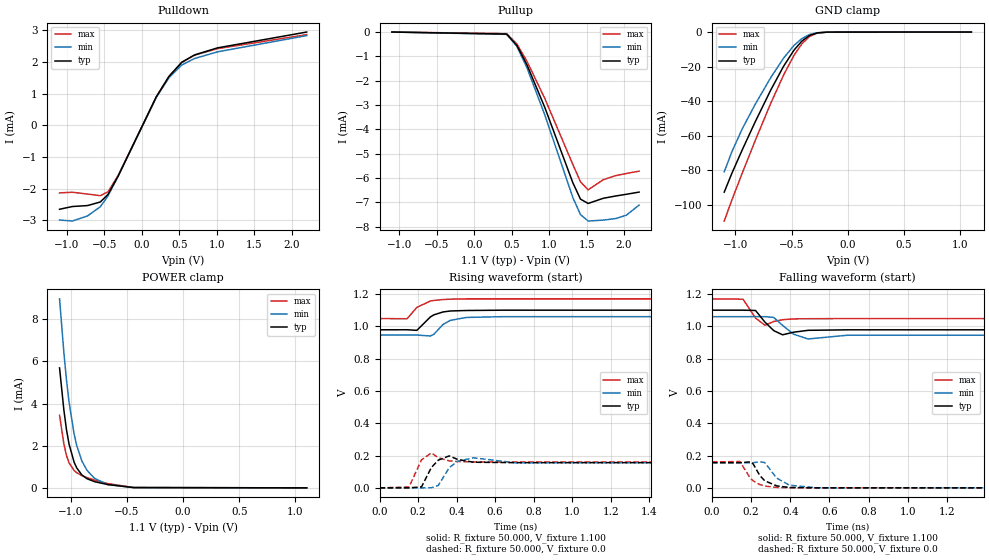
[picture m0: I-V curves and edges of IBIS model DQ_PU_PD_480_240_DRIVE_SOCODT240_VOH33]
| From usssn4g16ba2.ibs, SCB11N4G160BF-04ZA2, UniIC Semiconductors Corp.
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|   Model DQ_PU_PD_480_240_DRIVE_SOCODT240_VOH33
[Model] DQ_PU_PD_480_240_DRIVE_SOCODT240_VOH33
Model_type I/O
Polarity   Inverting
Vinl =  98.000mV
Vinh =  0.268V
Vmeas =  0.183V
Rref =  50.000
Vref =  0.183V
C_comp   1.020pF   1.010pF   1.030pF
[Model Spec]
Vinh   0.268V   0.262V   0.280V
Vinl   98.000mV   92.000mV   0.110V
Vmeas   0.183V   0.177V   0.195V
Vref   0.183V   0.177V   0.195V
Rref   50.000   NA   NA
[Temperature Range]   25.000   0.105k   -40.000
[Voltage Range]   1.100V   1.060V   1.170V
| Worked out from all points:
|   slope of the pulldown table from 0 to 0.165 V, typ, clamps not added: 211 ohm
|   GND clamp passes 1 mA (typ) near -0.30 V on its own axis
|   POWER clamp passes 1 mA (typ) near -0.95 V on its own axis
|   rising waveform, R_fixture 50.000, V_fixture 1.100: 20-80 % time 70ps typ, 72.2ps min, 68.1ps max; typ from 0.978 V to 1.1 V
|   rising waveform, R_fixture 50.000, V_fixture 0.0: 20-80 % time 37ps typ, 47ps min, 30.1ps max; typ from 0 V to 0.156 V
|   falling waveform, R_fixture 50.000, V_fixture 1.100: 20-80 % time 45.4ps typ, 59.1ps min, 35.5ps max; typ from 1.1 V to 0.978 V
|   falling waveform, R_fixture 50.000, V_fixture 0.0: 20-80 % time 63.3ps typ, 70.7ps min, 60.6ps max; typ from 0.156 V to 0 V
[Pulldown]
|Voltage   I(typ)   I(min)   I(max)
-1.1V     -2.652mA   -2.992mA   -2.134mA
-930mV    -2.565mA   -3.023mA   -2.114mA
-726mV    -2.535mA   -2.862mA   -2.171mA
-556mV    -2.422mA   -2.572mA   -2.223mA
-454mV    -2.185mA   -2.234mA   -2.101mA
-318mV    -1.604mA   -1.606mA   -1.589mA
192mV     900.6uA    884.3uA    903.8uA
362mV     1.549mA    1.507mA    1.549mA
532mV     1.993mA    1.907mA    1.988mA
702mV     2.225mA    2.111mA    2.215mA
1.008V    2.447mA    2.322mA    2.422mA
2.2V      2.948mA    2.835mA    2.866mA
[Pullup]
|Voltage   I(typ)   I(min)   I(max)
-1.1V     500pA      5.412nA    0A
432mV     -84.42uA   -95.4uA    -65.89uA
568mV     -546.4uA   -585.3uA   -487.9uA
704mV     -1.354mA   -1.473mA   -1.207mA
942mV     -3.104mA   -3.412mA   -2.737mA
1.316V    -6.198mA   -6.807mA   -5.446mA
1.418V    -6.872mA   -7.507mA   -6.161mA
1.52V     -7.049mA   -7.771mA   -6.489mA
1.724V    -6.835mA   -7.734mA   -6.072mA
1.894V    -6.739mA   -7.667mA   -5.9mA
2.03V     -6.672mA   -7.532mA   -5.816mA
2.2V      -6.582mA   -7.117mA   -5.721mA
[GND_clamp]
|Voltage   I(typ)   I(min)   I(max)
-1.1V     -92.78mA   -81.05mA   -109.5mA
-1.031V   -81.73mA   -69.22mA   -97.17mA
-939mV    -68.18mA   -56.02mA   -81.64mA
-824mV    -52mA      -41.83mA   -62.83mA
-686mV    -33.62mA   -26.41mA   -41.32mA
-571mV    -19.76mA   -15.06mA   -24.85mA
-479mV    -10.5mA    -7.76mA    -13.5mA
-410mV    -5.313mA   -3.84mA    -6.916mA
-341mV    -2.007mA   -1.45mA    -2.59mA
-272mV    -506.9uA   -403.5uA   -609.8uA
-180mV    -45.65uA   -51.35uA   -43.55uA
1.1V      0A         0A         0A
[POWER_clamp]
|Voltage   I(typ)   I(min)   I(max)
-1.1V     5.691mA    8.967mA    3.44mA
-1.062V   3.709mA    6.444mA    2.092mA
-1.039V   2.781mA    5.152mA    1.546mA
-1.016V   2.086mA    4.085mA    1.193mA
-970mV    1.21mA     2.539mA    818.5uA
-947mV    943.7uA    2.005mA    716.7uA
-901mV    610.1uA    1.27mA     581.3uA
-855mV    430.7uA    824.1uA    484.6uA
-786mV    289.9uA    439.4uA    366uA
-671mV    155.9uA    155.9uA    203.6uA
-441mV    13.2uA     12.79uA    15.03uA
1.1V      0A         0A         0A
[Ramp]
| variable   typ   min   max
dV/dt_r   93.599m/37.161p   92.823m/47.081p   96.210m/30.054p
dV/dt_f   72.903m/45.492p   68.572m/59.110p   73.268m/35.541p
R_load = 50.000
[Rising Waveform]
R_fixture= 50.000
V_fixture= 1.100
V_fixture_min= 1.060
V_fixture_max= 1.170
|time   V(typ)   V(min)   V(max)
0s        978.5mV    945.7mV    1.048V
143ps     978.8mV    945.9mV    1.047V
194ps     975.1mV    946mV      1.117V
264ps     1.058V     940.1mV    1.157V
282ps     1.071V     950.5mV    1.16V
330ps     1.089V     1.012V     1.166V
368ps     1.095V     1.037V     1.168V
451ps     1.098V     1.055V     1.17V
646ps     1.1V       1.06V      1.17V
3ns       1.1V       1.06V      1.17V
[Rising Waveform]
R_fixture= 50.000
V_fixture= 0.0
V_fixture_min= 0.0
V_fixture_max= 0.0
|time   V(typ)   V(min)   V(max)
0s        5.235uV    19.06uV    1.24uV
153ps     -29.13uV   44.17uV    4.946mV
218ps     6.141mV    -7.246uV   173.5mV
269ps     125.5mV    451.2uV    216.1mV
305ps     171.5mV    14.89mV    186.4mV
362ps     197.8mV    124.6mV    167mV
405ps     176.1mV    164.3mV    162.7mV
488ps     158.6mV    186mV      160.7mV
706ps     156mV      155mV      160.3mV
3ns       156mV      154.7mV    160.3mV
[Falling Waveform]
R_fixture= 50.000
V_fixture= 1.100
V_fixture_min= 1.060
V_fixture_max= 1.170
|time   V(typ)   V(min)   V(max)
0s        1.1V       1.06V      1.17V
159ps     1.1V       1.06V      1.168V
223ps     1.098V     1.06V      1.051V
271ps     1.026V     1.06V      1.007V
316ps     973.3mV    1.055V     1.03V
361ps     947.5mV    1.006V     1.041V
417ps     963.5mV    951.4mV    1.046V
491ps     975.3mV    921.7mV    1.047V
694ps     978.4mV    945.1mV    1.048V
3ns       978.5mV    945.7mV    1.048V
[Falling Waveform]
R_fixture= 50.000
V_fixture= 0.0
V_fixture_min= 0.0
V_fixture_max= 0.0
|time   V(typ)   V(min)   V(max)
0s        156mV      154.7mV    160.3mV
143ps     155.8mV    154.5mV    163mV
196ps     160.8mV    154.6mV    60.66mV
211ps     147.8mV    155.8mV    43.18mV
245ps     75.97mV    161.5mV    20.16mV
270ps     43.85mV    156.5mV    10.98mV
331ps     12.16mV    60.34mV    2.493mV
396ps     2.224mV    16.43mV    620.7uV
535ps     135.6uV    482.5uV    32.23uV
3ns       5.266uV    19.16uV    -96.73nV
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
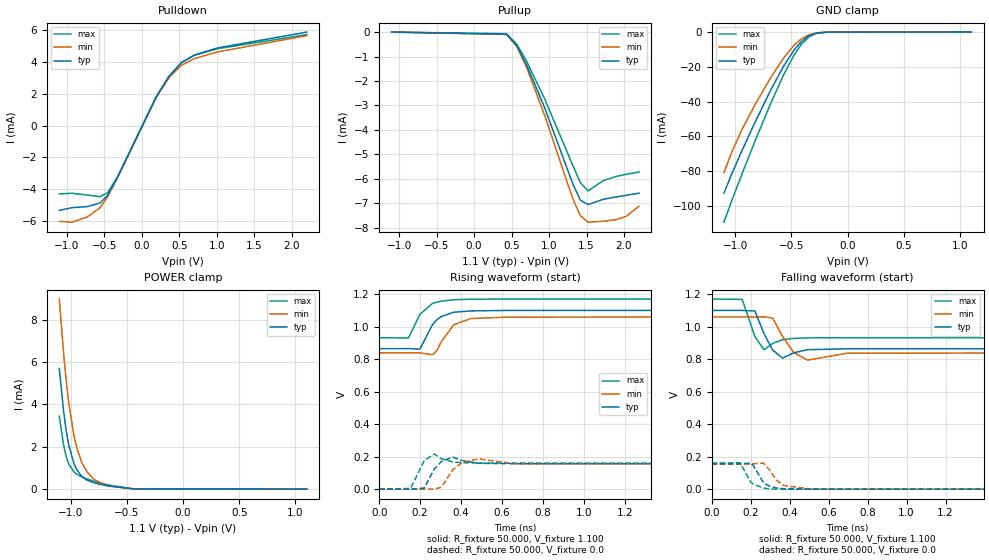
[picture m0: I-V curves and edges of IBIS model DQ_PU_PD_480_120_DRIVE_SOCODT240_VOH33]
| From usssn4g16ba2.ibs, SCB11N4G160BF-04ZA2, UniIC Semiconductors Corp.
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|   Model DQ_PU_PD_480_120_DRIVE_SOCODT240_VOH33
[Model] DQ_PU_PD_480_120_DRIVE_SOCODT240_VOH33
Model_type I/O
Polarity   Inverting
Vinl =  98.000mV
Vinh =  0.268V
Vmeas =  0.183V
Rref =  50.000
Vref =  0.183V
C_comp   1.020pF   1.010pF   1.030pF
[Model Spec]
Vinh   0.268V   0.262V   0.280V
Vinl   98.000mV   92.000mV   0.110V
Vmeas   0.183V   0.177V   0.195V
Vref   0.183V   0.177V   0.195V
Rref   50.000   NA   NA
[Temperature Range]   25.000   0.105k   -40.000
[Voltage Range]   1.100V   1.060V   1.170V
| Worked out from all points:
|   slope of the pulldown table from 0 to 0.165 V, typ, clamps not added: 105 ohm
|   GND clamp passes 1 mA (typ) near -0.30 V on its own axis
|   POWER clamp passes 1 mA (typ) near -0.95 V on its own axis
|   rising waveform, R_fixture 50.000, V_fixture 1.100: 20-80 % time 70.9ps typ, 74ps min, 68.7ps max; typ from 0.864 V to 1.1 V
|   rising waveform, R_fixture 50.000, V_fixture 0.0: 20-80 % time 36.7ps typ, 46.4ps min, 29.9ps max; typ from 0 V to 0.156 V
|   falling waveform, R_fixture 50.000, V_fixture 1.100: 20-80 % time 44.8ps typ, 58.1ps min, 35.2ps max; typ from 1.1 V to 0.864 V
|   falling waveform, R_fixture 50.000, V_fixture 0.0: 20-80 % time 52.5ps typ, 62.1ps min, 49.6ps max; typ from 0.156 V to 0 V
[Pulldown]
|Voltage   I(typ)   I(min)   I(max)
-1.1V     -5.34mA    -6.026mA   -4.302mA
-930mV    -5.164mA   -6.082mA   -4.26mA
-726mV    -5.101mA   -5.754mA   -4.373mA
-556mV    -4.87mA    -5.165mA   -4.475mA
-454mV    -4.386mA   -4.479mA   -4.222mA
-318mV    -3.209mA   -3.211mA   -3.18mA
192mV     1.799mA    1.766mA    1.806mA
362mV     3.096mA    3.011mA    3.096mA
532mV     3.983mA    3.811mA    3.973mA
702mV     4.448mA    4.219mA    4.427mA
1.008V    4.891mA    4.64mA     4.842mA
2.2V      5.891mA    5.665mA    5.73mA
[Pullup]
|Voltage   I(typ)   I(min)   I(max)
-1.1V     500pA      5.412nA    0A
432mV     -84.42uA   -95.4uA    -65.89uA
568mV     -546.4uA   -585.3uA   -487.9uA
704mV     -1.354mA   -1.473mA   -1.207mA
942mV     -3.104mA   -3.412mA   -2.737mA
1.316V    -6.198mA   -6.807mA   -5.446mA
1.418V    -6.872mA   -7.507mA   -6.161mA
1.52V     -7.049mA   -7.771mA   -6.489mA
1.724V    -6.835mA   -7.734mA   -6.072mA
1.894V    -6.739mA   -7.667mA   -5.9mA
2.03V     -6.672mA   -7.532mA   -5.816mA
2.2V      -6.582mA   -7.117mA   -5.721mA
[GND_clamp]
|Voltage   I(typ)   I(min)   I(max)
-1.1V     -92.78mA   -81.05mA   -109.5mA
-1.031V   -81.73mA   -69.22mA   -97.17mA
-939mV    -68.18mA   -56.02mA   -81.64mA
-824mV    -52mA      -41.83mA   -62.83mA
-686mV    -33.62mA   -26.41mA   -41.32mA
-571mV    -19.76mA   -15.06mA   -24.85mA
-479mV    -10.5mA    -7.76mA    -13.5mA
-410mV    -5.313mA   -3.84mA    -6.916mA
-341mV    -2.007mA   -1.45mA    -2.59mA
-272mV    -506.9uA   -403.5uA   -609.8uA
-180mV    -45.65uA   -51.35uA   -43.55uA
1.1V      0A         0A         0A
[POWER_clamp]
|Voltage   I(typ)   I(min)   I(max)
-1.1V     5.691mA    8.967mA    3.44mA
-1.062V   3.709mA    6.444mA    2.092mA
-1.039V   2.781mA    5.152mA    1.546mA
-1.016V   2.086mA    4.085mA    1.193mA
-970mV    1.21mA     2.539mA    818.5uA
-947mV    943.7uA    2.005mA    716.7uA
-901mV    610.1uA    1.27mA     581.3uA
-855mV    430.7uA    824.1uA    484.6uA
-786mV    289.9uA    439.4uA    366uA
-671mV    155.9uA    155.9uA    203.6uA
-441mV    13.2uA     12.79uA    15.03uA
1.1V      0A         0A         0A
[Ramp]
| variable   typ   min   max
dV/dt_r   93.600m/36.700p   92.825m/46.456p   96.210m/29.924p
dV/dt_f   0.141/44.746p   0.133/58.103p   0.143/35.264p
R_load = 50.000
[Rising Waveform]
R_fixture= 50.000
V_fixture= 1.100
V_fixture_min= 1.060
V_fixture_max= 1.170
|time   V(typ)   V(min)   V(max)
0s        864.4mV    838.5mV    932.1mV
143ps     864.9mV    838.7mV    930.5mV
199ps     862mV      838.6mV    1.076V
260ps     1.012V     827.4mV    1.143V
281ps     1.042V     851mV      1.151V
302ps     1.062V     904.9mV    1.157V
364ps     1.089V     1.012V     1.166V
447ps     1.097V     1.05V      1.169V
627ps     1.1V       1.059V     1.17V
3ns       1.1V       1.06V      1.17V
[Rising Waveform]
R_fixture= 50.000
V_fixture= 0.0
V_fixture_min= 0.0
V_fixture_max= 0.0
|time   V(typ)   V(min)   V(max)
0s        4.356uV    15.89uV    1.031uV
153ps     73.44uV    34.03uV    3.762mV
220ps     6.132mV    153.6uV    175.7mV
269ps     124mV      -471.6uV   215.9mV
305ps     171.1mV    12.11mV    186.4mV
359ps     197.2mV    118.7mV    167.4mV
406ps     175.5mV    164.5mV    162.7mV
486ps     158.8mV    185.8mV    160.7mV
665ps     156mV      155.4mV    160.4mV
3ns       156mV      154.7mV    160.3mV
[Falling Waveform]
R_fixture= 50.000
V_fixture= 1.100
V_fixture_min= 1.060
V_fixture_max= 1.170
|time   V(typ)   V(min)   V(max)
0s        1.1V       1.06V      1.17V
157ps     1.1V       1.06V      1.168V
222ps     1.097V     1.06V      939.9mV
269ps     957.1mV    1.061V     857.6mV
314ps     855.8mV    1.052V     897.3mV
364ps     806.5mV    940.4mV    919.5mV
421ps     839.3mV    841.3mV    928.1mV
492ps     858.3mV    794.1mV    931.2mV
698ps     864.3mV    837.3mV    932.1mV
3ns       864.4mV    838.5mV    932.1mV
[Falling Waveform]
R_fixture= 50.000
V_fixture= 0.0
V_fixture_min= 0.0
V_fixture_max= 0.0
|time   V(typ)   V(min)   V(max)
0s        156mV      154.7mV    160.3mV
146ps     155.8mV    154.5mV    162.6mV
200ps     160.4mV    154.8mV    45.79mV
215ps     143.5mV    156.2mV    30.14mV
266ps     39.97mV    160mV      6.797mV
297ps     18.06mV    119.2mV    975.6uV
331ps     7.774mV    57.5mV     415.2uV
369ps     2.426mV    22.99mV    167.1uV
515ps     -10.66uV   -75.85uV   5.185uV
3ns       4.126uV    15.81uV    991.6nV
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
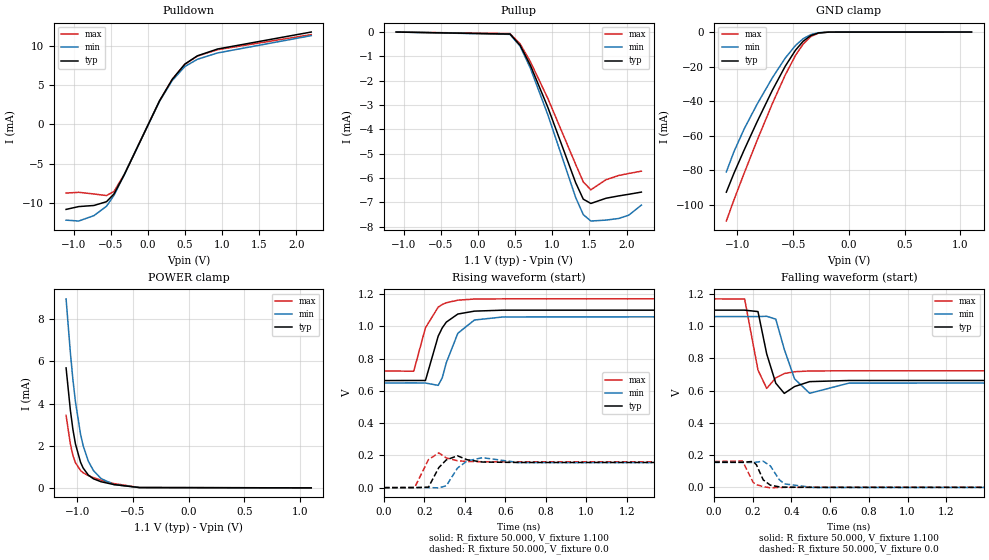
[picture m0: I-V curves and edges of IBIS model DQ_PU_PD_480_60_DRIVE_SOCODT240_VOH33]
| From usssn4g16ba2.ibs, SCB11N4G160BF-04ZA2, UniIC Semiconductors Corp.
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|   Model DQ_PU_PD_480_60_DRIVE_SOCODT240_VOH33
[Model] DQ_PU_PD_480_60_DRIVE_SOCODT240_VOH33
Model_type I/O
Polarity   Inverting
Vinl =  98.000mV
Vinh =  0.268V
Vmeas =  0.183V
Rref =  50.000
Vref =  0.183V
C_comp   1.020pF   1.010pF   1.030pF
[Model Spec]
Vinh   0.268V   0.262V   0.280V
Vinl   98.000mV   92.000mV   0.110V
Vmeas   0.183V   0.177V   0.195V
Vref   0.183V   0.177V   0.195V
Rref   50.000   NA   NA
[Temperature Range]   25.000   0.105k   -40.000
[Voltage Range]   1.100V   1.060V   1.170V
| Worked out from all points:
|   slope of the pulldown table from 0 to 0.165 V, typ, clamps not added: 52.7 ohm
|   GND clamp passes 1 mA (typ) near -0.30 V on its own axis
|   POWER clamp passes 1 mA (typ) near -0.95 V on its own axis
|   rising waveform, R_fixture 50.000, V_fixture 1.100: 20-80 % time 74.3ps typ, 78.1ps min, 71.5ps max; typ from 0.663 V to 1.1 V
|   rising waveform, R_fixture 50.000, V_fixture 0.0: 20-80 % time 36.5ps typ, 45.9ps min, 30ps max; typ from 0 V to 0.156 V
|   falling waveform, R_fixture 50.000, V_fixture 1.100: 20-80 % time 43.7ps typ, 56.9ps min, 35ps max; typ from 1.1 V to 0.663 V
|   falling waveform, R_fixture 50.000, V_fixture 0.0: 20-80 % time 40.7ps typ, 54.3ps min, 37.6ps max; typ from 0.156 V to 0 V
[Pulldown]
|Voltage   I(typ)   I(min)   I(max)
-1.1V     -10.83mA   -12.2mA    -8.746mA
-930mV    -10.47mA   -12.31mA   -8.649mA
-726mV    -10.33mA   -11.63mA   -8.863mA
-556mV    -9.849mA   -10.43mA   -9.063mA
-454mV    -8.849mA   -9.016mA   -8.534mA
-318mV    -6.436mA   -6.433mA   -6.383mA
158mV     3.005mA    2.954mA    3.019mA
328mV     5.729mA    5.586mA    5.734mA
498mV     7.686mA    7.379mA    7.672mA
668mV     8.751mA    8.306mA    8.715mA
940mV     9.618mA    9.116mA    9.532mA
2.2V      11.78mA    11.32mA    11.45mA
[Pullup]
|Voltage   I(typ)   I(min)   I(max)
-1.1V     500pA      5.412nA    0A
432mV     -84.42uA   -95.4uA    -65.89uA
568mV     -546.4uA   -585.3uA   -487.9uA
704mV     -1.354mA   -1.473mA   -1.207mA
942mV     -3.104mA   -3.412mA   -2.737mA
1.316V    -6.198mA   -6.807mA   -5.446mA
1.418V    -6.872mA   -7.507mA   -6.161mA
1.52V     -7.049mA   -7.771mA   -6.489mA
1.724V    -6.835mA   -7.734mA   -6.072mA
1.894V    -6.739mA   -7.667mA   -5.9mA
2.03V     -6.672mA   -7.532mA   -5.816mA
2.2V      -6.582mA   -7.117mA   -5.721mA
[GND_clamp]
|Voltage   I(typ)   I(min)   I(max)
-1.1V     -92.78mA   -81.05mA   -109.5mA
-1.031V   -81.73mA   -69.22mA   -97.17mA
-939mV    -68.18mA   -56.02mA   -81.64mA
-824mV    -52mA      -41.83mA   -62.83mA
-686mV    -33.62mA   -26.41mA   -41.32mA
-571mV    -19.76mA   -15.06mA   -24.85mA
-479mV    -10.5mA    -7.76mA    -13.5mA
-410mV    -5.313mA   -3.84mA    -6.916mA
-341mV    -2.007mA   -1.45mA    -2.59mA
-272mV    -506.9uA   -403.5uA   -609.8uA
-180mV    -45.65uA   -51.35uA   -43.55uA
1.1V      0A         0A         0A
[POWER_clamp]
|Voltage   I(typ)   I(min)   I(max)
-1.1V     5.691mA    8.967mA    3.44mA
-1.062V   3.709mA    6.444mA    2.092mA
-1.039V   2.781mA    5.152mA    1.546mA
-1.016V   2.086mA    4.085mA    1.193mA
-970mV    1.21mA     2.539mA    818.5uA
-947mV    943.7uA    2.005mA    716.7uA
-901mV    610.1uA    1.27mA     581.3uA
-855mV    430.7uA    824.1uA    484.6uA
-786mV    289.9uA    439.4uA    366uA
-671mV    155.9uA    155.9uA    203.6uA
-441mV    13.2uA     12.79uA    15.03uA
1.1V      0A         0A         0A
[Ramp]
| variable   typ   min   max
dV/dt_r   93.600m/36.486p   92.827m/45.929p   96.210m/30.147p
dV/dt_f   0.262/43.724p   0.247/56.957p   0.268/35.010p
R_load = 50.000
[Rising Waveform]
R_fixture= 50.000
V_fixture= 1.100
V_fixture_min= 1.060
V_fixture_max= 1.170
|time   V(typ)   V(min)   V(max)
0s        663.5mV    648.6mV    723.5mV
147ps     664.4mV    649.2mV    721.5mV
205ps     664.1mV    648.5mV    990.6mV
268ps     939mV      633.9mV    1.119V
288ps     990.3mV    681.1mV    1.135V
308ps     1.026V     774.6mV    1.146V
365ps     1.076V     956.8mV    1.162V
447ps     1.094V     1.039V     1.169V
589ps     1.1V       1.058V     1.17V
3ns       1.1V       1.06V      1.17V
[Rising Waveform]
R_fixture= 50.000
V_fixture= 0.0
V_fixture_min= 0.0
V_fixture_max= 0.0
|time   V(typ)   V(min)   V(max)
0s        3.262uV    11.92uV    771.1nV
152ps     171.2uV    18.36uV    1.764mV
220ps     3.07mV     366.5uV    173.9mV
271ps     124.4mV    -1.252mV   215.4mV
308ps     172mV      11.43mV    184.3mV
363ps     197.5mV    121mV      166.8mV
411ps     172.8mV    165.8mV    162.4mV
487ps     158.7mV    185.7mV    160.7mV
666ps     156mV      155.3mV    160.4mV
3ns       156mV      154.7mV    160.3mV
[Falling Waveform]
R_fixture= 50.000
V_fixture= 1.100
V_fixture_min= 1.060
V_fixture_max= 1.170
|time   V(typ)   V(min)   V(max)
0s        1.1V       1.06V      1.17V
158ps     1.1V       1.06V      1.169V
227ps     1.091V     1.06V      728.1mV
272ps     828.5mV    1.062V     614mV
319ps     646.5mV    1.044V     679.6mV
363ps     583.2mV    856.5mV    706.4mV
416ps     625.7mV    673.5mV    717.8mV
494ps     656.3mV    583.9mV    722.4mV
697ps     663.3mV    647mV      723.5mV
3ns       663.5mV    648.6mV    723.5mV
[Falling Waveform]
R_fixture= 50.000
V_fixture= 0.0
V_fixture_min= 0.0
V_fixture_max= 0.0
|time   V(typ)   V(min)   V(max)
0s        156mV      154.7mV    160.3mV
147ps     155.8mV    154.5mV    163.6mV
202ps     160.8mV    154.8mV    30.88mV
219ps     139.8mV    156.5mV    16.32mV
254ps     46.57mV    162.2mV    4.596mV
291ps     13.33mV    133.1mV    -3.105mV
337ps     3.193mV    47.69mV    -764.7uV
363ps     1.019mV    21.51mV    -301.9uV
513ps     -70.22uV   -1.085mV   -892nV
3ns       3.16uV     11.89uV    560.6nV
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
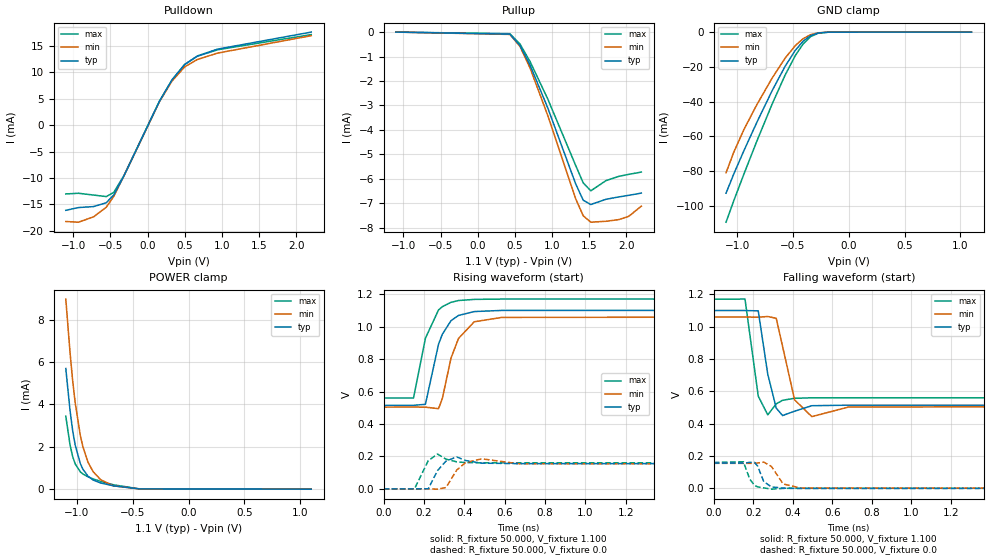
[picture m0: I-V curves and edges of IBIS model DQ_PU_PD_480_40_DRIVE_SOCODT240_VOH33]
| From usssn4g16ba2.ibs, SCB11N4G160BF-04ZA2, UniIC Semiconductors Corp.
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|   Model DQ_PU_PD_480_40_DRIVE_SOCODT240_VOH33
[Model] DQ_PU_PD_480_40_DRIVE_SOCODT240_VOH33
Model_type I/O
Polarity   Inverting
Vinl =  98.000mV
Vinh =  0.268V
Vmeas =  0.183V
Rref =  50.000
Vref =  0.183V
C_comp   1.020pF   1.010pF   1.030pF
[Model Spec]
Vinh   0.268V   0.262V   0.280V
Vinl   98.000mV   92.000mV   0.110V
Vmeas   0.183V   0.177V   0.195V
Vref   0.183V   0.177V   0.195V
Rref   50.000   NA   NA
[Temperature Range]   25.000   0.105k   -40.000
[Voltage Range]   1.100V   1.060V   1.170V
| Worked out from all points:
|   slope of the pulldown table from 0 to 0.165 V, typ, clamps not added: 35.3 ohm
|   GND clamp passes 1 mA (typ) near -0.30 V on its own axis
|   POWER clamp passes 1 mA (typ) near -0.95 V on its own axis
|   rising waveform, R_fixture 50.000, V_fixture 1.100: 20-80 % time 76.4ps typ, 80.2ps min, 73.5ps max; typ from 0.514 V to 1.1 V
|   rising waveform, R_fixture 50.000, V_fixture 0.0: 20-80 % time 36.1ps typ, 45.5ps min, 29.7ps max; typ from 0 V to 0.156 V
|   falling waveform, R_fixture 50.000, V_fixture 1.100: 20-80 % time 40.5ps typ, 53.3ps min, 33.2ps max; typ from 1.1 V to 0.514 V
|   falling waveform, R_fixture 50.000, V_fixture 0.0: 20-80 % time 33.3ps typ, 48.3ps min, 30.2ps max; typ from 0.156 V to 0 V
[Pulldown]
|Voltage   I(typ)   I(min)   I(max)
-1.1V     -16.13mA   -18.25mA   -13.03mA
-930mV    -15.61mA   -18.38mA   -12.9mA
-726mV    -15.42mA   -17.36mA   -13.24mA
-556mV    -14.7mA    -15.55mA   -13.53mA
-454mV    -13.2mA    -13.45mA   -12.73mA
-318mV    -9.609mA   -9.606mA   -9.529mA
158mV     4.492mA    4.415mA    4.512mA
328mV     8.568mA    8.352mA    8.576mA
498mV     11.5mA     11.04mA    11.48mA
668mV     13.1mA     12.43mA    13.05mA
940mV     14.4mA     13.65mA    14.28mA
2.2V      17.63mA    16.95mA    17.16mA
[Pullup]
|Voltage   I(typ)   I(min)   I(max)
-1.1V     500pA      5.412nA    0A
432mV     -84.42uA   -95.4uA    -65.89uA
568mV     -546.4uA   -585.3uA   -487.9uA
704mV     -1.354mA   -1.473mA   -1.207mA
942mV     -3.104mA   -3.412mA   -2.737mA
1.316V    -6.198mA   -6.807mA   -5.446mA
1.418V    -6.872mA   -7.507mA   -6.161mA
1.52V     -7.049mA   -7.771mA   -6.489mA
1.724V    -6.835mA   -7.734mA   -6.072mA
1.894V    -6.739mA   -7.667mA   -5.9mA
2.03V     -6.672mA   -7.532mA   -5.816mA
2.2V      -6.582mA   -7.117mA   -5.721mA
[GND_clamp]
|Voltage   I(typ)   I(min)   I(max)
-1.1V     -92.78mA   -81.05mA   -109.5mA
-1.031V   -81.73mA   -69.22mA   -97.17mA
-939mV    -68.18mA   -56.02mA   -81.64mA
-824mV    -52mA      -41.83mA   -62.83mA
-686mV    -33.62mA   -26.41mA   -41.32mA
-571mV    -19.76mA   -15.06mA   -24.85mA
-479mV    -10.5mA    -7.76mA    -13.5mA
-410mV    -5.313mA   -3.84mA    -6.916mA
-341mV    -2.007mA   -1.45mA    -2.59mA
-272mV    -506.9uA   -403.5uA   -609.8uA
-180mV    -45.65uA   -51.35uA   -43.55uA
1.1V      0A         0A         0A
[POWER_clamp]
|Voltage   I(typ)   I(min)   I(max)
-1.1V     5.691mA    8.967mA    3.44mA
-1.062V   3.709mA    6.444mA    2.092mA
-1.039V   2.781mA    5.152mA    1.546mA
-1.016V   2.086mA    4.085mA    1.193mA
-970mV    1.21mA     2.539mA    818.5uA
-947mV    943.7uA    2.005mA    716.7uA
-901mV    610.1uA    1.27mA     581.3uA
-855mV    430.7uA    824.1uA    484.6uA
-786mV    289.9uA    439.4uA    366uA
-671mV    155.9uA    155.9uA    203.6uA
-441mV    13.2uA     12.79uA    15.03uA
1.1V      0A         0A         0A
[Ramp]
| variable   typ   min   max
dV/dt_r   93.601m/36.231p   92.829m/45.503p   96.210m/29.958p
dV/dt_f   0.351/40.612p   0.333/53.407p   0.366/33.320p
R_load = 50.000
[Rising Waveform]
R_fixture= 50.000
V_fixture= 1.100
V_fixture_min= 1.060
V_fixture_max= 1.170
|time   V(typ)   V(min)   V(max)
0s        514.4mV    504.3mV    560.3mV
148ps     515.3mV    504.9mV    560.5mV
207ps     521.4mV    503.8mV    928.6mV
272ps     892mV      494.7mV    1.103V
291ps     953.4mV    557.8mV    1.123V
334ps     1.037V     807.2mV    1.15V
371ps     1.069V     927.2mV    1.161V
449ps     1.093V     1.03V      1.168V
586ps     1.1V       1.057V     1.17V
3ns       1.1V       1.06V      1.17V
[Rising Waveform]
R_fixture= 50.000
V_fixture= 0.0
V_fixture_min= 0.0
V_fixture_max= 0.0
|time   V(typ)   V(min)   V(max)
0s        2.608uV    9.548uV    616.3nV
153ps     334.6uV    16.89uV    864.6uV
221ps     1.036mV    579.7uV    174mV
267ps     112.8mV    -1.494mV   214.9mV
309ps     171.8mV    8.345mV    183.5mV
362ps     197.2mV    116.2mV    166.9mV
406ps     175.3mV    162.2mV    162.6mV
486ps     158.7mV    185.5mV    160.7mV
669ps     156mV      155.3mV    160.4mV
3ns       156mV      154.7mV    160.3mV
[Falling Waveform]
R_fixture= 50.000
V_fixture= 1.100
V_fixture_min= 1.060
V_fixture_max= 1.170
|time   V(typ)   V(min)   V(max)
0s        1.1V       1.06V      1.17V
158ps     1.1V       1.06V      1.171V
225ps     1.098V     1.059V     570.6mV
273ps     707mV      1.063V     454.5mV
316ps     496.5mV    1.052V     522.3mV
348ps     450.1mV    878.5mV    544.7mV
409ps     477.2mV    547.4mV    557.1mV
496ps     511.1mV    443.5mV    559.9mV
683ps     514.4mV    503.4mV    560.3mV
3ns       514.4mV    504.3mV    560.3mV
[Falling Waveform]
R_fixture= 50.000
V_fixture= 0.0
V_fixture_min= 0.0
V_fixture_max= 0.0
|time   V(typ)   V(min)   V(max)
0s        156mV      154.7mV    160.3mV
150ps     155.8mV    154.5mV    163.8mV
182ps     160.3mV    154.3mV    56.65mV
206ps     160.8mV    155mV      18.33mV
222ps     137.2mV    156.7mV    8.829mV
253ps     40.97mV    162mV      2.487mV
292ps     8.449mV    134.9mV    -5.342mV
351ps     1.215mV    26.97mV    -509.2uV
438ps     -1.186mV   1.839mV    -11.17uV
3ns       2.504uV    9.484uV    347.8nV
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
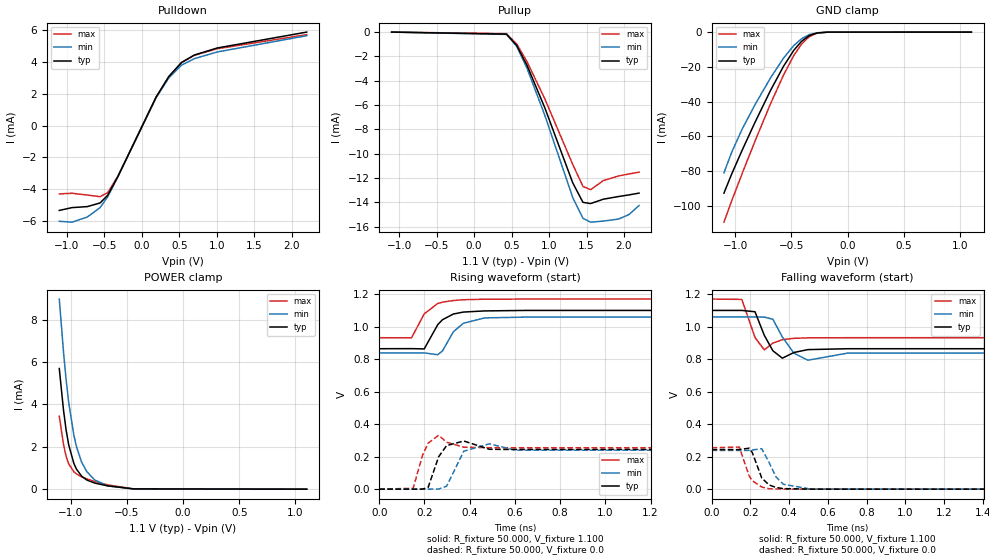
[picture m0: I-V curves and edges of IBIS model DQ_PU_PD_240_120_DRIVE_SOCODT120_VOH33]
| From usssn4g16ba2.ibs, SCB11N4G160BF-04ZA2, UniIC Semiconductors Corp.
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|   Model DQ_PU_PD_240_120_DRIVE_SOCODT120_VOH33
[Model] DQ_PU_PD_240_120_DRIVE_SOCODT120_VOH33
Model_type I/O
Polarity   Inverting
Vinl =  98.000mV
Vinh =  0.268V
Vmeas =  0.183V
Rref =  50.000
Vref =  0.183V
C_comp   1.020pF   1.010pF   1.030pF
[Model Spec]
Vinh   0.268V   0.262V   0.280V
Vinl   98.000mV   92.000mV   0.110V
Vmeas   0.183V   0.177V   0.195V
Vref   0.183V   0.177V   0.195V
Rref   50.000   NA   NA
[Temperature Range]   25.000   0.105k   -40.000
[Voltage Range]   1.100V   1.060V   1.170V
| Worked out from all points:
|   slope of the pulldown table from 0 to 0.165 V, typ, clamps not added: 105 ohm
|   GND clamp passes 1 mA (typ) near -0.30 V on its own axis
|   POWER clamp passes 1 mA (typ) near -0.95 V on its own axis
|   rising waveform, R_fixture 50.000, V_fixture 1.100: 20-80 % time 70.2ps typ, 72.6ps min, 68.3ps max; typ from 0.864 V to 1.1 V
|   rising waveform, R_fixture 50.000, V_fixture 0.0: 20-80 % time 33ps typ, 42.2ps min, 27ps max; typ from 0 V to 0.244 V
|   falling waveform, R_fixture 50.000, V_fixture 1.100: 20-80 % time 45ps typ, 58.6ps min, 35.4ps max; typ from 1.1 V to 0.864 V
|   falling waveform, R_fixture 50.000, V_fixture 0.0: 20-80 % time 52.8ps typ, 63.3ps min, 49.4ps max; typ from 0.244 V to 0 V
[Pulldown]
|Voltage   I(typ)   I(min)   I(max)
-1.1V     -5.34mA    -6.026mA   -4.302mA
-930mV    -5.164mA   -6.082mA   -4.26mA
-726mV    -5.101mA   -5.754mA   -4.373mA
-556mV    -4.87mA    -5.165mA   -4.475mA
-454mV    -4.386mA   -4.479mA   -4.222mA
-318mV    -3.209mA   -3.211mA   -3.18mA
192mV     1.799mA    1.766mA    1.806mA
362mV     3.096mA    3.011mA    3.096mA
532mV     3.983mA    3.811mA    3.973mA
702mV     4.448mA    4.219mA    4.427mA
1.008V    4.891mA    4.64mA     4.842mA
2.2V      5.891mA    5.665mA    5.73mA
[Pullup]
|Voltage   I(typ)   I(min)   I(max)
-1.1V     1nA        10.92nA    0A
432mV     -168.8uA   -190.8uA   -131.8uA
568mV     -1.092mA   -1.17mA    -975.3uA
704mV     -2.706mA   -2.942mA   -2.412mA
942mV     -6.202mA   -6.816mA   -5.469mA
1.316V    -12.39mA   -13.6mA    -10.88mA
1.452V    -13.99mA   -15.3mA    -12.68mA
1.554V    -14.09mA   -15.62mA   -12.95mA
1.724V    -13.73mA   -15.53mA   -12.2mA
1.928V    -13.51mA   -15.36mA   -11.82mA
2.064V    -13.38mA   -15mA      -11.66mA
2.2V      -13.23mA   -14.25mA   -11.51mA
[GND_clamp]
|Voltage   I(typ)   I(min)   I(max)
-1.1V     -92.78mA   -81.05mA   -109.5mA
-1.031V   -81.73mA   -69.22mA   -97.17mA
-939mV    -68.18mA   -56.02mA   -81.64mA
-824mV    -52mA      -41.83mA   -62.83mA
-686mV    -33.62mA   -26.41mA   -41.32mA
-571mV    -19.76mA   -15.06mA   -24.85mA
-479mV    -10.5mA    -7.76mA    -13.5mA
-410mV    -5.313mA   -3.84mA    -6.916mA
-341mV    -2.007mA   -1.45mA    -2.59mA
-272mV    -506.9uA   -403.5uA   -609.8uA
-180mV    -45.65uA   -51.35uA   -43.55uA
1.1V      0A         0A         0A
[POWER_clamp]
|Voltage   I(typ)   I(min)   I(max)
-1.1V     5.691mA    8.967mA    3.44mA
-1.062V   3.709mA    6.444mA    2.092mA
-1.039V   2.781mA    5.152mA    1.546mA
-1.016V   2.086mA    4.085mA    1.193mA
-970mV    1.21mA     2.539mA    818.5uA
-947mV    943.7uA    2.005mA    716.7uA
-901mV    610.1uA    1.27mA     581.3uA
-855mV    430.7uA    824.1uA    484.6uA
-786mV    289.9uA    439.4uA    366uA
-671mV    155.9uA    155.9uA    203.6uA
-441mV    13.2uA     12.79uA    15.03uA
1.1V      0A         0A         0A
[Ramp]
| variable   typ   min   max
dV/dt_r   0.146/33.230p   0.143/42.378p   0.153/27.125p
dV/dt_f   0.141/45.073p   0.133/58.679p   0.143/35.492p
R_load = 50.000
[Rising Waveform]
R_fixture= 50.000
V_fixture= 1.100
V_fixture_min= 1.060
V_fixture_max= 1.170
|time   V(typ)   V(min)   V(max)
0s        864.4mV    838.5mV    932.1mV
143ps     864.9mV    838.8mV    931.7mV
199ps     863.2mV    838.5mV    1.079V
259ps     1.013V     827.6mV    1.143V
280ps     1.043V     851.3mV    1.151V
328ps     1.078V     968.8mV    1.161V
372ps     1.09V      1.021V     1.166V
466ps     1.097V     1.054V     1.169V
647ps     1.1V       1.059V     1.17V
3ns       1.1V       1.06V      1.17V
[Rising Waveform]
R_fixture= 50.000
V_fixture= 0.0
V_fixture_min= 0.0
V_fixture_max= 0.0
|time   V(typ)   V(min)   V(max)
0s        4.356uV    15.89uV    1.031uV
150ps     -32.14uV   44.93uV    5.218mV
191ps     430uV      10.8uV     206.9mV
216ps     9.823mV    -98.92nV   282.9mV
263ps     200mV      554.6uV    331.7mV
298ps     268.1mV    18.44mV    289mV
374ps     296.4mV    233.5mV    258.3mV
487ps     245.4mV    279mV      255.2mV
602ps     244mV      239.8mV    255mV
3ns       243.9mV    238.7mV    255mV
[Falling Waveform]
R_fixture= 50.000
V_fixture= 1.100
V_fixture_min= 1.060
V_fixture_max= 1.170
|time   V(typ)   V(min)   V(max)
0s        1.1V       1.06V      1.17V
156ps     1.1V       1.06V      1.168V
224ps     1.092V     1.06V      933.6mV
272ps     946.8mV    1.059V     857.2mV
316ps     852.3mV    1.046V     898.7mV
365ps     806.1mV    936.7mV    919.8mV
425ps     841.3mV    836.6mV    928.4mV
497ps     858.9mV    793.6mV    931.2mV
702ps     864.3mV    837.4mV    932.1mV
3ns       864.4mV    838.5mV    932.1mV
[Falling Waveform]
R_fixture= 50.000
V_fixture= 0.0
V_fixture_min= 0.0
V_fixture_max= 0.0
|time   V(typ)   V(min)   V(max)
0s        243.9mV    238.7mV    255mV
143ps     243.6mV    238.4mV    259.1mV
194ps     252.3mV    238.7mV    81.09mV
210ps     225.5mV    241.2mV    51.95mV
259ps     68.39mV    249.2mV    13.18mV
297ps     25.63mV    163.4mV    2.571mV
332ps     10.7mV     75.51mV    1.061mV
370ps     3.498mV    30.18mV    410.7uV
511ps     30.71uV    455.5uV    11.99uV
3ns       2.675uV    15.8uV     -504.3nV
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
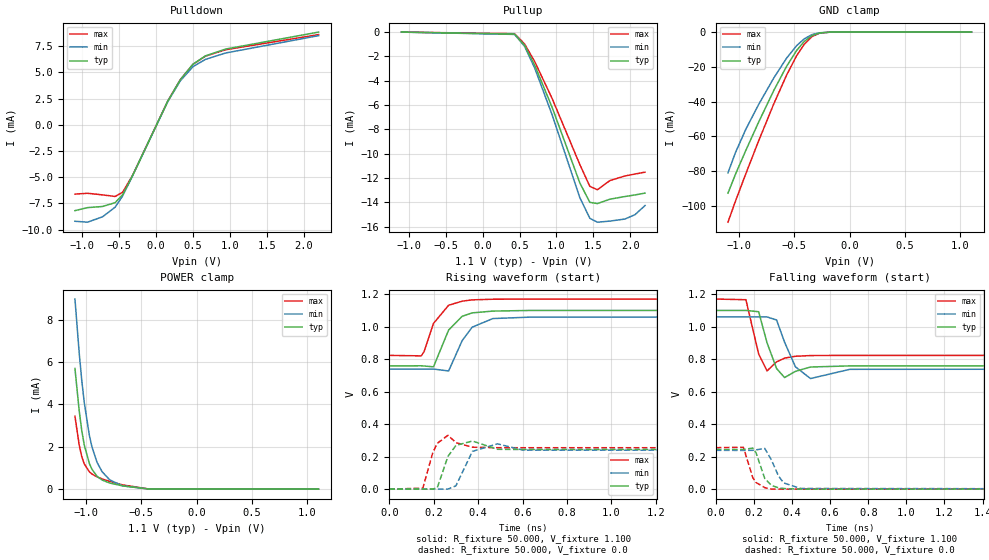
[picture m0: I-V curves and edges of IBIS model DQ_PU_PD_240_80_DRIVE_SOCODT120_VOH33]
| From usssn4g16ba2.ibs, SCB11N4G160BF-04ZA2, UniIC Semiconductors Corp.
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|   Model DQ_PU_PD_240_80_DRIVE_SOCODT120_VOH33
[Model] DQ_PU_PD_240_80_DRIVE_SOCODT120_VOH33
Model_type I/O
Polarity   Inverting
Vinl =  98.000mV
Vinh =  0.268V
Vmeas =  0.183V
Rref =  50.000
Vref =  0.183V
C_comp   1.020pF   1.010pF   1.030pF
[Model Spec]
Vinh   0.268V   0.262V   0.280V
Vinl   98.000mV   92.000mV   0.110V
Vmeas   0.183V   0.177V   0.195V
Vref   0.183V   0.177V   0.195V
Rref   50.000   NA   NA
[Temperature Range]   25.000   0.105k   -40.000
[Voltage Range]   1.100V   1.060V   1.170V
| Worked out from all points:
|   slope of the pulldown table from 0 to 0.165 V, typ, clamps not added: 70.2 ohm
|   GND clamp passes 1 mA (typ) near -0.30 V on its own axis
|   POWER clamp passes 1 mA (typ) near -0.95 V on its own axis
|   rising waveform, R_fixture 50.000, V_fixture 1.100: 20-80 % time 72.4ps typ, 75.5ps min, 69.9ps max; typ from 0.759 V to 1.1 V
|   rising waveform, R_fixture 50.000, V_fixture 0.0: 20-80 % time 33.1ps typ, 42.1ps min, 27.2ps max; typ from 0 V to 0.244 V
|   falling waveform, R_fixture 50.000, V_fixture 1.100: 20-80 % time 44.7ps typ, 58.2ps min, 35.5ps max; typ from 1.1 V to 0.759 V
|   falling waveform, R_fixture 50.000, V_fixture 0.0: 20-80 % time 46.8ps typ, 59.9ps min, 42.7ps max; typ from 0.244 V to 0 V
[Pulldown]
|Voltage   I(typ)   I(min)   I(max)
-1.1V     -8.193mA   -9.206mA   -6.618mA
-930mV    -7.906mA   -9.295mA   -6.537mA
-726mV    -7.797mA   -8.78mA    -6.691mA
-556mV    -7.432mA   -7.863mA   -6.841mA
-454mV    -6.673mA   -6.794mA   -6.44mA
-318mV    -4.841mA   -4.838mA   -4.804mA
158mV     2.257mA    2.219mA    2.267mA
328mV     4.302mA    4.194mA    4.305mA
498mV     5.77mA     5.539mA    5.759mA
668mV     6.567mA    6.233mA    6.54mA
940mV     7.217mA    6.841mA    7.152mA
2.2V      8.836mA    8.496mA    8.595mA
[Pullup]
|Voltage   I(typ)   I(min)   I(max)
-1.1V     1nA        10.92nA    0A
432mV     -168.8uA   -190.8uA   -131.8uA
568mV     -1.092mA   -1.17mA    -975.3uA
704mV     -2.706mA   -2.942mA   -2.412mA
942mV     -6.202mA   -6.816mA   -5.469mA
1.316V    -12.39mA   -13.6mA    -10.88mA
1.452V    -13.99mA   -15.3mA    -12.68mA
1.554V    -14.09mA   -15.62mA   -12.95mA
1.724V    -13.73mA   -15.53mA   -12.2mA
1.928V    -13.51mA   -15.36mA   -11.82mA
2.064V    -13.38mA   -15mA      -11.66mA
2.2V      -13.23mA   -14.25mA   -11.51mA
[GND_clamp]
|Voltage   I(typ)   I(min)   I(max)
-1.1V     -92.78mA   -81.05mA   -109.5mA
-1.031V   -81.73mA   -69.22mA   -97.17mA
-939mV    -68.18mA   -56.02mA   -81.64mA
-824mV    -52mA      -41.83mA   -62.83mA
-686mV    -33.62mA   -26.41mA   -41.32mA
-571mV    -19.76mA   -15.06mA   -24.85mA
-479mV    -10.5mA    -7.76mA    -13.5mA
-410mV    -5.313mA   -3.84mA    -6.916mA
-341mV    -2.007mA   -1.45mA    -2.59mA
-272mV    -506.9uA   -403.5uA   -609.8uA
-180mV    -45.65uA   -51.35uA   -43.55uA
1.1V      0A         0A         0A
[POWER_clamp]
|Voltage   I(typ)   I(min)   I(max)
-1.1V     5.691mA    8.967mA    3.44mA
-1.062V   3.709mA    6.444mA    2.092mA
-1.039V   2.781mA    5.152mA    1.546mA
-1.016V   2.086mA    4.085mA    1.193mA
-970mV    1.21mA     2.539mA    818.5uA
-947mV    943.7uA    2.005mA    716.7uA
-901mV    610.1uA    1.27mA     581.3uA
-855mV    430.7uA    824.1uA    484.6uA
-786mV    289.9uA    439.4uA    366uA
-671mV    155.9uA    155.9uA    203.6uA
-441mV    13.2uA     12.79uA    15.03uA
1.1V      0A         0A         0A
[Ramp]
| variable   typ   min   max
dV/dt_r   0.146/33.148p   0.143/42.127p   0.153/27.261p
dV/dt_f   0.205/44.793p   0.193/58.139p   0.208/35.579p
R_load = 50.000
[Rising Waveform]
R_fixture= 50.000
V_fixture= 1.100
V_fixture_min= 1.060
V_fixture_max= 1.170
|time   V(typ)   V(min)   V(max)
0s        758.6mV    738.8mV    823.3mV
144ps     759.4mV    739.2mV    820.4mV
157ps     757.9mV    739.5mV    847.5mV
199ps     752.9mV    739.3mV    1.02V
267ps     979.1mV    727.4mV    1.132V
328ps     1.064V     914.1mV    1.157V
373ps     1.085V     997mV      1.165V
466ps     1.096V     1.05V      1.169V
638ps     1.1V       1.059V     1.17V
3ns       1.1V       1.06V      1.17V
[Rising Waveform]
R_fixture= 50.000
V_fixture= 0.0
V_fixture_min= 0.0
V_fixture_max= 0.0
|time   V(typ)   V(min)   V(max)
0s        3.732uV    13.63uV    882.6nV
151ps     -2.695uV   30.18uV    6.213mV
196ps     816.1uV    21.32uV    225.6mV
216ps     8.616mV    105.4uV    282mV
264ps     201.5mV    511.5uV    331.7mV
300ps     269.4mV    20.61mV    286.5mV
374ps     296.3mV    232.6mV    258.3mV
487ps     245.4mV    279mV      255.2mV
603ps     244mV      239.8mV    255mV
3ns       243.9mV    238.7mV    255mV
[Falling Waveform]
R_fixture= 50.000
V_fixture= 1.100
V_fixture_min= 1.060
V_fixture_max= 1.170
|time   V(typ)   V(min)   V(max)
0s        1.1V       1.06V      1.17V
158ps     1.1V       1.06V      1.166V
225ps     1.092V     1.06V      831.6mV
269ps     900.5mV    1.06V      727.8mV
319ps     742.3mV    1.041V     783.5mV
361ps     686.8mV    904.3mV    806.3mV
418ps     725mV      752.8mV    817.8mV
497ps     751.7mV    680.6mV    822.2mV
703ps     758.5mV    737.4mV    823.3mV
3ns       758.6mV    738.8mV    823.3mV
[Falling Waveform]
R_fixture= 50.000
V_fixture= 0.0
V_fixture_min= 0.0
V_fixture_max= 0.0
|time   V(typ)   V(min)   V(max)
0s        243.9mV    238.7mV    255mV
145ps     243.7mV    238.4mV    257.6mV
194ps     252.6mV    238.7mV    71.17mV
211ps     224.1mV    241.4mV    40.71mV
257ps     65.19mV    250.4mV    8.992mV
292ps     22.73mV    179.6mV    -395uV
329ps     7.866mV    80.77mV    -215.8uV
356ps     3.576mV    38.07mV    -74.96uV
445ps     -429.2uV   3.993mV    -3.26uV
3ns       -1.513uV   13.5uV     427.3nV
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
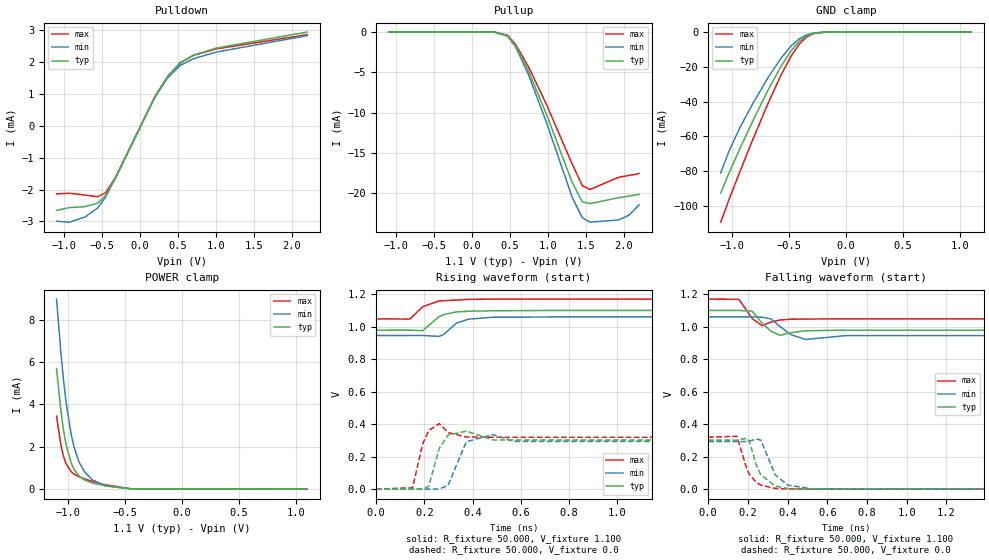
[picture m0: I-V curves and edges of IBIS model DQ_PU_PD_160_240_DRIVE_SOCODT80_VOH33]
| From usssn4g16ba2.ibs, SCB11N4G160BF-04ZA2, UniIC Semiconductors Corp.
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|   Model DQ_PU_PD_160_240_DRIVE_SOCODT80_VOH33
[Model] DQ_PU_PD_160_240_DRIVE_SOCODT80_VOH33
Model_type I/O
Polarity   Inverting
Vinl =  98.000mV
Vinh =  0.268V
Vmeas =  0.183V
Rref =  50.000
Vref =  0.183V
C_comp   1.020pF   1.010pF   1.030pF
[Model Spec]
Vinh   0.268V   0.262V   0.280V
Vinl   98.000mV   92.000mV   0.110V
Vmeas   0.183V   0.177V   0.195V
Vref   0.183V   0.177V   0.195V
Rref   50.000   NA   NA
[Temperature Range]   25.000   0.105k   -40.000
[Voltage Range]   1.100V   1.060V   1.170V
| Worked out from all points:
|   slope of the pulldown table from 0 to 0.165 V, typ, clamps not added: 211 ohm
|   GND clamp passes 1 mA (typ) near -0.30 V on its own axis
|   POWER clamp passes 1 mA (typ) near -0.95 V on its own axis
|   rising waveform, R_fixture 50.000, V_fixture 1.100: 20-80 % time 65.3ps typ, 64.5ps min, 65.2ps max; typ from 0.978 V to 1.1 V
|   rising waveform, R_fixture 50.000, V_fixture 0.0: 20-80 % time 30.9ps typ, 39.9ps min, 25.1ps max; typ from 0 V to 0.302 V
|   falling waveform, R_fixture 50.000, V_fixture 1.100: 20-80 % time 46.8ps typ, 62.5ps min, 36ps max; typ from 1.1 V to 0.978 V
|   falling waveform, R_fixture 50.000, V_fixture 0.0: 20-80 % time 62.3ps typ, 69.1ps min, 59.6ps max; typ from 0.302 V to 0 V
[Pulldown]
|Voltage   I(typ)   I(min)   I(max)
-1.1V     -2.652mA   -2.992mA   -2.134mA
-930mV    -2.565mA   -3.023mA   -2.114mA
-726mV    -2.535mA   -2.862mA   -2.171mA
-556mV    -2.422mA   -2.572mA   -2.223mA
-454mV    -2.185mA   -2.234mA   -2.101mA
-318mV    -1.604mA   -1.606mA   -1.589mA
192mV     900.6uA    884.3uA    903.8uA
362mV     1.549mA    1.507mA    1.549mA
532mV     1.993mA    1.907mA    1.988mA
702mV     2.225mA    2.111mA    2.215mA
1.008V    2.447mA    2.322mA    2.422mA
2.2V      2.948mA    2.835mA    2.866mA
[Pullup]
|Voltage   I(typ)   I(min)   I(max)
-1.1V     1.606nA    16.44nA    0A
296mV     -8.845uA   -14.64uA   -4.922uA
466mV     -464.7uA   -507.7uA   -387.5uA
568mV     -1.641mA   -1.758mA   -1.466mA
738mV     -4.764mA   -5.196mA   -4.236mA
976mV     -10.14mA   -11.16mA   -8.932mA
1.316V    -18.65mA   -20.49mA   -16.37mA
1.452V    -21.12mA   -23.1mA    -19.11mA
1.554V    -21.33mA   -23.64mA   -19.57mA
1.928V    -20.6mA    -23.36mA   -18.06mA
2.064V    -20.4mA    -22.78mA   -17.83mA
2.2V      -20.18mA   -21.49mA   -17.6mA
[GND_clamp]
|Voltage   I(typ)   I(min)   I(max)
-1.1V     -92.78mA   -81.05mA   -109.5mA
-1.031V   -81.73mA   -69.22mA   -97.17mA
-939mV    -68.18mA   -56.02mA   -81.64mA
-824mV    -52mA      -41.83mA   -62.83mA
-686mV    -33.62mA   -26.41mA   -41.32mA
-571mV    -19.76mA   -15.06mA   -24.85mA
-479mV    -10.5mA    -7.76mA    -13.5mA
-410mV    -5.313mA   -3.84mA    -6.916mA
-341mV    -2.007mA   -1.45mA    -2.59mA
-272mV    -506.9uA   -403.5uA   -609.8uA
-180mV    -45.65uA   -51.35uA   -43.55uA
1.1V      0A         0A         0A
[POWER_clamp]
|Voltage   I(typ)   I(min)   I(max)
-1.1V     5.691mA    8.967mA    3.44mA
-1.062V   3.709mA    6.444mA    2.092mA
-1.039V   2.781mA    5.152mA    1.546mA
-1.016V   2.086mA    4.085mA    1.193mA
-970mV    1.21mA     2.539mA    818.5uA
-947mV    943.7uA    2.005mA    716.7uA
-901mV    610.1uA    1.27mA     581.3uA
-855mV    430.7uA    824.1uA    484.6uA
-786mV    289.9uA    439.4uA    366uA
-671mV    155.9uA    155.9uA    203.6uA
-441mV    13.2uA     12.79uA    15.03uA
1.1V      0A         0A         0A
[Ramp]
| variable   typ   min   max
dV/dt_r   0.181/31.010p   0.176/39.984p   0.192/25.334p
dV/dt_f   72.904m/46.808p   68.572m/62.561p   73.268m/36.102p
R_load = 50.000
[Rising Waveform]
R_fixture= 50.000
V_fixture= 1.100
V_fixture_min= 1.060
V_fixture_max= 1.170
|time   V(typ)   V(min)   V(max)
0s        978.5mV    945.7mV    1.048V
140ps     978.8mV    945.9mV    1.047V
193ps     975.4mV    945.9mV    1.123V
260ps     1.061V     940mV      1.158V
280ps     1.074V     952.2mV    1.16V
333ps     1.091V     1.022V     1.164V
383ps     1.095V     1.046V     1.168V
481ps     1.098V     1.058V     1.17V
729ps     1.1V       1.06V      1.17V
3ns       1.1V       1.06V      1.17V
[Rising Waveform]
R_fixture= 50.000
V_fixture= 0.0
V_fixture_min= 0.0
V_fixture_max= 0.0
|time   V(typ)   V(min)   V(max)
0s        5.235uV    19.06uV    1.24uV
151ps     -191.3uV   65.34uV    8.324mV
194ps     1.151mV    -92.99uV   283.3mV
218ps     17.23mV    -283.2uV   360.6mV
262ps     252.3mV    1.049mV    403.1mV
298ps     332.6mV    23.49mV    348.1mV
374ps     357.1mV    291.9mV    320.9mV
484ps     302.8mV    335.8mV    319.2mV
571ps     302.1mV    294mV      319.2mV
3ns       302.1mV    293.3mV    319.2mV
[Falling Waveform]
R_fixture= 50.000
V_fixture= 1.100
V_fixture_min= 1.060
V_fixture_max= 1.170
|time   V(typ)   V(min)   V(max)
0s        1.1V       1.06V      1.17V
155ps     1.1V       1.06V      1.168V
222ps     1.095V     1.06V      1.05V
272ps     1.021V     1.058V     1.006V
316ps     971.9mV    1.048V     1.029V
362ps     946.7mV    1.001V     1.041V
417ps     963.3mV    950.1mV    1.046V
491ps     975.2mV    921.4mV    1.047V
694ps     978.4mV    945.1mV    1.048V
3ns       978.5mV    945.7mV    1.048V
[Falling Waveform]
R_fixture= 50.000
V_fixture= 0.0
V_fixture_min= 0.0
V_fixture_max= 0.0
|time   V(typ)   V(min)   V(max)
0s        302.1mV    293.3mV    319.2mV
145ps     301.6mV    292.9mV    325.7mV
195ps     314mV      293.1mV    121.8mV
209ps     288.4mV    295.9mV    88.68mV
242ps     148.9mV    308.9mV    42.05mV
265ps     88.84mV    302.2mV    24.74mV
337ps     19.43mV    89.17mV    4.769mV
401ps     4.235mV    24.82mV    1.213mV
525ps     356uV      1.707mV    84.36uV
3ns       5.293uV    19.12uV    655.9nV
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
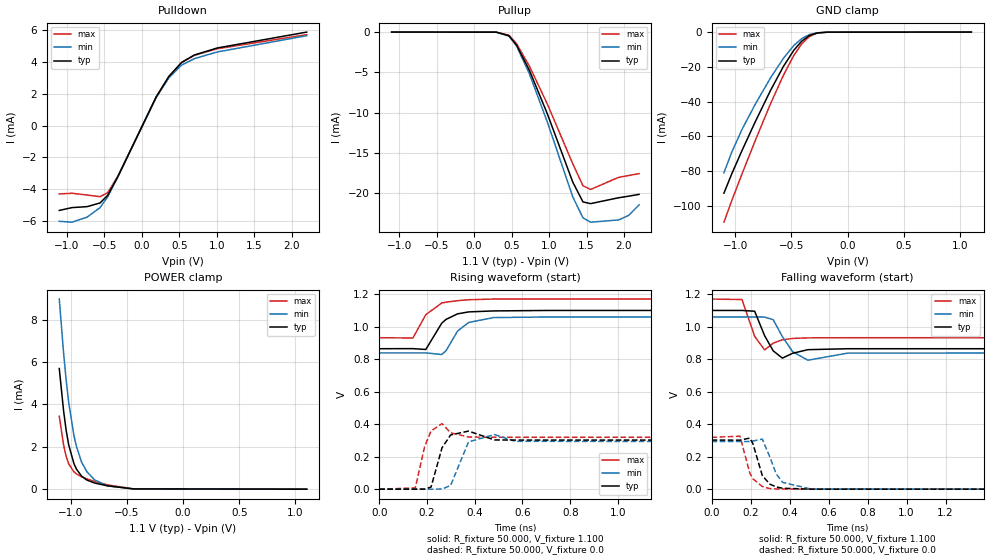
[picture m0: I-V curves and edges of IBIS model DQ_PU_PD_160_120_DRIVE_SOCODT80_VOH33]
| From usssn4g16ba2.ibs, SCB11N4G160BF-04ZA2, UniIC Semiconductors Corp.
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|   Model DQ_PU_PD_160_120_DRIVE_SOCODT80_VOH33
[Model] DQ_PU_PD_160_120_DRIVE_SOCODT80_VOH33
Model_type I/O
Polarity   Inverting
Vinl =  98.000mV
Vinh =  0.268V
Vmeas =  0.183V
Rref =  50.000
Vref =  0.183V
C_comp   1.020pF   1.010pF   1.030pF
[Model Spec]
Vinh   0.268V   0.262V   0.280V
Vinl   98.000mV   92.000mV   0.110V
Vmeas   0.183V   0.177V   0.195V
Vref   0.183V   0.177V   0.195V
Rref   50.000   NA   NA
[Temperature Range]   25.000   0.105k   -40.000
[Voltage Range]   1.100V   1.060V   1.170V
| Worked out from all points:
|   slope of the pulldown table from 0 to 0.165 V, typ, clamps not added: 105 ohm
|   GND clamp passes 1 mA (typ) near -0.30 V on its own axis
|   POWER clamp passes 1 mA (typ) near -0.95 V on its own axis
|   rising waveform, R_fixture 50.000, V_fixture 1.100: 20-80 % time 68.7ps typ, 70.1ps min, 67.4ps max; typ from 0.864 V to 1.1 V
|   rising waveform, R_fixture 50.000, V_fixture 0.0: 20-80 % time 30.7ps typ, 39.6ps min, 25.1ps max; typ from 0 V to 0.302 V
|   falling waveform, R_fixture 50.000, V_fixture 1.100: 20-80 % time 45.3ps typ, 59.5ps min, 35.5ps max; typ from 1.1 V to 0.864 V
|   falling waveform, R_fixture 50.000, V_fixture 0.0: 20-80 % time 51.8ps typ, 61.9ps min, 48.7ps max; typ from 0.302 V to 0 V
[Pulldown]
|Voltage   I(typ)   I(min)   I(max)
-1.1V     -5.34mA    -6.026mA   -4.302mA
-930mV    -5.164mA   -6.082mA   -4.26mA
-726mV    -5.101mA   -5.754mA   -4.373mA
-556mV    -4.87mA    -5.165mA   -4.475mA
-454mV    -4.386mA   -4.479mA   -4.222mA
-318mV    -3.209mA   -3.211mA   -3.18mA
192mV     1.799mA    1.766mA    1.806mA
362mV     3.096mA    3.011mA    3.096mA
532mV     3.983mA    3.811mA    3.973mA
702mV     4.448mA    4.219mA    4.427mA
1.008V    4.891mA    4.64mA     4.842mA
2.2V      5.891mA    5.665mA    5.73mA
[Pullup]
|Voltage   I(typ)   I(min)   I(max)
-1.1V     1.606nA    16.44nA    0A
296mV     -8.845uA   -14.64uA   -4.922uA
466mV     -464.7uA   -507.7uA   -387.5uA
568mV     -1.641mA   -1.758mA   -1.466mA
738mV     -4.764mA   -5.196mA   -4.236mA
976mV     -10.14mA   -11.16mA   -8.932mA
1.316V    -18.65mA   -20.49mA   -16.37mA
1.452V    -21.12mA   -23.1mA    -19.11mA
1.554V    -21.33mA   -23.64mA   -19.57mA
1.928V    -20.6mA    -23.36mA   -18.06mA
2.064V    -20.4mA    -22.78mA   -17.83mA
2.2V      -20.18mA   -21.49mA   -17.6mA
[GND_clamp]
|Voltage   I(typ)   I(min)   I(max)
-1.1V     -92.78mA   -81.05mA   -109.5mA
-1.031V   -81.73mA   -69.22mA   -97.17mA
-939mV    -68.18mA   -56.02mA   -81.64mA
-824mV    -52mA      -41.83mA   -62.83mA
-686mV    -33.62mA   -26.41mA   -41.32mA
-571mV    -19.76mA   -15.06mA   -24.85mA
-479mV    -10.5mA    -7.76mA    -13.5mA
-410mV    -5.313mA   -3.84mA    -6.916mA
-341mV    -2.007mA   -1.45mA    -2.59mA
-272mV    -506.9uA   -403.5uA   -609.8uA
-180mV    -45.65uA   -51.35uA   -43.55uA
1.1V      0A         0A         0A
[POWER_clamp]
|Voltage   I(typ)   I(min)   I(max)
-1.1V     5.691mA    8.967mA    3.44mA
-1.062V   3.709mA    6.444mA    2.092mA
-1.039V   2.781mA    5.152mA    1.546mA
-1.016V   2.086mA    4.085mA    1.193mA
-970mV    1.21mA     2.539mA    818.5uA
-947mV    943.7uA    2.005mA    716.7uA
-901mV    610.1uA    1.27mA     581.3uA
-855mV    430.7uA    824.1uA    484.6uA
-786mV    289.9uA    439.4uA    366uA
-671mV    155.9uA    155.9uA    203.6uA
-441mV    13.2uA     12.79uA    15.03uA
1.1V      0A         0A         0A
[Ramp]
| variable   typ   min   max
dV/dt_r   0.181/30.812p   0.176/39.497p   0.192/25.195p
dV/dt_f   0.141/45.332p   0.133/59.536p   0.143/35.518p
R_load = 50.000
[Rising Waveform]
R_fixture= 50.000
V_fixture= 1.100
V_fixture_min= 1.060
V_fixture_max= 1.170
|time   V(typ)   V(min)   V(max)
0s        864.4mV    838.5mV    932.1mV
141ps     864.9mV    838.7mV    930.3mV
195ps     859.6mV    838.7mV    1.074V
262ps     1.022V     828.7mV    1.146V
280ps     1.045V     852.5mV    1.151V
328ps     1.079V     973.1mV    1.16V
375ps     1.091V     1.026V     1.166V
479ps     1.097V     1.056V     1.17V
718ps     1.1V       1.06V      1.17V
3ns       1.1V       1.06V      1.17V
[Rising Waveform]
R_fixture= 50.000
V_fixture= 0.0
V_fixture_min= 0.0
V_fixture_max= 0.0
|time   V(typ)   V(min)   V(max)
0s        4.356uV    15.89uV    1.031uV
151ps     -96.84uV   54.19uV    7.108mV
190ps     269uV      -1.415uV   260.9mV
217ps     12.82mV    -111.7uV   358.3mV
263ps     254.9mV    614.8uV    403.3mV
299ps     333.6mV    23mV       346.9mV
374ps     357.3mV    291.2mV    320.9mV
483ps     302.8mV    335.7mV    319.2mV
570ps     302.1mV    294.1mV    319.2mV
3ns       302.1mV    293.3mV    319.2mV
[Falling Waveform]
R_fixture= 50.000
V_fixture= 1.100
V_fixture_min= 1.060
V_fixture_max= 1.170
|time   V(typ)   V(min)   V(max)
0s        1.1V       1.06V      1.17V
156ps     1.1V       1.06V      1.167V
221ps     1.095V     1.06V      940.5mV
272ps     944.7mV    1.059V     856.9mV
316ps     851.6mV    1.043V     898.5mV
363ps     806.5mV    939.4mV    919.2mV
416ps     836.3mV    845.9mV    927.7mV
494ps     858.5mV    793.6mV    931.2mV
698ps     864.3mV    837.3mV    932.1mV
3ns       864.4mV    838.5mV    932.1mV
[Falling Waveform]
R_fixture= 50.000
V_fixture= 0.0
V_fixture_min= 0.0
V_fixture_max= 0.0
|time   V(typ)   V(min)   V(max)
0s        302.1mV    293.3mV    319.2mV
146ps     301.7mV    292.8mV    325.7mV
196ps     314.5mV    293.2mV    99.96mV
212ps     280.1mV    296.6mV    63.94mV
260ps     84.32mV    308.5mV    16.63mV
298ps     31.61mV    200.7mV    3.908mV
332ps     13.49mV    93.03mV    1.659mV
365ps     5.525mV    41.36mV    719.4uV
510ps     69.88uV    804.1uV    18.23uV
3ns       4.394uV    15.9uV     1.068uV
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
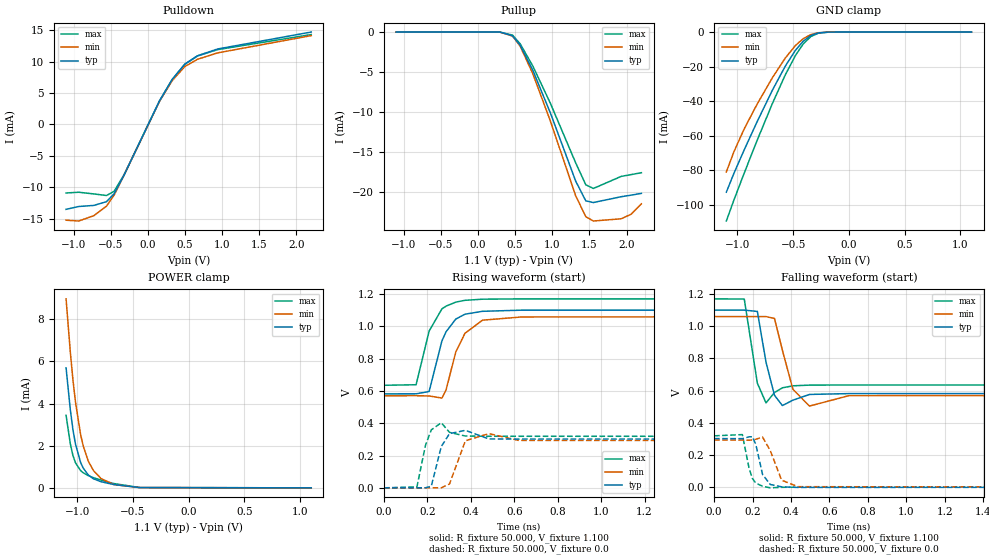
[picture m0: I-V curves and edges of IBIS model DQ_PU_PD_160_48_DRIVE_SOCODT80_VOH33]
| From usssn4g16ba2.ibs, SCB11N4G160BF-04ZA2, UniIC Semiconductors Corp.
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|   Model DQ_PU_PD_160_48_DRIVE_SOCODT80_VOH33
[Model] DQ_PU_PD_160_48_DRIVE_SOCODT80_VOH33
Model_type I/O
Polarity   Inverting
Vinl =  98.000mV
Vinh =  0.268V
Vmeas =  0.183V
Rref =  50.000
Vref =  0.183V
C_comp   1.020pF   1.010pF   1.030pF
[Model Spec]
Vinh   0.268V   0.262V   0.280V
Vinl   98.000mV   92.000mV   0.110V
Vmeas   0.183V   0.177V   0.195V
Vref   0.183V   0.177V   0.195V
Rref   50.000   NA   NA
[Temperature Range]   25.000   0.105k   -40.000
[Voltage Range]   1.100V   1.060V   1.170V
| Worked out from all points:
|   slope of the pulldown table from 0 to 0.165 V, typ, clamps not added: 42.3 ohm
|   GND clamp passes 1 mA (typ) near -0.30 V on its own axis
|   POWER clamp passes 1 mA (typ) near -0.95 V on its own axis
|   rising waveform, R_fixture 50.000, V_fixture 1.100: 20-80 % time 74.8ps typ, 78.2ps min, 72.3ps max; typ from 0.582 V to 1.1 V
|   rising waveform, R_fixture 50.000, V_fixture 0.0: 20-80 % time 30.4ps typ, 39ps min, 24.9ps max; typ from 0 V to 0.302 V
|   falling waveform, R_fixture 50.000, V_fixture 1.100: 20-80 % time 42.6ps typ, 55.9ps min, 34.5ps max; typ from 1.1 V to 0.582 V
|   falling waveform, R_fixture 50.000, V_fixture 0.0: 20-80 % time 36.7ps typ, 52.7ps min, 32.5ps max; typ from 0.302 V to 0 V
[Pulldown]
|Voltage   I(typ)   I(min)   I(max)
-1.1V     -13.51mA   -15.24mA   -10.91mA
-930mV    -13.06mA   -15.37mA   -10.79mA
-726mV    -12.89mA   -14.52mA   -11.06mA
-556mV    -12.29mA   -13.01mA   -11.31mA
-454mV    -11.04mA   -11.25mA   -10.65mA
-318mV    -8.03mA    -8.027mA   -7.964mA
158mV     3.751mA    3.687mA    3.768mA
328mV     7.153mA    6.973mA    7.158mA
498mV     9.598mA    9.214mA    9.581mA
668mV     10.93mA    10.37mA    10.89mA
940mV     12.01mA    11.39mA    11.91mA
2.2V      14.71mA    14.14mA    14.31mA
[Pullup]
|Voltage   I(typ)   I(min)   I(max)
-1.1V     1.606nA    16.44nA    0A
296mV     -8.845uA   -14.64uA   -4.922uA
466mV     -464.7uA   -507.7uA   -387.5uA
568mV     -1.641mA   -1.758mA   -1.466mA
738mV     -4.764mA   -5.196mA   -4.236mA
976mV     -10.14mA   -11.16mA   -8.932mA
1.316V    -18.65mA   -20.49mA   -16.37mA
1.452V    -21.12mA   -23.1mA    -19.11mA
1.554V    -21.33mA   -23.64mA   -19.57mA
1.928V    -20.6mA    -23.36mA   -18.06mA
2.064V    -20.4mA    -22.78mA   -17.83mA
2.2V      -20.18mA   -21.49mA   -17.6mA
[GND_clamp]
|Voltage   I(typ)   I(min)   I(max)
-1.1V     -92.78mA   -81.05mA   -109.5mA
-1.031V   -81.73mA   -69.22mA   -97.17mA
-939mV    -68.18mA   -56.02mA   -81.64mA
-824mV    -52mA      -41.83mA   -62.83mA
-686mV    -33.62mA   -26.41mA   -41.32mA
-571mV    -19.76mA   -15.06mA   -24.85mA
-479mV    -10.5mA    -7.76mA    -13.5mA
-410mV    -5.313mA   -3.84mA    -6.916mA
-341mV    -2.007mA   -1.45mA    -2.59mA
-272mV    -506.9uA   -403.5uA   -609.8uA
-180mV    -45.65uA   -51.35uA   -43.55uA
1.1V      0A         0A         0A
[POWER_clamp]
|Voltage   I(typ)   I(min)   I(max)
-1.1V     5.691mA    8.967mA    3.44mA
-1.062V   3.709mA    6.444mA    2.092mA
-1.039V   2.781mA    5.152mA    1.546mA
-1.016V   2.086mA    4.085mA    1.193mA
-970mV    1.21mA     2.539mA    818.5uA
-947mV    943.7uA    2.005mA    716.7uA
-901mV    610.1uA    1.27mA     581.3uA
-855mV    430.7uA    824.1uA    484.6uA
-786mV    289.9uA    439.4uA    366uA
-671mV    155.9uA    155.9uA    203.6uA
-441mV    13.2uA     12.79uA    15.03uA
1.1V      0A         0A         0A
[Ramp]
| variable   typ   min   max
dV/dt_r   0.181/30.338p   0.176/38.919p   0.192/24.997p
dV/dt_f   0.311/42.683p   0.294/55.993p   0.321/34.473p
R_load = 50.000
[Rising Waveform]
R_fixture= 50.000
V_fixture= 1.100
V_fixture_min= 1.060
V_fixture_max= 1.170
|time   V(typ)   V(min)   V(max)
0s        581.6mV    569.9mV    635mV
148ps     582.3mV    570.6mV    638.4mV
208ps     596.5mV    568.8mV    970.4mV
267ps     909.6mV    555.8mV    1.108V
286ps     966.4mV    606.6mV    1.125V
331ps     1.045V     841.6mV    1.15V
373ps     1.075V     956.7mV    1.161V
454ps     1.093V     1.038V     1.168V
634ps     1.1V       1.058V     1.17V
3ns       1.1V       1.06V      1.17V
[Rising Waveform]
R_fixture= 50.000
V_fixture= 0.0
V_fixture_min= 0.0
V_fixture_max= 0.0
|time   V(typ)   V(min)   V(max)
0s        2.898uV    10.6uV     685nV
152ps     91.66uV    31.25uV    6.439mV
191ps     381.7uV    60.71uV    262.2mV
218ps     10.25mV    247uV      359mV
264ps     255.6mV    99.21uV    403.3mV
302ps     335.7mV    24.37mV    343.4mV
375ps     356.2mV    291.3mV    320.8mV
483ps     302.8mV    335.7mV    319.2mV
621ps     302.1mV    293.5mV    319.2mV
3ns       302.1mV    293.3mV    319.2mV
[Falling Waveform]
R_fixture= 50.000
V_fixture= 1.100
V_fixture_min= 1.060
V_fixture_max= 1.170
|time   V(typ)   V(min)   V(max)
0s        1.1V       1.06V      1.17V
157ps     1.1V       1.06V      1.169V
225ps     1.092V     1.06V      646.1mV
270ps     776.8mV    1.06V      524.1mV
314ps     571.2mV    1.048V     588.2mV
355ps     507.4mV    851.4mV    617.4mV
410ps     540.8mV    608mV      630mV
496ps     576.4mV    504.2mV    634.3mV
701ps     581.5mV    568.8mV    635mV
3ns       581.6mV    569.9mV    635mV
[Falling Waveform]
R_fixture= 50.000
V_fixture= 0.0
V_fixture_min= 0.0
V_fixture_max= 0.0
|time   V(typ)   V(min)   V(max)
0s        302.1mV    293.3mV    319.2mV
147ps     301.7mV    292.8mV    326.9mV
182ps     313.2mV    292.3mV    117.4mV
199ps     313.6mV    293.5mV    55.12mV
217ps     266mV      298mV      25.58mV
252ps     79.39mV    311.4mV    6.149mV
292ps     17.21mV    227.9mV    -3.831mV
351ps     2.407mV    43.87mV    -445.9uV
436ps     -1.113mV   3.367mV    -15.22uV
3ns       -956.6nV   10.52uV    179.7nV
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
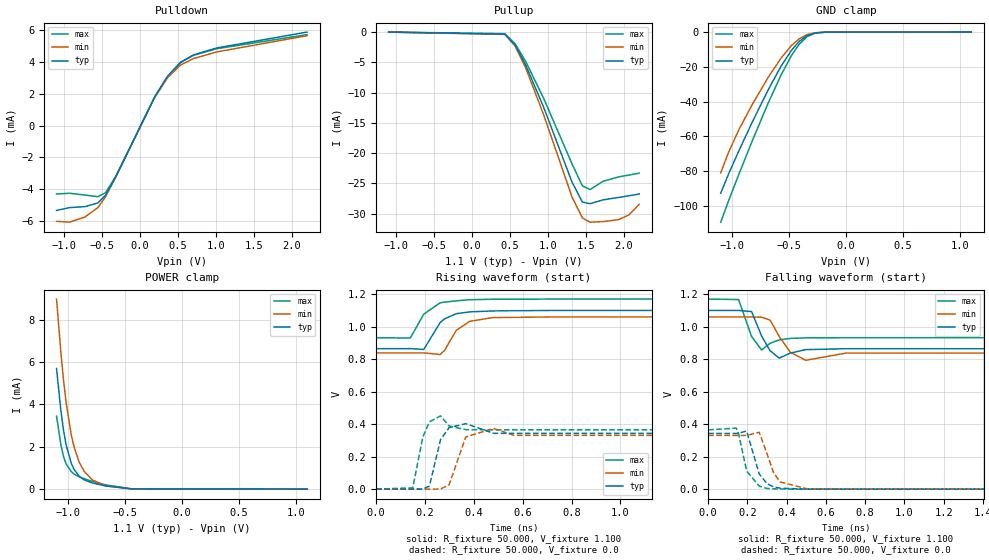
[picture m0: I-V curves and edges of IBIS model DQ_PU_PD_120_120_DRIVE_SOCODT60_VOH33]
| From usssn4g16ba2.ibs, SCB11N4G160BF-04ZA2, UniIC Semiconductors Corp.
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|   Model DQ_PU_PD_120_120_DRIVE_SOCODT60_VOH33
[Model] DQ_PU_PD_120_120_DRIVE_SOCODT60_VOH33
Model_type I/O
Polarity   Inverting
Vinl =  98.000mV
Vinh =  0.268V
Vmeas =  0.183V
Rref =  50.000
Vref =  0.183V
C_comp   1.020pF   1.010pF   1.030pF
[Model Spec]
Vinh   0.268V   0.262V   0.280V
Vinl   98.000mV   92.000mV   0.110V
Vmeas   0.183V   0.177V   0.195V
Vref   0.183V   0.177V   0.195V
Rref   50.000   NA   NA
[Temperature Range]   25.000   0.105k   -40.000
[Voltage Range]   1.100V   1.060V   1.170V
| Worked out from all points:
|   slope of the pulldown table from 0 to 0.165 V, typ, clamps not added: 105 ohm
|   GND clamp passes 1 mA (typ) near -0.30 V on its own axis
|   POWER clamp passes 1 mA (typ) near -0.95 V on its own axis
|   rising waveform, R_fixture 50.000, V_fixture 1.100: 20-80 % time 67.3ps typ, 67.5ps min, 66.7ps max; typ from 0.864 V to 1.1 V
|   rising waveform, R_fixture 50.000, V_fixture 0.0: 20-80 % time 29ps typ, 37.7ps min, 23.6ps max; typ from 0 V to 0.343 V
|   falling waveform, R_fixture 50.000, V_fixture 1.100: 20-80 % time 45.6ps typ, 60.3ps min, 35.6ps max; typ from 1.1 V to 0.864 V
|   falling waveform, R_fixture 50.000, V_fixture 0.0: 20-80 % time 51.7ps typ, 61.2ps min, 48.8ps max; typ from 0.343 V to 0 V
[Pulldown]
|Voltage   I(typ)   I(min)   I(max)
-1.1V     -5.34mA    -6.026mA   -4.302mA
-930mV    -5.164mA   -6.082mA   -4.26mA
-726mV    -5.101mA   -5.754mA   -4.373mA
-556mV    -4.87mA    -5.165mA   -4.475mA
-454mV    -4.386mA   -4.479mA   -4.222mA
-318mV    -3.209mA   -3.211mA   -3.18mA
192mV     1.799mA    1.766mA    1.806mA
362mV     3.096mA    3.011mA    3.096mA
532mV     3.983mA    3.811mA    3.973mA
702mV     4.448mA    4.219mA    4.427mA
1.008V    4.891mA    4.64mA     4.842mA
2.2V      5.891mA    5.665mA    5.73mA
[Pullup]
|Voltage   I(typ)   I(min)   I(max)
-1.1V     2.1nA      21.95nA    0A
432mV     -337.7uA   -381.6uA   -263.6uA
568mV     -2.186mA   -2.341mA   -1.952mA
704mV     -5.417mA   -5.891mA   -4.827mA
942mV     -12.42mA   -13.65mA   -10.95mA
1.316V    -24.8mA    -27.25mA   -21.78mA
1.452V    -28.09mA   -30.72mA   -25.42mA
1.554V    -28.36mA   -31.42mA   -26.03mA
1.724V    -27.73mA   -31.32mA   -24.66mA
1.928V    -27.33mA   -31mA      -23.94mA
2.064V    -27.06mA   -30.24mA   -23.63mA
2.2V      -26.76mA   -28.47mA   -23.32mA
[GND_clamp]
|Voltage   I(typ)   I(min)   I(max)
-1.1V     -92.78mA   -81.05mA   -109.5mA
-1.031V   -81.73mA   -69.22mA   -97.17mA
-939mV    -68.18mA   -56.02mA   -81.64mA
-824mV    -52mA      -41.83mA   -62.83mA
-686mV    -33.62mA   -26.41mA   -41.32mA
-571mV    -19.76mA   -15.06mA   -24.85mA
-479mV    -10.5mA    -7.76mA    -13.5mA
-410mV    -5.313mA   -3.84mA    -6.916mA
-341mV    -2.007mA   -1.45mA    -2.59mA
-272mV    -506.9uA   -403.5uA   -609.8uA
-180mV    -45.65uA   -51.35uA   -43.55uA
1.1V      0A         0A         0A
[POWER_clamp]
|Voltage   I(typ)   I(min)   I(max)
-1.1V     5.691mA    8.967mA    3.44mA
-1.062V   3.709mA    6.444mA    2.092mA
-1.039V   2.781mA    5.152mA    1.546mA
-1.016V   2.086mA    4.085mA    1.193mA
-970mV    1.21mA     2.539mA    818.5uA
-947mV    943.7uA    2.005mA    716.7uA
-901mV    610.1uA    1.27mA     581.3uA
-855mV    430.7uA    824.1uA    484.6uA
-786mV    289.9uA    439.4uA    366uA
-671mV    155.9uA    155.9uA    203.6uA
-441mV    13.2uA     12.79uA    15.03uA
1.1V      0A         0A         0A
[Ramp]
| variable   typ   min   max
dV/dt_r   0.206/29.194p   0.199/37.868p   0.219/23.889p
dV/dt_f   0.141/45.638p   0.133/60.104p   0.143/35.657p
R_load = 50.000
[Rising Waveform]
R_fixture= 50.000
V_fixture= 1.100
V_fixture_min= 1.060
V_fixture_max= 1.170
|time   V(typ)   V(min)   V(max)
0s        864.4mV    838.5mV    932.1mV
140ps     865mV      838.7mV    930mV
195ps     859.9mV    838.7mV    1.077V
262ps     1.025V     828.8mV    1.147V
280ps     1.048V     853.7mV    1.151V
328ps     1.08V      977.3mV    1.159V
383ps     1.091V     1.033V     1.166V
478ps     1.097V     1.056V     1.169V
726ps     1.1V       1.06V      1.17V
3ns       1.1V       1.06V      1.17V
[Rising Waveform]
R_fixture= 50.000
V_fixture= 0.0
V_fixture_min= 0.0
V_fixture_max= 0.0
|time   V(typ)   V(min)   V(max)
0s        4.356uV    15.89uV    1.031uV
150ps     -151.9uV   63.08uV    7.857mV
191ps     456.3uV    -25.82uV   319.7mV
218ps     18.34mV    -222.2uV   414.1mV
264ps     305.6mV    914.6uV    451mV
299ps     378.7mV    27.24mV    387.8mV
367ps     403mV      321.4mV    366.3mV
481ps     343.5mV    373.6mV    365.2mV
564ps     343.2mV    330.9mV    365.2mV
3ns       343.2mV    331.4mV    365.2mV
[Falling Waveform]
R_fixture= 50.000
V_fixture= 1.100
V_fixture_min= 1.060
V_fixture_max= 1.170
|time   V(typ)   V(min)   V(max)
0s        1.1V       1.06V      1.17V
155ps     1.1V       1.06V      1.167V
221ps     1.093V     1.06V      939.5mV
272ps     943.2mV    1.058V     856.5mV
315ps     852.3mV    1.041V     897.6mV
362ps     806.5mV    939.9mV    918.8mV
418ps     837.3mV    843mV      927.8mV
497ps     858.9mV    793.3mV    931.2mV
702ps     864.3mV    837.4mV    932.1mV
3ns       864.4mV    838.5mV    932.1mV
[Falling Waveform]
R_fixture= 50.000
V_fixture= 0.0
V_fixture_min= 0.0
V_fixture_max= 0.0
|time   V(typ)   V(min)   V(max)
0s        343.2mV    331.4mV    365.2mV
143ps     342.5mV    330.9mV    375.5mV
155ps     344.6mV    330.6mV    340.3mV
196ps     357.9mV    331.3mV    111.8mV
260ps     93.74mV    350mV      18.61mV
299ps     34.22mV    221.5mV    4.499mV
332ps     15.01mV    103.7mV    1.963mV
366ps     5.972mV    44.71mV    826uV
507ps     97.42uV    1.194mV    22.75uV
3ns       4.356uV    15.77uV    1.056uV
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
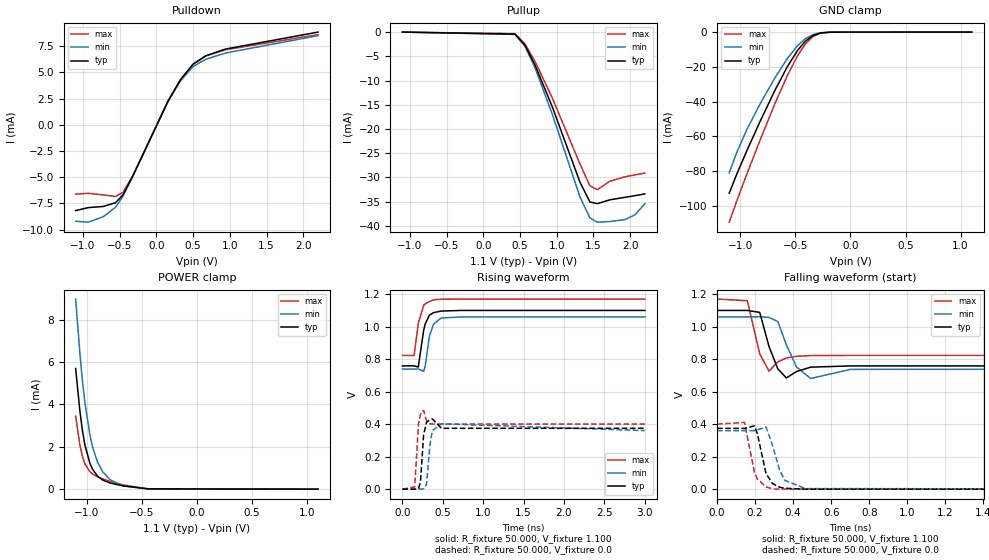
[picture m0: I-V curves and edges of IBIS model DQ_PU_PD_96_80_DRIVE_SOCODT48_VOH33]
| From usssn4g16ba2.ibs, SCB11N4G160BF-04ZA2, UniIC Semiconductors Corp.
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|   Model DQ_PU_PD_96_80_DRIVE_SOCODT48_VOH33
[Model] DQ_PU_PD_96_80_DRIVE_SOCODT48_VOH33
Model_type I/O
Polarity   Inverting
Vinl =  98.000mV
Vinh =  0.268V
Vmeas =  0.183V
Rref =  50.000
Vref =  0.183V
C_comp   1.020pF   1.010pF   1.030pF
[Model Spec]
Vinh   0.268V   0.262V   0.280V
Vinl   98.000mV   92.000mV   0.110V
Vmeas   0.183V   0.177V   0.195V
Vref   0.183V   0.177V   0.195V
Rref   50.000   NA   NA
[Temperature Range]   25.000   0.105k   -40.000
[Voltage Range]   1.100V   1.060V   1.170V
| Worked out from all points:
|   slope of the pulldown table from 0 to 0.165 V, typ, clamps not added: 70.2 ohm
|   GND clamp passes 1 mA (typ) near -0.30 V on its own axis
|   POWER clamp passes 1 mA (typ) near -0.95 V on its own axis
|   rising waveform, R_fixture 50.000, V_fixture 1.100: 20-80 % time 70.3ps typ, 71.4ps min, 69ps max; typ from 0.759 V to 1.1 V
|   rising waveform, R_fixture 50.000, V_fixture 0.0: 20-80 % time 27.9ps typ, 36.5ps min, 22.7ps max; typ from 0 V to 0.374 V
|   falling waveform, R_fixture 50.000, V_fixture 1.100: 20-80 % time 45.3ps typ, 59.8ps min, 35.8ps max; typ from 1.1 V to 0.759 V
|   falling waveform, R_fixture 50.000, V_fixture 0.0: 20-80 % time 46.1ps typ, 58.3ps min, 42.2ps max; typ from 0.374 V to 0 V
[Pulldown]
|Voltage   I(typ)   I(min)   I(max)
-1.1V     -8.193mA   -9.206mA   -6.618mA
-930mV    -7.906mA   -9.295mA   -6.537mA
-726mV    -7.797mA   -8.78mA    -6.691mA
-556mV    -7.432mA   -7.863mA   -6.841mA
-454mV    -6.673mA   -6.794mA   -6.44mA
-318mV    -4.841mA   -4.838mA   -4.804mA
158mV     2.257mA    2.219mA    2.267mA
328mV     4.302mA    4.194mA    4.305mA
498mV     5.77mA     5.539mA    5.759mA
668mV     6.567mA    6.233mA    6.54mA
940mV     7.217mA    6.841mA    7.152mA
2.2V      8.836mA    8.496mA    8.595mA
[Pullup]
|Voltage   I(typ)   I(min)   I(max)
-1.1V     2.6nA      27.46nA    0A
432mV     -421.9uA   -476.8uA   -329.3uA
568mV     -2.729mA   -2.923mA   -2.437mA
704mV     -6.762mA   -7.352mA   -6.026mA
942mV     -15.5mA    -17.03mA   -13.67mA
1.316V    -30.95mA   -34mA      -27.19mA
1.452V    -35.08mA   -38.36mA   -31.74mA
1.554V    -35.42mA   -39.25mA   -32.53mA
1.724V    -34.63mA   -39.11mA   -30.79mA
1.928V    -34.12mA   -38.72mA   -29.88mA
2.064V    -33.78mA   -37.75mA   -29.49mA
2.2V      -33.41mA   -35.44mA   -29.11mA
[GND_clamp]
|Voltage   I(typ)   I(min)   I(max)
-1.1V     -92.78mA   -81.05mA   -109.5mA
-1.031V   -81.73mA   -69.22mA   -97.17mA
-939mV    -68.18mA   -56.02mA   -81.64mA
-824mV    -52mA      -41.83mA   -62.83mA
-686mV    -33.62mA   -26.41mA   -41.32mA
-571mV    -19.76mA   -15.06mA   -24.85mA
-479mV    -10.5mA    -7.76mA    -13.5mA
-410mV    -5.313mA   -3.84mA    -6.916mA
-341mV    -2.007mA   -1.45mA    -2.59mA
-272mV    -506.9uA   -403.5uA   -609.8uA
-180mV    -45.65uA   -51.35uA   -43.55uA
1.1V      0A         0A         0A
[POWER_clamp]
|Voltage   I(typ)   I(min)   I(max)
-1.1V     5.691mA    8.967mA    3.44mA
-1.062V   3.709mA    6.444mA    2.092mA
-1.039V   2.781mA    5.152mA    1.546mA
-1.016V   2.086mA    4.085mA    1.193mA
-970mV    1.21mA     2.539mA    818.5uA
-947mV    943.7uA    2.005mA    716.7uA
-901mV    610.1uA    1.27mA     581.3uA
-855mV    430.7uA    824.1uA    484.6uA
-786mV    289.9uA    439.4uA    366uA
-671mV    155.9uA    155.9uA    203.6uA
-441mV    13.2uA     12.79uA    15.03uA
1.1V      0A         0A         0A
[Ramp]
| variable   typ   min   max
dV/dt_r   0.225/27.970p   0.216/36.659p   0.240/22.852p
dV/dt_f   0.205/45.397p   0.193/59.821p   0.208/35.929p
R_load = 50.000
[Rising Waveform]
R_fixture= 50.000
V_fixture= 1.100
V_fixture_min= 1.060
V_fixture_max= 1.170
|time   V(typ)   V(min)   V(max)
0s        758.6mV    738.8mV    823.3mV
144ps     759.3mV    739.2mV    822.9mV
196ps     751.4mV    739.4mV    1.02V
263ps     978.8mV    725.1mV    1.132V
282ps     1.017V     758.5mV    1.14V
334ps     1.071V     941.3mV    1.155V
384ps     1.086V     1.015V     1.165V
477ps     1.096V     1.053V     1.169V
727ps     1.1V       1.06V      1.17V
3ns       1.1V       1.06V      1.17V
[Rising Waveform]
R_fixture= 50.000
V_fixture= 0.0
V_fixture_min= 0.0
V_fixture_max= 0.0
|time   V(typ)   V(min)   V(max)
0s        3.732uV    13.63uV    882.6nV
152ps     -223.6uV   57.31uV    13.64mV
199ps     2.786mV    -145uV     403.4mV
223ps     43.99mV    -241.3uV   459.8mV
262ps     333.1mV    1.069mV    485.4mV
298ps     411.2mV    29.68mV    419.3mV
340ps     427.8mV    270.4mV    402mV
370ps     432.2mV    359.8mV    400.8mV
483ps     374.4mV    401.9mV    400.4mV
3ns       374.4mV    360.1mV    400.4mV
[Falling Waveform]
R_fixture= 50.000
V_fixture= 1.100
V_fixture_min= 1.060
V_fixture_max= 1.170
|time   V(typ)   V(min)   V(max)
0s        1.1V       1.06V      1.17V
159ps     1.1V       1.06V      1.16V
224ps     1.088V     1.061V     832.5mV
273ps     877.6mV    1.057V     726.3mV
319ps     740.7mV    1.032V     783.2mV
364ps     684.4mV    888.4mV    807.2mV
417ps     723.8mV    752.8mV    817.7mV
492ps     750.9mV    681.1mV    822mV
701ps     758.5mV    737.3mV    823.3mV
3ns       758.6mV    738.8mV    823.3mV
[Falling Waveform]
R_fixture= 50.000
V_fixture= 0.0
V_fixture_min= 0.0
V_fixture_max= 0.0
|time   V(typ)   V(min)   V(max)
0s        374.4mV    360.1mV    400.4mV
144ps     373.7mV    359.5mV    410.4mV
196ps     389.8mV    360.2mV    104.3mV
211ps     344.2mV    364.5mV    63.22mV
257ps     96.88mV    383mV      13.93mV
291ps     34.6mV     270.9mV    1.377mV
329ps     11.58mV    115.4mV    336.9uV
355ps     5.454mV    54.7mV     177.1uV
465ps     -127.4uV   3.462mV    8.159uV
3ns       3.469uV    13.53uV    -2.1uV
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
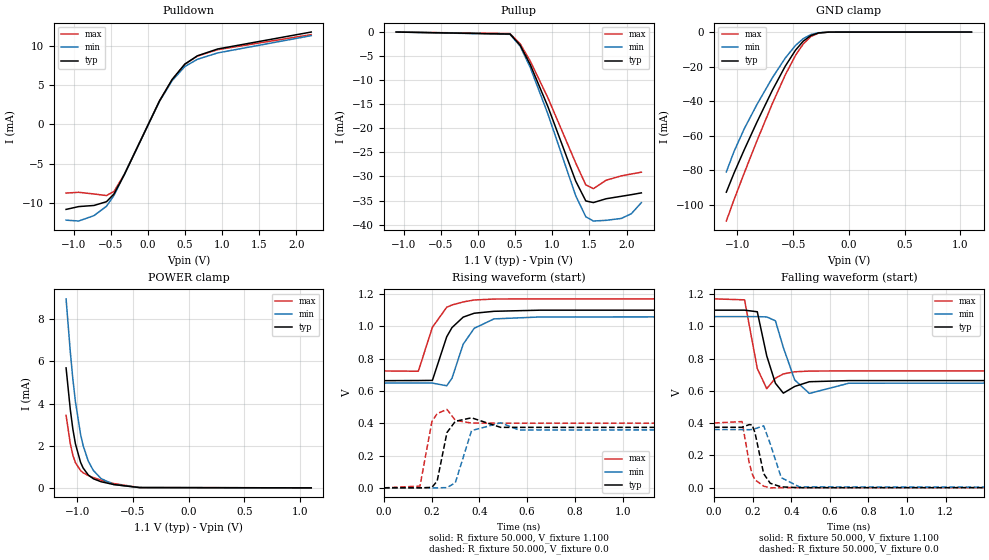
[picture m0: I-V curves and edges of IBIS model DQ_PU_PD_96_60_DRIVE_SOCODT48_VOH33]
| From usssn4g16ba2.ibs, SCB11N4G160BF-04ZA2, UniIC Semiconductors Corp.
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|   Model DQ_PU_PD_96_60_DRIVE_SOCODT48_VOH33
[Model] DQ_PU_PD_96_60_DRIVE_SOCODT48_VOH33
Model_type I/O
Polarity   Inverting
Vinl =  98.000mV
Vinh =  0.268V
Vmeas =  0.183V
Rref =  50.000
Vref =  0.183V
C_comp   1.020pF   1.010pF   1.030pF
[Model Spec]
Vinh   0.268V   0.262V   0.280V
Vinl   98.000mV   92.000mV   0.110V
Vmeas   0.183V   0.177V   0.195V
Vref   0.183V   0.177V   0.195V
Rref   50.000   NA   NA
[Temperature Range]   25.000   0.105k   -40.000
[Voltage Range]   1.100V   1.060V   1.170V
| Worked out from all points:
|   slope of the pulldown table from 0 to 0.165 V, typ, clamps not added: 52.7 ohm
|   GND clamp passes 1 mA (typ) near -0.30 V on its own axis
|   POWER clamp passes 1 mA (typ) near -0.95 V on its own axis
|   rising waveform, R_fixture 50.000, V_fixture 1.100: 20-80 % time 72.7ps typ, 74.8ps min, 70.8ps max; typ from 0.663 V to 1.1 V
|   rising waveform, R_fixture 50.000, V_fixture 0.0: 20-80 % time 27.6ps typ, 36.1ps min, 22.6ps max; typ from 0 V to 0.374 V
|   falling waveform, R_fixture 50.000, V_fixture 1.100: 20-80 % time 44.3ps typ, 58.3ps min, 35.3ps max; typ from 1.1 V to 0.663 V
|   falling waveform, R_fixture 50.000, V_fixture 0.0: 20-80 % time 41.7ps typ, 56.1ps min, 37.2ps max; typ from 0.374 V to 0 V
[Pulldown]
|Voltage   I(typ)   I(min)   I(max)
-1.1V     -10.83mA   -12.2mA    -8.746mA
-930mV    -10.47mA   -12.31mA   -8.649mA
-726mV    -10.33mA   -11.63mA   -8.863mA
-556mV    -9.849mA   -10.43mA   -9.063mA
-454mV    -8.849mA   -9.016mA   -8.534mA
-318mV    -6.436mA   -6.433mA   -6.383mA
158mV     3.005mA    2.954mA    3.019mA
328mV     5.729mA    5.586mA    5.734mA
498mV     7.686mA    7.379mA    7.672mA
668mV     8.751mA    8.306mA    8.715mA
940mV     9.618mA    9.116mA    9.532mA
2.2V      11.78mA    11.32mA    11.45mA
[Pullup]
|Voltage   I(typ)   I(min)   I(max)
-1.1V     2.6nA      27.46nA    0A
432mV     -421.9uA   -476.8uA   -329.3uA
568mV     -2.729mA   -2.923mA   -2.437mA
704mV     -6.762mA   -7.352mA   -6.026mA
942mV     -15.5mA    -17.03mA   -13.67mA
1.316V    -30.95mA   -34mA      -27.19mA
1.452V    -35.08mA   -38.36mA   -31.74mA
1.554V    -35.42mA   -39.25mA   -32.53mA
1.724V    -34.63mA   -39.11mA   -30.79mA
1.928V    -34.12mA   -38.72mA   -29.88mA
2.064V    -33.78mA   -37.75mA   -29.49mA
2.2V      -33.41mA   -35.44mA   -29.11mA
[GND_clamp]
|Voltage   I(typ)   I(min)   I(max)
-1.1V     -92.78mA   -81.05mA   -109.5mA
-1.031V   -81.73mA   -69.22mA   -97.17mA
-939mV    -68.18mA   -56.02mA   -81.64mA
-824mV    -52mA      -41.83mA   -62.83mA
-686mV    -33.62mA   -26.41mA   -41.32mA
-571mV    -19.76mA   -15.06mA   -24.85mA
-479mV    -10.5mA    -7.76mA    -13.5mA
-410mV    -5.313mA   -3.84mA    -6.916mA
-341mV    -2.007mA   -1.45mA    -2.59mA
-272mV    -506.9uA   -403.5uA   -609.8uA
-180mV    -45.65uA   -51.35uA   -43.55uA
1.1V      0A         0A         0A
[POWER_clamp]
|Voltage   I(typ)   I(min)   I(max)
-1.1V     5.691mA    8.967mA    3.44mA
-1.062V   3.709mA    6.444mA    2.092mA
-1.039V   2.781mA    5.152mA    1.546mA
-1.016V   2.086mA    4.085mA    1.193mA
-970mV    1.21mA     2.539mA    818.5uA
-947mV    943.7uA    2.005mA    716.7uA
-901mV    610.1uA    1.27mA     581.3uA
-855mV    430.7uA    824.1uA    484.6uA
-786mV    289.9uA    439.4uA    366uA
-671mV    155.9uA    155.9uA    203.6uA
-441mV    13.2uA     12.79uA    15.03uA
1.1V      0A         0A         0A
[Ramp]
| variable   typ   min   max
dV/dt_r   0.225/27.841p   0.216/36.440p   0.240/22.786p
dV/dt_f   0.262/44.436p   0.247/58.444p   0.268/35.302p
R_load = 50.000
[Rising Waveform]
R_fixture= 50.000
V_fixture= 1.100
V_fixture_min= 1.060
V_fixture_max= 1.170
|time   V(typ)   V(min)   V(max)
0s        663.5mV    648.6mV    723.5mV
144ps     664.4mV    649.1mV    722mV
203ps     665.2mV    648.5mV    994.1mV
263ps     935.3mV    632mV      1.118V
285ps     992mV      678.2mV    1.132V
332ps     1.057V     889mV      1.151V
378ps     1.081V     987.4mV    1.163V
461ps     1.093V     1.046V     1.169V
655ps     1.1V       1.058V     1.17V
3ns       1.1V       1.06V      1.17V
[Rising Waveform]
R_fixture= 50.000
V_fixture= 0.0
V_fixture_min= 0.0
V_fixture_max= 0.0
|time   V(typ)   V(min)   V(max)
0s        3.262uV    11.92uV    771.1nV
151ps     -144.6uV   53.98uV    10.85mV
201ps     2.893mV    -103.8uV   410.9mV
223ps     42.11mV    -98.12uV   459.8mV
264ps     342.1mV    1.298mV    485.6mV
299ps     411.9mV    30.96mV    418.2mV
367ps     433.5mV    354.1mV    400.8mV
489ps     374.4mV    402.6mV    400.4mV
565ps     374.4mV    358.3mV    400.4mV
3ns       374.4mV    360.1mV    400.4mV
[Falling Waveform]
R_fixture= 50.000
V_fixture= 1.100
V_fixture_min= 1.060
V_fixture_max= 1.170
|time   V(typ)   V(min)   V(max)
0s        1.1V       1.06V      1.17V
158ps     1.1V       1.06V      1.164V
224ps     1.09V      1.06V      738.2mV
273ps     816.6mV    1.058V     613mV
318ps     646.8mV    1.034V     678.2mV
359ps     585.5mV    868.7mV    704.7mV
418ps     627.1mV    667.2mV    718mV
494ps     656.3mV    583.7mV    722.4mV
699ps     663.3mV    647.1mV    723.5mV
3ns       663.5mV    648.6mV    723.5mV
[Falling Waveform]
R_fixture= 50.000
V_fixture= 0.0
V_fixture_min= 0.0
V_fixture_max= 0.0
|time   V(typ)   V(min)   V(max)
0s        374.4mV    360.1mV    400.4mV
145ps     373.8mV    359.4mV    409.2mV
182ps     390.4mV    358.9mV    154.7mV
197ps     389.2mV    360.4mV    86mV
212ps     340.9mV    364.9mV    48.44mV
257ps     86.58mV    382.9mV    8.921mV
291ps     26.94mV    272.3mV    -1.573mV
348ps     4.465mV    61.81mV    -299.2uV
442ps     -674.5uV   4.343mV    -9.6uV
3ns       1.985uV    11.9uV     62.5nV
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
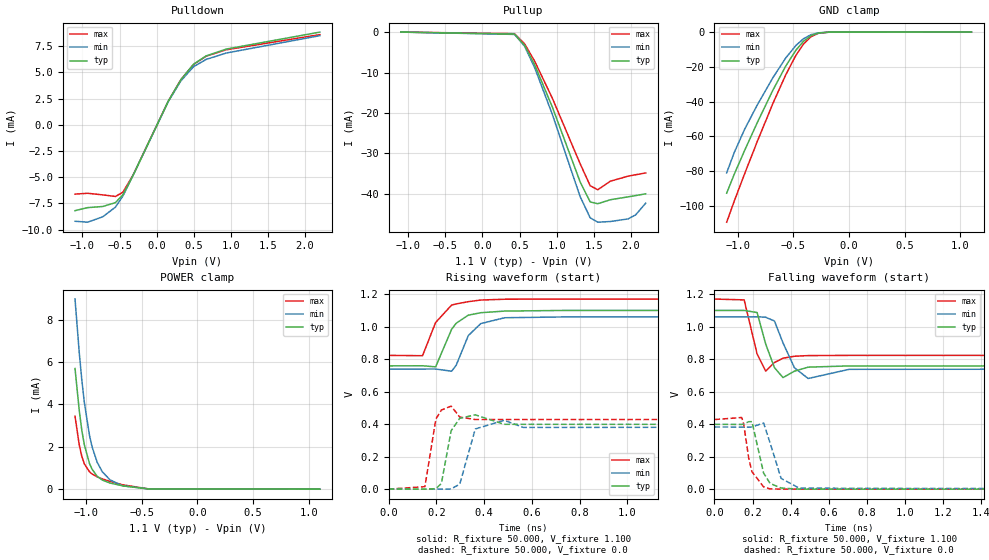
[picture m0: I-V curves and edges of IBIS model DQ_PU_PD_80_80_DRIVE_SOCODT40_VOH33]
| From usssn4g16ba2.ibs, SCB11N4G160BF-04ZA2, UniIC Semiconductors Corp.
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|   Model DQ_PU_PD_80_80_DRIVE_SOCODT40_VOH33
[Model] DQ_PU_PD_80_80_DRIVE_SOCODT40_VOH33
Model_type I/O
Polarity   Inverting
Vinl =  98.000mV
Vinh =  0.268V
Vmeas =  0.183V
Rref =  50.000
Vref =  0.183V
C_comp   1.020pF   1.010pF   1.030pF
[Model Spec]
Vinh   0.268V   0.262V   0.280V
Vinl   98.000mV   92.000mV   0.110V
Vmeas   0.183V   0.177V   0.195V
Vref   0.183V   0.177V   0.195V
Rref   50.000   NA   NA
[Temperature Range]   25.000   0.105k   -40.000
[Voltage Range]   1.100V   1.060V   1.170V
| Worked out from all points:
|   slope of the pulldown table from 0 to 0.165 V, typ, clamps not added: 70.2 ohm
|   GND clamp passes 1 mA (typ) near -0.30 V on its own axis
|   POWER clamp passes 1 mA (typ) near -0.95 V on its own axis
|   rising waveform, R_fixture 50.000, V_fixture 1.100: 20-80 % time 69.3ps typ, 69.5ps min, 68.6ps max; typ from 0.759 V to 1.1 V
|   rising waveform, R_fixture 50.000, V_fixture 0.0: 20-80 % time 26.8ps typ, 35.7ps min, 21.8ps max; typ from 0 V to 0.399 V
|   falling waveform, R_fixture 50.000, V_fixture 1.100: 20-80 % time 45.5ps typ, 60.4ps min, 36ps max; typ from 1.1 V to 0.759 V
|   falling waveform, R_fixture 50.000, V_fixture 0.0: 20-80 % time 46ps typ, 57.3ps min, 42.3ps max; typ from 0.399 V to 0 V
[Pulldown]
|Voltage   I(typ)   I(min)   I(max)
-1.1V     -8.193mA   -9.206mA   -6.618mA
-930mV    -7.906mA   -9.295mA   -6.537mA
-726mV    -7.797mA   -8.78mA    -6.691mA
-556mV    -7.432mA   -7.863mA   -6.841mA
-454mV    -6.673mA   -6.794mA   -6.44mA
-318mV    -4.841mA   -4.838mA   -4.804mA
158mV     2.257mA    2.219mA    2.267mA
328mV     4.302mA    4.194mA    4.305mA
498mV     5.77mA     5.539mA    5.759mA
668mV     6.567mA    6.233mA    6.54mA
940mV     7.217mA    6.841mA    7.152mA
2.2V      8.836mA    8.496mA    8.595mA
[Pullup]
|Voltage   I(typ)   I(min)   I(max)
-1.1V     3.1nA      32.98nA    0A
432mV     -506.1uA   -571.8uA   -395uA
568mV     -3.269mA   -3.501mA   -2.92mA
704mV     -8.095mA   -8.8mA     -7.217mA
942mV     -18.54mA   -20.37mA   -16.36mA
1.316V    -37.03mA   -40.67mA   -32.54mA
1.452V    -42.01mA   -45.93mA   -38mA
1.554V    -42.45mA   -47.02mA   -39mA
1.724V    -41.47mA   -46.85mA   -36.88mA
1.962V    -40.75mA   -46.21mA   -35.64mA
2.064V    -40.44mA   -45.22mA   -35.29mA
2.2V      -40mA      -42.32mA   -34.84mA
[GND_clamp]
|Voltage   I(typ)   I(min)   I(max)
-1.1V     -92.78mA   -81.05mA   -109.5mA
-1.031V   -81.73mA   -69.22mA   -97.17mA
-939mV    -68.18mA   -56.02mA   -81.64mA
-824mV    -52mA      -41.83mA   -62.83mA
-686mV    -33.62mA   -26.41mA   -41.32mA
-571mV    -19.76mA   -15.06mA   -24.85mA
-479mV    -10.5mA    -7.76mA    -13.5mA
-410mV    -5.313mA   -3.84mA    -6.916mA
-341mV    -2.007mA   -1.45mA    -2.59mA
-272mV    -506.9uA   -403.5uA   -609.8uA
-180mV    -45.65uA   -51.35uA   -43.55uA
1.1V      0A         0A         0A
[POWER_clamp]
|Voltage   I(typ)   I(min)   I(max)
-1.1V     5.691mA    8.967mA    3.44mA
-1.062V   3.709mA    6.444mA    2.092mA
-1.039V   2.781mA    5.152mA    1.546mA
-1.016V   2.086mA    4.085mA    1.193mA
-970mV    1.21mA     2.539mA    818.5uA
-947mV    943.7uA    2.005mA    716.7uA
-901mV    610.1uA    1.27mA     581.3uA
-855mV    430.7uA    824.1uA    484.6uA
-786mV    289.9uA    439.4uA    366uA
-671mV    155.9uA    155.9uA    203.6uA
-441mV    13.2uA     12.79uA    15.03uA
1.1V      0A         0A         0A
[Ramp]
| variable   typ   min   max
dV/dt_r   0.239/27.012p   0.230/35.769p   0.257/22.087p
dV/dt_f   0.205/45.575p   0.193/60.409p   0.208/36.053p
R_load = 50.000
[Rising Waveform]
R_fixture= 50.000
V_fixture= 1.100
V_fixture_min= 1.060
V_fixture_max= 1.170
|time   V(typ)   V(min)   V(max)
0s        758.6mV    738.8mV    823.3mV
142ps     759.4mV    739.2mV    821.3mV
197ps     752.6mV    739.3mV    1.026V
264ps     984.3mV    725.8mV    1.133V
283ps     1.021V     762.7mV    1.14V
334ps     1.071V     945.5mV    1.154V
386ps     1.086V     1.019V     1.164V
486ps     1.096V     1.055V     1.169V
735ps     1.1V       1.06V      1.17V
3ns       1.1V       1.06V      1.17V
[Rising Waveform]
R_fixture= 50.000
V_fixture= 0.0
V_fixture_min= 0.0
V_fixture_max= 0.0
|time   V(typ)   V(min)   V(max)
0s        3.732uV    13.63uV    882.6nV
152ps     -283.2uV   65.56uV    15.01mV
198ps     2.792mV    -165.4uV   431.5mV
221ps     34.78mV    -332.9uV   486.6mV
262ps     359.6mV    975.4uV    511.3mV
298ps     436mV      30.99mV    443.2mV
363ps     457.4mV    370.3mV    428.4mV
484ps     398.9mV    423.5mV    428.3mV
564ps     398.9mV    379.8mV    428.3mV
3ns       398.9mV    382.6mV    428.3mV
[Falling Waveform]
R_fixture= 50.000
V_fixture= 1.100
V_fixture_min= 1.060
V_fixture_max= 1.170
|time   V(typ)   V(min)   V(max)
0s        1.1V       1.06V      1.17V
156ps     1.1V       1.06V      1.165V
224ps     1.087V     1.061V     831.8mV
269ps     893.6mV    1.058V     726.5mV
315ps     747.9mV    1.035V     779.5mV
360ps     686.6mV    900.1mV    805.8mV
420ps     726.1mV    747.3mV    818mV
492ps     750.9mV    680.9mV    822mV
707ps     758.5mV    737.5mV    823.3mV
3ns       758.6mV    738.8mV    823.3mV
[Falling Waveform]
R_fixture= 50.000
V_fixture= 0.0
V_fixture_min= 0.0
V_fixture_max= 0.0
|time   V(typ)   V(min)   V(max)
0s        398.9mV    382.6mV    428.3mV
143ps     398.1mV    381.9mV    440.9mV
153ps     400.3mV    381.6mV    405.2mV
180ps     415.2mV    381.2mV    190.4mV
197ps     415.2mV    382.8mV    106.9mV
258ps     99.28mV    407mV      14.23mV
292ps     35.41mV    285.1mV    1.519mV
350ps     6.727mV    66.35mV    251.6uV
445ps     -253.6uV   5.777mV    16.71uV
3ns       3.47uV     13.5uV     502.5nV
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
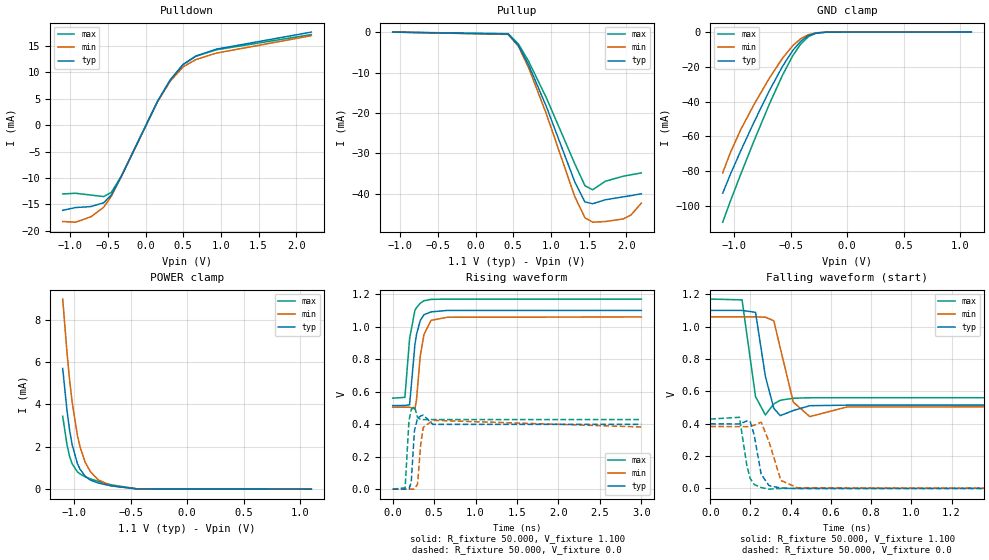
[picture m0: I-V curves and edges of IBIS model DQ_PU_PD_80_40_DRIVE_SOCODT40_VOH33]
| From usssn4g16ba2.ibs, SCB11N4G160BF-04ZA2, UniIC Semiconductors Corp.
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|   Model DQ_PU_PD_80_40_DRIVE_SOCODT40_VOH33
[Model] DQ_PU_PD_80_40_DRIVE_SOCODT40_VOH33
Model_type I/O
Polarity   Inverting
Vinl =  98.000mV
Vinh =  0.268V
Vmeas =  0.183V
Rref =  50.000
Vref =  0.183V
C_comp   1.020pF   1.010pF   1.030pF
[Model Spec]
Vinh   0.268V   0.262V   0.280V
Vinl   98.000mV   92.000mV   0.110V
Vmeas   0.183V   0.177V   0.195V
Vref   0.183V   0.177V   0.195V
Rref   50.000   NA   NA
[Temperature Range]   25.000   0.105k   -40.000
[Voltage Range]   1.100V   1.060V   1.170V
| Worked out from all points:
|   slope of the pulldown table from 0 to 0.165 V, typ, clamps not added: 35.3 ohm
|   GND clamp passes 1 mA (typ) near -0.30 V on its own axis
|   POWER clamp passes 1 mA (typ) near -0.95 V on its own axis
|   rising waveform, R_fixture 50.000, V_fixture 1.100: 20-80 % time 75ps typ, 77.3ps min, 72.8ps max; typ from 0.514 V to 1.1 V
|   rising waveform, R_fixture 50.000, V_fixture 0.0: 20-80 % time 26.6ps typ, 35.1ps min, 21.7ps max; typ from 0 V to 0.399 V
|   falling waveform, R_fixture 50.000, V_fixture 1.100: 20-80 % time 41.2ps typ, 54.7ps min, 33.6ps max; typ from 1.1 V to 0.514 V
|   falling waveform, R_fixture 50.000, V_fixture 0.0: 20-80 % time 35ps typ, 51.8ps min, 30.1ps max; typ from 0.399 V to 0 V
[Pulldown]
|Voltage   I(typ)   I(min)   I(max)
-1.1V     -16.13mA   -18.25mA   -13.03mA
-930mV    -15.61mA   -18.38mA   -12.9mA
-726mV    -15.42mA   -17.36mA   -13.24mA
-556mV    -14.7mA    -15.55mA   -13.53mA
-454mV    -13.2mA    -13.45mA   -12.73mA
-318mV    -9.609mA   -9.606mA   -9.529mA
158mV     4.492mA    4.415mA    4.512mA
328mV     8.568mA    8.352mA    8.576mA
498mV     11.5mA     11.04mA    11.48mA
668mV     13.1mA     12.43mA    13.05mA
940mV     14.4mA     13.65mA    14.28mA
2.2V      17.63mA    16.95mA    17.16mA
[Pullup]
|Voltage   I(typ)   I(min)   I(max)
-1.1V     3.1nA      32.98nA    0A
432mV     -506.1uA   -571.8uA   -395uA
568mV     -3.269mA   -3.501mA   -2.92mA
704mV     -8.095mA   -8.8mA     -7.217mA
942mV     -18.54mA   -20.37mA   -16.36mA
1.316V    -37.03mA   -40.67mA   -32.54mA
1.452V    -42.01mA   -45.93mA   -38mA
1.554V    -42.45mA   -47.02mA   -39mA
1.724V    -41.47mA   -46.85mA   -36.88mA
1.962V    -40.75mA   -46.21mA   -35.64mA
2.064V    -40.44mA   -45.22mA   -35.29mA
2.2V      -40mA      -42.32mA   -34.84mA
[GND_clamp]
|Voltage   I(typ)   I(min)   I(max)
-1.1V     -92.78mA   -81.05mA   -109.5mA
-1.031V   -81.73mA   -69.22mA   -97.17mA
-939mV    -68.18mA   -56.02mA   -81.64mA
-824mV    -52mA      -41.83mA   -62.83mA
-686mV    -33.62mA   -26.41mA   -41.32mA
-571mV    -19.76mA   -15.06mA   -24.85mA
-479mV    -10.5mA    -7.76mA    -13.5mA
-410mV    -5.313mA   -3.84mA    -6.916mA
-341mV    -2.007mA   -1.45mA    -2.59mA
-272mV    -506.9uA   -403.5uA   -609.8uA
-180mV    -45.65uA   -51.35uA   -43.55uA
1.1V      0A         0A         0A
[POWER_clamp]
|Voltage   I(typ)   I(min)   I(max)
-1.1V     5.691mA    8.967mA    3.44mA
-1.062V   3.709mA    6.444mA    2.092mA
-1.039V   2.781mA    5.152mA    1.546mA
-1.016V   2.086mA    4.085mA    1.193mA
-970mV    1.21mA     2.539mA    818.5uA
-947mV    943.7uA    2.005mA    716.7uA
-901mV    610.1uA    1.27mA     581.3uA
-855mV    430.7uA    824.1uA    484.6uA
-786mV    289.9uA    439.4uA    366uA
-671mV    155.9uA    155.9uA    203.6uA
-441mV    13.2uA     12.79uA    15.03uA
1.1V      0A         0A         0A
[Ramp]
| variable   typ   min   max
dV/dt_r   0.239/26.699p   0.230/35.167p   0.257/21.866p
dV/dt_f   0.351/41.147p   0.333/54.685p   0.366/33.664p
R_load = 50.000
[Rising Waveform]
R_fixture= 50.000
V_fixture= 1.100
V_fixture_min= 1.060
V_fixture_max= 1.170
|time   V(typ)   V(min)   V(max)
0s        514.4mV    504.3mV    560.3mV
147ps     515.1mV    504.9mV    564.9mV
204ps     519.5mV    504.1mV    927.4mV
268ps     890.3mV    492.9mV    1.101V
287ps     952mV      548.8mV    1.117V
332ps     1.038V     818.2mV    1.144V
378ps     1.074V     953.3mV    1.16V
463ps     1.091V     1.039V     1.168V
658ps     1.1V       1.058V     1.17V
3ns       1.1V       1.06V      1.17V
[Rising Waveform]
R_fixture= 50.000
V_fixture= 0.0
V_fixture_min= 0.0
V_fixture_max= 0.0
|time   V(typ)   V(min)   V(max)
0s        2.608uV    9.548uV    616.3nV
150ps     -51.96uV   55.79uV    8.502mV
196ps     1.456mV    -4.783uV   421.1mV
223ps     39.9mV     84.18uV    488.2mV
262ps     358.1mV    700uV      511.2mV
300ps     437mV      31.62mV    440.6mV
338ps     450.1mV    276.1mV    428.8mV
369ps     456.3mV    380.5mV    428.3mV
484ps     398.9mV    423.5mV    428.3mV
3ns       398.9mV    382.6mV    428.3mV
[Falling Waveform]
R_fixture= 50.000
V_fixture= 1.100
V_fixture_min= 1.060
V_fixture_max= 1.170
|time   V(typ)   V(min)   V(max)
0s        1.1V       1.06V      1.17V
158ps     1.1V       1.06V      1.165V
225ps     1.088V     1.06V      567.4mV
274ps     692mV      1.058V     453.9mV
316ps     494.8mV    1.036V     522.2mV
348ps     449.5mV    867.8mV    544.6mV
413ps     481.4mV    532.9mV    557.3mV
495ps     511mV      443.5mV    559.9mV
680ps     514.4mV    503.3mV    560.3mV
3ns       514.4mV    504.3mV    560.3mV
[Falling Waveform]
R_fixture= 50.000
V_fixture= 0.0
V_fixture_min= 0.0
V_fixture_max= 0.0
|time   V(typ)   V(min)   V(max)
0s        398.9mV    382.6mV    428.3mV
145ps     398.2mV    381.8mV    439.3mV
182ps     416.4mV    381.2mV    140.4mV
198ps     415.3mV    382.9mV    62.99mV
218ps     332.3mV    390.2mV    24.32mV
253ps     87.41mV    408.9mV    5.19mV
292ps     17.15mV    289.5mV    -4.817mV
351ps     2.186mV    49.24mV    -457.8uV
434ps     -1.362mV   3.467mV    -12.04uV
3ns       2.472uV    9.44uV     446.3nV
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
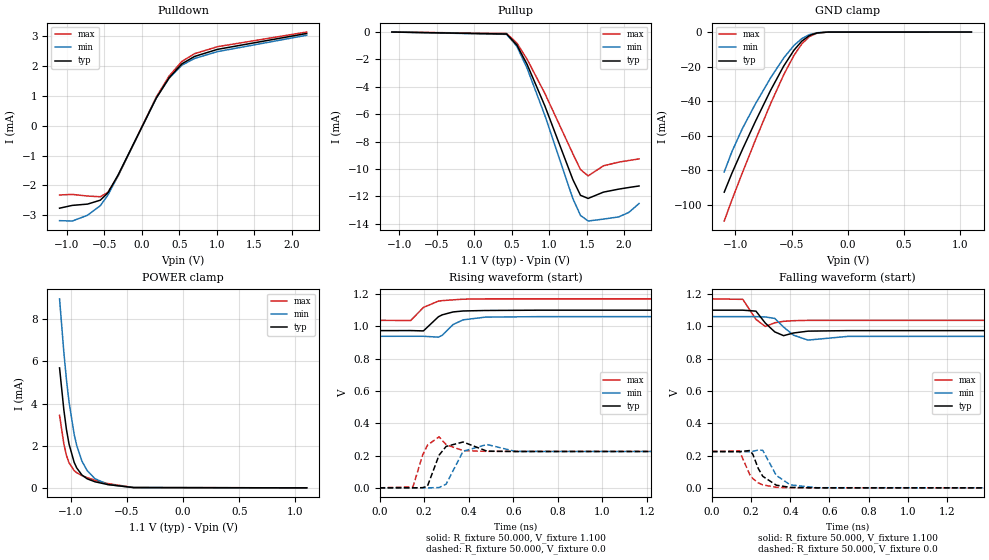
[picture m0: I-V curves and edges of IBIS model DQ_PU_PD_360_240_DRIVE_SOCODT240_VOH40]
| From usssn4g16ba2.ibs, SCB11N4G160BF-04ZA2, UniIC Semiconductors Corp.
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|   Model DQ_PU_PD_360_240_DRIVE_SOCODT240_VOH40
[Model] DQ_PU_PD_360_240_DRIVE_SOCODT240_VOH40
Model_type I/O
Polarity   Inverting
Vinl =  0.135V
Vinh =  0.305V
Vmeas =  0.220V
Rref =  50.000
Vref =  0.220V
C_comp   1.020pF   1.010pF   1.030pF
[Model Spec]
Vinh   0.305V   0.297V   0.319V
Vinl   0.135V   0.127V   0.149V
Vmeas   0.220V   0.212V   0.234V
Vref   0.220V   0.212V   0.234V
Rref   50.000   NA   NA
[Temperature Range]   25.000   0.105k   -40.000
[Voltage Range]   1.100V   1.060V   1.170V
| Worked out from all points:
|   slope of the pulldown table from 0 to 0.165 V, typ, clamps not added: 205 ohm
|   GND clamp passes 1 mA (typ) near -0.30 V on its own axis
|   POWER clamp passes 1 mA (typ) near -0.95 V on its own axis
|   rising waveform, R_fixture 50.000, V_fixture 1.100: 20-80 % time 68.4ps typ, 70.2ps min, 68.1ps max; typ from 0.973 V to 1.1 V
|   rising waveform, R_fixture 50.000, V_fixture 0.0: 20-80 % time 32.3ps typ, 41ps min, 25.5ps max; typ from 0 V to 0.225 V
|   falling waveform, R_fixture 50.000, V_fixture 1.100: 20-80 % time 47.2ps typ, 60.4ps min, 37.6ps max; typ from 1.1 V to 0.973 V
|   falling waveform, R_fixture 50.000, V_fixture 0.0: 20-80 % time 63.1ps typ, 70.5ps min, 60.5ps max; typ from 0.225 V to 0 V
[Pulldown]
|Voltage   I(typ)   I(min)   I(max)
-1.1V     -2.76mA    -3.177mA   -2.318mA
-930mV    -2.666mA   -3.189mA   -2.299mA
-726mV    -2.623mA   -2.996mA   -2.354mA
-556mV    -2.492mA   -2.677mA   -2.377mA
-454mV    -2.244mA   -2.321mA   -2.229mA
-318mV    -1.646mA   -1.668mA   -1.68mA
192mV     927.8uA    924.2uA    960.8uA
362mV     1.601mA    1.585mA    1.659mA
532mV     2.068mA    2.023mA    2.148mA
702mV     2.317mA    2.249mA    2.409mA
1.008V    2.554mA    2.478mA    2.643mA
2.2V      3.086mA    3.027mA    3.134mA
[Pullup]
|Voltage   I(typ)   I(min)   I(max)
-1.1V     900pA      9.618nA    0A
432mV     -147.1uA   -170.1uA   -107.3uA
568mV     -948.7uA   -1.043mA   -800.9uA
704mV     -2.351mA   -2.626mA   -1.98mA
942mV     -5.394mA   -6.093mA   -4.481mA
1.316V    -10.78mA   -12.17mA   -8.894mA
1.418V    -11.93mA   -13.4mA    -10.05mA
1.52V     -12.16mA   -13.81mA   -10.51mA
1.724V    -11.7mA    -13.67mA   -9.778mA
1.928V    -11.48mA   -13.51mA   -9.507mA
2.064V    -11.36mA   -13.18mA   -9.389mA
2.2V      -11.25mA   -12.53mA   -9.27mA
[GND_clamp]
|Voltage   I(typ)   I(min)   I(max)
-1.1V     -92.78mA   -81.05mA   -109.5mA
-1.031V   -81.73mA   -69.22mA   -97.17mA
-939mV    -68.18mA   -56.02mA   -81.64mA
-824mV    -52mA      -41.83mA   -62.83mA
-686mV    -33.62mA   -26.41mA   -41.32mA
-571mV    -19.76mA   -15.06mA   -24.85mA
-479mV    -10.5mA    -7.76mA    -13.5mA
-410mV    -5.313mA   -3.84mA    -6.916mA
-341mV    -2.007mA   -1.45mA    -2.59mA
-272mV    -506.9uA   -403.5uA   -609.8uA
-180mV    -45.65uA   -51.35uA   -43.55uA
1.1V      0A         0A         0A
[POWER_clamp]
|Voltage   I(typ)   I(min)   I(max)
-1.1V     5.691mA    8.967mA    3.44mA
-1.062V   3.709mA    6.444mA    2.092mA
-1.039V   2.781mA    5.152mA    1.546mA
-1.016V   2.086mA    4.085mA    1.193mA
-970mV    1.21mA     2.539mA    818.5uA
-947mV    943.7uA    2.005mA    716.7uA
-901mV    610.1uA    1.27mA     581.3uA
-855mV    430.7uA    824.1uA    484.6uA
-786mV    289.9uA    439.4uA    366uA
-671mV    155.9uA    155.9uA    203.6uA
-441mV    13.2uA     12.79uA    15.03uA
1.1V      0A         0A         0A
[Ramp]
| variable   typ   min   max
dV/dt_r   0.135/32.421p   0.134/41.155p   0.135/25.787p
dV/dt_f   75.974m/47.303p   73.034m/60.379p   79.780m/37.576p
R_load = 50.000
[Rising Waveform]
R_fixture= 50.000
V_fixture= 1.100
V_fixture_min= 1.060
V_fixture_max= 1.170
|time   V(typ)   V(min)   V(max)
0s        973.4mV    938.3mV    1.037V
140ps     973.7mV    938.4mV    1.036V
197ps     971.6mV    938.4mV    1.117V
264ps     1.059V     932.9mV    1.156V
281ps     1.071V     943.9mV    1.159V
330ps     1.089V     1.011V     1.164V
375ps     1.095V     1.04V      1.168V
475ps     1.098V     1.057V     1.17V
716ps     1.1V       1.06V      1.17V
3ns       1.1V       1.06V      1.17V
[Rising Waveform]
R_fixture= 50.000
V_fixture= 0.0
V_fixture_min= 0.0
V_fixture_max= 0.0
|time   V(typ)   V(min)   V(max)
0s        5.206uV    18.91uV    1.226uV
150ps     -117.6uV   55.69uV    5.972mV
193ps     979.9uV    -47.44uV   201.6mV
215ps     10.25mV    -137.7uV   264.2mV
267ps     202mV      1.585mV    315.6mV
299ps     256.5mV    23.06mV    267.2mV
375ps     283.8mV    226.3mV    230.3mV
482ps     227.1mV    268.4mV    225.7mV
610ps     224.8mV    225.4mV    225.5mV
3ns       224.7mV    224.1mV    225.5mV
[Falling Waveform]
R_fixture= 50.000
V_fixture= 1.100
V_fixture_min= 1.060
V_fixture_max= 1.170
|time   V(typ)   V(min)   V(max)
0s        1.1V       1.06V      1.17V
158ps     1.1V       1.06V      1.167V
225ps     1.094V     1.06V      1.043V
273ps     1.02V      1.058V     998.9mV
321ps     965.7mV    1.049V     1.022V
366ps     942.2mV    995.5mV    1.031V
417ps     958.8mV    945.1mV    1.035V
491ps     970.2mV    914.8mV    1.037V
694ps     973.3mV    937.7mV    1.037V
3ns       973.4mV    938.3mV    1.037V
[Falling Waveform]
R_fixture= 50.000
V_fixture= 0.0
V_fixture_min= 0.0
V_fixture_max= 0.0
|time   V(typ)   V(min)   V(max)
0s        224.7mV    224.1mV    225.5mV
140ps     224.3mV    223.8mV    229.2mV
194ps     231.1mV    224.1mV    81.2mV
209ps     207.9mV    226.2mV    57.73mV
237ps     119.5mV    234.1mV    30.65mV
260ps     71.33mV    231.9mV    18.08mV
329ps     16.48mV    76.84mV    3.432mV
400ps     2.845mV    18.58mV    737.8uV
535ps     189.7uV    750.3uV    40.25uV
3ns       5.228uV    18.92uV    1.258uV
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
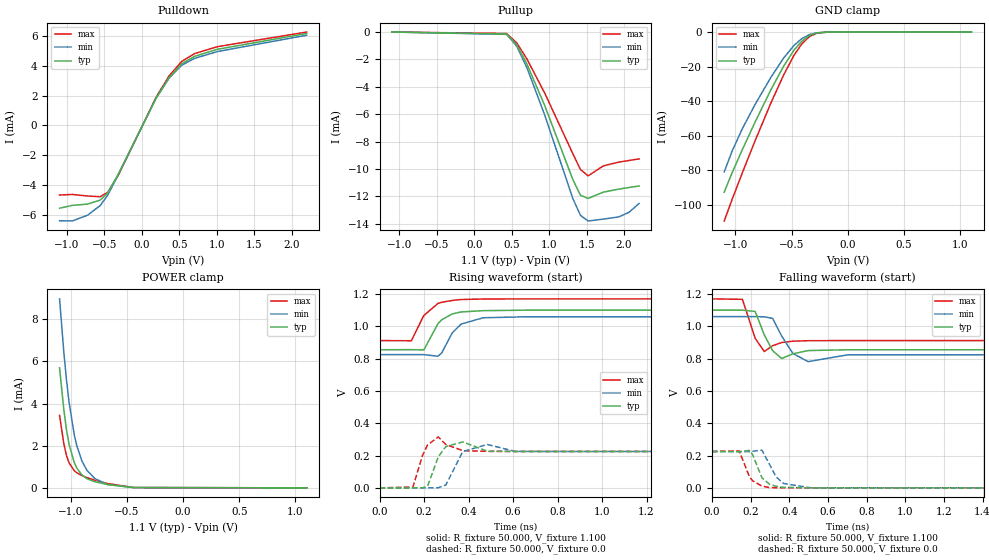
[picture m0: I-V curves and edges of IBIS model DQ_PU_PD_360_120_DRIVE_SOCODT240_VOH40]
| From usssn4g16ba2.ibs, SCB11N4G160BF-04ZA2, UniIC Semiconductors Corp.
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|   Model DQ_PU_PD_360_120_DRIVE_SOCODT240_VOH40
[Model] DQ_PU_PD_360_120_DRIVE_SOCODT240_VOH40
Model_type I/O
Polarity   Inverting
Vinl =  0.135V
Vinh =  0.305V
Vmeas =  0.220V
Rref =  50.000
Vref =  0.220V
C_comp   1.020pF   1.010pF   1.030pF
[Model Spec]
Vinh   0.305V   0.297V   0.319V
Vinl   0.135V   0.127V   0.149V
Vmeas   0.220V   0.212V   0.234V
Vref   0.220V   0.212V   0.234V
Rref   50.000   NA   NA
[Temperature Range]   25.000   0.105k   -40.000
[Voltage Range]   1.100V   1.060V   1.170V
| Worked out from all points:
|   slope of the pulldown table from 0 to 0.165 V, typ, clamps not added: 102 ohm
|   GND clamp passes 1 mA (typ) near -0.30 V on its own axis
|   POWER clamp passes 1 mA (typ) near -0.95 V on its own axis
|   rising waveform, R_fixture 50.000, V_fixture 1.100: 20-80 % time 70.2ps typ, 72.9ps min, 69ps max; typ from 0.855 V to 1.1 V
|   rising waveform, R_fixture 50.000, V_fixture 0.0: 20-80 % time 32.1ps typ, 40.7ps min, 25.5ps max; typ from 0 V to 0.225 V
|   falling waveform, R_fixture 50.000, V_fixture 1.100: 20-80 % time 46.1ps typ, 58.5ps min, 37.1ps max; typ from 1.1 V to 0.855 V
|   falling waveform, R_fixture 50.000, V_fixture 0.0: 20-80 % time 52.5ps typ, 63.3ps min, 49.8ps max; typ from 0.225 V to 0 V
[Pulldown]
|Voltage   I(typ)   I(min)   I(max)
-1.1V     -5.559mA   -6.398mA   -4.673mA
-930mV    -5.368mA   -6.416mA   -4.632mA
-726mV    -5.279mA   -6.025mA   -4.74mA
-556mV    -5.011mA   -5.376mA   -4.784mA
-454mV    -4.503mA   -4.653mA   -4.479mA
-318mV    -3.293mA   -3.335mA   -3.363mA
192mV     1.854mA    1.846mA    1.919mA
362mV     3.2mA      3.168mA    3.314mA
532mV     4.133mA    4.043mA    4.293mA
702mV     4.631mA    4.495mA    4.815mA
1.008V    5.105mA    4.953mA    5.282mA
2.2V      6.168mA    6.05mA     6.263mA
[Pullup]
|Voltage   I(typ)   I(min)   I(max)
-1.1V     900pA      9.618nA    0A
432mV     -147.1uA   -170.1uA   -107.3uA
568mV     -948.7uA   -1.043mA   -800.9uA
704mV     -2.351mA   -2.626mA   -1.98mA
942mV     -5.394mA   -6.093mA   -4.481mA
1.316V    -10.78mA   -12.17mA   -8.894mA
1.418V    -11.93mA   -13.4mA    -10.05mA
1.52V     -12.16mA   -13.81mA   -10.51mA
1.724V    -11.7mA    -13.67mA   -9.778mA
1.928V    -11.48mA   -13.51mA   -9.507mA
2.064V    -11.36mA   -13.18mA   -9.389mA
2.2V      -11.25mA   -12.53mA   -9.27mA
[GND_clamp]
|Voltage   I(typ)   I(min)   I(max)
-1.1V     -92.78mA   -81.05mA   -109.5mA
-1.031V   -81.73mA   -69.22mA   -97.17mA
-939mV    -68.18mA   -56.02mA   -81.64mA
-824mV    -52mA      -41.83mA   -62.83mA
-686mV    -33.62mA   -26.41mA   -41.32mA
-571mV    -19.76mA   -15.06mA   -24.85mA
-479mV    -10.5mA    -7.76mA    -13.5mA
-410mV    -5.313mA   -3.84mA    -6.916mA
-341mV    -2.007mA   -1.45mA    -2.59mA
-272mV    -506.9uA   -403.5uA   -609.8uA
-180mV    -45.65uA   -51.35uA   -43.55uA
1.1V      0A         0A         0A
[POWER_clamp]
|Voltage   I(typ)   I(min)   I(max)
-1.1V     5.691mA    8.967mA    3.44mA
-1.062V   3.709mA    6.444mA    2.092mA
-1.039V   2.781mA    5.152mA    1.546mA
-1.016V   2.086mA    4.085mA    1.193mA
-970mV    1.21mA     2.539mA    818.5uA
-947mV    943.7uA    2.005mA    716.7uA
-901mV    610.1uA    1.27mA     581.3uA
-855mV    430.7uA    824.1uA    484.6uA
-786mV    289.9uA    439.4uA    366uA
-671mV    155.9uA    155.9uA    203.6uA
-441mV    13.2uA     12.79uA    15.03uA
1.1V      0A         0A         0A
[Ramp]
| variable   typ   min   max
dV/dt_r   0.135/32.169p   0.134/40.729p   0.135/25.664p
dV/dt_f   0.147/46.132p   0.141/58.641p   0.155/37.105p
R_load = 50.000
[Rising Waveform]
R_fixture= 50.000
V_fixture= 1.100
V_fixture_min= 1.060
V_fixture_max= 1.170
|time   V(typ)   V(min)   V(max)
0s        855mV      824.7mV    911.8mV
143ps     855.5mV    825mV      910.7mV
199ps     853.8mV    824.7mV    1.067V
263ps     1.017V     814.8mV    1.142V
280ps     1.041V     836.8mV    1.149V
327ps     1.077V     959.6mV    1.16V
367ps     1.089V     1.014V     1.166V
466ps     1.097V     1.053V     1.169V
656ps     1.1V       1.059V     1.17V
3ns       1.1V       1.06V      1.17V
[Rising Waveform]
R_fixture= 50.000
V_fixture= 0.0
V_fixture_min= 0.0
V_fixture_max= 0.0
|time   V(typ)   V(min)   V(max)
0s        4.316uV    15.68uV    1.011uV
150ps     -33.57uV   45.53uV    4.76mV
193ps     595.7uV    14.44uV    200mV
216ps     9.941mV    16.54uV    265.4mV
264ps     192.2mV    617.7uV    315.3mV
298ps     255.1mV    18.12mV    268.5mV
374ps     284.5mV    224.4mV    230.4mV
484ps     227mV      268.6mV    225.7mV
611ps     224.8mV    225.3mV    225.5mV
3ns       224.7mV    224.1mV    225.5mV
[Falling Waveform]
R_fixture= 50.000
V_fixture= 1.100
V_fixture_min= 1.060
V_fixture_max= 1.170
|time   V(typ)   V(min)   V(max)
0s        1.1V       1.06V      1.17V
158ps     1.1V       1.06V      1.167V
224ps     1.092V     1.06V      925.6mV
271ps     947.2mV    1.059V     843.7mV
314ps     849.5mV    1.049V     880.1mV
361ps     800.6mV    940.2mV    899.6mV
419ps     829.9mV    831.8mV    908mV
498ps     849.9mV    781.5mV    911.1mV
703ps     854.9mV    823.7mV    911.8mV
3ns       855mV      824.7mV    911.8mV
[Falling Waveform]
R_fixture= 50.000
V_fixture= 0.0
V_fixture_min= 0.0
V_fixture_max= 0.0
|time   V(typ)   V(min)   V(max)
0s        224.7mV    224.1mV    225.5mV
141ps     224.3mV    223.8mV    229.2mV
194ps     231.9mV    224mV      69.16mV
210ps     207.3mV    226.3mV    44.06mV
259ps     62.28mV    233.1mV    11.06mV
297ps     23.23mV    147.8mV    1.846mV
332ps     9.641mV    68.15mV    751.1uV
370ps     3.085mV    27.14mV    288.7uV
511ps     17.58uV    316.2uV    8.408uV
3ns       4.212uV    15.51uV    1.054uV
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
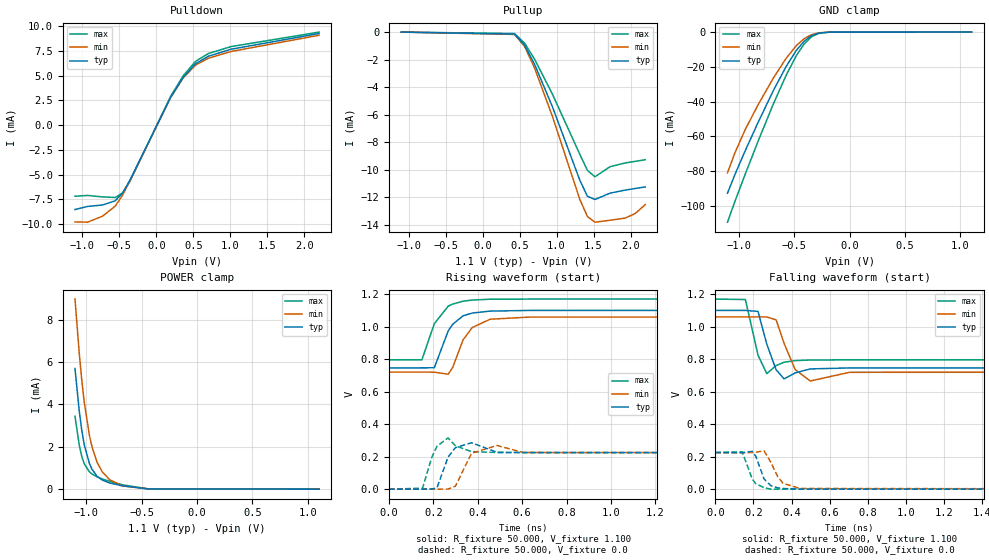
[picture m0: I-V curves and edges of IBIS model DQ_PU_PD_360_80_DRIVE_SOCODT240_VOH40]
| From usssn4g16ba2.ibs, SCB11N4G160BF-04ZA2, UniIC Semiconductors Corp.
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|   Model DQ_PU_PD_360_80_DRIVE_SOCODT240_VOH40
[Model] DQ_PU_PD_360_80_DRIVE_SOCODT240_VOH40
Model_type I/O
Polarity   Inverting
Vinl =  0.135V
Vinh =  0.305V
Vmeas =  0.220V
Rref =  50.000
Vref =  0.220V
C_comp   1.020pF   1.010pF   1.030pF
[Model Spec]
Vinh   0.305V   0.297V   0.319V
Vinl   0.135V   0.127V   0.149V
Vmeas   0.220V   0.212V   0.234V
Vref   0.220V   0.212V   0.234V
Rref   50.000   NA   NA
[Temperature Range]   25.000   0.105k   -40.000
[Voltage Range]   1.100V   1.060V   1.170V
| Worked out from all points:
|   slope of the pulldown table from 0 to 0.165 V, typ, clamps not added: 68.2 ohm
|   GND clamp passes 1 mA (typ) near -0.30 V on its own axis
|   POWER clamp passes 1 mA (typ) near -0.95 V on its own axis
|   rising waveform, R_fixture 50.000, V_fixture 1.100: 20-80 % time 72.4ps typ, 75.7ps min, 70.6ps max; typ from 0.746 V to 1.1 V
|   rising waveform, R_fixture 50.000, V_fixture 0.0: 20-80 % time 32.1ps typ, 40.6ps min, 25.8ps max; typ from 0 V to 0.225 V
|   falling waveform, R_fixture 50.000, V_fixture 1.100: 20-80 % time 45.7ps typ, 57.9ps min, 37.1ps max; typ from 1.1 V to 0.746 V
|   falling waveform, R_fixture 50.000, V_fixture 0.0: 20-80 % time 46.5ps typ, 60.3ps min, 43.6ps max; typ from 0.225 V to 0 V
[Pulldown]
|Voltage   I(typ)   I(min)   I(max)
-1.1V     -8.531mA   -9.779mA   -7.187mA
-930mV    -8.221mA   -9.809mA   -7.107mA
-726mV    -8.07mA    -9.196mA   -7.255mA
-556mV    -7.649mA   -8.186mA   -7.316mA
-454mV    -6.852mA   -7.06mA    -6.833mA
-352mV    -5.485mA   -5.559mA   -5.593mA
192mV     2.785mA    2.773mA    2.883mA
362mV     4.806mA    4.757mA    4.977mA
532mV     6.204mA    6.068mA    6.444mA
702mV     6.948mA    6.744mA    7.224mA
1.008V    7.659mA    7.43mA     7.924mA
2.2V      9.253mA    9.074mA    9.394mA
[Pullup]
|Voltage   I(typ)   I(min)   I(max)
-1.1V     900pA      9.618nA    0A
432mV     -147.1uA   -170.1uA   -107.3uA
568mV     -948.7uA   -1.043mA   -800.9uA
704mV     -2.351mA   -2.626mA   -1.98mA
942mV     -5.394mA   -6.093mA   -4.481mA
1.316V    -10.78mA   -12.17mA   -8.894mA
1.418V    -11.93mA   -13.4mA    -10.05mA
1.52V     -12.16mA   -13.81mA   -10.51mA
1.724V    -11.7mA    -13.67mA   -9.778mA
1.928V    -11.48mA   -13.51mA   -9.507mA
2.064V    -11.36mA   -13.18mA   -9.389mA
2.2V      -11.25mA   -12.53mA   -9.27mA
[GND_clamp]
|Voltage   I(typ)   I(min)   I(max)
-1.1V     -92.78mA   -81.05mA   -109.5mA
-1.031V   -81.73mA   -69.22mA   -97.17mA
-939mV    -68.18mA   -56.02mA   -81.64mA
-824mV    -52mA      -41.83mA   -62.83mA
-686mV    -33.62mA   -26.41mA   -41.32mA
-571mV    -19.76mA   -15.06mA   -24.85mA
-479mV    -10.5mA    -7.76mA    -13.5mA
-410mV    -5.313mA   -3.84mA    -6.916mA
-341mV    -2.007mA   -1.45mA    -2.59mA
-272mV    -506.9uA   -403.5uA   -609.8uA
-180mV    -45.65uA   -51.35uA   -43.55uA
1.1V      0A         0A         0A
[POWER_clamp]
|Voltage   I(typ)   I(min)   I(max)
-1.1V     5.691mA    8.967mA    3.44mA
-1.062V   3.709mA    6.444mA    2.092mA
-1.039V   2.781mA    5.152mA    1.546mA
-1.016V   2.086mA    4.085mA    1.193mA
-970mV    1.21mA     2.539mA    818.5uA
-947mV    943.7uA    2.005mA    716.7uA
-901mV    610.1uA    1.27mA     581.3uA
-855mV    430.7uA    824.1uA    484.6uA
-786mV    289.9uA    439.4uA    366uA
-671mV    155.9uA    155.9uA    203.6uA
-441mV    13.2uA     12.79uA    15.03uA
1.1V      0A         0A         0A
[Ramp]
| variable   typ   min   max
dV/dt_r   0.135/32.213p   0.134/40.574p   0.135/25.881p
dV/dt_f   0.212/45.696p   0.204/57.889p   0.225/37.254p
R_load = 50.000
[Rising Waveform]
R_fixture= 50.000
V_fixture= 1.100
V_fixture_min= 1.060
V_fixture_max= 1.170
|time   V(typ)   V(min)   V(max)
0s        746mV      720.2mV    795.6mV
148ps     746.6mV    720.7mV    795.8mV
204ps     747.4mV    720mV      1.018V
267ps     974.6mV    707.4mV    1.127V
287ps     1.015V     749.4mV    1.139V
334ps     1.067V     919.8mV    1.157V
375ps     1.084V     994.9mV    1.164V
456ps     1.096V     1.046V     1.169V
633ps     1.1V       1.059V     1.17V
3ns       1.1V       1.06V      1.17V
[Rising Waveform]
R_fixture= 50.000
V_fixture= 0.0
V_fixture_min= 0.0
V_fixture_max= 0.0
|time   V(typ)   V(min)   V(max)
0s        3.688uV    13.4uV     861.5nV
151ps     -5.239uV   31.77uV    5.857mV
192ps     678.8uV    26.82uV    193.3mV
216ps     8.79mV     121.5uV    264.2mV
266ps     196.7mV    564.5uV    315.4mV
299ps     255.6mV    18.12mV    267.1mV
372ps     285.6mV    221.2mV    230.7mV
487ps     226.8mV    268.8mV    225.7mV
605ps     224.8mV    225.6mV    225.5mV
3ns       224.7mV    224.1mV    225.5mV
[Falling Waveform]
R_fixture= 50.000
V_fixture= 1.100
V_fixture_min= 1.060
V_fixture_max= 1.170
|time   V(typ)   V(min)   V(max)
0s        1.1V       1.06V      1.17V
158ps     1.1V       1.06V      1.167V
224ps     1.094V     1.06V      825mV
270ps     892.7mV    1.06V      710.9mV
319ps     734.8mV    1.042V     760.7mV
361ps     678.2mV    896.4mV    780.9mV
419ps     715.2mV    735.7mV    791mV
498ps     739.8mV    665.2mV    794.6mV
704ps     745.9mV    718.9mV    795.5mV
3ns       746mV      720.2mV    795.6mV
[Falling Waveform]
R_fixture= 50.000
V_fixture= 0.0
V_fixture_min= 0.0
V_fixture_max= 0.0
|time   V(typ)   V(min)   V(max)
0s        224.7mV    224.1mV    225.5mV
141ps     224.3mV    223.8mV    229.5mV
194ps     232.1mV    224mV      61.19mV
212ps     203.3mV    226.7mV    33.56mV
256ps     61.37mV    235mV      7.895mV
292ps     20.54mV    163.5mV    -755.6uV
328ps     7.234mV    75.3mV     -333.2uV
355ps     3.304mV    35.37mV    -124uV
445ps     -436.1uV   3.515mV    -6.013uV
3ns       914nV      13.26uV    536.4nV
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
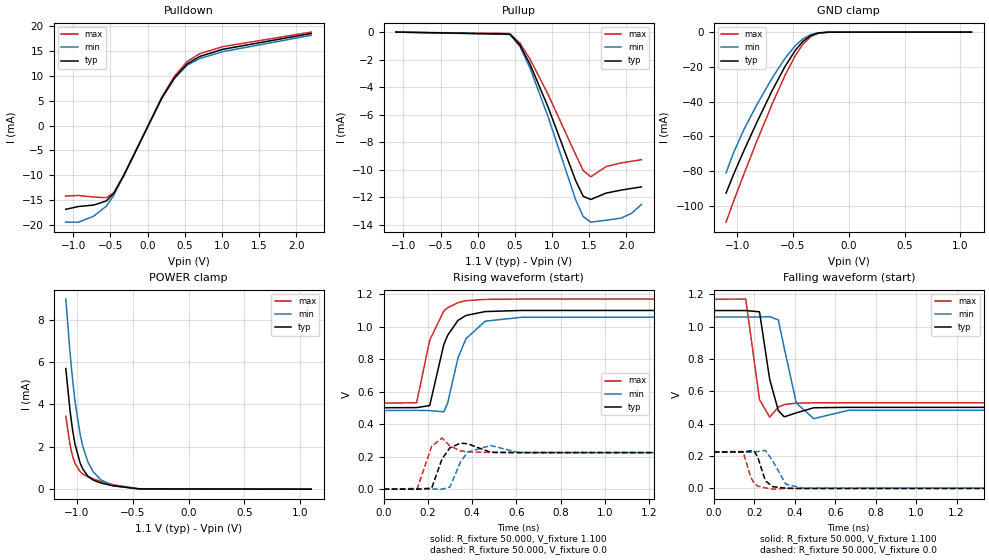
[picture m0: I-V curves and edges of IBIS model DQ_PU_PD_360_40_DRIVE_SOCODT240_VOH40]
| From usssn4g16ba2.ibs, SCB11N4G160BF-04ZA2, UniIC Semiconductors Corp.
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|   Model DQ_PU_PD_360_40_DRIVE_SOCODT240_VOH40
[Model] DQ_PU_PD_360_40_DRIVE_SOCODT240_VOH40
Model_type I/O
Polarity   Inverting
Vinl =  0.135V
Vinh =  0.305V
Vmeas =  0.220V
Rref =  50.000
Vref =  0.220V
C_comp   1.020pF   1.010pF   1.030pF
[Model Spec]
Vinh   0.305V   0.297V   0.319V
Vinl   0.135V   0.127V   0.149V
Vmeas   0.220V   0.212V   0.234V
Vref   0.220V   0.212V   0.234V
Rref   50.000   NA   NA
[Temperature Range]   25.000   0.105k   -40.000
[Voltage Range]   1.100V   1.060V   1.170V
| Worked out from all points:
|   slope of the pulldown table from 0 to 0.165 V, typ, clamps not added: 34.3 ohm
|   GND clamp passes 1 mA (typ) near -0.30 V on its own axis
|   POWER clamp passes 1 mA (typ) near -0.95 V on its own axis
|   rising waveform, R_fixture 50.000, V_fixture 1.100: 20-80 % time 76.1ps typ, 79.8ps min, 73.9ps max; typ from 0.501 V to 1.1 V
|   rising waveform, R_fixture 50.000, V_fixture 0.0: 20-80 % time 31.8ps typ, 40.3ps min, 25.8ps max; typ from 0 V to 0.225 V
|   falling waveform, R_fixture 50.000, V_fixture 1.100: 20-80 % time 40.9ps typ, 52.1ps min, 33.9ps max; typ from 1.1 V to 0.501 V
|   falling waveform, R_fixture 50.000, V_fixture 0.0: 20-80 % time 34.5ps typ, 54ps min, 31.3ps max; typ from 0.225 V to 0 V
[Pulldown]
|Voltage   I(typ)   I(min)   I(max)
-1.1V     -16.81mA   -19.37mA   -14.15mA
-930mV    -16.24mA   -19.39mA   -14.03mA
-726mV    -15.96mA   -18.19mA   -14.35mA
-556mV    -15.13mA   -16.19mA   -14.47mA
-454mV    -13.55mA   -13.98mA   -13.5mA
-318mV    -9.863mA   -9.979mA   -10.07mA
192mV     5.543mA    5.52mA     5.738mA
362mV     9.574mA    9.475mA    9.913mA
532mV     12.37mA    12.1mA     12.85mA
702mV     13.87mA    13.45mA    14.42mA
1.008V    15.29mA    14.82mA    15.82mA
2.2V      18.47mA    18.1mA     18.75mA
[Pullup]
|Voltage   I(typ)   I(min)   I(max)
-1.1V     900pA      9.618nA    0A
432mV     -147.1uA   -170.1uA   -107.3uA
568mV     -948.7uA   -1.043mA   -800.9uA
704mV     -2.351mA   -2.626mA   -1.98mA
942mV     -5.394mA   -6.093mA   -4.481mA
1.316V    -10.78mA   -12.17mA   -8.894mA
1.418V    -11.93mA   -13.4mA    -10.05mA
1.52V     -12.16mA   -13.81mA   -10.51mA
1.724V    -11.7mA    -13.67mA   -9.778mA
1.928V    -11.48mA   -13.51mA   -9.507mA
2.064V    -11.36mA   -13.18mA   -9.389mA
2.2V      -11.25mA   -12.53mA   -9.27mA
[GND_clamp]
|Voltage   I(typ)   I(min)   I(max)
-1.1V     -92.78mA   -81.05mA   -109.5mA
-1.031V   -81.73mA   -69.22mA   -97.17mA
-939mV    -68.18mA   -56.02mA   -81.64mA
-824mV    -52mA      -41.83mA   -62.83mA
-686mV    -33.62mA   -26.41mA   -41.32mA
-571mV    -19.76mA   -15.06mA   -24.85mA
-479mV    -10.5mA    -7.76mA    -13.5mA
-410mV    -5.313mA   -3.84mA    -6.916mA
-341mV    -2.007mA   -1.45mA    -2.59mA
-272mV    -506.9uA   -403.5uA   -609.8uA
-180mV    -45.65uA   -51.35uA   -43.55uA
1.1V      0A         0A         0A
[POWER_clamp]
|Voltage   I(typ)   I(min)   I(max)
-1.1V     5.691mA    8.967mA    3.44mA
-1.062V   3.709mA    6.444mA    2.092mA
-1.039V   2.781mA    5.152mA    1.546mA
-1.016V   2.086mA    4.085mA    1.193mA
-970mV    1.21mA     2.539mA    818.5uA
-947mV    943.7uA    2.005mA    716.7uA
-901mV    610.1uA    1.27mA     581.3uA
-855mV    430.7uA    824.1uA    484.6uA
-786mV    289.9uA    439.4uA    366uA
-671mV    155.9uA    155.9uA    203.6uA
-441mV    13.2uA     12.79uA    15.03uA
1.1V      0A         0A         0A
[Ramp]
| variable   typ   min   max
dV/dt_r   0.135/31.847p   0.134/40.360p   0.135/25.811p
dV/dt_f   0.359/40.927p   0.346/52.180p   0.384/33.972p
R_load = 50.000
[Rising Waveform]
R_fixture= 50.000
V_fixture= 1.100
V_fixture_min= 1.060
V_fixture_max= 1.170
|time   V(typ)   V(min)   V(max)
0s        501.3mV    484.2mV    529.3mV
149ps     501.9mV    484.8mV    532.1mV
208ps     514.2mV    483.4mV    916.2mV
272ps     890.5mV    476mV      1.097V
289ps     946.4mV    528.8mV    1.116V
336ps     1.039V     808.2mV    1.148V
372ps     1.069V     925.8mV    1.16V
459ps     1.093V     1.034V     1.168V
625ps     1.1V       1.058V     1.17V
3ns       1.1V       1.06V      1.17V
[Rising Waveform]
R_fixture= 50.000
V_fixture= 0.0
V_fixture_min= 0.0
V_fixture_max= 0.0
|time   V(typ)   V(min)   V(max)
0s        2.565uV    9.322uV    596nV
152ps     205.6uV    32.42uV    4.302mV
217ps     6.472mV    433.8uV    263.7mV
264ps     186.5mV    -59.52uV   314.8mV
299ps     254.4mV    12.2mV     267mV
347ps     283.2mV    166.5mV    235.8mV
380ps     279.2mV    228.5mV    229.6mV
483ps     227mV      268.4mV    225.7mV
610ps     224.8mV    225.4mV    225.5mV
3ns       224.7mV    224.1mV    225.5mV
[Falling Waveform]
R_fixture= 50.000
V_fixture= 1.100
V_fixture_min= 1.060
V_fixture_max= 1.170
|time   V(typ)   V(min)   V(max)
0s        1.1V       1.06V      1.17V
158ps     1.1V       1.06V      1.171V
226ps     1.092V     1.06V      549.7mV
276ps     676.1mV    1.062V     440.6mV
319ps     480.8mV    1.042V     502.6mV
348ps     442.4mV    868.9mV    518.2mV
408ps     467.2mV    527.8mV    527.3mV
494ps     498.6mV    431.3mV    529.1mV
667ps     501.2mV    483.3mV    529.3mV
3ns       501.3mV    484.2mV    529.3mV
[Falling Waveform]
R_fixture= 50.000
V_fixture= 0.0
V_fixture_min= 0.0
V_fixture_max= 0.0
|time   V(typ)   V(min)   V(max)
0s        224.7mV    224.1mV    225.5mV
144ps     224.4mV    223.8mV    228.7mV
183ps     232.5mV    223.5mV    68.96mV
199ps     230.3mV    224.4mV    32.2mV
217ps     194.6mV    227.6mV    13.79mV
255ps     46.44mV    235mV      2.708mV
292ps     10.17mV    168.4mV    -5mV
356ps     1.083mV    25.93mV    -353.3uV
436ps     -1.207mV   2.082mV    -10.3uV
3ns       -2.825uV   9.148uV    -33.44nV
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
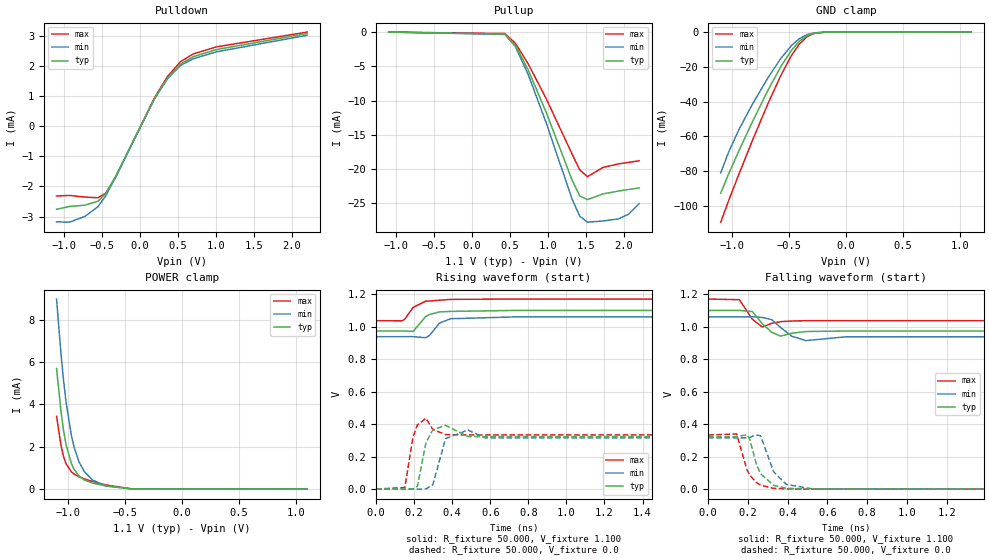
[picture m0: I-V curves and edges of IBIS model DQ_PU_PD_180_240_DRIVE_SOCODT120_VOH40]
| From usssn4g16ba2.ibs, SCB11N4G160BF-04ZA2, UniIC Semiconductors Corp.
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|   Model DQ_PU_PD_180_240_DRIVE_SOCODT120_VOH40
[Model] DQ_PU_PD_180_240_DRIVE_SOCODT120_VOH40
Model_type I/O
Polarity   Inverting
Vinl =  0.135V
Vinh =  0.305V
Vmeas =  0.220V
Rref =  50.000
Vref =  0.220V
C_comp   1.020pF   1.010pF   1.030pF
[Model Spec]
Vinh   0.305V   0.297V   0.319V
Vinl   0.135V   0.127V   0.149V
Vmeas   0.220V   0.212V   0.234V
Vref   0.220V   0.212V   0.234V
Rref   50.000   NA   NA
[Temperature Range]   25.000   0.105k   -40.000
[Voltage Range]   1.100V   1.060V   1.170V
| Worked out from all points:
|   slope of the pulldown table from 0 to 0.165 V, typ, clamps not added: 205 ohm
|   GND clamp passes 1 mA (typ) near -0.30 V on its own axis
|   POWER clamp passes 1 mA (typ) near -0.95 V on its own axis
|   rising waveform, R_fixture 50.000, V_fixture 1.100: 20-80 % time 62.7ps typ, 61.6ps min, 66ps max; typ from 0.973 V to 1.1 V
|   rising waveform, R_fixture 50.000, V_fixture 0.0: 20-80 % time 28.6ps typ, 36.5ps min, 22.8ps max; typ from 0 V to 0.323 V
|   falling waveform, R_fixture 50.000, V_fixture 1.100: 20-80 % time 48.4ps typ, 63.8ps min, 38.2ps max; typ from 1.1 V to 0.973 V
|   falling waveform, R_fixture 50.000, V_fixture 0.0: 20-80 % time 61.8ps typ, 67.8ps min, 59.9ps max; typ from 0.323 V to 0 V
[Pulldown]
|Voltage   I(typ)   I(min)   I(max)
-1.1V     -2.76mA    -3.177mA   -2.318mA
-930mV    -2.666mA   -3.189mA   -2.299mA
-726mV    -2.623mA   -2.996mA   -2.354mA
-556mV    -2.492mA   -2.677mA   -2.377mA
-454mV    -2.244mA   -2.321mA   -2.229mA
-318mV    -1.646mA   -1.668mA   -1.68mA
192mV     927.8uA    924.2uA    960.8uA
362mV     1.601mA    1.585mA    1.659mA
532mV     2.068mA    2.023mA    2.148mA
702mV     2.317mA    2.249mA    2.409mA
1.008V    2.554mA    2.478mA    2.643mA
2.2V      3.086mA    3.027mA    3.134mA
[Pullup]
|Voltage   I(typ)   I(min)   I(max)
-1.1V     1.8nA      19.34nA    0A
432mV     -294.2uA   -340.2uA   -214.5uA
568mV     -1.899mA   -2.087mA   -1.603mA
738mV     -5.508mA   -6.173mA   -4.628mA
976mV     -11.74mA   -13.27mA   -9.734mA
1.316V    -21.59mA   -24.38mA   -17.8mA
1.418V    -23.93mA   -26.88mA   -20.13mA
1.52V     -24.46mA   -27.76mA   -21.11mA
1.724V    -23.63mA   -27.58mA   -19.76mA
1.928V    -23.21mA   -27.28mA   -19.25mA
2.064V    -22.98mA   -26.57mA   -19.02mA
2.2V      -22.76mA   -25.06mA   -18.79mA
[GND_clamp]
|Voltage   I(typ)   I(min)   I(max)
-1.1V     -92.78mA   -81.05mA   -109.5mA
-1.031V   -81.73mA   -69.22mA   -97.17mA
-939mV    -68.18mA   -56.02mA   -81.64mA
-824mV    -52mA      -41.83mA   -62.83mA
-686mV    -33.62mA   -26.41mA   -41.32mA
-571mV    -19.76mA   -15.06mA   -24.85mA
-479mV    -10.5mA    -7.76mA    -13.5mA
-410mV    -5.313mA   -3.84mA    -6.916mA
-341mV    -2.007mA   -1.45mA    -2.59mA
-272mV    -506.9uA   -403.5uA   -609.8uA
-180mV    -45.65uA   -51.35uA   -43.55uA
1.1V      0A         0A         0A
[POWER_clamp]
|Voltage   I(typ)   I(min)   I(max)
-1.1V     5.691mA    8.967mA    3.44mA
-1.062V   3.709mA    6.444mA    2.092mA
-1.039V   2.781mA    5.152mA    1.546mA
-1.016V   2.086mA    4.085mA    1.193mA
-970mV    1.21mA     2.539mA    818.5uA
-947mV    943.7uA    2.005mA    716.7uA
-901mV    610.1uA    1.27mA     581.3uA
-855mV    430.7uA    824.1uA    484.6uA
-786mV    289.9uA    439.4uA    366uA
-671mV    155.9uA    155.9uA    203.6uA
-441mV    13.2uA     12.79uA    15.03uA
1.1V      0A         0A         0A
[Ramp]
| variable   typ   min   max
dV/dt_r   0.194/28.858p   0.190/36.607p   0.200/22.939p
dV/dt_f   75.974m/48.498p   73.034m/63.894p   79.780m/38.288p
R_load = 50.000
[Rising Waveform]
R_fixture= 50.000
V_fixture= 1.100
V_fixture_min= 1.060
V_fixture_max= 1.170
|time   V(typ)   V(min)   V(max)
0s        973.4mV    938.3mV    1.037V
138ps     973.7mV    938.4mV    1.036V
151ps     973.1mV    938.6mV    1.047V
195ps     971.1mV    938.5mV    1.119V
260ps     1.062V     932mV      1.157V
281ps     1.075V     946.5mV    1.158V
333ps     1.091V     1.022V     1.163V
392ps     1.094V     1.049V     1.168V
724ps     1.1V       1.06V      1.17V
3ns       1.1V       1.06V      1.17V
[Rising Waveform]
R_fixture= 50.000
V_fixture= 0.0
V_fixture_min= 0.0
V_fixture_max= 0.0
|time   V(typ)   V(min)   V(max)
0s        5.206uV    18.91uV    1.226uV
151ps     -249.7uV   74.55uV    9.781mV
193ps     1.219mV    -95.82uV   315.8mV
217ps     17.83mV    -359.6uV   395.4mV
262ps     285.8mV    1.151mV    436.3mV
298ps     365.2mV    26.78mV    367.3mV
365ps     392.4mV    310.5mV    335.6mV
482ps     323.6mV    364.1mV    333.3mV
571ps     323.1mV    316.1mV    333.3mV
3ns       323.1mV    316.4mV    333.3mV
[Falling Waveform]
R_fixture= 50.000
V_fixture= 1.100
V_fixture_min= 1.060
V_fixture_max= 1.170
|time   V(typ)   V(min)   V(max)
0s        1.1V       1.06V      1.17V
157ps     1.1V       1.06V      1.166V
222ps     1.093V     1.061V     1.046V
272ps     1.018V     1.057V     998.3mV
320ps     965.2mV    1.043V     1.021V
364ps     942mV      994.8mV    1.031V
422ps     960.1mV    940.7mV    1.035V
492ps     970.3mV    914.4mV    1.037V
693ps     973.3mV    937.7mV    1.037V
3ns       973.4mV    938.3mV    1.037V
[Falling Waveform]
R_fixture= 50.000
V_fixture= 0.0
V_fixture_min= 0.0
V_fixture_max= 0.0
|time   V(typ)   V(min)   V(max)
0s        323.1mV    316.4mV    333.3mV
143ps     322.4mV    315.9mV    339.9mV
195ps     335.5mV    316.2mV    119.3mV
209ps     306.1mV    319.1mV    86.79mV
242ps     155.2mV    333.8mV    40.97mV
264ps     94.37mV    327.6mV    24.63mV
329ps     23.71mV    107.2mV    5.42mV
393ps     5.392mV    29.39mV    1.362mV
524ps     369uV      1.785mV    79.27uV
3ns       3.041uV    18.92uV    1.253uV
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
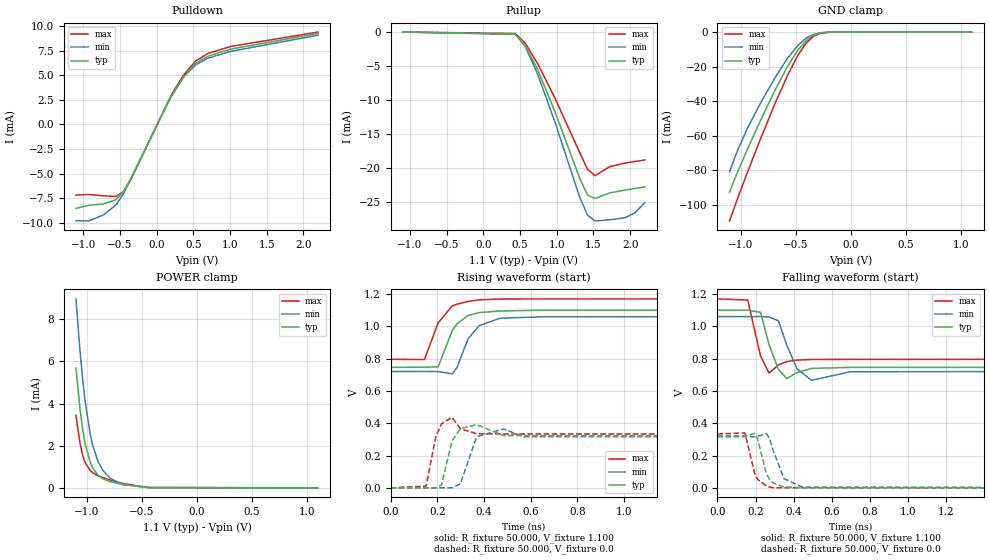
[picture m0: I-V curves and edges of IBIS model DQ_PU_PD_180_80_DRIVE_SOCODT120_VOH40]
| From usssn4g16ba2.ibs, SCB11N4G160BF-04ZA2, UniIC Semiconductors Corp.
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|   Model DQ_PU_PD_180_80_DRIVE_SOCODT120_VOH40
[Model] DQ_PU_PD_180_80_DRIVE_SOCODT120_VOH40
Model_type I/O
Polarity   Inverting
Vinl =  0.135V
Vinh =  0.305V
Vmeas =  0.220V
Rref =  50.000
Vref =  0.220V
C_comp   1.020pF   1.010pF   1.030pF
[Model Spec]
Vinh   0.305V   0.297V   0.319V
Vinl   0.135V   0.127V   0.149V
Vmeas   0.220V   0.212V   0.234V
Vref   0.220V   0.212V   0.234V
Rref   50.000   NA   NA
[Temperature Range]   25.000   0.105k   -40.000
[Voltage Range]   1.100V   1.060V   1.170V
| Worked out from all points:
|   slope of the pulldown table from 0 to 0.165 V, typ, clamps not added: 68.2 ohm
|   GND clamp passes 1 mA (typ) near -0.30 V on its own axis
|   POWER clamp passes 1 mA (typ) near -0.95 V on its own axis
|   rising waveform, R_fixture 50.000, V_fixture 1.100: 20-80 % time 71.1ps typ, 73.3ps min, 70.4ps max; typ from 0.746 V to 1.1 V
|   rising waveform, R_fixture 50.000, V_fixture 0.0: 20-80 % time 28.5ps typ, 36ps min, 22.8ps max; typ from 0 V to 0.323 V
|   falling waveform, R_fixture 50.000, V_fixture 1.100: 20-80 % time 46ps typ, 58.8ps min, 37.4ps max; typ from 1.1 V to 0.746 V
|   falling waveform, R_fixture 50.000, V_fixture 0.0: 20-80 % time 45.4ps typ, 58ps min, 42.9ps max; typ from 0.323 V to 0 V
[Pulldown]
|Voltage   I(typ)   I(min)   I(max)
-1.1V     -8.531mA   -9.779mA   -7.187mA
-930mV    -8.221mA   -9.809mA   -7.107mA
-726mV    -8.07mA    -9.196mA   -7.255mA
-556mV    -7.649mA   -8.186mA   -7.316mA
-454mV    -6.852mA   -7.06mA    -6.833mA
-352mV    -5.485mA   -5.559mA   -5.593mA
192mV     2.785mA    2.773mA    2.883mA
362mV     4.806mA    4.757mA    4.977mA
532mV     6.204mA    6.068mA    6.444mA
702mV     6.948mA    6.744mA    7.224mA
1.008V    7.659mA    7.43mA     7.924mA
2.2V      9.253mA    9.074mA    9.394mA
[Pullup]
|Voltage   I(typ)   I(min)   I(max)
-1.1V     1.8nA      19.34nA    0A
432mV     -294.2uA   -340.2uA   -214.5uA
568mV     -1.899mA   -2.087mA   -1.603mA
738mV     -5.508mA   -6.173mA   -4.628mA
976mV     -11.74mA   -13.27mA   -9.734mA
1.316V    -21.59mA   -24.38mA   -17.8mA
1.418V    -23.93mA   -26.88mA   -20.13mA
1.52V     -24.46mA   -27.76mA   -21.11mA
1.724V    -23.63mA   -27.58mA   -19.76mA
1.928V    -23.21mA   -27.28mA   -19.25mA
2.064V    -22.98mA   -26.57mA   -19.02mA
2.2V      -22.76mA   -25.06mA   -18.79mA
[GND_clamp]
|Voltage   I(typ)   I(min)   I(max)
-1.1V     -92.78mA   -81.05mA   -109.5mA
-1.031V   -81.73mA   -69.22mA   -97.17mA
-939mV    -68.18mA   -56.02mA   -81.64mA
-824mV    -52mA      -41.83mA   -62.83mA
-686mV    -33.62mA   -26.41mA   -41.32mA
-571mV    -19.76mA   -15.06mA   -24.85mA
-479mV    -10.5mA    -7.76mA    -13.5mA
-410mV    -5.313mA   -3.84mA    -6.916mA
-341mV    -2.007mA   -1.45mA    -2.59mA
-272mV    -506.9uA   -403.5uA   -609.8uA
-180mV    -45.65uA   -51.35uA   -43.55uA
1.1V      0A         0A         0A
[POWER_clamp]
|Voltage   I(typ)   I(min)   I(max)
-1.1V     5.691mA    8.967mA    3.44mA
-1.062V   3.709mA    6.444mA    2.092mA
-1.039V   2.781mA    5.152mA    1.546mA
-1.016V   2.086mA    4.085mA    1.193mA
-970mV    1.21mA     2.539mA    818.5uA
-947mV    943.7uA    2.005mA    716.7uA
-901mV    610.1uA    1.27mA     581.3uA
-855mV    430.7uA    824.1uA    484.6uA
-786mV    289.9uA    439.4uA    366uA
-671mV    155.9uA    155.9uA    203.6uA
-441mV    13.2uA     12.79uA    15.03uA
1.1V      0A         0A         0A
[Ramp]
| variable   typ   min   max
dV/dt_r   0.194/28.665p   0.190/36.013p   0.200/22.975p
dV/dt_f   0.212/46.084p   0.204/58.909p   0.225/37.475p
R_load = 50.000
[Rising Waveform]
R_fixture= 50.000
V_fixture= 1.100
V_fixture_min= 1.060
V_fixture_max= 1.170
|time   V(typ)   V(min)   V(max)
0s        746mV      720.2mV    795.6mV
145ps     746.7mV    720.6mV    794.2mV
204ps     749.5mV    719.8mV    1.022V
264ps     973.1mV    705.4mV    1.126V
284ps     1.015V     742.9mV    1.137V
332ps     1.067V     922.2mV    1.154V
379ps     1.085V     1.004V     1.164V
469ps     1.095V     1.05V      1.169V
653ps     1.1V       1.059V     1.17V
3ns       1.1V       1.06V      1.17V
[Rising Waveform]
R_fixture= 50.000
V_fixture= 0.0
V_fixture_min= 0.0
V_fixture_max= 0.0
|time   V(typ)   V(min)   V(max)
0s        3.688uV    13.4uV     861.5nV
152ps     -135.1uV   48.78uV    10.12mV
194ps     1.157mV    -28.47uV   318mV
218ps     16.95mV    -70.87uV   396.4mV
263ps     287.6mV    792.3uV    436.4mV
299ps     366.1mV    24.21mV    365.7mV
369ps     391.1mV    316.6mV    335.2mV
484ps     323.6mV    364.4mV    333.3mV
571ps     323.1mV    316.1mV    333.3mV
3ns       323.1mV    316.4mV    333.3mV
[Falling Waveform]
R_fixture= 50.000
V_fixture= 1.100
V_fixture_min= 1.060
V_fixture_max= 1.170
|time   V(typ)   V(min)   V(max)
0s        1.1V       1.06V      1.17V
159ps     1.1V       1.06V      1.163V
226ps     1.087V     1.06V      816.1mV
271ps     884.9mV    1.058V     710.2mV
320ps     731.8mV    1.034V     761.2mV
364ps     675.9mV    881.9mV    781.7mV
418ps     714.1mV    736.4mV    790.9mV
493ps     739.1mV    665.6mV    794.5mV
698ps     745.9mV    718.8mV    795.5mV
3ns       746mV      720.2mV    795.6mV
[Falling Waveform]
R_fixture= 50.000
V_fixture= 0.0
V_fixture_min= 0.0
V_fixture_max= 0.0
|time   V(typ)   V(min)   V(max)
0s        323.1mV    316.4mV    333.3mV
144ps     322.4mV    315.9mV    340.1mV
196ps     336.1mV    316.3mV    85.51mV
211ps     302mV      319.6mV    51.78mV
257ps     85.24mV    335.8mV    11.21mV
275ps     48.76mV    301.3mV    4.403mV
292ps     29.13mV    233.1mV    436.8uV
349ps     5.663mV    56.74mV    56.51uV
445ps     -322.5uV   4.686mV    5.166uV
3ns       3.255uV    13.2uV     681nV
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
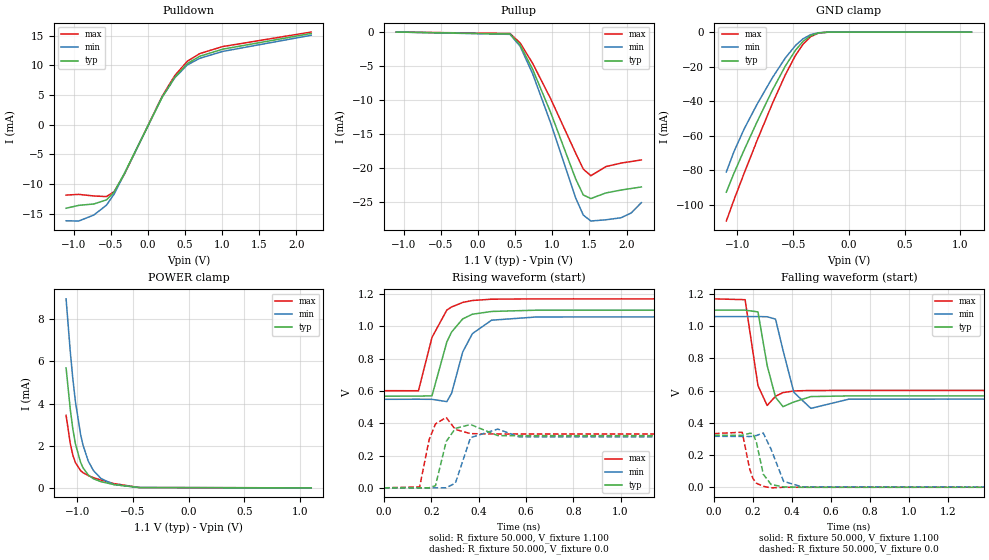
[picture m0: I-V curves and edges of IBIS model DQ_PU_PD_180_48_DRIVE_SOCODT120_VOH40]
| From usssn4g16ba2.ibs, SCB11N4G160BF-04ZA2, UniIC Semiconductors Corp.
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|   Model DQ_PU_PD_180_48_DRIVE_SOCODT120_VOH40
[Model] DQ_PU_PD_180_48_DRIVE_SOCODT120_VOH40
Model_type I/O
Polarity   Inverting
Vinl =  0.135V
Vinh =  0.305V
Vmeas =  0.220V
Rref =  50.000
Vref =  0.220V
C_comp   1.020pF   1.010pF   1.030pF
[Model Spec]
Vinh   0.305V   0.297V   0.319V
Vinl   0.135V   0.127V   0.149V
Vmeas   0.220V   0.212V   0.234V
Vref   0.220V   0.212V   0.234V
Rref   50.000   NA   NA
[Temperature Range]   25.000   0.105k   -40.000
[Voltage Range]   1.100V   1.060V   1.170V
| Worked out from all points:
|   slope of the pulldown table from 0 to 0.165 V, typ, clamps not added: 41 ohm
|   GND clamp passes 1 mA (typ) near -0.30 V on its own axis
|   POWER clamp passes 1 mA (typ) near -0.95 V on its own axis
|   rising waveform, R_fixture 50.000, V_fixture 1.100: 20-80 % time 74.6ps typ, 77.6ps min, 73ps max; typ from 0.567 V to 1.1 V
|   rising waveform, R_fixture 50.000, V_fixture 0.0: 20-80 % time 28.2ps typ, 35.6ps min, 22.7ps max; typ from 0 V to 0.323 V
|   falling waveform, R_fixture 50.000, V_fixture 1.100: 20-80 % time 43.2ps typ, 55.1ps min, 35.7ps max; typ from 1.1 V to 0.567 V
|   falling waveform, R_fixture 50.000, V_fixture 0.0: 20-80 % time 36.6ps typ, 53.1ps min, 33.6ps max; typ from 0.323 V to 0 V
[Pulldown]
|Voltage   I(typ)   I(min)   I(max)
-1.1V     -14.07mA   -16.18mA   -11.85mA
-930mV    -13.58mA   -16.22mA   -11.73mA
-726mV    -13.35mA   -15.21mA   -12mA
-556mV    -12.65mA   -13.54mA   -12.1mA
-454mV    -11.34mA   -11.69mA   -11.29mA
-318mV    -8.242mA   -8.339mA   -8.422mA
192mV     4.628mA    4.609mA    4.791mA
362mV     7.992mA    7.909mA    8.275mA
532mV     10.32mA    10.1mA     10.72mA
702mV     11.57mA    11.22mA    12.02mA
1.008V    12.75mA    12.37mA    13.19mA
2.2V      15.4mA     15.1mA     15.64mA
[Pullup]
|Voltage   I(typ)   I(min)   I(max)
-1.1V     1.8nA      19.34nA    0A
432mV     -294.2uA   -340.2uA   -214.5uA
568mV     -1.899mA   -2.087mA   -1.603mA
738mV     -5.508mA   -6.173mA   -4.628mA
976mV     -11.74mA   -13.27mA   -9.734mA
1.316V    -21.59mA   -24.38mA   -17.8mA
1.418V    -23.93mA   -26.88mA   -20.13mA
1.52V     -24.46mA   -27.76mA   -21.11mA
1.724V    -23.63mA   -27.58mA   -19.76mA
1.928V    -23.21mA   -27.28mA   -19.25mA
2.064V    -22.98mA   -26.57mA   -19.02mA
2.2V      -22.76mA   -25.06mA   -18.79mA
[GND_clamp]
|Voltage   I(typ)   I(min)   I(max)
-1.1V     -92.78mA   -81.05mA   -109.5mA
-1.031V   -81.73mA   -69.22mA   -97.17mA
-939mV    -68.18mA   -56.02mA   -81.64mA
-824mV    -52mA      -41.83mA   -62.83mA
-686mV    -33.62mA   -26.41mA   -41.32mA
-571mV    -19.76mA   -15.06mA   -24.85mA
-479mV    -10.5mA    -7.76mA    -13.5mA
-410mV    -5.313mA   -3.84mA    -6.916mA
-341mV    -2.007mA   -1.45mA    -2.59mA
-272mV    -506.9uA   -403.5uA   -609.8uA
-180mV    -45.65uA   -51.35uA   -43.55uA
1.1V      0A         0A         0A
[POWER_clamp]
|Voltage   I(typ)   I(min)   I(max)
-1.1V     5.691mA    8.967mA    3.44mA
-1.062V   3.709mA    6.444mA    2.092mA
-1.039V   2.781mA    5.152mA    1.546mA
-1.016V   2.086mA    4.085mA    1.193mA
-970mV    1.21mA     2.539mA    818.5uA
-947mV    943.7uA    2.005mA    716.7uA
-901mV    610.1uA    1.27mA     581.3uA
-855mV    430.7uA    824.1uA    484.6uA
-786mV    289.9uA    439.4uA    366uA
-671mV    155.9uA    155.9uA    203.6uA
-441mV    13.2uA     12.79uA    15.03uA
1.1V      0A         0A         0A
[Ramp]
| variable   typ   min   max
dV/dt_r   0.194/28.408p   0.190/35.664p   0.200/22.911p
dV/dt_f   0.320/43.324p   0.307/55.282p   0.341/35.782p
R_load = 50.000
[Rising Waveform]
R_fixture= 50.000
V_fixture= 1.100
V_fixture_min= 1.060
V_fixture_max= 1.170
|time   V(typ)   V(min)   V(max)
0s        567.3mV    548.1mV    601.6mV
146ps     568.1mV    548.7mV    601.2mV
203ps     569.5mV    548mV      931.5mV
266ps     903.9mV    533.9mV    1.101V
286ps     964.9mV    585.7mV    1.12V
333ps     1.046V     841.2mV    1.148V
374ps     1.075V     955mV      1.16V
455ps     1.092V     1.038V     1.168V
645ps     1.1V       1.058V     1.17V
3ns       1.1V       1.06V      1.17V
[Rising Waveform]
R_fixture= 50.000
V_fixture= 0.0
V_fixture_min= 0.0
V_fixture_max= 0.0
|time   V(typ)   V(min)   V(max)
0s        2.854uV    10.37uV    664nV
151ps     13.91uV    43.83uV    6.279mV
191ps     544.2uV    55.62uV    298.3mV
218ps     13.94mV    177.2uV    395.7mV
263ps     286.4mV    356.5uV    436.3mV
302ps     368.1mV    29.1mV     361.3mV
366ps     392.2mV    310.7mV    335.5mV
481ps     323.6mV    363.9mV    333.3mV
570ps     323.1mV    316.2mV    333.3mV
3ns       323.1mV    316.4mV    333.3mV
[Falling Waveform]
R_fixture= 50.000
V_fixture= 1.100
V_fixture_min= 1.060
V_fixture_max= 1.170
|time   V(typ)   V(min)   V(max)
0s        1.1V       1.06V      1.17V
159ps     1.1V       1.06V      1.165V
225ps     1.089V     1.06V      631.2mV
272ps     756.2mV    1.059V     507.7mV
315ps     559.1mV    1.044V     565.3mV
353ps     500.7mV    852.2mV    587.8mV
409ps     529.6mV    589.5mV    598.1mV
496ps     563.1mV    489.8mV    601.2mV
691ps     567.3mV    547.2mV    601.6mV
3ns       567.3mV    548.1mV    601.6mV
[Falling Waveform]
R_fixture= 50.000
V_fixture= 0.0
V_fixture_min= 0.0
V_fixture_max= 0.0
|time   V(typ)   V(min)   V(max)
0s        323.1mV    316.4mV    333.3mV
144ps     322.3mV    315.9mV    341.6mV
182ps     335mV      315.3mV    115.6mV
199ps     334.3mV    316.6mV    54.75mV
217ps     279.5mV    321.5mV    25.08mV
252ps     81.68mV    336.6mV    5.952mV
292ps     17.29mV    236.6mV    -3.697mV
356ps     1.917mV    36.64mV    -330.7uV
452ps     -517.3uV   2.168mV    -6.323uV
3ns       -266.9nV   10.24uV    -2.167uV
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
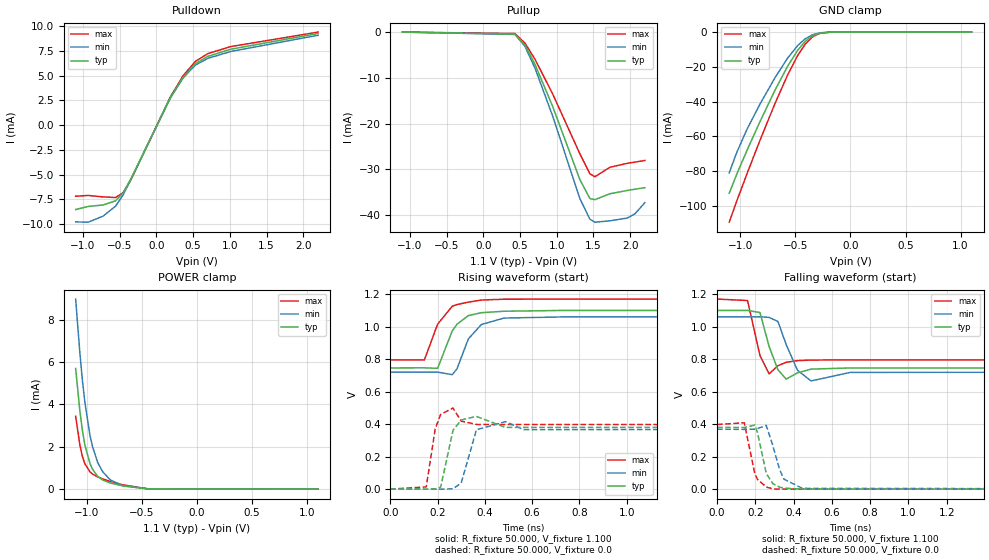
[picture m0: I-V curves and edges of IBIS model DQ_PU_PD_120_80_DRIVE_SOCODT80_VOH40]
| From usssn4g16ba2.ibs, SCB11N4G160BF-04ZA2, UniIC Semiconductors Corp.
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|   Model DQ_PU_PD_120_80_DRIVE_SOCODT80_VOH40
[Model] DQ_PU_PD_120_80_DRIVE_SOCODT80_VOH40
Model_type I/O
Polarity   Inverting
Vinl =  0.135V
Vinh =  0.305V
Vmeas =  0.220V
Rref =  50.000
Vref =  0.220V
C_comp   1.020pF   1.010pF   1.030pF
[Model Spec]
Vinh   0.305V   0.297V   0.319V
Vinl   0.135V   0.127V   0.149V
Vmeas   0.220V   0.212V   0.234V
Vref   0.220V   0.212V   0.234V
Rref   50.000   NA   NA
[Temperature Range]   25.000   0.105k   -40.000
[Voltage Range]   1.100V   1.060V   1.170V
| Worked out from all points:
|   slope of the pulldown table from 0 to 0.165 V, typ, clamps not added: 68.2 ohm
|   GND clamp passes 1 mA (typ) near -0.30 V on its own axis
|   POWER clamp passes 1 mA (typ) near -0.95 V on its own axis
|   rising waveform, R_fixture 50.000, V_fixture 1.100: 20-80 % time 69.6ps typ, 70.9ps min, 70ps max; typ from 0.746 V to 1.1 V
|   rising waveform, R_fixture 50.000, V_fixture 0.0: 20-80 % time 26.5ps typ, 34.2ps min, 21.2ps max; typ from 0 V to 0.38 V
|   falling waveform, R_fixture 50.000, V_fixture 1.100: 20-80 % time 46.5ps typ, 59.7ps min, 37.7ps max; typ from 1.1 V to 0.746 V
|   falling waveform, R_fixture 50.000, V_fixture 0.0: 20-80 % time 45.6ps typ, 57.4ps min, 43.1ps max; typ from 0.38 V to 0 V
[Pulldown]
|Voltage   I(typ)   I(min)   I(max)
-1.1V     -8.531mA   -9.779mA   -7.187mA
-930mV    -8.221mA   -9.809mA   -7.107mA
-726mV    -8.07mA    -9.196mA   -7.255mA
-556mV    -7.649mA   -8.186mA   -7.316mA
-454mV    -6.852mA   -7.06mA    -6.833mA
-352mV    -5.485mA   -5.559mA   -5.593mA
192mV     2.785mA    2.773mA    2.883mA
362mV     4.806mA    4.757mA    4.977mA
532mV     6.204mA    6.068mA    6.444mA
702mV     6.948mA    6.744mA    7.224mA
1.008V    7.659mA    7.43mA     7.924mA
2.2V      9.253mA    9.074mA    9.394mA
[Pullup]
|Voltage   I(typ)   I(min)   I(max)
-1.1V     2.7nA      29.07nA    0A
432mV     -441uA     -509.9uA   -321.6uA
568mV     -2.841mA   -3.122mA   -2.399mA
704mV     -7.035mA   -7.857mA   -5.928mA
942mV     -16.13mA   -18.22mA   -13.41mA
1.316V    -32.25mA   -36.4mA    -26.61mA
1.452V    -36.39mA   -40.9mA    -30.97mA
1.52V     -36.62mA   -41.55mA   -31.62mA
1.724V    -35.34mA   -41.25mA   -29.55mA
1.962V    -34.61mA   -40.64mA   -28.68mA
2.064V    -34.34mA   -39.74mA   -28.42mA
2.2V      -34.01mA   -37.29mA   -28.06mA
[GND_clamp]
|Voltage   I(typ)   I(min)   I(max)
-1.1V     -92.78mA   -81.05mA   -109.5mA
-1.031V   -81.73mA   -69.22mA   -97.17mA
-939mV    -68.18mA   -56.02mA   -81.64mA
-824mV    -52mA      -41.83mA   -62.83mA
-686mV    -33.62mA   -26.41mA   -41.32mA
-571mV    -19.76mA   -15.06mA   -24.85mA
-479mV    -10.5mA    -7.76mA    -13.5mA
-410mV    -5.313mA   -3.84mA    -6.916mA
-341mV    -2.007mA   -1.45mA    -2.59mA
-272mV    -506.9uA   -403.5uA   -609.8uA
-180mV    -45.65uA   -51.35uA   -43.55uA
1.1V      0A         0A         0A
[POWER_clamp]
|Voltage   I(typ)   I(min)   I(max)
-1.1V     5.691mA    8.967mA    3.44mA
-1.062V   3.709mA    6.444mA    2.092mA
-1.039V   2.781mA    5.152mA    1.546mA
-1.016V   2.086mA    4.085mA    1.193mA
-970mV    1.21mA     2.539mA    818.5uA
-947mV    943.7uA    2.005mA    716.7uA
-901mV    610.1uA    1.27mA     581.3uA
-855mV    430.7uA    824.1uA    484.6uA
-786mV    289.9uA    439.4uA    366uA
-671mV    155.9uA    155.9uA    203.6uA
-441mV    13.2uA     12.79uA    15.03uA
1.1V      0A         0A         0A
[Ramp]
| variable   typ   min   max
dV/dt_r   0.228/26.702p   0.221/34.364p   0.239/21.401p
dV/dt_f   0.212/46.552p   0.204/59.813p   0.225/37.677p
R_load = 50.000
[Rising Waveform]
R_fixture= 50.000
V_fixture= 1.100
V_fixture_min= 1.060
V_fixture_max= 1.170
|time   V(typ)   V(min)   V(max)
0s        746mV      720.2mV    795.6mV
144ps     746.7mV    720.6mV    794.8mV
200ps     743.5mV    720.3mV    1.015V
262ps     974.1mV    704.6mV    1.126V
282ps     1.015V     740.1mV    1.136V
330ps     1.068V     924.7mV    1.151V
385ps     1.086V     1.013V     1.164V
480ps     1.095V     1.053V     1.169V
727ps     1.1V       1.06V      1.17V
3ns       1.1V       1.06V      1.17V
[Rising Waveform]
R_fixture= 50.000
V_fixture= 0.0
V_fixture_min= 0.0
V_fixture_max= 0.0
|time   V(typ)   V(min)   V(max)
0s        3.688uV    13.4uV     861.5nV
152ps     -275.7uV   66.3uV     13.88mV
190ps     705.5uV    -38.37uV   371.1mV
213ps     11.83mV    -259.5uV   460.1mV
265ps     361.5mV    1.662mV    499.1mV
300ps     426mV      37.31mV    418.6mV
364ps     447.6mV    365mV      398.3mV
487ps     379.9mV    415.4mV    397.7mV
564ps     379.9mV    366mV      397.7mV
3ns       379.9mV    368.5mV    397.7mV
[Falling Waveform]
R_fixture= 50.000
V_fixture= 1.100
V_fixture_min= 1.060
V_fixture_max= 1.170
|time   V(typ)   V(min)   V(max)
0s        1.1V       1.06V      1.17V
159ps     1.1V       1.06V      1.161V
224ps     1.087V     1.061V     822.7mV
272ps     877.4mV    1.057V     709.5mV
318ps     734.6mV    1.032V     759.6mV
361ps     677.3mV    889.8mV    780.7mV
420ps     715.5mV    732.2mV    791mV
491ps     738.8mV    665.9mV    794.5mV
697ps     745.9mV    718.7mV    795.5mV
3ns       746mV      720.2mV    795.6mV
[Falling Waveform]
R_fixture= 50.000
V_fixture= 0.0
V_fixture_min= 0.0
V_fixture_max= 0.0
|time   V(typ)   V(min)   V(max)
0s        379.9mV    368.5mV    397.7mV
142ps     379mV      367.9mV    408.3mV
197ps     394.2mV    368.7mV    95.75mV
211ps     348.7mV    372.8mV    59.99mV
257ps     96.43mV    392.4mV    12.95mV
291ps     34.09mV    269.5mV    1.108mV
327ps     11.91mV    118.8mV    260.1uV
350ps     6.197mV    60.98mV    153.8uV
445ps     -271.8uV   5.184mV    10.61uV
3ns       3.355uV    13.16uV    -2.617uV
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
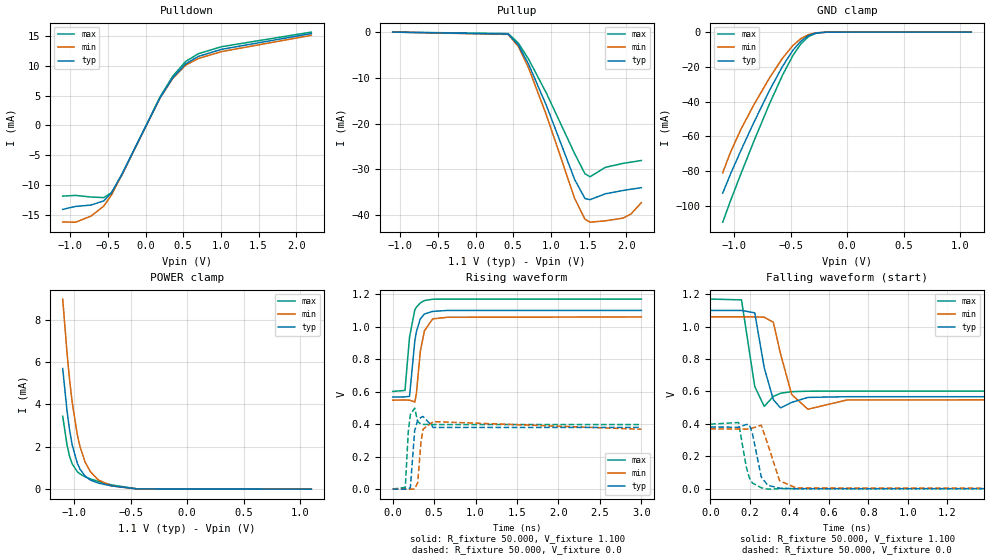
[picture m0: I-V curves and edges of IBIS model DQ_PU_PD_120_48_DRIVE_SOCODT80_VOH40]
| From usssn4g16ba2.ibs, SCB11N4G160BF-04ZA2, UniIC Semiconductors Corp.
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|   Model DQ_PU_PD_120_48_DRIVE_SOCODT80_VOH40
[Model] DQ_PU_PD_120_48_DRIVE_SOCODT80_VOH40
Model_type I/O
Polarity   Inverting
Vinl =  0.135V
Vinh =  0.305V
Vmeas =  0.220V
Rref =  50.000
Vref =  0.220V
C_comp   1.020pF   1.010pF   1.030pF
[Model Spec]
Vinh   0.305V   0.297V   0.319V
Vinl   0.135V   0.127V   0.149V
Vmeas   0.220V   0.212V   0.234V
Vref   0.220V   0.212V   0.234V
Rref   50.000   NA   NA
[Temperature Range]   25.000   0.105k   -40.000
[Voltage Range]   1.100V   1.060V   1.170V
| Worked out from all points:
|   slope of the pulldown table from 0 to 0.165 V, typ, clamps not added: 41 ohm
|   GND clamp passes 1 mA (typ) near -0.30 V on its own axis
|   POWER clamp passes 1 mA (typ) near -0.95 V on its own axis
|   rising waveform, R_fixture 50.000, V_fixture 1.100: 20-80 % time 73.8ps typ, 76.2ps min, 72.8ps max; typ from 0.567 V to 1.1 V
|   rising waveform, R_fixture 50.000, V_fixture 0.0: 20-80 % time 26.3ps typ, 33.8ps min, 21.1ps max; typ from 0 V to 0.38 V
|   falling waveform, R_fixture 50.000, V_fixture 1.100: 20-80 % time 43.6ps typ, 55.8ps min, 35.8ps max; typ from 1.1 V to 0.567 V
|   falling waveform, R_fixture 50.000, V_fixture 0.0: 20-80 % time 37.2ps typ, 53.2ps min, 34.1ps max; typ from 0.38 V to 0 V
[Pulldown]
|Voltage   I(typ)   I(min)   I(max)
-1.1V     -14.07mA   -16.18mA   -11.85mA
-930mV    -13.58mA   -16.22mA   -11.73mA
-726mV    -13.35mA   -15.21mA   -12mA
-556mV    -12.65mA   -13.54mA   -12.1mA
-454mV    -11.34mA   -11.69mA   -11.29mA
-318mV    -8.242mA   -8.339mA   -8.422mA
192mV     4.628mA    4.609mA    4.791mA
362mV     7.992mA    7.909mA    8.275mA
532mV     10.32mA    10.1mA     10.72mA
702mV     11.57mA    11.22mA    12.02mA
1.008V    12.75mA    12.37mA    13.19mA
2.2V      15.4mA     15.1mA     15.64mA
[Pullup]
|Voltage   I(typ)   I(min)   I(max)
-1.1V     2.7nA      29.07nA    0A
432mV     -441uA     -509.9uA   -321.6uA
568mV     -2.841mA   -3.122mA   -2.399mA
704mV     -7.035mA   -7.857mA   -5.928mA
942mV     -16.13mA   -18.22mA   -13.41mA
1.316V    -32.25mA   -36.4mA    -26.61mA
1.452V    -36.39mA   -40.9mA    -30.97mA
1.52V     -36.62mA   -41.55mA   -31.62mA
1.724V    -35.34mA   -41.25mA   -29.55mA
1.962V    -34.61mA   -40.64mA   -28.68mA
2.064V    -34.34mA   -39.74mA   -28.42mA
2.2V      -34.01mA   -37.29mA   -28.06mA
[GND_clamp]
|Voltage   I(typ)   I(min)   I(max)
-1.1V     -92.78mA   -81.05mA   -109.5mA
-1.031V   -81.73mA   -69.22mA   -97.17mA
-939mV    -68.18mA   -56.02mA   -81.64mA
-824mV    -52mA      -41.83mA   -62.83mA
-686mV    -33.62mA   -26.41mA   -41.32mA
-571mV    -19.76mA   -15.06mA   -24.85mA
-479mV    -10.5mA    -7.76mA    -13.5mA
-410mV    -5.313mA   -3.84mA    -6.916mA
-341mV    -2.007mA   -1.45mA    -2.59mA
-272mV    -506.9uA   -403.5uA   -609.8uA
-180mV    -45.65uA   -51.35uA   -43.55uA
1.1V      0A         0A         0A
[POWER_clamp]
|Voltage   I(typ)   I(min)   I(max)
-1.1V     5.691mA    8.967mA    3.44mA
-1.062V   3.709mA    6.444mA    2.092mA
-1.039V   2.781mA    5.152mA    1.546mA
-1.016V   2.086mA    4.085mA    1.193mA
-970mV    1.21mA     2.539mA    818.5uA
-947mV    943.7uA    2.005mA    716.7uA
-901mV    610.1uA    1.27mA     581.3uA
-855mV    430.7uA    824.1uA    484.6uA
-786mV    289.9uA    439.4uA    366uA
-671mV    155.9uA    155.9uA    203.6uA
-441mV    13.2uA     12.79uA    15.03uA
1.1V      0A         0A         0A
[Ramp]
| variable   typ   min   max
dV/dt_r   0.228/26.451p   0.221/33.929p   0.239/21.350p
dV/dt_f   0.320/43.568p   0.307/55.786p   0.341/35.868p
R_load = 50.000
[Rising Waveform]
R_fixture= 50.000
V_fixture= 1.100
V_fixture_min= 1.060
V_fixture_max= 1.170
|time   V(typ)   V(min)   V(max)
0s        567.3mV    548.1mV    601.6mV
148ps     567.8mV    548.8mV    607.5mV
203ps     571.1mV    547.9mV    935.8mV
267ps     913mV      535.9mV    1.104V
286ps     969mV      589.2mV    1.12V
333ps     1.048V     848.7mV    1.146V
383ps     1.078V     974.8mV    1.161V
482ps     1.094V     1.048V     1.169V
660ps     1.1V       1.058V     1.17V
3ns       1.1V       1.06V      1.17V
[Rising Waveform]
R_fixture= 50.000
V_fixture= 0.0
V_fixture_min= 0.0
V_fixture_max= 0.0
|time   V(typ)   V(min)   V(max)
0s        2.854uV    10.37uV    664.1nV
152ps     -117.5uV   60.55uV    11.68mV
188ps     391.7uV    34.05uV    354.2mV
213ps     9.261mV    -21.58uV   459.2mV
265ps     360mV      1.089mV    499mV
302ps     427mV      40.7mV     415.7mV
341ps     440.8mV    290.3mV    399.5mV
366ps     447.5mV    368.4mV    398.3mV
490ps     379.9mV    415.8mV    397.7mV
3ns       379.9mV    368.5mV    397.7mV
[Falling Waveform]
R_fixture= 50.000
V_fixture= 1.100
V_fixture_min= 1.060
V_fixture_max= 1.170
|time   V(typ)   V(min)   V(max)
0s        1.1V       1.06V      1.17V
158ps     1.1V       1.06V      1.165V
225ps     1.085V     1.06V      630.4mV
273ps     746.4mV    1.058V     507.4mV
319ps     549mV      1.027V     569mV
356ps     498mV      830mV      588.9mV
412ps     532.3mV    580.6mV    598.3mV
494ps     562.9mV    490mV      601.2mV
692ps     567.3mV    547.2mV    601.6mV
3ns       567.3mV    548.1mV    601.6mV
[Falling Waveform]
R_fixture= 50.000
V_fixture= 0.0
V_fixture_min= 0.0
V_fixture_max= 0.0
|time   V(typ)   V(min)   V(max)
0s        379.9mV    368.5mV    397.7mV
143ps     379mV      367.9mV    408mV
182ps     395.7mV    367.2mV    134.6mV
197ps     395.1mV    368.6mV    69.2mV
213ps     341.7mV    373.5mV    34.49mV
258ps     71.95mV    391.6mV    5.158mV
291ps     20.29mV    272.7mV    -3.487mV
351ps     2.663mV    48.36mV    -388.1uV
436ps     -1.037mV   3.557mV    -11.94uV
3ns       1.356uV    10.23uV    363.5nV
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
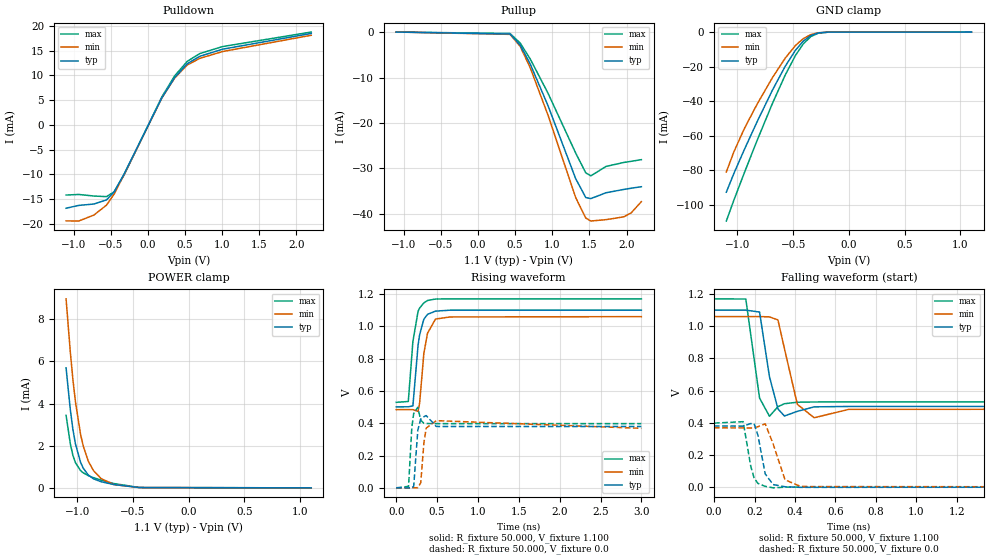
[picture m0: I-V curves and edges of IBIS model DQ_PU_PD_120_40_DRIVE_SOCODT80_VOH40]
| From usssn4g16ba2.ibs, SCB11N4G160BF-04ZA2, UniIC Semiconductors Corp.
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|   Model DQ_PU_PD_120_40_DRIVE_SOCODT80_VOH40
[Model] DQ_PU_PD_120_40_DRIVE_SOCODT80_VOH40
Model_type I/O
Polarity   Inverting
Vinl =  0.135V
Vinh =  0.305V
Vmeas =  0.220V
Rref =  50.000
Vref =  0.220V
C_comp   1.020pF   1.010pF   1.030pF
[Model Spec]
Vinh   0.305V   0.297V   0.319V
Vinl   0.135V   0.127V   0.149V
Vmeas   0.220V   0.212V   0.234V
Vref   0.220V   0.212V   0.234V
Rref   50.000   NA   NA
[Temperature Range]   25.000   0.105k   -40.000
[Voltage Range]   1.100V   1.060V   1.170V
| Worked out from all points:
|   slope of the pulldown table from 0 to 0.165 V, typ, clamps not added: 34.3 ohm
|   GND clamp passes 1 mA (typ) near -0.30 V on its own axis
|   POWER clamp passes 1 mA (typ) near -0.95 V on its own axis
|   rising waveform, R_fixture 50.000, V_fixture 1.100: 20-80 % time 75ps typ, 77.8ps min, 73.6ps max; typ from 0.501 V to 1.1 V
|   rising waveform, R_fixture 50.000, V_fixture 0.0: 20-80 % time 26.2ps typ, 33.6ps min, 21.1ps max; typ from 0 V to 0.38 V
|   falling waveform, R_fixture 50.000, V_fixture 1.100: 20-80 % time 41.4ps typ, 53ps min, 34.3ps max; typ from 1.1 V to 0.501 V
|   falling waveform, R_fixture 50.000, V_fixture 0.0: 20-80 % time 34.7ps typ, 52.3ps min, 31.3ps max; typ from 0.38 V to 0 V
[Pulldown]
|Voltage   I(typ)   I(min)   I(max)
-1.1V     -16.81mA   -19.37mA   -14.15mA
-930mV    -16.24mA   -19.39mA   -14.03mA
-726mV    -15.96mA   -18.19mA   -14.35mA
-556mV    -15.13mA   -16.19mA   -14.47mA
-454mV    -13.55mA   -13.98mA   -13.5mA
-318mV    -9.863mA   -9.979mA   -10.07mA
192mV     5.543mA    5.52mA     5.738mA
362mV     9.574mA    9.475mA    9.913mA
532mV     12.37mA    12.1mA     12.85mA
702mV     13.87mA    13.45mA    14.42mA
1.008V    15.29mA    14.82mA    15.82mA
2.2V      18.47mA    18.1mA     18.75mA
[Pullup]
|Voltage   I(typ)   I(min)   I(max)
-1.1V     2.7nA      29.07nA    0A
432mV     -441uA     -509.9uA   -321.6uA
568mV     -2.841mA   -3.122mA   -2.399mA
704mV     -7.035mA   -7.857mA   -5.928mA
942mV     -16.13mA   -18.22mA   -13.41mA
1.316V    -32.25mA   -36.4mA    -26.61mA
1.452V    -36.39mA   -40.9mA    -30.97mA
1.52V     -36.62mA   -41.55mA   -31.62mA
1.724V    -35.34mA   -41.25mA   -29.55mA
1.962V    -34.61mA   -40.64mA   -28.68mA
2.064V    -34.34mA   -39.74mA   -28.42mA
2.2V      -34.01mA   -37.29mA   -28.06mA
[GND_clamp]
|Voltage   I(typ)   I(min)   I(max)
-1.1V     -92.78mA   -81.05mA   -109.5mA
-1.031V   -81.73mA   -69.22mA   -97.17mA
-939mV    -68.18mA   -56.02mA   -81.64mA
-824mV    -52mA      -41.83mA   -62.83mA
-686mV    -33.62mA   -26.41mA   -41.32mA
-571mV    -19.76mA   -15.06mA   -24.85mA
-479mV    -10.5mA    -7.76mA    -13.5mA
-410mV    -5.313mA   -3.84mA    -6.916mA
-341mV    -2.007mA   -1.45mA    -2.59mA
-272mV    -506.9uA   -403.5uA   -609.8uA
-180mV    -45.65uA   -51.35uA   -43.55uA
1.1V      0A         0A         0A
[POWER_clamp]
|Voltage   I(typ)   I(min)   I(max)
-1.1V     5.691mA    8.967mA    3.44mA
-1.062V   3.709mA    6.444mA    2.092mA
-1.039V   2.781mA    5.152mA    1.546mA
-1.016V   2.086mA    4.085mA    1.193mA
-970mV    1.21mA     2.539mA    818.5uA
-947mV    943.7uA    2.005mA    716.7uA
-901mV    610.1uA    1.27mA     581.3uA
-855mV    430.7uA    824.1uA    484.6uA
-786mV    289.9uA    439.4uA    366uA
-671mV    155.9uA    155.9uA    203.6uA
-441mV    13.2uA     12.79uA    15.03uA
1.1V      0A         0A         0A
[Ramp]
| variable   typ   min   max
dV/dt_r   0.228/26.399p   0.221/33.765p   0.239/21.311p
dV/dt_f   0.359/41.391p   0.346/53.084p   0.384/34.203p
R_load = 50.000
[Rising Waveform]
R_fixture= 50.000
V_fixture= 1.100
V_fixture_min= 1.060
V_fixture_max= 1.170
|time   V(typ)   V(min)   V(max)
0s        501.3mV    484.2mV    529.3mV
148ps     501.8mV    484.8mV    534.7mV
204ps     507.1mV    483.9mV    905.2mV
268ps     885.4mV    473.1mV    1.094V
287ps     948.5mV    526.6mV    1.113V
338ps     1.044V     831.1mV    1.145V
383ps     1.074V     957.2mV    1.16V
481ps     1.094V     1.045V     1.169V
658ps     1.1V       1.058V     1.17V
3ns       1.1V       1.06V      1.17V
[Rising Waveform]
R_fixture= 50.000
V_fixture= 0.0
V_fixture_min= 0.0
V_fixture_max= 0.0
|time   V(typ)   V(min)   V(max)
0s        2.565uV    9.322uV    596nV
151ps     -51.36uV   62.45uV    9.121mV
191ps     852.2uV    33.98uV    374.4mV
214ps     9.4mV      78.64uV    460.9mV
264ps     355.3mV    982.7uV    499mV
300ps     426mV      30.89mV    418.6mV
339ps     440.1mV    278.4mV    399.7mV
367ps     447.3mV    369.8mV    398.2mV
491ps     379.9mV    416mV      397.7mV
3ns       379.9mV    368.5mV    397.7mV
[Falling Waveform]
R_fixture= 50.000
V_fixture= 1.100
V_fixture_min= 1.060
V_fixture_max= 1.170
|time   V(typ)   V(min)   V(max)
0s        1.1V       1.06V      1.17V
157ps     1.1V       1.06V      1.169V
225ps     1.088V     1.06V      553.4mV
274ps     686.1mV    1.058V     440.3mV
316ps     486mV      1.039V     499.9mV
348ps     442mV      861mV      518.2mV
412ps     471mV      514.3mV    527.5mV
495ps     498.6mV    431mV      529.1mV
667ps     501.2mV    483.3mV    529.3mV
3ns       501.3mV    484.2mV    529.3mV
[Falling Waveform]
R_fixture= 50.000
V_fixture= 0.0
V_fixture_min= 0.0
V_fixture_max= 0.0
|time   V(typ)   V(min)   V(max)
0s        379.9mV    368.5mV    397.7mV
144ps     379mV      367.9mV    406.6mV
181ps     394.9mV    367.2mV    132.1mV
198ps     394.3mV    368.8mV    56.77mV
217ps     321.5mV    375.2mV    22.84mV
253ps     81.83mV    393.6mV    4.625mV
292ps     15.71mV    269mV      -4.717mV
351ps     1.991mV    45.24mV    -414.1uV
429ps     -1.649mV   3.493mV    -13.68uV
3ns       2.36uV     9.114uV    365.5nV
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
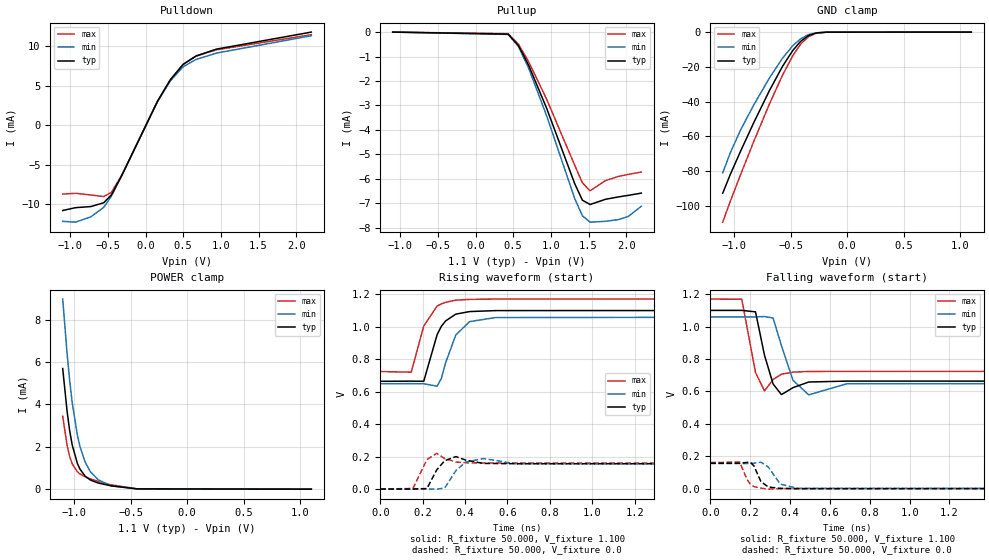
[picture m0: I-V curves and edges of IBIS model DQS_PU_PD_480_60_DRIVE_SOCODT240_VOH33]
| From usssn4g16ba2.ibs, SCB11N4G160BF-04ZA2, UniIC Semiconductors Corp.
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|   Model DQS_PU_PD_480_60_DRIVE_SOCODT240_VOH33
[Model] DQS_PU_PD_480_60_DRIVE_SOCODT240_VOH33
Model_type I/O
Polarity   Inverting
Vinl =  98.000mV
Vinh =  0.268V
Vmeas =  0.183V
Rref =  50.000
Vref =  0.183V
C_comp   1.020pF   1.010pF   1.030pF
[Model Spec]
Vinh   0.268V   0.262V   0.280V
Vinl   98.000mV   92.000mV   0.110V
Vmeas   0.183V   0.177V   0.195V
Vref   0.183V   0.177V   0.195V
Rref   50.000   NA   NA
[Temperature Range]   25.000   0.105k   -40.000
[Voltage Range]   1.100V   1.060V   1.170V
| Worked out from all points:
|   slope of the pulldown table from 0 to 0.165 V, typ, clamps not added: 52.7 ohm
|   GND clamp passes 1 mA (typ) near -0.30 V on its own axis
|   POWER clamp passes 1 mA (typ) near -0.95 V on its own axis
|   rising waveform, R_fixture 50.000, V_fixture 1.100: 20-80 % time 68.7ps typ, 72.2ps min, 66.3ps max; typ from 0.663 V to 1.1 V
|   rising waveform, R_fixture 50.000, V_fixture 0.0: 20-80 % time 34.6ps typ, 43.8ps min, 28.2ps max; typ from 0 V to 0.156 V
|   falling waveform, R_fixture 50.000, V_fixture 1.100: 20-80 % time 42.3ps typ, 55.4ps min, 33.8ps max; typ from 1.1 V to 0.663 V
|   falling waveform, R_fixture 50.000, V_fixture 0.0: 20-80 % time 37.3ps typ, 51.4ps min, 33.8ps max; typ from 0.156 V to 0 V
[Pulldown]
|Voltage   I(typ)   I(min)   I(max)
-1.1V     -10.83mA   -12.2mA    -8.746mA
-930mV    -10.47mA   -12.31mA   -8.649mA
-726mV    -10.33mA   -11.63mA   -8.863mA
-556mV    -9.849mA   -10.43mA   -9.063mA
-454mV    -8.849mA   -9.016mA   -8.534mA
-318mV    -6.436mA   -6.433mA   -6.383mA
158mV     3.005mA    2.954mA    3.019mA
328mV     5.729mA    5.586mA    5.734mA
498mV     7.686mA    7.379mA    7.672mA
668mV     8.751mA    8.306mA    8.715mA
940mV     9.618mA    9.116mA    9.532mA
2.2V      11.78mA    11.32mA    11.45mA
[Pullup]
|Voltage   I(typ)   I(min)   I(max)
-1.1V     500pA      5.412nA    0A
432mV     -84.42uA   -95.4uA    -65.89uA
568mV     -546.4uA   -585.3uA   -487.9uA
704mV     -1.354mA   -1.473mA   -1.207mA
942mV     -3.104mA   -3.412mA   -2.737mA
1.316V    -6.198mA   -6.807mA   -5.446mA
1.418V    -6.872mA   -7.507mA   -6.161mA
1.52V     -7.049mA   -7.771mA   -6.489mA
1.724V    -6.835mA   -7.734mA   -6.072mA
1.894V    -6.739mA   -7.667mA   -5.9mA
2.03V     -6.672mA   -7.532mA   -5.816mA
2.2V      -6.582mA   -7.117mA   -5.721mA
[GND_clamp]
|Voltage   I(typ)   I(min)   I(max)
-1.1V     -92.78mA   -81.05mA   -109.5mA
-1.031V   -81.73mA   -69.22mA   -97.17mA
-939mV    -68.18mA   -56.02mA   -81.64mA
-824mV    -52mA      -41.83mA   -62.83mA
-686mV    -33.62mA   -26.41mA   -41.32mA
-571mV    -19.76mA   -15.06mA   -24.85mA
-479mV    -10.5mA    -7.76mA    -13.5mA
-410mV    -5.313mA   -3.84mA    -6.916mA
-341mV    -2.007mA   -1.45mA    -2.59mA
-272mV    -506.9uA   -403.5uA   -609.8uA
-180mV    -45.65uA   -51.35uA   -43.55uA
1.1V      0A         0A         0A
[POWER_clamp]
|Voltage   I(typ)   I(min)   I(max)
-1.1V     5.691mA    8.967mA    3.44mA
-1.062V   3.709mA    6.444mA    2.092mA
-1.039V   2.781mA    5.152mA    1.546mA
-1.016V   2.086mA    4.085mA    1.193mA
-970mV    1.21mA     2.539mA    818.5uA
-947mV    943.7uA    2.005mA    716.7uA
-901mV    610.1uA    1.27mA     581.3uA
-855mV    430.7uA    824.1uA    484.6uA
-786mV    289.9uA    439.4uA    366uA
-671mV    155.9uA    155.9uA    203.6uA
-441mV    13.2uA     12.79uA    15.03uA
1.1V      0A         0A         0A
[Ramp]
| variable   typ   min   max
dV/dt_r   93.600m/34.547p   92.827m/43.879p   96.210m/28.300p
dV/dt_f   0.262/42.313p   0.247/55.396p   0.268/33.830p
R_load = 50.000
[Rising Waveform]
R_fixture= 50.000
V_fixture= 1.100
V_fixture_min= 1.060
V_fixture_max= 1.170
|time   V(typ)   V(min)   V(max)
0s        663.5mV    648.6mV    723.5mV
146ps     664.5mV    649.1mV    719.7mV
205ps     663.6mV    648.5mV    1.004V
268ps     950.4mV    633.2mV    1.127V
288ps     1.002V     681mV      1.14V
308ps     1.035V     776.9mV    1.15V
356ps     1.077V     948.1mV    1.163V
421ps     1.093V     1.031V     1.168V
543ps     1.099V     1.056V     1.17V
3ns       1.1V       1.06V      1.17V
[Rising Waveform]
R_fixture= 50.000
V_fixture= 0.0
V_fixture_min= 0.0
V_fixture_max= 0.0
|time   V(typ)   V(min)   V(max)
0s        3.261uV    11.92uV    770.5nV
154ps     200.8uV    18.1uV     3.43mV
220ps     3.031mV    373uV      181.4mV
266ps     117.7mV    -756.1uV   220.1mV
304ps     174.6mV    6.328mV    187.8mV
357ps     199.9mV    114.2mV    166.5mV
403ps     178.2mV    166.1mV    162mV
487ps     157.8mV    187.7mV    160.5mV
645ps     156mV      155.2mV    160.3mV
3ns       156mV      154.7mV    160.3mV
[Falling Waveform]
R_fixture= 50.000
V_fixture= 1.100
V_fixture_min= 1.060
V_fixture_max= 1.170
|time   V(typ)   V(min)   V(max)
0s        1.1V       1.06V      1.17V
158ps     1.1V       1.06V      1.169V
227ps     1.091V     1.06V      716mV
272ps     823.2mV    1.062V     602.9mV
315ps     646mV      1.053V     673.4mV
357ps     580mV      882.7mV    705.8mV
415ps     622.9mV    668.5mV    719mV
494ps     657.7mV    578.5mV    722.8mV
686ps     663.4mV    647.3mV    723.5mV
3ns       663.5mV    648.6mV    723.5mV
[Falling Waveform]
R_fixture= 50.000
V_fixture= 0.0
V_fixture_min= 0.0
V_fixture_max= 0.0
|time   V(typ)   V(min)   V(max)
0s        156mV      154.7mV    160.3mV
147ps     155.8mV    154.5mV    163.9mV
185ps     161.3mV    154.3mV    54.63mV
202ps     161.1mV    154.8mV    25.74mV
219ps     139.7mV    156.5mV    11.89mV
254ps     43.05mV    162.4mV    2.569mV
291ps     9.476mV    133mV      -3.996mV
351ps     940uV      27.53mV    -496.5uV
437ps     -1.123mV   1.341mV    -11.29uV
3ns       3.161uV    11.81uV    477.7nV
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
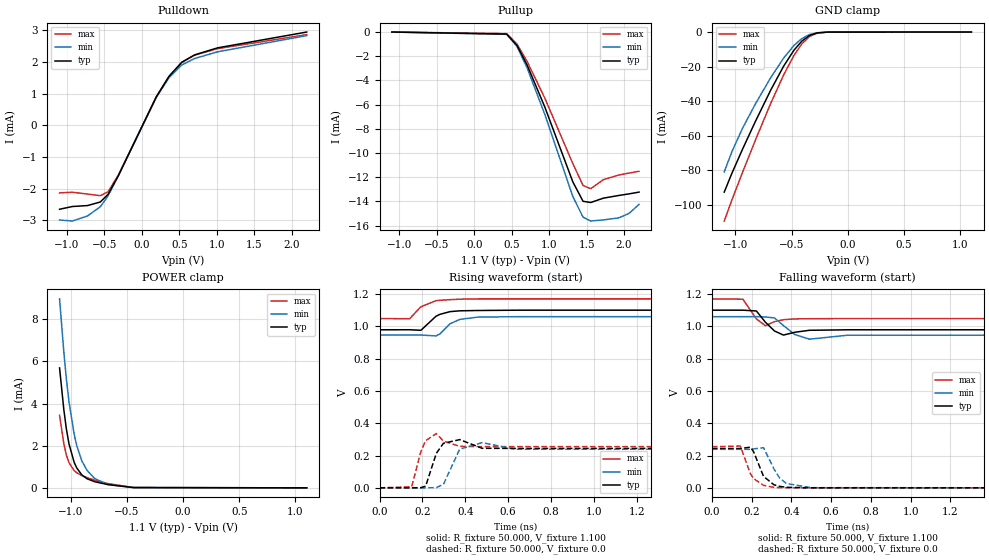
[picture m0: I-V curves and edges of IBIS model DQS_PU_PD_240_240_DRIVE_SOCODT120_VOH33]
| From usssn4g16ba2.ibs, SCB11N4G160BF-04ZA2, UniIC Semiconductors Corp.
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|   Model DQS_PU_PD_240_240_DRIVE_SOCODT120_VOH33
[Model] DQS_PU_PD_240_240_DRIVE_SOCODT120_VOH33
Model_type I/O
Polarity   Inverting
Vinl =  98.000mV
Vinh =  0.268V
Vmeas =  0.183V
Rref =  50.000
Vref =  0.183V
C_comp   1.020pF   1.010pF   1.030pF
[Model Spec]
Vinh   0.268V   0.262V   0.280V
Vinl   98.000mV   92.000mV   0.110V
Vmeas   0.183V   0.177V   0.195V
Vref   0.183V   0.177V   0.195V
Rref   50.000   NA   NA
[Temperature Range]   25.000   0.105k   -40.000
[Voltage Range]   1.100V   1.060V   1.170V
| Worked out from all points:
|   slope of the pulldown table from 0 to 0.165 V, typ, clamps not added: 211 ohm
|   GND clamp passes 1 mA (typ) near -0.30 V on its own axis
|   POWER clamp passes 1 mA (typ) near -0.95 V on its own axis
|   rising waveform, R_fixture 50.000, V_fixture 1.100: 20-80 % time 65ps typ, 66ps min, 64ps max; typ from 0.978 V to 1.1 V
|   rising waveform, R_fixture 50.000, V_fixture 0.0: 20-80 % time 31.8ps typ, 41.1ps min, 25.6ps max; typ from 0 V to 0.244 V
|   falling waveform, R_fixture 50.000, V_fixture 1.100: 20-80 % time 44.9ps typ, 59.2ps min, 34.9ps max; typ from 1.1 V to 0.978 V
|   falling waveform, R_fixture 50.000, V_fixture 0.0: 20-80 % time 56.5ps typ, 64.3ps min, 53.4ps max; typ from 0.244 V to 0 V
[Pulldown]
|Voltage   I(typ)   I(min)   I(max)
-1.1V     -2.652mA   -2.992mA   -2.134mA
-930mV    -2.565mA   -3.023mA   -2.114mA
-726mV    -2.535mA   -2.862mA   -2.171mA
-556mV    -2.422mA   -2.572mA   -2.223mA
-454mV    -2.185mA   -2.234mA   -2.101mA
-318mV    -1.604mA   -1.606mA   -1.589mA
192mV     900.6uA    884.3uA    903.8uA
362mV     1.549mA    1.507mA    1.549mA
532mV     1.993mA    1.907mA    1.988mA
702mV     2.225mA    2.111mA    2.215mA
1.008V    2.447mA    2.322mA    2.422mA
2.2V      2.948mA    2.835mA    2.866mA
[Pullup]
|Voltage   I(typ)   I(min)   I(max)
-1.1V     1nA        10.92nA    0A
432mV     -168.8uA   -190.8uA   -131.8uA
568mV     -1.092mA   -1.17mA    -975.3uA
704mV     -2.706mA   -2.942mA   -2.412mA
942mV     -6.202mA   -6.816mA   -5.469mA
1.316V    -12.39mA   -13.6mA    -10.88mA
1.452V    -13.99mA   -15.3mA    -12.68mA
1.554V    -14.09mA   -15.62mA   -12.95mA
1.724V    -13.73mA   -15.53mA   -12.2mA
1.928V    -13.51mA   -15.36mA   -11.82mA
2.064V    -13.38mA   -15mA      -11.66mA
2.2V      -13.23mA   -14.25mA   -11.51mA
[GND_clamp]
|Voltage   I(typ)   I(min)   I(max)
-1.1V     -92.78mA   -81.05mA   -109.5mA
-1.031V   -81.73mA   -69.22mA   -97.17mA
-939mV    -68.18mA   -56.02mA   -81.64mA
-824mV    -52mA      -41.83mA   -62.83mA
-686mV    -33.62mA   -26.41mA   -41.32mA
-571mV    -19.76mA   -15.06mA   -24.85mA
-479mV    -10.5mA    -7.76mA    -13.5mA
-410mV    -5.313mA   -3.84mA    -6.916mA
-341mV    -2.007mA   -1.45mA    -2.59mA
-272mV    -506.9uA   -403.5uA   -609.8uA
-180mV    -45.65uA   -51.35uA   -43.55uA
1.1V      0A         0A         0A
[POWER_clamp]
|Voltage   I(typ)   I(min)   I(max)
-1.1V     5.691mA    8.967mA    3.44mA
-1.062V   3.709mA    6.444mA    2.092mA
-1.039V   2.781mA    5.152mA    1.546mA
-1.016V   2.086mA    4.085mA    1.193mA
-970mV    1.21mA     2.539mA    818.5uA
-947mV    943.7uA    2.005mA    716.7uA
-901mV    610.1uA    1.27mA     581.3uA
-855mV    430.7uA    824.1uA    484.6uA
-786mV    289.9uA    439.4uA    366uA
-671mV    155.9uA    155.9uA    203.6uA
-441mV    13.2uA     12.79uA    15.03uA
1.1V      0A         0A         0A
[Ramp]
| variable   typ   min   max
dV/dt_r   0.146/31.912p   0.143/41.249p   0.153/25.777p
dV/dt_f   72.904m/44.911p   68.572m/59.341p   73.268m/35.020p
R_load = 50.000
[Rising Waveform]
R_fixture= 50.000
V_fixture= 1.100
V_fixture_min= 1.060
V_fixture_max= 1.170
|time   V(typ)   V(min)   V(max)
0s        978.5mV    945.7mV    1.048V
140ps     978.8mV    945.9mV    1.047V
193ps     975.4mV    946mV      1.121V
263ps     1.062V     940.6mV    1.159V
281ps     1.074V     951.9mV    1.161V
329ps     1.091V     1.016V     1.165V
375ps     1.096V     1.043V     1.168V
458ps     1.098V     1.057V     1.17V
657ps     1.1V       1.06V      1.17V
3ns       1.1V       1.06V      1.17V
[Rising Waveform]
R_fixture= 50.000
V_fixture= 0.0
V_fixture_min= 0.0
V_fixture_max= 0.0
|time   V(typ)   V(min)   V(max)
0s        5.234uV    19.06uV    1.239uV
150ps     -123.5uV   56.39uV    6.594mV
192ps     849.6uV    -48.1uV    221.1mV
215ps     10.36mV    -159.2uV   291.7mV
265ps     213.8mV    1.368mV    336.4mV
298ps     275.8mV    21.4mV     289mV
374ps     298.5mV    239.5mV    257mV
478ps     244.8mV    279.6mV    255.1mV
634ps     243.9mV    238.7mV    255mV
3ns       243.9mV    238.7mV    255mV
[Falling Waveform]
R_fixture= 50.000
V_fixture= 1.100
V_fixture_min= 1.060
V_fixture_max= 1.170
|time   V(typ)   V(min)   V(max)
0s        1.1V       1.06V      1.17V
156ps     1.1V       1.06V      1.168V
224ps     1.095V     1.06V      1.046V
269ps     1.026V     1.058V     1.004V
315ps     971.3mV    1.052V     1.029V
360ps     945.8mV    1.005V     1.041V
417ps     963.2mV    949.2mV    1.046V
491ps     975.5mV    920.4mV    1.047V
684ps     978.5mV    945.1mV    1.048V
3ns       978.5mV    945.7mV    1.048V
[Falling Waveform]
R_fixture= 50.000
V_fixture= 0.0
V_fixture_min= 0.0
V_fixture_max= 0.0
|time   V(typ)   V(min)   V(max)
0s        243.9mV    238.7mV    255mV
143ps     243.6mV    238.4mV    258.6mV
194ps     251.9mV    238.7mV    87.45mV
210ps     223.5mV    241.3mV    57.58mV
260ps     71.13mV    248.5mV    15.34mV
312ps     19.12mV    118mV      3.119mV
341ps     9.25mV     60.51mV    1.519mV
375ps     3.402mV    26.92mV    649.4uV
500ps     80.24uV    1.047mV    29.13uV
3ns       5.24uV     19.07uV    904.5nV
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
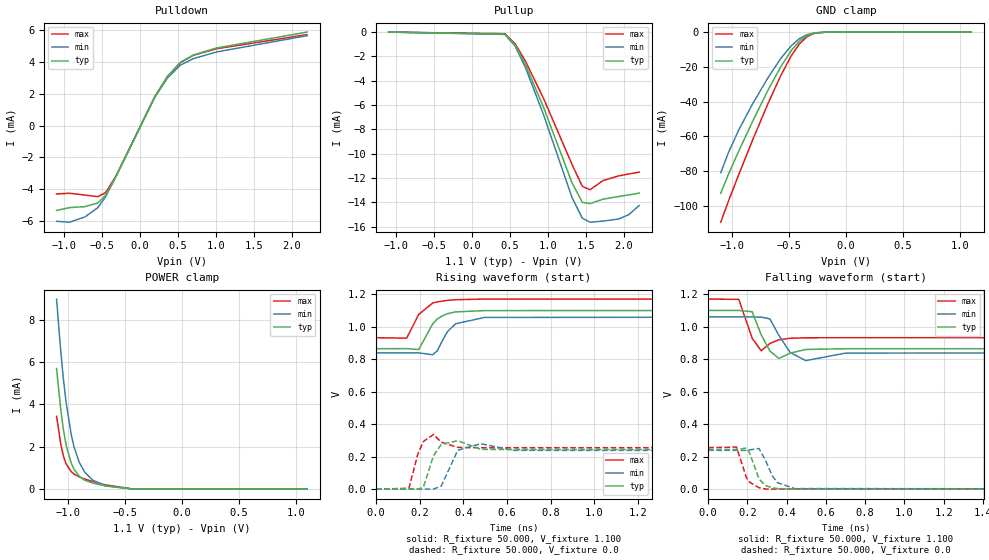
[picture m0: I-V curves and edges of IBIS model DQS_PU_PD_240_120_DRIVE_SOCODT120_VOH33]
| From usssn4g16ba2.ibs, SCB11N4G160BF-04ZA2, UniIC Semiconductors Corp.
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|   Model DQS_PU_PD_240_120_DRIVE_SOCODT120_VOH33
[Model] DQS_PU_PD_240_120_DRIVE_SOCODT120_VOH33
Model_type I/O
Polarity   Inverting
Vinl =  98.000mV
Vinh =  0.268V
Vmeas =  0.183V
Rref =  50.000
Vref =  0.183V
C_comp   1.020pF   1.010pF   1.030pF
[Model Spec]
Vinh   0.268V   0.262V   0.280V
Vinl   98.000mV   92.000mV   0.110V
Vmeas   0.183V   0.177V   0.195V
Vref   0.183V   0.177V   0.195V
Rref   50.000   NA   NA
[Temperature Range]   25.000   0.105k   -40.000
[Voltage Range]   1.100V   1.060V   1.170V
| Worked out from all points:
|   slope of the pulldown table from 0 to 0.165 V, typ, clamps not added: 105 ohm
|   GND clamp passes 1 mA (typ) near -0.30 V on its own axis
|   POWER clamp passes 1 mA (typ) near -0.95 V on its own axis
|   rising waveform, R_fixture 50.000, V_fixture 1.100: 20-80 % time 66.6ps typ, 68.9ps min, 65ps max; typ from 0.864 V to 1.1 V
|   rising waveform, R_fixture 50.000, V_fixture 0.0: 20-80 % time 31.5ps typ, 40.7ps min, 25.6ps max; typ from 0 V to 0.244 V
|   falling waveform, R_fixture 50.000, V_fixture 1.100: 20-80 % time 43.8ps typ, 57.3ps min, 34.4ps max; typ from 1.1 V to 0.864 V
|   falling waveform, R_fixture 50.000, V_fixture 0.0: 20-80 % time 47.7ps typ, 58.5ps min, 44ps max; typ from 0.244 V to 0 V
[Pulldown]
|Voltage   I(typ)   I(min)   I(max)
-1.1V     -5.34mA    -6.026mA   -4.302mA
-930mV    -5.164mA   -6.082mA   -4.26mA
-726mV    -5.101mA   -5.754mA   -4.373mA
-556mV    -4.87mA    -5.165mA   -4.475mA
-454mV    -4.386mA   -4.479mA   -4.222mA
-318mV    -3.209mA   -3.211mA   -3.18mA
192mV     1.799mA    1.766mA    1.806mA
362mV     3.096mA    3.011mA    3.096mA
532mV     3.983mA    3.811mA    3.973mA
702mV     4.448mA    4.219mA    4.427mA
1.008V    4.891mA    4.64mA     4.842mA
2.2V      5.891mA    5.665mA    5.73mA
[Pullup]
|Voltage   I(typ)   I(min)   I(max)
-1.1V     1nA        10.92nA    0A
432mV     -168.8uA   -190.8uA   -131.8uA
568mV     -1.092mA   -1.17mA    -975.3uA
704mV     -2.706mA   -2.942mA   -2.412mA
942mV     -6.202mA   -6.816mA   -5.469mA
1.316V    -12.39mA   -13.6mA    -10.88mA
1.452V    -13.99mA   -15.3mA    -12.68mA
1.554V    -14.09mA   -15.62mA   -12.95mA
1.724V    -13.73mA   -15.53mA   -12.2mA
1.928V    -13.51mA   -15.36mA   -11.82mA
2.064V    -13.38mA   -15mA      -11.66mA
2.2V      -13.23mA   -14.25mA   -11.51mA
[GND_clamp]
|Voltage   I(typ)   I(min)   I(max)
-1.1V     -92.78mA   -81.05mA   -109.5mA
-1.031V   -81.73mA   -69.22mA   -97.17mA
-939mV    -68.18mA   -56.02mA   -81.64mA
-824mV    -52mA      -41.83mA   -62.83mA
-686mV    -33.62mA   -26.41mA   -41.32mA
-571mV    -19.76mA   -15.06mA   -24.85mA
-479mV    -10.5mA    -7.76mA    -13.5mA
-410mV    -5.313mA   -3.84mA    -6.916mA
-341mV    -2.007mA   -1.45mA    -2.59mA
-272mV    -506.9uA   -403.5uA   -609.8uA
-180mV    -45.65uA   -51.35uA   -43.55uA
1.1V      0A         0A         0A
[POWER_clamp]
|Voltage   I(typ)   I(min)   I(max)
-1.1V     5.691mA    8.967mA    3.44mA
-1.062V   3.709mA    6.444mA    2.092mA
-1.039V   2.781mA    5.152mA    1.546mA
-1.016V   2.086mA    4.085mA    1.193mA
-970mV    1.21mA     2.539mA    818.5uA
-947mV    943.7uA    2.005mA    716.7uA
-901mV    610.1uA    1.27mA     581.3uA
-855mV    430.7uA    824.1uA    484.6uA
-786mV    289.9uA    439.4uA    366uA
-671mV    155.9uA    155.9uA    203.6uA
-441mV    13.2uA     12.79uA    15.03uA
1.1V      0A         0A         0A
[Ramp]
| variable   typ   min   max
dV/dt_r   0.146/31.634p   0.143/40.801p   0.153/25.685p
dV/dt_f   0.141/43.825p   0.133/57.197p   0.143/34.473p
R_load = 50.000
[Rising Waveform]
R_fixture= 50.000
V_fixture= 1.100
V_fixture_min= 1.060
V_fixture_max= 1.170
|time   V(typ)   V(min)   V(max)
0s        864.4mV    838.5mV    932.1mV
140ps     865mV      838.7mV    929.4mV
195ps     859.3mV    838.8mV    1.075V
259ps     1.017V     827.3mV    1.146V
280ps     1.047V     851.2mV    1.153V
302ps     1.066V     909.9mV    1.157V
327ps     1.08V      970mV      1.162V
364ps     1.091V     1.018V     1.166V
497ps     1.099V     1.057V     1.17V
3ns       1.1V       1.06V      1.17V
[Rising Waveform]
R_fixture= 50.000
V_fixture= 0.0
V_fixture_min= 0.0
V_fixture_max= 0.0
|time   V(typ)   V(min)   V(max)
0s        4.355uV    15.89uV    1.03uV
150ps     -33.07uV   45.13uV    5.325mV
191ps     432.3uV    10.97uV    215.1mV
216ps     9.935mV    -1.402uV   293mV
263ps     206.2mV    557.2uV    336.3mV
298ps     275.5mV    18.61mV    289mV
374ps     298.3mV    239.4mV    257mV
479ps     244.8mV    279.8mV    255.1mV
631ps     243.9mV    238.7mV    255mV
3ns       243.9mV    238.7mV    255mV
[Falling Waveform]
R_fixture= 50.000
V_fixture= 1.100
V_fixture_min= 1.060
V_fixture_max= 1.170
|time   V(typ)   V(min)   V(max)
0s        1.1V       1.06V      1.17V
156ps     1.1V       1.06V      1.168V
224ps     1.092V     1.06V      928.5mV
270ps     949.8mV    1.059V     852mV
314ps     850.9mV    1.048V     896.3mV
360ps     804.3mV    946.8mV    919.4mV
418ps     837mV      840.9mV    928.6mV
497ps     859.6mV    791.1mV    931.5mV
702ps     864.3mV    837.7mV    932.1mV
3ns       864.4mV    838.5mV    932.1mV
[Falling Waveform]
R_fixture= 50.000
V_fixture= 0.0
V_fixture_min= 0.0
V_fixture_max= 0.0
|time   V(typ)   V(min)   V(max)
0s        243.9mV    238.7mV    255mV
144ps     243.7mV    238.4mV    258.6mV
194ps     252.7mV    238.7mV    72.86mV
210ps     225.6mV    241.2mV    43.25mV
259ps     61.64mV    249.6mV    8.45mV
292ps     22.1mV     177mV      451.5uV
326ps     7.694mV    82.93mV    -62.56uV
352ps     3.44mV     40.04mV    -23.21uV
440ps     -508.5uV   3.219mV    539.2nV
3ns       3.161uV    15.88uV    -795.7nV
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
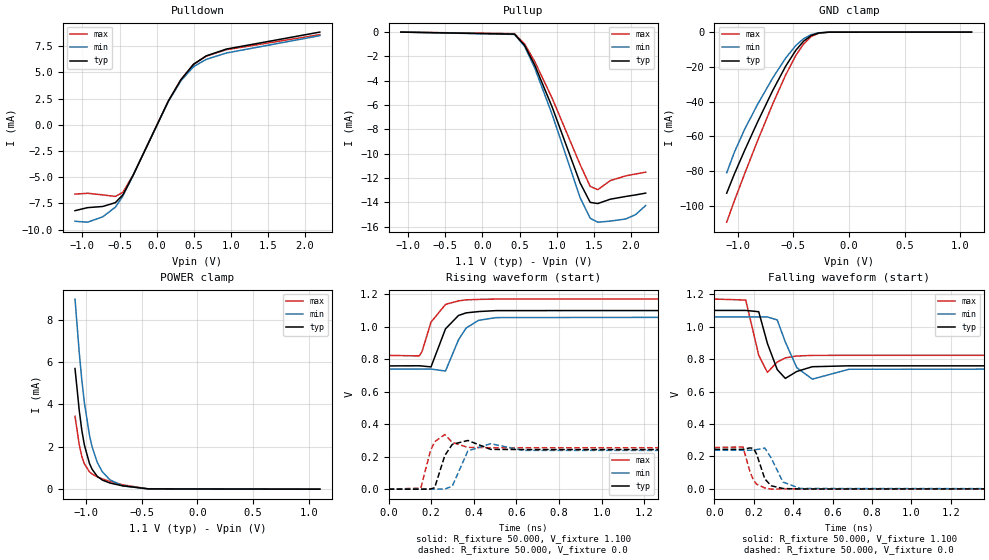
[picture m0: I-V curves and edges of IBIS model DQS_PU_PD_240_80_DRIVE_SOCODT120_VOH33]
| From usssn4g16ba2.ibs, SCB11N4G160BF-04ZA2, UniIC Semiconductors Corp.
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|   Model DQS_PU_PD_240_80_DRIVE_SOCODT120_VOH33
[Model] DQS_PU_PD_240_80_DRIVE_SOCODT120_VOH33
Model_type I/O
Polarity   Inverting
Vinl =  98.000mV
Vinh =  0.268V
Vmeas =  0.183V
Rref =  50.000
Vref =  0.183V
C_comp   1.020pF   1.010pF   1.030pF
[Model Spec]
Vinh   0.268V   0.262V   0.280V
Vinl   98.000mV   92.000mV   0.110V
Vmeas   0.183V   0.177V   0.195V
Vref   0.183V   0.177V   0.195V
Rref   50.000   NA   NA
[Temperature Range]   25.000   0.105k   -40.000
[Voltage Range]   1.100V   1.060V   1.170V
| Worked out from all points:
|   slope of the pulldown table from 0 to 0.165 V, typ, clamps not added: 70.2 ohm
|   GND clamp passes 1 mA (typ) near -0.30 V on its own axis
|   POWER clamp passes 1 mA (typ) near -0.95 V on its own axis
|   rising waveform, R_fixture 50.000, V_fixture 1.100: 20-80 % time 67.9ps typ, 70.6ps min, 65.7ps max; typ from 0.759 V to 1.1 V
|   rising waveform, R_fixture 50.000, V_fixture 0.0: 20-80 % time 31.5ps typ, 40.5ps min, 25.7ps max; typ from 0 V to 0.244 V
|   falling waveform, R_fixture 50.000, V_fixture 1.100: 20-80 % time 43.3ps typ, 56.6ps min, 34.4ps max; typ from 1.1 V to 0.759 V
|   falling waveform, R_fixture 50.000, V_fixture 0.0: 20-80 % time 42.7ps typ, 56.1ps min, 38.4ps max; typ from 0.244 V to 0 V
[Pulldown]
|Voltage   I(typ)   I(min)   I(max)
-1.1V     -8.193mA   -9.206mA   -6.618mA
-930mV    -7.906mA   -9.295mA   -6.537mA
-726mV    -7.797mA   -8.78mA    -6.691mA
-556mV    -7.432mA   -7.863mA   -6.841mA
-454mV    -6.673mA   -6.794mA   -6.44mA
-318mV    -4.841mA   -4.838mA   -4.804mA
158mV     2.257mA    2.219mA    2.267mA
328mV     4.302mA    4.194mA    4.305mA
498mV     5.77mA     5.539mA    5.759mA
668mV     6.567mA    6.233mA    6.54mA
940mV     7.217mA    6.841mA    7.152mA
2.2V      8.836mA    8.496mA    8.595mA
[Pullup]
|Voltage   I(typ)   I(min)   I(max)
-1.1V     1nA        10.92nA    0A
432mV     -168.8uA   -190.8uA   -131.8uA
568mV     -1.092mA   -1.17mA    -975.3uA
704mV     -2.706mA   -2.942mA   -2.412mA
942mV     -6.202mA   -6.816mA   -5.469mA
1.316V    -12.39mA   -13.6mA    -10.88mA
1.452V    -13.99mA   -15.3mA    -12.68mA
1.554V    -14.09mA   -15.62mA   -12.95mA
1.724V    -13.73mA   -15.53mA   -12.2mA
1.928V    -13.51mA   -15.36mA   -11.82mA
2.064V    -13.38mA   -15mA      -11.66mA
2.2V      -13.23mA   -14.25mA   -11.51mA
[GND_clamp]
|Voltage   I(typ)   I(min)   I(max)
-1.1V     -92.78mA   -81.05mA   -109.5mA
-1.031V   -81.73mA   -69.22mA   -97.17mA
-939mV    -68.18mA   -56.02mA   -81.64mA
-824mV    -52mA      -41.83mA   -62.83mA
-686mV    -33.62mA   -26.41mA   -41.32mA
-571mV    -19.76mA   -15.06mA   -24.85mA
-479mV    -10.5mA    -7.76mA    -13.5mA
-410mV    -5.313mA   -3.84mA    -6.916mA
-341mV    -2.007mA   -1.45mA    -2.59mA
-272mV    -506.9uA   -403.5uA   -609.8uA
-180mV    -45.65uA   -51.35uA   -43.55uA
1.1V      0A         0A         0A
[POWER_clamp]
|Voltage   I(typ)   I(min)   I(max)
-1.1V     5.691mA    8.967mA    3.44mA
-1.062V   3.709mA    6.444mA    2.092mA
-1.039V   2.781mA    5.152mA    1.546mA
-1.016V   2.086mA    4.085mA    1.193mA
-970mV    1.21mA     2.539mA    818.5uA
-947mV    943.7uA    2.005mA    716.7uA
-901mV    610.1uA    1.27mA     581.3uA
-855mV    430.7uA    824.1uA    484.6uA
-786mV    289.9uA    439.4uA    366uA
-671mV    155.9uA    155.9uA    203.6uA
-441mV    13.2uA     12.79uA    15.03uA
1.1V      0A         0A         0A
[Ramp]
| variable   typ   min   max
dV/dt_r   0.146/31.561p   0.143/40.517p   0.153/25.792p
dV/dt_f   0.205/43.467p   0.193/56.679p   0.208/34.505p
R_load = 50.000
[Rising Waveform]
R_fixture= 50.000
V_fixture= 1.100
V_fixture_min= 1.060
V_fixture_max= 1.170
|time   V(typ)   V(min)   V(max)
0s        758.6mV    738.8mV    823.3mV
144ps     759.4mV    739.2mV    820.1mV
157ps     758mV      739.5mV    847.8mV
199ps     752.4mV    739.3mV    1.028V
267ps     986.6mV    726.9mV    1.137V
328ps     1.069V     919.1mV    1.159V
364ps     1.085V     991.9mV    1.165V
422ps     1.093V     1.039V     1.168V
505ps     1.099V     1.056V     1.17V
3ns       1.1V       1.06V      1.17V
[Rising Waveform]
R_fixture= 50.000
V_fixture= 0.0
V_fixture_min= 0.0
V_fixture_max= 0.0
|time   V(typ)   V(min)   V(max)
0s        3.731uV    13.63uV    881.9nV
151ps     -3.997uV   30.23uV    6.343mV
196ps     833uV      21.12uV    234.7mV
216ps     8.706mV    106uV      292.1mV
264ps     207.7mV    519.7uV    336.3mV
299ps     275.9mV    18.58mV    287.5mV
372ps     299.7mV    235.6mV    257.2mV
479ps     244.8mV    279.8mV    255.1mV
632ps     243.9mV    238.7mV    255mV
3ns       243.9mV    238.7mV    255mV
[Falling Waveform]
R_fixture= 50.000
V_fixture= 1.100
V_fixture_min= 1.060
V_fixture_max= 1.170
|time   V(typ)   V(min)   V(max)
0s        1.1V       1.06V      1.17V
159ps     1.1V       1.06V      1.164V
225ps     1.092V     1.06V      823.5mV
269ps     896.6mV    1.06V      718.2mV
319ps     735.2mV    1.041V     782.1mV
360ps     681mV      905.5mV    807.3mV
418ps     723.5mV    747.6mV    819mV
497ps     752.9mV    676.3mV    822.6mV
684ps     758.5mV    737.4mV    823.3mV
3ns       758.6mV    738.8mV    823.3mV
[Falling Waveform]
R_fixture= 50.000
V_fixture= 0.0
V_fixture_min= 0.0
V_fixture_max= 0.0
|time   V(typ)   V(min)   V(max)
0s        243.9mV    238.7mV    255mV
145ps     243.7mV    238.4mV    257.9mV
180ps     252.4mV    238mV      107.8mV
198ps     249.8mV    239.1mV    54.02mV
214ps     214.8mV    242.1mV    28.79mV
256ps     61.09mV    251.4mV    5.49mV
288ps     19.14mV    190.5mV    -1.905mV
348ps     2.209mV    41.86mV    -432.8uV
436ps     -953.5uV   2.348mV    -14.8uV
3ns       -1.257uV   13.53uV    556.3nV
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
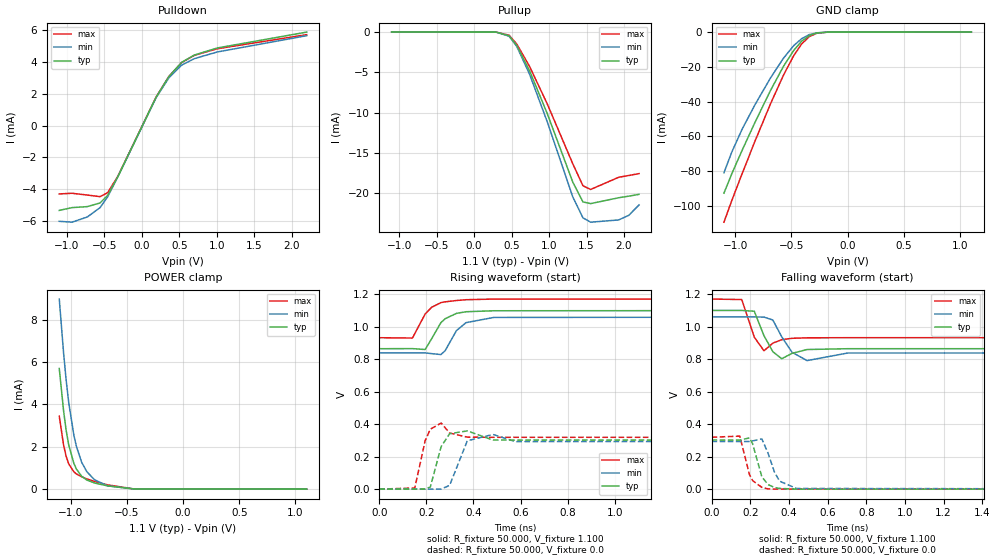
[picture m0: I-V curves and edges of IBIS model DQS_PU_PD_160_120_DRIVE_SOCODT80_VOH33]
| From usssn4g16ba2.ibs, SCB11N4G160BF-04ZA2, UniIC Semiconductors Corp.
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|   Model DQS_PU_PD_160_120_DRIVE_SOCODT80_VOH33
[Model] DQS_PU_PD_160_120_DRIVE_SOCODT80_VOH33
Model_type I/O
Polarity   Inverting
Vinl =  98.000mV
Vinh =  0.268V
Vmeas =  0.183V
Rref =  50.000
Vref =  0.183V
C_comp   1.020pF   1.010pF   1.030pF
[Model Spec]
Vinh   0.268V   0.262V   0.280V
Vinl   98.000mV   92.000mV   0.110V
Vmeas   0.183V   0.177V   0.195V
Vref   0.183V   0.177V   0.195V
Rref   50.000   NA   NA
[Temperature Range]   25.000   0.105k   -40.000
[Voltage Range]   1.100V   1.060V   1.170V
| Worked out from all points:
|   slope of the pulldown table from 0 to 0.165 V, typ, clamps not added: 105 ohm
|   GND clamp passes 1 mA (typ) near -0.30 V on its own axis
|   POWER clamp passes 1 mA (typ) near -0.95 V on its own axis
|   rising waveform, R_fixture 50.000, V_fixture 1.100: 20-80 % time 65.1ps typ, 66.4ps min, 64ps max; typ from 0.864 V to 1.1 V
|   rising waveform, R_fixture 50.000, V_fixture 0.0: 20-80 % time 29.5ps typ, 38.2ps min, 23.8ps max; typ from 0 V to 0.302 V
|   falling waveform, R_fixture 50.000, V_fixture 1.100: 20-80 % time 44ps typ, 58ps min, 34.4ps max; typ from 1.1 V to 0.864 V
|   falling waveform, R_fixture 50.000, V_fixture 0.0: 20-80 % time 46.7ps typ, 57.1ps min, 43.2ps max; typ from 0.302 V to 0 V
[Pulldown]
|Voltage   I(typ)   I(min)   I(max)
-1.1V     -5.34mA    -6.026mA   -4.302mA
-930mV    -5.164mA   -6.082mA   -4.26mA
-726mV    -5.101mA   -5.754mA   -4.373mA
-556mV    -4.87mA    -5.165mA   -4.475mA
-454mV    -4.386mA   -4.479mA   -4.222mA
-318mV    -3.209mA   -3.211mA   -3.18mA
192mV     1.799mA    1.766mA    1.806mA
362mV     3.096mA    3.011mA    3.096mA
532mV     3.983mA    3.811mA    3.973mA
702mV     4.448mA    4.219mA    4.427mA
1.008V    4.891mA    4.64mA     4.842mA
2.2V      5.891mA    5.665mA    5.73mA
[Pullup]
|Voltage   I(typ)   I(min)   I(max)
-1.1V     1.606nA    16.44nA    0A
296mV     -8.845uA   -14.64uA   -4.922uA
466mV     -464.7uA   -507.7uA   -387.5uA
568mV     -1.641mA   -1.758mA   -1.466mA
738mV     -4.764mA   -5.196mA   -4.236mA
976mV     -10.14mA   -11.16mA   -8.932mA
1.316V    -18.65mA   -20.49mA   -16.37mA
1.452V    -21.12mA   -23.1mA    -19.11mA
1.554V    -21.33mA   -23.64mA   -19.57mA
1.928V    -20.6mA    -23.36mA   -18.06mA
2.064V    -20.4mA    -22.78mA   -17.83mA
2.2V      -20.18mA   -21.49mA   -17.6mA
[GND_clamp]
|Voltage   I(typ)   I(min)   I(max)
-1.1V     -92.78mA   -81.05mA   -109.5mA
-1.031V   -81.73mA   -69.22mA   -97.17mA
-939mV    -68.18mA   -56.02mA   -81.64mA
-824mV    -52mA      -41.83mA   -62.83mA
-686mV    -33.62mA   -26.41mA   -41.32mA
-571mV    -19.76mA   -15.06mA   -24.85mA
-479mV    -10.5mA    -7.76mA    -13.5mA
-410mV    -5.313mA   -3.84mA    -6.916mA
-341mV    -2.007mA   -1.45mA    -2.59mA
-272mV    -506.9uA   -403.5uA   -609.8uA
-180mV    -45.65uA   -51.35uA   -43.55uA
1.1V      0A         0A         0A
[POWER_clamp]
|Voltage   I(typ)   I(min)   I(max)
-1.1V     5.691mA    8.967mA    3.44mA
-1.062V   3.709mA    6.444mA    2.092mA
-1.039V   2.781mA    5.152mA    1.546mA
-1.016V   2.086mA    4.085mA    1.193mA
-970mV    1.21mA     2.539mA    818.5uA
-947mV    943.7uA    2.005mA    716.7uA
-901mV    610.1uA    1.27mA     581.3uA
-855mV    430.7uA    824.1uA    484.6uA
-786mV    289.9uA    439.4uA    366uA
-671mV    155.9uA    155.9uA    203.6uA
-441mV    13.2uA     12.79uA    15.03uA
1.1V      0A         0A         0A
[Ramp]
| variable   typ   min   max
dV/dt_r   0.181/29.597p   0.176/38.280p   0.192/23.991p
dV/dt_f   0.141/44.087p   0.133/58.117p   0.143/34.475p
R_load = 50.000
[Rising Waveform]
R_fixture= 50.000
V_fixture= 1.100
V_fixture_min= 1.060
V_fixture_max= 1.170
|time   V(typ)   V(min)   V(max)
0s        864.4mV    838.5mV    932.1mV
141ps     865mV      838.7mV    930.1mV
195ps     859.4mV    838.8mV    1.078V
223ps     926.9mV    834mV      1.12V
262ps     1.025V     828.4mV    1.148V
280ps     1.049V     852.4mV    1.153V
328ps     1.082V     976.2mV    1.161V
369ps     1.092V     1.025V     1.166V
487ps     1.098V     1.057V     1.17V
3ns       1.1V       1.06V      1.17V
[Rising Waveform]
R_fixture= 50.000
V_fixture= 0.0
V_fixture_min= 0.0
V_fixture_max= 0.0
|time   V(typ)   V(min)   V(max)
0s        4.355uV    15.89uV    1.03uV
151ps     -98.45uV   54.57uV    7.252mV
195ps     798.1uV    -34.89uV   298.1mV
217ps     12.99mV    -115.3uV   369mV
263ps     262mV      610.4uV    406.8mV
299ps     341.3mV    23.23mV    345.7mV
374ps     358.6mV    297.7mV    319.9mV
483ps     302.1mV    336.7mV    319.2mV
578ps     302.1mV    292.7mV    319.2mV
3ns       302.1mV    293.3mV    319.2mV
[Falling Waveform]
R_fixture= 50.000
V_fixture= 1.100
V_fixture_min= 1.060
V_fixture_max= 1.170
|time   V(typ)   V(min)   V(max)
0s        1.1V       1.06V      1.17V
156ps     1.1V       1.06V      1.167V
221ps     1.095V     1.06V      935.5mV
271ps     944.6mV    1.059V     851.5mV
317ps     845.8mV    1.041V     898.6mV
363ps     802.7mV    937.5mV    920.1mV
416ps     835.5mV    842.6mV    928.4mV
494ps     859.3mV    791.1mV    931.4mV
704ps     864.3mV    837.7mV    932.1mV
3ns       864.4mV    838.5mV    932.1mV
[Falling Waveform]
R_fixture= 50.000
V_fixture= 0.0
V_fixture_min= 0.0
V_fixture_max= 0.0
|time   V(typ)   V(min)   V(max)
0s        302.1mV    293.3mV    319.2mV
146ps     301.7mV    292.8mV    326.1mV
196ps     315mV      293.2mV    89.52mV
212ps     280.2mV    296.7mV    52.96mV
260ps     75.88mV    309mV      10.63mV
292ps     27.93mV    221.7mV    1.352mV
326ps     9.716mV    102.6mV    258.3uV
352ps     4.317mV    48.85mV    122.2uV
439ps     -463.8uV   3.938mV    10.55uV
3ns       4.2uV      15.83uV    989.4nV
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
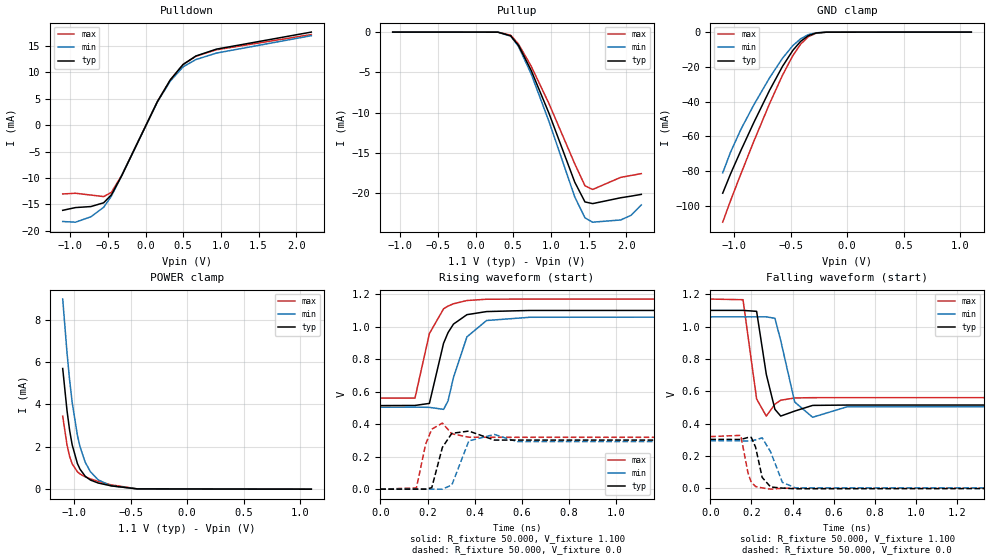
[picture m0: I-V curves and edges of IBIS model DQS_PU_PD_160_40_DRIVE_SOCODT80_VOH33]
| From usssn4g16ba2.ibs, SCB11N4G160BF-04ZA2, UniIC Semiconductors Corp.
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|   Model DQS_PU_PD_160_40_DRIVE_SOCODT80_VOH33
[Model] DQS_PU_PD_160_40_DRIVE_SOCODT80_VOH33
Model_type I/O
Polarity   Inverting
Vinl =  98.000mV
Vinh =  0.268V
Vmeas =  0.183V
Rref =  50.000
Vref =  0.183V
C_comp   1.020pF   1.010pF   1.030pF
[Model Spec]
Vinh   0.268V   0.262V   0.280V
Vinl   98.000mV   92.000mV   0.110V
Vmeas   0.183V   0.177V   0.195V
Vref   0.183V   0.177V   0.195V
Rref   50.000   NA   NA
[Temperature Range]   25.000   0.105k   -40.000
[Voltage Range]   1.100V   1.060V   1.170V
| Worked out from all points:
|   slope of the pulldown table from 0 to 0.165 V, typ, clamps not added: 35.3 ohm
|   GND clamp passes 1 mA (typ) near -0.30 V on its own axis
|   POWER clamp passes 1 mA (typ) near -0.95 V on its own axis
|   rising waveform, R_fixture 50.000, V_fixture 1.100: 20-80 % time 69ps typ, 72.5ps min, 66.6ps max; typ from 0.514 V to 1.1 V
|   rising waveform, R_fixture 50.000, V_fixture 0.0: 20-80 % time 29.1ps typ, 37.5ps min, 23.7ps max; typ from 0 V to 0.302 V
|   falling waveform, R_fixture 50.000, V_fixture 1.100: 20-80 % time 39.3ps typ, 52.3ps min, 32.1ps max; typ from 1.1 V to 0.514 V
|   falling waveform, R_fixture 50.000, V_fixture 0.0: 20-80 % time 31.6ps typ, 49.5ps min, 26.8ps max; typ from 0.302 V to 0 V
[Pulldown]
|Voltage   I(typ)   I(min)   I(max)
-1.1V     -16.13mA   -18.25mA   -13.03mA
-930mV    -15.61mA   -18.38mA   -12.9mA
-726mV    -15.42mA   -17.36mA   -13.24mA
-556mV    -14.7mA    -15.55mA   -13.53mA
-454mV    -13.2mA    -13.45mA   -12.73mA
-318mV    -9.609mA   -9.606mA   -9.529mA
158mV     4.492mA    4.415mA    4.512mA
328mV     8.568mA    8.352mA    8.576mA
498mV     11.5mA     11.04mA    11.48mA
668mV     13.1mA     12.43mA    13.05mA
940mV     14.4mA     13.65mA    14.28mA
2.2V      17.63mA    16.95mA    17.16mA
[Pullup]
|Voltage   I(typ)   I(min)   I(max)
-1.1V     1.606nA    16.44nA    0A
296mV     -8.845uA   -14.64uA   -4.922uA
466mV     -464.7uA   -507.7uA   -387.5uA
568mV     -1.641mA   -1.758mA   -1.466mA
738mV     -4.764mA   -5.196mA   -4.236mA
976mV     -10.14mA   -11.16mA   -8.932mA
1.316V    -18.65mA   -20.49mA   -16.37mA
1.452V    -21.12mA   -23.1mA    -19.11mA
1.554V    -21.33mA   -23.64mA   -19.57mA
1.928V    -20.6mA    -23.36mA   -18.06mA
2.064V    -20.4mA    -22.78mA   -17.83mA
2.2V      -20.18mA   -21.49mA   -17.6mA
[GND_clamp]
|Voltage   I(typ)   I(min)   I(max)
-1.1V     -92.78mA   -81.05mA   -109.5mA
-1.031V   -81.73mA   -69.22mA   -97.17mA
-939mV    -68.18mA   -56.02mA   -81.64mA
-824mV    -52mA      -41.83mA   -62.83mA
-686mV    -33.62mA   -26.41mA   -41.32mA
-571mV    -19.76mA   -15.06mA   -24.85mA
-479mV    -10.5mA    -7.76mA    -13.5mA
-410mV    -5.313mA   -3.84mA    -6.916mA
-341mV    -2.007mA   -1.45mA    -2.59mA
-272mV    -506.9uA   -403.5uA   -609.8uA
-180mV    -45.65uA   -51.35uA   -43.55uA
1.1V      0A         0A         0A
[POWER_clamp]
|Voltage   I(typ)   I(min)   I(max)
-1.1V     5.691mA    8.967mA    3.44mA
-1.062V   3.709mA    6.444mA    2.092mA
-1.039V   2.781mA    5.152mA    1.546mA
-1.016V   2.086mA    4.085mA    1.193mA
-970mV    1.21mA     2.539mA    818.5uA
-947mV    943.7uA    2.005mA    716.7uA
-901mV    610.1uA    1.27mA     581.3uA
-855mV    430.7uA    824.1uA    484.6uA
-786mV    289.9uA    439.4uA    366uA
-671mV    155.9uA    155.9uA    203.6uA
-441mV    13.2uA     12.79uA    15.03uA
1.1V      0A         0A         0A
[Ramp]
| variable   typ   min   max
dV/dt_r   0.181/29.054p   0.176/37.584p   0.192/23.693p
dV/dt_f   0.351/39.489p   0.333/52.353p   0.366/32.143p
R_load = 50.000
[Rising Waveform]
R_fixture= 50.000
V_fixture= 1.100
V_fixture_min= 1.060
V_fixture_max= 1.170
|time   V(typ)   V(min)   V(max)
0s        514.4mV    504.3mV    560.3mV
147ps     515.3mV    504.9mV    560.8mV
208ps     527.8mV    503.5mV    957.7mV
268ps     898mV      491.1mV    1.11V
287ps     963.7mV    543.2mV    1.127V
310ps     1.016V     687.9mV    1.141V
367ps     1.074V     937.5mV    1.161V
450ps     1.093V     1.038V     1.169V
634ps     1.1V       1.058V     1.17V
3ns       1.1V       1.06V      1.17V
[Rising Waveform]
R_fixture= 50.000
V_fixture= 0.0
V_fixture_min= 0.0
V_fixture_max= 0.0
|time   V(typ)   V(min)   V(max)
0s        2.608uV    9.547uV    615.8nV
153ps     169.3uV    32.25uV    7.456mV
192ps     420.2uV    84.24uV    276.2mV
218ps     9.014mV    345.3uV    369.4mV
263ps     257.2mV    117.5uV    406.7mV
303ps     343.7mV    25.61mV    340.6mV
375ps     357.5mV    297.2mV    319.9mV
483ps     302.1mV    336.8mV    319.2mV
579ps     302.1mV    292.7mV    319.2mV
3ns       302.1mV    293.3mV    319.2mV
[Falling Waveform]
R_fixture= 50.000
V_fixture= 1.100
V_fixture_min= 1.060
V_fixture_max= 1.170
|time   V(typ)   V(min)   V(max)
0s        1.1V       1.06V      1.17V
159ps     1.1V       1.06V      1.166V
225ps     1.094V     1.06V      552.2mV
272ps     704.5mV    1.06V      446mV
314ps     487.9mV    1.051V     519.9mV
342ps     446.2mV    913.9mV    544.2mV
410ps     477.2mV    533.1mV    558.3mV
497ps     512.3mV    438.9mV    560.1mV
664ps     514.4mV    503.5mV    560.3mV
3ns       514.4mV    504.3mV    560.3mV
[Falling Waveform]
R_fixture= 50.000
V_fixture= 0.0
V_fixture_min= 0.0
V_fixture_max= 0.0
|time   V(typ)   V(min)   V(max)
0s        302.1mV    293.3mV    319.2mV
148ps     301.7mV    292.8mV    327mV
183ps     313.8mV    292.3mV    95.48mV
199ps     314.5mV    293.5mV    37.21mV
220ps     254.1mV    299mV      10.61mV
252ps     66.8mV     311.6mV    1.92mV
293ps     7.698mV    224.9mV    -5.828mV
350ps     672.7uV    36.53mV    -426.1uV
413ps     -3.506mV   2.353mV    -9.994uV
3ns       2.509uV    6.602uV    140.6nV
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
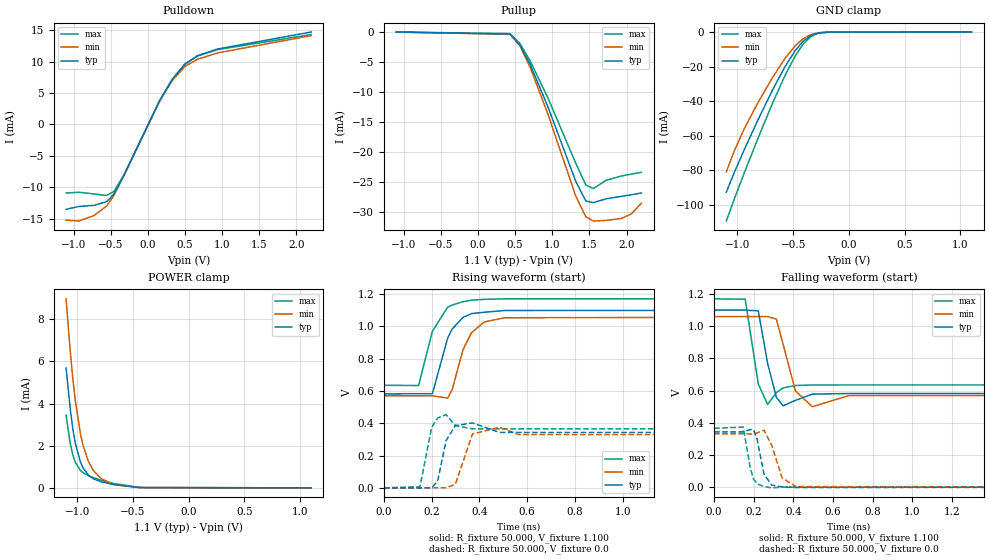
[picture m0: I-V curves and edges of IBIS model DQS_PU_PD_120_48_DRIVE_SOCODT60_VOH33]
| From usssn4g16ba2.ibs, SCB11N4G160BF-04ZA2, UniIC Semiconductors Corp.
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|   Model DQS_PU_PD_120_48_DRIVE_SOCODT60_VOH33
[Model] DQS_PU_PD_120_48_DRIVE_SOCODT60_VOH33
Model_type I/O
Polarity   Inverting
Vinl =  98.000mV
Vinh =  0.268V
Vmeas =  0.183V
Rref =  50.000
Vref =  0.183V
C_comp   1.020pF   1.010pF   1.030pF
[Model Spec]
Vinh   0.268V   0.262V   0.280V
Vinl   98.000mV   92.000mV   0.110V
Vmeas   0.183V   0.177V   0.195V
Vref   0.183V   0.177V   0.195V
Rref   50.000   NA   NA
[Temperature Range]   25.000   0.105k   -40.000
[Voltage Range]   1.100V   1.060V   1.170V
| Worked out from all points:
|   slope of the pulldown table from 0 to 0.165 V, typ, clamps not added: 42.3 ohm
|   GND clamp passes 1 mA (typ) near -0.30 V on its own axis
|   POWER clamp passes 1 mA (typ) near -0.95 V on its own axis
|   rising waveform, R_fixture 50.000, V_fixture 1.100: 20-80 % time 68.1ps typ, 70.7ps min, 66.2ps max; typ from 0.582 V to 1.1 V
|   rising waveform, R_fixture 50.000, V_fixture 0.0: 20-80 % time 27.6ps typ, 35.9ps min, 22.5ps max; typ from 0 V to 0.343 V
|   falling waveform, R_fixture 50.000, V_fixture 1.100: 20-80 % time 41.4ps typ, 54.7ps min, 33.2ps max; typ from 1.1 V to 0.582 V
|   falling waveform, R_fixture 50.000, V_fixture 0.0: 20-80 % time 34.3ps typ, 50ps min, 29.7ps max; typ from 0.343 V to 0 V
[Pulldown]
|Voltage   I(typ)   I(min)   I(max)
-1.1V     -13.51mA   -15.24mA   -10.91mA
-930mV    -13.06mA   -15.37mA   -10.79mA
-726mV    -12.89mA   -14.52mA   -11.06mA
-556mV    -12.29mA   -13.01mA   -11.31mA
-454mV    -11.04mA   -11.25mA   -10.65mA
-318mV    -8.03mA    -8.027mA   -7.964mA
158mV     3.751mA    3.687mA    3.768mA
328mV     7.153mA    6.973mA    7.158mA
498mV     9.598mA    9.214mA    9.581mA
668mV     10.93mA    10.37mA    10.89mA
940mV     12.01mA    11.39mA    11.91mA
2.2V      14.71mA    14.14mA    14.31mA
[Pullup]
|Voltage   I(typ)   I(min)   I(max)
-1.1V     2.106nA    21.95nA    0A
432mV     -337.7uA   -381.6uA   -263.6uA
568mV     -2.186mA   -2.341mA   -1.952mA
704mV     -5.417mA   -5.891mA   -4.827mA
942mV     -12.42mA   -13.65mA   -10.95mA
1.316V    -24.8mA    -27.25mA   -21.78mA
1.452V    -28.09mA   -30.72mA   -25.42mA
1.554V    -28.36mA   -31.42mA   -26.03mA
1.724V    -27.73mA   -31.32mA   -24.66mA
1.928V    -27.33mA   -31mA      -23.94mA
2.064V    -27.06mA   -30.24mA   -23.63mA
2.2V      -26.76mA   -28.47mA   -23.32mA
[GND_clamp]
|Voltage   I(typ)   I(min)   I(max)
-1.1V     -92.78mA   -81.05mA   -109.5mA
-1.031V   -81.73mA   -69.22mA   -97.17mA
-939mV    -68.18mA   -56.02mA   -81.64mA
-824mV    -52mA      -41.83mA   -62.83mA
-686mV    -33.62mA   -26.41mA   -41.32mA
-571mV    -19.76mA   -15.06mA   -24.85mA
-479mV    -10.5mA    -7.76mA    -13.5mA
-410mV    -5.313mA   -3.84mA    -6.916mA
-341mV    -2.007mA   -1.45mA    -2.59mA
-272mV    -506.9uA   -403.5uA   -609.8uA
-180mV    -45.65uA   -51.35uA   -43.55uA
1.1V      0A         0A         0A
[POWER_clamp]
|Voltage   I(typ)   I(min)   I(max)
-1.1V     5.691mA    8.967mA    3.44mA
-1.062V   3.709mA    6.444mA    2.092mA
-1.039V   2.781mA    5.152mA    1.546mA
-1.016V   2.086mA    4.085mA    1.193mA
-970mV    1.21mA     2.539mA    818.5uA
-947mV    943.7uA    2.005mA    716.7uA
-901mV    610.1uA    1.27mA     581.3uA
-855mV    430.7uA    824.1uA    484.6uA
-786mV    289.9uA    439.4uA    366uA
-671mV    155.9uA    155.9uA    203.6uA
-441mV    13.2uA     12.79uA    15.03uA
1.1V      0A         0A         0A
[Ramp]
| variable   typ   min   max
dV/dt_r   0.206/27.771p   0.199/36.031p   0.219/22.665p
dV/dt_f   0.311/41.415p   0.294/54.618p   0.321/33.405p
R_load = 50.000
[Rising Waveform]
R_fixture= 50.000
V_fixture= 1.100
V_fixture_min= 1.060
V_fixture_max= 1.170
|time   V(typ)   V(min)   V(max)
0s        581.6mV    569.9mV    635mV
145ps     582.6mV    570.5mV    633.5mV
203ps     582.8mV    569.9mV    969.7mV
267ps     926.9mV    555.7mV    1.119V
286ps     983.6mV    608.5mV    1.132V
331ps     1.055V     854.6mV    1.152V
367ps     1.079V     960.6mV    1.162V
420ps     1.087V     1.027V     1.167V
506ps     1.098V     1.053V     1.17V
3ns       1.1V       1.06V      1.17V
[Rising Waveform]
R_fixture= 50.000
V_fixture= 0.0
V_fixture_min= 0.0
V_fixture_max= 0.0
|time   V(typ)   V(min)   V(max)
0s        2.898uV    10.6uV     684.5nV
151ps     17.73uV    38.93uV    7.306mV
200ps     1.071mV    49.89uV    374.9mV
225ps     41.26mV    178.1uV    432.3mV
260ps     290.9mV    187.8uV    453.2mV
299ps     385.6mV    20.78mV    385.8mV
371ps     402mV      333.8mV    365.3mV
484ps     343mV      374.7mV    365.2mV
565ps     343.2mV    329.8mV    365.2mV
3ns       343.2mV    331.4mV    365.2mV
[Falling Waveform]
R_fixture= 50.000
V_fixture= 1.100
V_fixture_min= 1.060
V_fixture_max= 1.170
|time   V(typ)   V(min)   V(max)
0s        1.1V       1.06V      1.17V
157ps     1.1V       1.06V      1.168V
223ps     1.095V     1.06V      640.6mV
270ps     769.1mV    1.06V      513.4mV
314ps     558.9mV    1.044V     587.1mV
348ps     504.9mV    888.2mV    616.4mV
410ps     538.9mV    598.8mV    631.4mV
495ps     577.7mV    499.3mV    634.6mV
680ps     581.5mV    568.9mV    635mV
3ns       581.6mV    569.9mV    635mV
[Falling Waveform]
R_fixture= 50.000
V_fixture= 0.0
V_fixture_min= 0.0
V_fixture_max= 0.0
|time   V(typ)   V(min)   V(max)
0s        343.2mV    331.4mV    365.2mV
147ps     342.8mV    330.8mV    372.9mV
183ps     357.6mV    330.2mV    116.3mV
199ps     356.7mV    331.7mV    50.04mV
217ps     297mV      337mV      19.2mV
252ps     80.23mV    353.4mV    3.227mV
291ps     12.26mV    259mV      -4.856mV
343ps     1.251mV    56.87mV    -677.1uV
412ps     -3.129mV   3.252mV    -19.63uV
3ns       -1.038uV   10.53uV    257.9nV
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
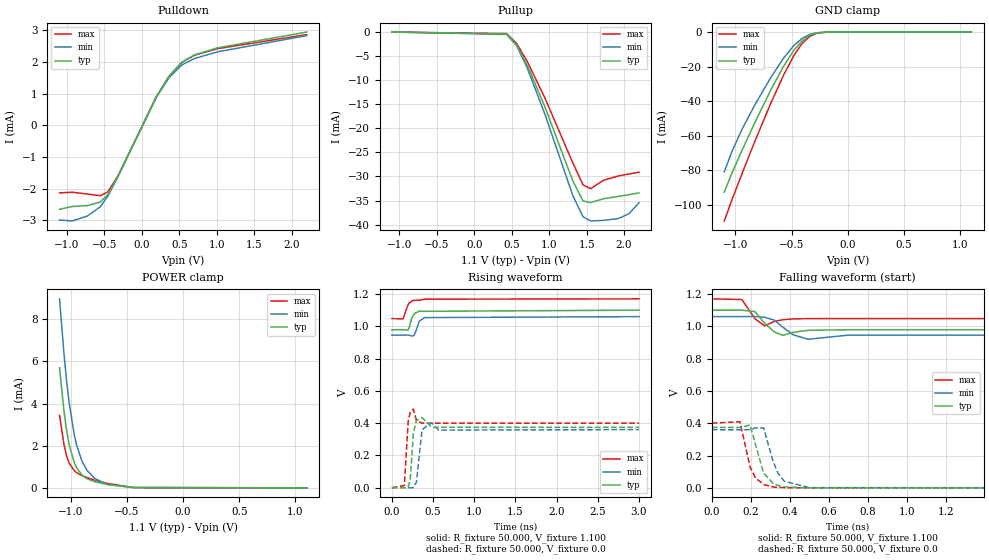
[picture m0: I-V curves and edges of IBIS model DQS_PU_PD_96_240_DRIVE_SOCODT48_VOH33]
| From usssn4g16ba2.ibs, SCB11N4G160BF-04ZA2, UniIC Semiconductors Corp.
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|   Model DQS_PU_PD_96_240_DRIVE_SOCODT48_VOH33
[Model] DQS_PU_PD_96_240_DRIVE_SOCODT48_VOH33
Model_type I/O
Polarity   Inverting
Vinl =  98.000mV
Vinh =  0.268V
Vmeas =  0.183V
Rref =  50.000
Vref =  0.183V
C_comp   1.020pF   1.010pF   1.030pF
[Model Spec]
Vinh   0.268V   0.262V   0.280V
Vinl   98.000mV   92.000mV   0.110V
Vmeas   0.183V   0.177V   0.195V
Vref   0.183V   0.177V   0.195V
Rref   50.000   NA   NA
[Temperature Range]   25.000   0.105k   -40.000
[Voltage Range]   1.100V   1.060V   1.170V
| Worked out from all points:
|   slope of the pulldown table from 0 to 0.165 V, typ, clamps not added: 211 ohm
|   GND clamp passes 1 mA (typ) near -0.30 V on its own axis
|   POWER clamp passes 1 mA (typ) near -0.95 V on its own axis
|   rising waveform, R_fixture 50.000, V_fixture 1.100: 20-80 % time 55ps typ, 51.2ps min, 57.4ps max; typ from 0.978 V to 1.1 V
|   rising waveform, R_fixture 50.000, V_fixture 0.0: 20-80 % time 27.1ps typ, 35.9ps min, 21.7ps max; typ from 0 V to 0.374 V
|   falling waveform, R_fixture 50.000, V_fixture 1.100: 20-80 % time 46.8ps typ, 66.4ps min, 35.5ps max; typ from 1.1 V to 0.978 V
|   falling waveform, R_fixture 50.000, V_fixture 0.0: 20-80 % time 55.1ps typ, 61.6ps min, 52.4ps max; typ from 0.374 V to 0 V
[Pulldown]
|Voltage   I(typ)   I(min)   I(max)
-1.1V     -2.652mA   -2.992mA   -2.134mA
-930mV    -2.565mA   -3.023mA   -2.114mA
-726mV    -2.535mA   -2.862mA   -2.171mA
-556mV    -2.422mA   -2.572mA   -2.223mA
-454mV    -2.185mA   -2.234mA   -2.101mA
-318mV    -1.604mA   -1.606mA   -1.589mA
192mV     900.6uA    884.3uA    903.8uA
362mV     1.549mA    1.507mA    1.549mA
532mV     1.993mA    1.907mA    1.988mA
702mV     2.225mA    2.111mA    2.215mA
1.008V    2.447mA    2.322mA    2.422mA
2.2V      2.948mA    2.835mA    2.866mA
[Pullup]
|Voltage   I(typ)   I(min)   I(max)
-1.1V     2.6nA      27.46nA    0A
432mV     -421.9uA   -476.8uA   -329.3uA
568mV     -2.729mA   -2.923mA   -2.437mA
704mV     -6.762mA   -7.352mA   -6.026mA
942mV     -15.5mA    -17.03mA   -13.67mA
1.316V    -30.95mA   -34mA      -27.19mA
1.452V    -35.08mA   -38.36mA   -31.74mA
1.554V    -35.42mA   -39.25mA   -32.53mA
1.724V    -34.63mA   -39.11mA   -30.79mA
1.928V    -34.12mA   -38.72mA   -29.88mA
2.064V    -33.78mA   -37.75mA   -29.49mA
2.2V      -33.41mA   -35.44mA   -29.11mA
[GND_clamp]
|Voltage   I(typ)   I(min)   I(max)
-1.1V     -92.78mA   -81.05mA   -109.5mA
-1.031V   -81.73mA   -69.22mA   -97.17mA
-939mV    -68.18mA   -56.02mA   -81.64mA
-824mV    -52mA      -41.83mA   -62.83mA
-686mV    -33.62mA   -26.41mA   -41.32mA
-571mV    -19.76mA   -15.06mA   -24.85mA
-479mV    -10.5mA    -7.76mA    -13.5mA
-410mV    -5.313mA   -3.84mA    -6.916mA
-341mV    -2.007mA   -1.45mA    -2.59mA
-272mV    -506.9uA   -403.5uA   -609.8uA
-180mV    -45.65uA   -51.35uA   -43.55uA
1.1V      0A         0A         0A
[POWER_clamp]
|Voltage   I(typ)   I(min)   I(max)
-1.1V     5.691mA    8.967mA    3.44mA
-1.062V   3.709mA    6.444mA    2.092mA
-1.039V   2.781mA    5.152mA    1.546mA
-1.016V   2.086mA    4.085mA    1.193mA
-970mV    1.21mA     2.539mA    818.5uA
-947mV    943.7uA    2.005mA    716.7uA
-901mV    610.1uA    1.27mA     581.3uA
-855mV    430.7uA    824.1uA    484.6uA
-786mV    289.9uA    439.4uA    366uA
-671mV    155.9uA    155.9uA    203.6uA
-441mV    13.2uA     12.79uA    15.03uA
1.1V      0A         0A         0A
[Ramp]
| variable   typ   min   max
dV/dt_r   0.225/27.191p   0.216/36.181p   0.240/21.935p
dV/dt_f   72.904m/46.897p   68.572m/66.396p   73.268m/35.527p
R_load = 50.000
[Rising Waveform]
R_fixture= 50.000
V_fixture= 1.100
V_fixture_min= 1.060
V_fixture_max= 1.170
|time   V(typ)   V(min)   V(max)
0s        978.5mV    945.7mV    1.048V
136ps     978.9mV    945.8mV    1.046V
194ps     976.3mV    945.9mV    1.132V
210ps     993mV      944.7mV    1.143V
240ps     1.049V     940.4mV    1.156V
260ps     1.069V     940.1mV    1.161V
281ps     1.081V     956.5mV    1.161V
333ps     1.094V     1.032V     1.162V
399ps     1.093V     1.054V     1.168V
3ns       1.1V       1.06V      1.17V
[Rising Waveform]
R_fixture= 50.000
V_fixture= 0.0
V_fixture_min= 0.0
V_fixture_max= 0.0
|time   V(typ)   V(min)   V(max)
0s        5.234uV    19.06uV    1.239uV
151ps     -348.8uV   87.08uV    13.53mV
198ps     3.248mV    -255.2uV   412.4mV
223ps     49.15mV    -614.6uV   468.1mV
261ps     338.4mV    1.241mV    487.1mV
298ps     417.9mV    35.38mV    417.3mV
366ps     434.5mV    360.3mV    400.2mV
483ps     374.1mV    402.5mV    400.4mV
565ps     374.4mV    357.3mV    400.4mV
3ns       374.4mV    360.1mV    400.4mV
[Falling Waveform]
R_fixture= 50.000
V_fixture= 1.100
V_fixture_min= 1.060
V_fixture_max= 1.170
|time   V(typ)   V(min)   V(max)
0s        1.1V       1.06V      1.17V
154ps     1.1V       1.06V      1.166V
221ps     1.091V     1.061V     1.047V
270ps     1.019V     1.056V     1.003V
321ps     964.8mV    1.038V     1.031V
364ps     944.1mV    994.3mV    1.041V
418ps     963.2mV    946.7mV    1.046V
494ps     975.6mV    920mV      1.048V
697ps     978.5mV    945.2mV    1.048V
3ns       978.5mV    945.7mV    1.048V
[Falling Waveform]
R_fixture= 50.000
V_fixture= 0.0
V_fixture_min= 0.0
V_fixture_max= 0.0
|time   V(typ)   V(min)   V(max)
0s        374.4mV    360.1mV    400.4mV
144ps     373.8mV    359.4mV    409.5mV
196ps     389.2mV    360.2mV    129.3mV
224ps     266.2mV    370.9mV    61.71mV
265ps     92.98mV    371.5mV    20.67mV
313ps     27.52mV    168.3mV    5.234mV
338ps     14.66mV    92.06mV    2.797mV
372ps     5.759mV    40.33mV    1.204mV
500ps     165.1uV    1.547mV    48.8uV
3ns       5.242uV    19.11uV    1.235uV
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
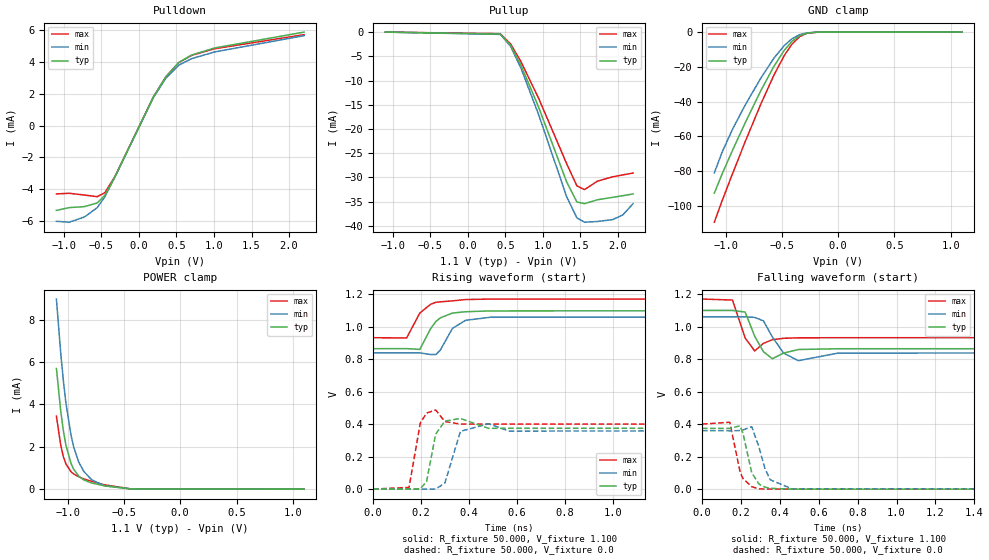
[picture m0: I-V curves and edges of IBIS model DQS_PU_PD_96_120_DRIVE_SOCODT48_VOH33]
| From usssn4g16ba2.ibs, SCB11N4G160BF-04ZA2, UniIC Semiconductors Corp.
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|   Model DQS_PU_PD_96_120_DRIVE_SOCODT48_VOH33
[Model] DQS_PU_PD_96_120_DRIVE_SOCODT48_VOH33
Model_type I/O
Polarity   Inverting
Vinl =  98.000mV
Vinh =  0.268V
Vmeas =  0.183V
Rref =  50.000
Vref =  0.183V
C_comp   1.020pF   1.010pF   1.030pF
[Model Spec]
Vinh   0.268V   0.262V   0.280V
Vinl   98.000mV   92.000mV   0.110V
Vmeas   0.183V   0.177V   0.195V
Vref   0.183V   0.177V   0.195V
Rref   50.000   NA   NA
[Temperature Range]   25.000   0.105k   -40.000
[Voltage Range]   1.100V   1.060V   1.170V
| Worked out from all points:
|   slope of the pulldown table from 0 to 0.165 V, typ, clamps not added: 105 ohm
|   GND clamp passes 1 mA (typ) near -0.30 V on its own axis
|   POWER clamp passes 1 mA (typ) near -0.95 V on its own axis
|   rising waveform, R_fixture 50.000, V_fixture 1.100: 20-80 % time 62.1ps typ, 61.3ps min, 62.4ps max; typ from 0.864 V to 1.1 V
|   rising waveform, R_fixture 50.000, V_fixture 0.0: 20-80 % time 26.9ps typ, 35.6ps min, 21.7ps max; typ from 0 V to 0.374 V
|   falling waveform, R_fixture 50.000, V_fixture 1.100: 20-80 % time 44.6ps typ, 59.7ps min, 34.7ps max; typ from 1.1 V to 0.864 V
|   falling waveform, R_fixture 50.000, V_fixture 0.0: 20-80 % time 46.8ps typ, 56.4ps min, 43.2ps max; typ from 0.374 V to 0 V
[Pulldown]
|Voltage   I(typ)   I(min)   I(max)
-1.1V     -5.34mA    -6.026mA   -4.302mA
-930mV    -5.164mA   -6.082mA   -4.26mA
-726mV    -5.101mA   -5.754mA   -4.373mA
-556mV    -4.87mA    -5.165mA   -4.475mA
-454mV    -4.386mA   -4.479mA   -4.222mA
-318mV    -3.209mA   -3.211mA   -3.18mA
192mV     1.799mA    1.766mA    1.806mA
362mV     3.096mA    3.011mA    3.096mA
532mV     3.983mA    3.811mA    3.973mA
702mV     4.448mA    4.219mA    4.427mA
1.008V    4.891mA    4.64mA     4.842mA
2.2V      5.891mA    5.665mA    5.73mA
[Pullup]
|Voltage   I(typ)   I(min)   I(max)
-1.1V     2.6nA      27.46nA    0A
432mV     -421.9uA   -476.8uA   -329.3uA
568mV     -2.729mA   -2.923mA   -2.437mA
704mV     -6.762mA   -7.352mA   -6.026mA
942mV     -15.5mA    -17.03mA   -13.67mA
1.316V    -30.95mA   -34mA      -27.19mA
1.452V    -35.08mA   -38.36mA   -31.74mA
1.554V    -35.42mA   -39.25mA   -32.53mA
1.724V    -34.63mA   -39.11mA   -30.79mA
1.928V    -34.12mA   -38.72mA   -29.88mA
2.064V    -33.78mA   -37.75mA   -29.49mA
2.2V      -33.41mA   -35.44mA   -29.11mA
[GND_clamp]
|Voltage   I(typ)   I(min)   I(max)
-1.1V     -92.78mA   -81.05mA   -109.5mA
-1.031V   -81.73mA   -69.22mA   -97.17mA
-939mV    -68.18mA   -56.02mA   -81.64mA
-824mV    -52mA      -41.83mA   -62.83mA
-686mV    -33.62mA   -26.41mA   -41.32mA
-571mV    -19.76mA   -15.06mA   -24.85mA
-479mV    -10.5mA    -7.76mA    -13.5mA
-410mV    -5.313mA   -3.84mA    -6.916mA
-341mV    -2.007mA   -1.45mA    -2.59mA
-272mV    -506.9uA   -403.5uA   -609.8uA
-180mV    -45.65uA   -51.35uA   -43.55uA
1.1V      0A         0A         0A
[POWER_clamp]
|Voltage   I(typ)   I(min)   I(max)
-1.1V     5.691mA    8.967mA    3.44mA
-1.062V   3.709mA    6.444mA    2.092mA
-1.039V   2.781mA    5.152mA    1.546mA
-1.016V   2.086mA    4.085mA    1.193mA
-970mV    1.21mA     2.539mA    818.5uA
-947mV    943.7uA    2.005mA    716.7uA
-901mV    610.1uA    1.27mA     581.3uA
-855mV    430.7uA    824.1uA    484.6uA
-786mV    289.9uA    439.4uA    366uA
-671mV    155.9uA    155.9uA    203.6uA
-441mV    13.2uA     12.79uA    15.03uA
1.1V      0A         0A         0A
[Ramp]
| variable   typ   min   max
dV/dt_r   0.225/27.123p   0.216/35.848p   0.240/21.872p
dV/dt_f   0.141/44.756p   0.133/59.767p   0.143/34.768p
R_load = 50.000
[Rising Waveform]
R_fixture= 50.000
V_fixture= 1.100
V_fixture_min= 1.060
V_fixture_max= 1.170
|time   V(typ)   V(min)   V(max)
0s        864.4mV    838.5mV    932.1mV
140ps     865mV      838.7mV    930.5mV
195ps     860.1mV    838.7mV    1.084V
240ps     988.1mV    828.4mV    1.138V
262ps     1.032V     828.8mV    1.15V
280ps     1.054V     855.4mV    1.153V
331ps     1.084V     989.7mV    1.159V
385ps     1.092V     1.039V     1.167V
488ps     1.097V     1.058V     1.17V
3ns       1.1V       1.06V      1.17V
[Rising Waveform]
R_fixture= 50.000
V_fixture= 0.0
V_fixture_min= 0.0
V_fixture_max= 0.0
|time   V(typ)   V(min)   V(max)
0s        4.355uV    15.89uV    1.03uV
150ps     -233.4uV   73.86uV    10.42mV
197ps     2.232mV    -153.6uV   407.4mV
223ps     46.54mV    -402.7uV   468.1mV
261ps     338.6mV    815.7uV    487.1mV
299ps     418.4mV    35.89mV    416mV
364ps     434.9mV    355.6mV    400.2mV
481ps     374.1mV    402.2mV    400.4mV
567ps     374.4mV    357.3mV    400.4mV
3ns       374.4mV    360.1mV    400.4mV
[Falling Waveform]
R_fixture= 50.000
V_fixture= 1.100
V_fixture_min= 1.060
V_fixture_max= 1.170
|time   V(typ)   V(min)   V(max)
0s        1.1V       1.06V      1.17V
157ps     1.1V       1.06V      1.164V
222ps     1.09V      1.061V     930.7mV
271ps     941.4mV    1.057V     850.6mV
316ps     846mV      1.036V     897.4mV
362ps     802.6mV    936.3mV    919.7mV
420ps     837.9mV    837mV      928.6mV
496ps     859.5mV    790.8mV    931.4mV
700ps     864.3mV    837.6mV    932.1mV
3ns       864.4mV    838.5mV    932.1mV
[Falling Waveform]
R_fixture= 50.000
V_fixture= 0.0
V_fixture_min= 0.0
V_fixture_max= 0.0
|time   V(typ)   V(min)   V(max)
0s        374.4mV    360.1mV    400.4mV
143ps     373.6mV    359.5mV    411.8mV
196ps     390.1mV    360.2mV    106.4mV
211ps     342.9mV    364.6mV    64.81mV
256ps     100.4mV    384.2mV    14.62mV
293ps     31.44mV    259mV      1.942mV
323ps     12.31mV    129.2mV    562.4uV
351ps     5.159mV    57.4mV     243.2uV
462ps     -202.9uV   2.338mV    9.849uV
3ns       4.151uV    15.8uV     903.7nV
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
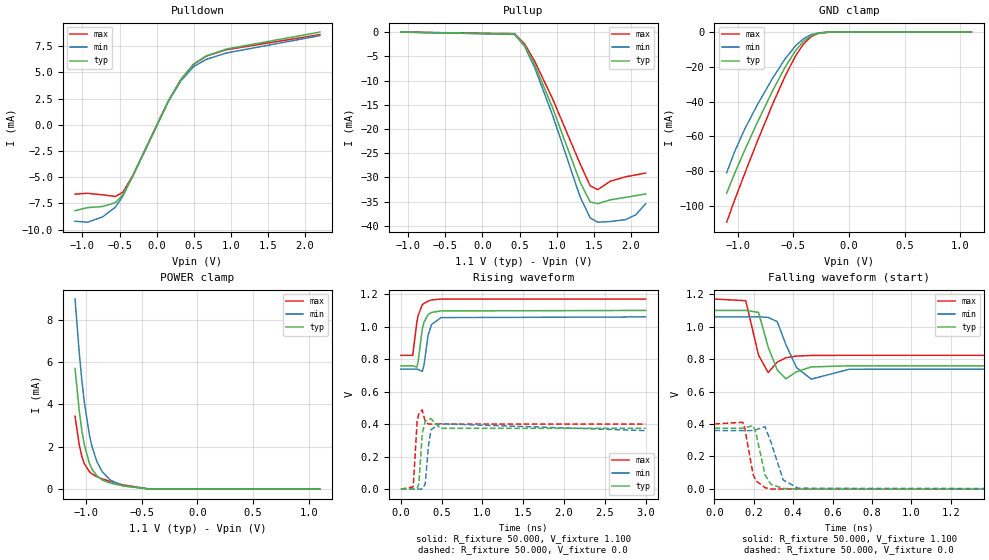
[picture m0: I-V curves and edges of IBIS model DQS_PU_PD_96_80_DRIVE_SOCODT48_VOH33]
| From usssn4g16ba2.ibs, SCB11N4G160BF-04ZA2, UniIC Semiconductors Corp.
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|   Model DQS_PU_PD_96_80_DRIVE_SOCODT48_VOH33
[Model] DQS_PU_PD_96_80_DRIVE_SOCODT48_VOH33
Model_type I/O
Polarity   Inverting
Vinl =  98.000mV
Vinh =  0.268V
Vmeas =  0.183V
Rref =  50.000
Vref =  0.183V
C_comp   1.020pF   1.010pF   1.030pF
[Model Spec]
Vinh   0.268V   0.262V   0.280V
Vinl   98.000mV   92.000mV   0.110V
Vmeas   0.183V   0.177V   0.195V
Vref   0.183V   0.177V   0.195V
Rref   50.000   NA   NA
[Temperature Range]   25.000   0.105k   -40.000
[Voltage Range]   1.100V   1.060V   1.170V
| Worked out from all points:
|   slope of the pulldown table from 0 to 0.165 V, typ, clamps not added: 70.2 ohm
|   GND clamp passes 1 mA (typ) near -0.30 V on its own axis
|   POWER clamp passes 1 mA (typ) near -0.95 V on its own axis
|   rising waveform, R_fixture 50.000, V_fixture 1.100: 20-80 % time 65.6ps typ, 66.5ps min, 64.8ps max; typ from 0.759 V to 1.1 V
|   rising waveform, R_fixture 50.000, V_fixture 0.0: 20-80 % time 26.8ps typ, 35.5ps min, 21.6ps max; typ from 0 V to 0.374 V
|   falling waveform, R_fixture 50.000, V_fixture 1.100: 20-80 % time 44.1ps typ, 58.4ps min, 34.8ps max; typ from 1.1 V to 0.759 V
|   falling waveform, R_fixture 50.000, V_fixture 0.0: 20-80 % time 42.1ps typ, 54.3ps min, 37.8ps max; typ from 0.374 V to 0 V
[Pulldown]
|Voltage   I(typ)   I(min)   I(max)
-1.1V     -8.193mA   -9.206mA   -6.618mA
-930mV    -7.906mA   -9.295mA   -6.537mA
-726mV    -7.797mA   -8.78mA    -6.691mA
-556mV    -7.432mA   -7.863mA   -6.841mA
-454mV    -6.673mA   -6.794mA   -6.44mA
-318mV    -4.841mA   -4.838mA   -4.804mA
158mV     2.257mA    2.219mA    2.267mA
328mV     4.302mA    4.194mA    4.305mA
498mV     5.77mA     5.539mA    5.759mA
668mV     6.567mA    6.233mA    6.54mA
940mV     7.217mA    6.841mA    7.152mA
2.2V      8.836mA    8.496mA    8.595mA
[Pullup]
|Voltage   I(typ)   I(min)   I(max)
-1.1V     2.6nA      27.46nA    0A
432mV     -421.9uA   -476.8uA   -329.3uA
568mV     -2.729mA   -2.923mA   -2.437mA
704mV     -6.762mA   -7.352mA   -6.026mA
942mV     -15.5mA    -17.03mA   -13.67mA
1.316V    -30.95mA   -34mA      -27.19mA
1.452V    -35.08mA   -38.36mA   -31.74mA
1.554V    -35.42mA   -39.25mA   -32.53mA
1.724V    -34.63mA   -39.11mA   -30.79mA
1.928V    -34.12mA   -38.72mA   -29.88mA
2.064V    -33.78mA   -37.75mA   -29.49mA
2.2V      -33.41mA   -35.44mA   -29.11mA
[GND_clamp]
|Voltage   I(typ)   I(min)   I(max)
-1.1V     -92.78mA   -81.05mA   -109.5mA
-1.031V   -81.73mA   -69.22mA   -97.17mA
-939mV    -68.18mA   -56.02mA   -81.64mA
-824mV    -52mA      -41.83mA   -62.83mA
-686mV    -33.62mA   -26.41mA   -41.32mA
-571mV    -19.76mA   -15.06mA   -24.85mA
-479mV    -10.5mA    -7.76mA    -13.5mA
-410mV    -5.313mA   -3.84mA    -6.916mA
-341mV    -2.007mA   -1.45mA    -2.59mA
-272mV    -506.9uA   -403.5uA   -609.8uA
-180mV    -45.65uA   -51.35uA   -43.55uA
1.1V      0A         0A         0A
[POWER_clamp]
|Voltage   I(typ)   I(min)   I(max)
-1.1V     5.691mA    8.967mA    3.44mA
-1.062V   3.709mA    6.444mA    2.092mA
-1.039V   2.781mA    5.152mA    1.546mA
-1.016V   2.086mA    4.085mA    1.193mA
-970mV    1.21mA     2.539mA    818.5uA
-947mV    943.7uA    2.005mA    716.7uA
-901mV    610.1uA    1.27mA     581.3uA
-855mV    430.7uA    824.1uA    484.6uA
-786mV    289.9uA    439.4uA    366uA
-671mV    155.9uA    155.9uA    203.6uA
-441mV    13.2uA     12.79uA    15.03uA
1.1V      0A         0A         0A
[Ramp]
| variable   typ   min   max
dV/dt_r   0.225/26.992p   0.216/35.640p   0.240/21.882p
dV/dt_f   0.205/44.104p   0.193/58.329p   0.208/34.915p
R_load = 50.000
[Rising Waveform]
R_fixture= 50.000
V_fixture= 1.100
V_fixture_min= 1.060
V_fixture_max= 1.170
|time   V(typ)   V(min)   V(max)
0s        758.6mV    738.8mV    823.3mV
145ps     759.3mV    739.2mV    823.7mV
196ps     751mV      739.4mV    1.028V
211ps     781.9mV    737mV      1.067V
263ps     986.4mV    724.5mV    1.136V
284ps     1.027V     764.5mV    1.144V
334ps     1.075V     947.4mV    1.157V
377ps     1.088V     1.014V     1.165V
494ps     1.097V     1.056V     1.17V
3ns       1.1V       1.06V      1.17V
[Rising Waveform]
R_fixture= 50.000
V_fixture= 0.0
V_fixture_min= 0.0
V_fixture_max= 0.0
|time   V(typ)   V(min)   V(max)
0s        3.731uV    13.63uV    881.9nV
152ps     -228.3uV   57.96uV    13.93mV
199ps     2.817mV    -146.4uV   415.6mV
221ps     34.04mV    -239.8uV   466.3mV
262ps     341.1mV    1.066mV    487.2mV
298ps     417.9mV    29.99mV    417.3mV
340ps     429.8mV    275.1mV    400.3mV
370ps     433mV      366.3mV    400.3mV
483ps     374.1mV    402.5mV    400.4mV
3ns       374.4mV    360.1mV    400.4mV
[Falling Waveform]
R_fixture= 50.000
V_fixture= 1.100
V_fixture_min= 1.060
V_fixture_max= 1.170
|time   V(typ)   V(min)   V(max)
0s        1.1V       1.06V      1.17V
159ps     1.1V       1.06V      1.16V
224ps     1.088V     1.061V     824.4mV
273ps     873.2mV    1.057V     717.1mV
319ps     733.7mV    1.031V     781.8mV
363ps     678.5mV    889.2mV    808.3mV
417ps     722.2mV    747.6mV    818.9mV
492ps     752.1mV    676.7mV    822.5mV
684ps     758.5mV    737.4mV    823.3mV
3ns       758.6mV    738.8mV    823.3mV
[Falling Waveform]
R_fixture= 50.000
V_fixture= 0.0
V_fixture_min= 0.0
V_fixture_max= 0.0
|time   V(typ)   V(min)   V(max)
0s        374.4mV    360.1mV    400.4mV
144ps     373.7mV    359.5mV    410.9mV
154ps     376mV      359.2mV    374.5mV
196ps     390.4mV    360.2mV    91.06mV
211ps     344.2mV    364.6mV    50.14mV
257ps     86.78mV    383.5mV    8.001mV
287ps     28.64mV    288.7mV    -911.7uV
349ps     2.972mV    55.82mV    -320.3uV
425ps     -1.326mV   4.325mV    -17.23uV
3ns       3.551uV    13.6uV     -1.988uV
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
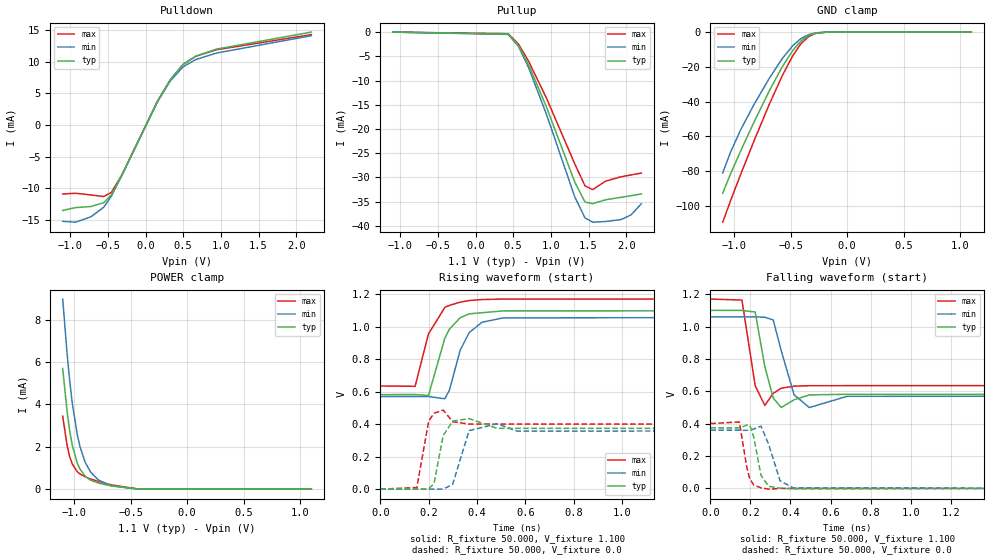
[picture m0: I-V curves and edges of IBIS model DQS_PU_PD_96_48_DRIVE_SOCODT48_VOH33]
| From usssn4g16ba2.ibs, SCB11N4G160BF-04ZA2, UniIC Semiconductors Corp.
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|   Model DQS_PU_PD_96_48_DRIVE_SOCODT48_VOH33
[Model] DQS_PU_PD_96_48_DRIVE_SOCODT48_VOH33
Model_type I/O
Polarity   Inverting
Vinl =  98.000mV
Vinh =  0.268V
Vmeas =  0.183V
Rref =  50.000
Vref =  0.183V
C_comp   1.020pF   1.010pF   1.030pF
[Model Spec]
Vinh   0.268V   0.262V   0.280V
Vinl   98.000mV   92.000mV   0.110V
Vmeas   0.183V   0.177V   0.195V
Vref   0.183V   0.177V   0.195V
Rref   50.000   NA   NA
[Temperature Range]   25.000   0.105k   -40.000
[Voltage Range]   1.100V   1.060V   1.170V
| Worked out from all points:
|   slope of the pulldown table from 0 to 0.165 V, typ, clamps not added: 42.3 ohm
|   GND clamp passes 1 mA (typ) near -0.30 V on its own axis
|   POWER clamp passes 1 mA (typ) near -0.95 V on its own axis
|   rising waveform, R_fixture 50.000, V_fixture 1.100: 20-80 % time 67.7ps typ, 70ps min, 66ps max; typ from 0.582 V to 1.1 V
|   rising waveform, R_fixture 50.000, V_fixture 0.0: 20-80 % time 26.6ps typ, 35ps min, 21.6ps max; typ from 0 V to 0.374 V
|   falling waveform, R_fixture 50.000, V_fixture 1.100: 20-80 % time 41.5ps typ, 54.9ps min, 33.4ps max; typ from 1.1 V to 0.582 V
|   falling waveform, R_fixture 50.000, V_fixture 0.0: 20-80 % time 34.9ps typ, 50.6ps min, 30ps max; typ from 0.374 V to 0 V
[Pulldown]
|Voltage   I(typ)   I(min)   I(max)
-1.1V     -13.51mA   -15.24mA   -10.91mA
-930mV    -13.06mA   -15.37mA   -10.79mA
-726mV    -12.89mA   -14.52mA   -11.06mA
-556mV    -12.29mA   -13.01mA   -11.31mA
-454mV    -11.04mA   -11.25mA   -10.65mA
-318mV    -8.03mA    -8.027mA   -7.964mA
158mV     3.751mA    3.687mA    3.768mA
328mV     7.153mA    6.973mA    7.158mA
498mV     9.598mA    9.214mA    9.581mA
668mV     10.93mA    10.37mA    10.89mA
940mV     12.01mA    11.39mA    11.91mA
2.2V      14.71mA    14.14mA    14.31mA
[Pullup]
|Voltage   I(typ)   I(min)   I(max)
-1.1V     2.6nA      27.46nA    0A
432mV     -421.9uA   -476.8uA   -329.3uA
568mV     -2.729mA   -2.923mA   -2.437mA
704mV     -6.762mA   -7.352mA   -6.026mA
942mV     -15.5mA    -17.03mA   -13.67mA
1.316V    -30.95mA   -34mA      -27.19mA
1.452V    -35.08mA   -38.36mA   -31.74mA
1.554V    -35.42mA   -39.25mA   -32.53mA
1.724V    -34.63mA   -39.11mA   -30.79mA
1.928V    -34.12mA   -38.72mA   -29.88mA
2.064V    -33.78mA   -37.75mA   -29.49mA
2.2V      -33.41mA   -35.44mA   -29.11mA
[GND_clamp]
|Voltage   I(typ)   I(min)   I(max)
-1.1V     -92.78mA   -81.05mA   -109.5mA
-1.031V   -81.73mA   -69.22mA   -97.17mA
-939mV    -68.18mA   -56.02mA   -81.64mA
-824mV    -52mA      -41.83mA   -62.83mA
-686mV    -33.62mA   -26.41mA   -41.32mA
-571mV    -19.76mA   -15.06mA   -24.85mA
-479mV    -10.5mA    -7.76mA    -13.5mA
-410mV    -5.313mA   -3.84mA    -6.916mA
-341mV    -2.007mA   -1.45mA    -2.59mA
-272mV    -506.9uA   -403.5uA   -609.8uA
-180mV    -45.65uA   -51.35uA   -43.55uA
1.1V      0A         0A         0A
[POWER_clamp]
|Voltage   I(typ)   I(min)   I(max)
-1.1V     5.691mA    8.967mA    3.44mA
-1.062V   3.709mA    6.444mA    2.092mA
-1.039V   2.781mA    5.152mA    1.546mA
-1.016V   2.086mA    4.085mA    1.193mA
-970mV    1.21mA     2.539mA    818.5uA
-947mV    943.7uA    2.005mA    716.7uA
-901mV    610.1uA    1.27mA     581.3uA
-855mV    430.7uA    824.1uA    484.6uA
-786mV    289.9uA    439.4uA    366uA
-671mV    155.9uA    155.9uA    203.6uA
-441mV    13.2uA     12.79uA    15.03uA
1.1V      0A         0A         0A
[Ramp]
| variable   typ   min   max
dV/dt_r   0.225/26.721p   0.216/35.216p   0.240/21.724p
dV/dt_f   0.311/41.532p   0.294/54.990p   0.321/33.429p
R_load = 50.000
[Rising Waveform]
R_fixture= 50.000
V_fixture= 1.100
V_fixture_min= 1.060
V_fixture_max= 1.170
|time   V(typ)   V(min)   V(max)
0s        581.6mV    569.9mV    635mV
144ps     582.6mV    570.4mV    633.1mV
199ps     576.2mV    570.5mV    955.2mV
267ps     929.8mV    556.3mV    1.119V
286ps     985.6mV    610.7mV    1.131V
330ps     1.055V     854.4mV    1.151V
367ps     1.079V     963.1mV    1.161V
420ps     1.086V     1.027V     1.167V
507ps     1.097V     1.054V     1.17V
3ns       1.1V       1.06V      1.17V
[Rising Waveform]
R_fixture= 50.000
V_fixture= 0.0
V_fixture_min= 0.0
V_fixture_max= 0.0
|time   V(typ)   V(min)   V(max)
0s        2.898uV    10.6uV     684.5nV
151ps     -62.81uV   48.19uV    9.854mV
200ps     2.007mV    -23.96uV   418.7mV
222ps     34.83mV    51.52uV    467.1mV
260ps     329.8mV    518.1uV    486.8mV
299ps     418.3mV    29.02mV    415.7mV
367ps     434.4mV    360.4mV    400.2mV
483ps     374.1mV    402.5mV    400.4mV
565ps     374.4mV    357.3mV    400.4mV
3ns       374.4mV    360.1mV    400.4mV
[Falling Waveform]
R_fixture= 50.000
V_fixture= 1.100
V_fixture_min= 1.060
V_fixture_max= 1.170
|time   V(typ)   V(min)   V(max)
0s        1.1V       1.06V      1.17V
158ps     1.1V       1.06V      1.164V
224ps     1.09V      1.06V      634.4mV
272ps     753.2mV    1.058V     512.7mV
314ps     558.3mV    1.041V     587mV
354ps     499.9mV    850.5mV    619.2mV
418ps     547.4mV    578.4mV    632mV
494ps     577.6mV    499.4mV    634.6mV
682ps     581.5mV    569mV      635mV
3ns       581.6mV    569.9mV    635mV
[Falling Waveform]
R_fixture= 50.000
V_fixture= 0.0
V_fixture_min= 0.0
V_fixture_max= 0.0
|time   V(typ)   V(min)   V(max)
0s        374.4mV    360.1mV    400.4mV
145ps     373.7mV    359.4mV    410.6mV
182ps     390.8mV    358.8mV    131.1mV
197ps     390.5mV    360.3mV    59.76mV
217ps     315.7mV    367mV      20.37mV
253ps     80.68mV    384.7mV    3.231mV
291ps     12.88mV    272.9mV    -4.823mV
348ps     1.07mV     47.6mV     -520.4uV
413ps     -3.055mV   3.262mV    -18.48uV
3ns       947.6nV    10.44uV    352.7nV
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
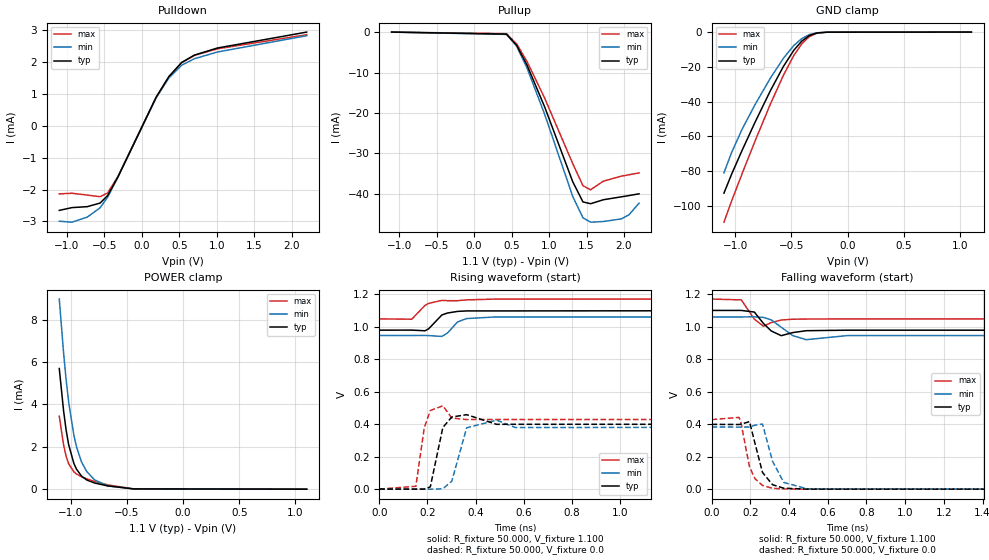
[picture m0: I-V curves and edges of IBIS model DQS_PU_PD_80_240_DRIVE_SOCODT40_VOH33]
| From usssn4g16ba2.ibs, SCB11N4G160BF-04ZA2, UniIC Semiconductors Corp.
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|   Model DQS_PU_PD_80_240_DRIVE_SOCODT40_VOH33
[Model] DQS_PU_PD_80_240_DRIVE_SOCODT40_VOH33
Model_type I/O
Polarity   Inverting
Vinl =  98.000mV
Vinh =  0.268V
Vmeas =  0.183V
Rref =  50.000
Vref =  0.183V
C_comp   1.020pF   1.010pF   1.030pF
[Model Spec]
Vinh   0.268V   0.262V   0.280V
Vinl   98.000mV   92.000mV   0.110V
Vmeas   0.183V   0.177V   0.195V
Vref   0.183V   0.177V   0.195V
Rref   50.000   NA   NA
[Temperature Range]   25.000   0.105k   -40.000
[Voltage Range]   1.100V   1.060V   1.170V
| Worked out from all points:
|   slope of the pulldown table from 0 to 0.165 V, typ, clamps not added: 211 ohm
|   GND clamp passes 1 mA (typ) near -0.30 V on its own axis
|   POWER clamp passes 1 mA (typ) near -0.95 V on its own axis
|   rising waveform, R_fixture 50.000, V_fixture 1.100: 20-80 % time 50.6ps typ, 46.1ps min, 54.1ps max; typ from 0.978 V to 1.1 V
|   rising waveform, R_fixture 50.000, V_fixture 0.0: 20-80 % time 26.2ps typ, 35.2ps min, 21ps max; typ from 0 V to 0.399 V
|   falling waveform, R_fixture 50.000, V_fixture 1.100: 20-80 % time 47.3ps typ, 69.9ps min, 35.7ps max; typ from 1.1 V to 0.978 V
|   falling waveform, R_fixture 50.000, V_fixture 0.0: 20-80 % time 54.7ps typ, 60.8ps min, 52.2ps max; typ from 0.399 V to 0 V
[Pulldown]
|Voltage   I(typ)   I(min)   I(max)
-1.1V     -2.652mA   -2.992mA   -2.134mA
-930mV    -2.565mA   -3.023mA   -2.114mA
-726mV    -2.535mA   -2.862mA   -2.171mA
-556mV    -2.422mA   -2.572mA   -2.223mA
-454mV    -2.185mA   -2.234mA   -2.101mA
-318mV    -1.604mA   -1.606mA   -1.589mA
192mV     900.6uA    884.3uA    903.8uA
362mV     1.549mA    1.507mA    1.549mA
532mV     1.993mA    1.907mA    1.988mA
702mV     2.225mA    2.111mA    2.215mA
1.008V    2.447mA    2.322mA    2.422mA
2.2V      2.948mA    2.835mA    2.866mA
[Pullup]
|Voltage   I(typ)   I(min)   I(max)
-1.1V     3.1nA      32.98nA    0A
432mV     -506.1uA   -571.8uA   -395uA
568mV     -3.269mA   -3.501mA   -2.92mA
704mV     -8.095mA   -8.8mA     -7.217mA
942mV     -18.54mA   -20.37mA   -16.36mA
1.316V    -37.03mA   -40.67mA   -32.54mA
1.452V    -42.01mA   -45.93mA   -38mA
1.554V    -42.45mA   -47.02mA   -39mA
1.724V    -41.47mA   -46.85mA   -36.88mA
1.962V    -40.75mA   -46.21mA   -35.64mA
2.064V    -40.44mA   -45.22mA   -35.29mA
2.2V      -40mA      -42.32mA   -34.84mA
[GND_clamp]
|Voltage   I(typ)   I(min)   I(max)
-1.1V     -92.78mA   -81.05mA   -109.5mA
-1.031V   -81.73mA   -69.22mA   -97.17mA
-939mV    -68.18mA   -56.02mA   -81.64mA
-824mV    -52mA      -41.83mA   -62.83mA
-686mV    -33.62mA   -26.41mA   -41.32mA
-571mV    -19.76mA   -15.06mA   -24.85mA
-479mV    -10.5mA    -7.76mA    -13.5mA
-410mV    -5.313mA   -3.84mA    -6.916mA
-341mV    -2.007mA   -1.45mA    -2.59mA
-272mV    -506.9uA   -403.5uA   -609.8uA
-180mV    -45.65uA   -51.35uA   -43.55uA
1.1V      0A         0A         0A
[POWER_clamp]
|Voltage   I(typ)   I(min)   I(max)
-1.1V     5.691mA    8.967mA    3.44mA
-1.062V   3.709mA    6.444mA    2.092mA
-1.039V   2.781mA    5.152mA    1.546mA
-1.016V   2.086mA    4.085mA    1.193mA
-970mV    1.21mA     2.539mA    818.5uA
-947mV    943.7uA    2.005mA    716.7uA
-901mV    610.1uA    1.27mA     581.3uA
-855mV    430.7uA    824.1uA    484.6uA
-786mV    289.9uA    439.4uA    366uA
-671mV    155.9uA    155.9uA    203.6uA
-441mV    13.2uA     12.79uA    15.03uA
1.1V      0A         0A         0A
[Ramp]
| variable   typ   min   max
dV/dt_r   0.239/26.483p   0.230/35.428p   0.257/21.218p
dV/dt_f   72.904m/47.403p   68.572m/69.906p   73.268m/35.722p
R_load = 50.000
[Rising Waveform]
R_fixture= 50.000
V_fixture= 1.100
V_fixture_min= 1.060
V_fixture_max= 1.170
|time   V(typ)   V(min)   V(max)
0s        978.5mV    945.7mV    1.048V
135ps     978.9mV    945.8mV    1.046V
190ps     974.7mV    946mV      1.131V
205ps     986.6mV    945.1mV    1.143V
260ps     1.072V     939.9mV    1.162V
283ps     1.084V     960.3mV    1.16V
325ps     1.094V     1.029V     1.16V
363ps     1.097V     1.05V      1.165V
486ps     1.097V     1.06V      1.17V
3ns       1.1V       1.06V      1.17V
[Rising Waveform]
R_fixture= 50.000
V_fixture= 0.0
V_fixture_min= 0.0
V_fixture_max= 0.0
|time   V(typ)   V(min)   V(max)
0s        5.234uV    19.06uV    1.239uV
152ps     -431.2uV   97.1uV     17.23mV
187ps     -74.5uV    -30.12uV   378.7mV
212ps     13.5mV     -568.9uV   483.8mV
264ps     378.9mV    1.927mV    513mV
301ps     443.6mV    47.99mV    437.5mV
363ps     458.1mV    377.2mV    427.9mV
487ps     398.7mV    424.5mV    428.3mV
565ps     398.9mV    378.9mV    428.3mV
3ns       398.9mV    382.6mV    428.3mV
[Falling Waveform]
R_fixture= 50.000
V_fixture= 1.100
V_fixture_min= 1.060
V_fixture_max= 1.170
|time   V(typ)   V(min)   V(max)
0s        1.1V       1.06V      1.17V
154ps     1.1V       1.06V      1.165V
221ps     1.09V      1.061V     1.046V
268ps     1.02V      1.057V     1.003V
308ps     973.9mV    1.042V     1.025V
360ps     944.7mV    996.6mV    1.041V
420ps     963.8mV    944.8mV    1.046V
489ps     975.3mV    920.1mV    1.047V
703ps     978.5mV    945.3mV    1.048V
3ns       978.5mV    945.7mV    1.048V
[Falling Waveform]
R_fixture= 50.000
V_fixture= 0.0
V_fixture_min= 0.0
V_fixture_max= 0.0
|time   V(typ)   V(min)   V(max)
0s        398.9mV    382.6mV    428.3mV
142ps     398mV      381.9mV    441.4mV
151ps     399.7mV    381.6mV    414.1mV
196ps     415.7mV    382.6mV    136.5mV
224ps     283.2mV    393.9mV    65.07mV
263ps     102.9mV    400.9mV    23.08mV
315ps     27.47mV    171.6mV    5.308mV
373ps     5.887mV    41.35mV    1.251mV
495ps     200.4uV    1.979mV    58.65uV
3ns       5.23uV     19.13uV    875.8nV
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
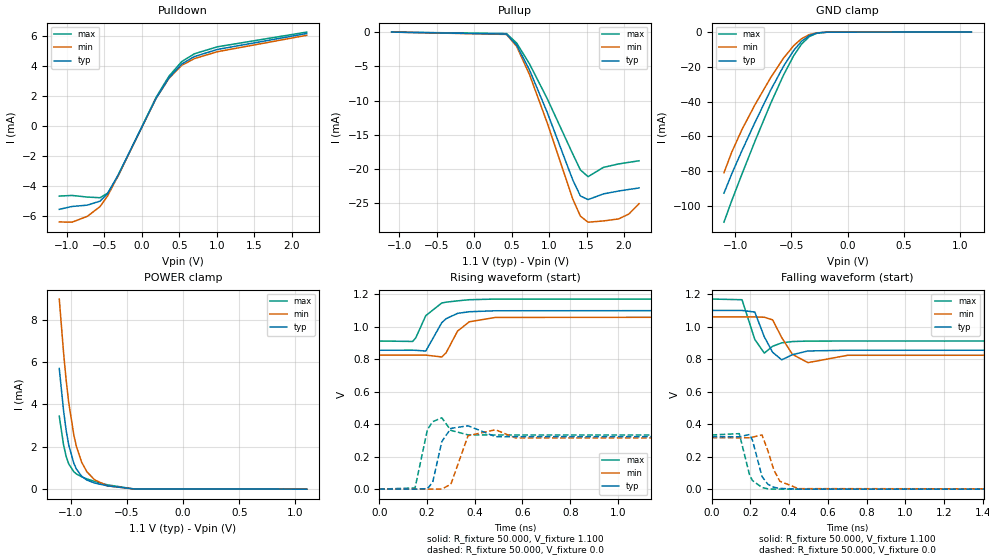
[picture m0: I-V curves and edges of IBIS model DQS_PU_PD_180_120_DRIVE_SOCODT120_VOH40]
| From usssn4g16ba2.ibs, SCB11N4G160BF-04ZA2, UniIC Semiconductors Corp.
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|   Model DQS_PU_PD_180_120_DRIVE_SOCODT120_VOH40
[Model] DQS_PU_PD_180_120_DRIVE_SOCODT120_VOH40
Model_type I/O
Polarity   Inverting
Vinl =  0.135V
Vinh =  0.305V
Vmeas =  0.220V
Rref =  50.000
Vref =  0.220V
C_comp   1.020pF   1.010pF   1.030pF
[Model Spec]
Vinh   0.305V   0.297V   0.319V
Vinl   0.135V   0.127V   0.149V
Vmeas   0.220V   0.212V   0.234V
Vref   0.220V   0.212V   0.234V
Rref   50.000   NA   NA
[Temperature Range]   25.000   0.105k   -40.000
[Voltage Range]   1.100V   1.060V   1.170V
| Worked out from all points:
|   slope of the pulldown table from 0 to 0.165 V, typ, clamps not added: 102 ohm
|   GND clamp passes 1 mA (typ) near -0.30 V on its own axis
|   POWER clamp passes 1 mA (typ) near -0.95 V on its own axis
|   rising waveform, R_fixture 50.000, V_fixture 1.100: 20-80 % time 63.8ps typ, 64.8ps min, 64.7ps max; typ from 0.855 V to 1.1 V
|   rising waveform, R_fixture 50.000, V_fixture 0.0: 20-80 % time 27.6ps typ, 35ps min, 21.7ps max; typ from 0 V to 0.323 V
|   falling waveform, R_fixture 50.000, V_fixture 1.100: 20-80 % time 45.3ps typ, 58.6ps min, 36.3ps max; typ from 1.1 V to 0.855 V
|   falling waveform, R_fixture 50.000, V_fixture 0.0: 20-80 % time 46.2ps typ, 56.3ps min, 43.6ps max; typ from 0.323 V to 0 V
[Pulldown]
|Voltage   I(typ)   I(min)   I(max)
-1.1V     -5.559mA   -6.398mA   -4.673mA
-930mV    -5.368mA   -6.416mA   -4.632mA
-726mV    -5.279mA   -6.025mA   -4.74mA
-556mV    -5.011mA   -5.376mA   -4.784mA
-454mV    -4.503mA   -4.653mA   -4.479mA
-318mV    -3.293mA   -3.335mA   -3.363mA
192mV     1.854mA    1.846mA    1.919mA
362mV     3.2mA      3.168mA    3.314mA
532mV     4.133mA    4.043mA    4.293mA
702mV     4.631mA    4.495mA    4.815mA
1.008V    5.105mA    4.953mA    5.282mA
2.2V      6.168mA    6.05mA     6.263mA
[Pullup]
|Voltage   I(typ)   I(min)   I(max)
-1.1V     1.8nA      19.34nA    0A
432mV     -294.2uA   -340.2uA   -214.5uA
568mV     -1.899mA   -2.087mA   -1.603mA
738mV     -5.508mA   -6.173mA   -4.628mA
976mV     -11.74mA   -13.27mA   -9.734mA
1.316V    -21.59mA   -24.38mA   -17.8mA
1.418V    -23.93mA   -26.88mA   -20.13mA
1.52V     -24.46mA   -27.76mA   -21.11mA
1.724V    -23.63mA   -27.58mA   -19.76mA
1.928V    -23.21mA   -27.28mA   -19.25mA
2.064V    -22.98mA   -26.57mA   -19.02mA
2.2V      -22.76mA   -25.06mA   -18.79mA
[GND_clamp]
|Voltage   I(typ)   I(min)   I(max)
-1.1V     -92.78mA   -81.05mA   -109.5mA
-1.031V   -81.73mA   -69.22mA   -97.17mA
-939mV    -68.18mA   -56.02mA   -81.64mA
-824mV    -52mA      -41.83mA   -62.83mA
-686mV    -33.62mA   -26.41mA   -41.32mA
-571mV    -19.76mA   -15.06mA   -24.85mA
-479mV    -10.5mA    -7.76mA    -13.5mA
-410mV    -5.313mA   -3.84mA    -6.916mA
-341mV    -2.007mA   -1.45mA    -2.59mA
-272mV    -506.9uA   -403.5uA   -609.8uA
-180mV    -45.65uA   -51.35uA   -43.55uA
1.1V      0A         0A         0A
[POWER_clamp]
|Voltage   I(typ)   I(min)   I(max)
-1.1V     5.691mA    8.967mA    3.44mA
-1.062V   3.709mA    6.444mA    2.092mA
-1.039V   2.781mA    5.152mA    1.546mA
-1.016V   2.086mA    4.085mA    1.193mA
-970mV    1.21mA     2.539mA    818.5uA
-947mV    943.7uA    2.005mA    716.7uA
-901mV    610.1uA    1.27mA     581.3uA
-855mV    430.7uA    824.1uA    484.6uA
-786mV    289.9uA    439.4uA    366uA
-671mV    155.9uA    155.9uA    203.6uA
-441mV    13.2uA     12.79uA    15.03uA
1.1V      0A         0A         0A
[Ramp]
| variable   typ   min   max
dV/dt_r   0.194/27.577p   0.190/35.221p   0.200/21.873p
dV/dt_f   0.147/45.337p   0.141/58.477p   0.155/36.321p
R_load = 50.000
[Rising Waveform]
R_fixture= 50.000
V_fixture= 1.100
V_fixture_min= 1.060
V_fixture_max= 1.170
|time   V(typ)   V(min)   V(max)
0s        855mV      824.7mV    911.8mV
140ps     855.6mV    825mV      909.1mV
153ps     854.4mV    825.3mV    931.4mV
195ps     850mV      825mV      1.068V
262ps     1.025V     813.6mV    1.146V
280ps     1.049V     839.1mV    1.151V
328ps     1.082V     972.9mV    1.159V
377ps     1.092V     1.03V      1.166V
487ps     1.098V     1.057V     1.17V
3ns       1.1V       1.06V      1.17V
[Rising Waveform]
R_fixture= 50.000
V_fixture= 0.0
V_fixture_min= 0.0
V_fixture_max= 0.0
|time   V(typ)   V(min)   V(max)
0s        4.315uV    15.68uV    1.011uV
150ps     -150.3uV   63.8uV     7.275mV
202ps     2.946mV    -117.9uV   367.4mV
224ps     42.51mV    -226.9uV   415.3mV
262ps     292.2mV    629.3uV    439.1mV
300ps     374.1mV    29.89mV    362mV
372ps     390mV      328.7mV    333.8mV
487ps     322.9mV    365.5mV    333.3mV
570ps     323.1mV    315.1mV    333.3mV
3ns       323.1mV    316.4mV    333.3mV
[Falling Waveform]
R_fixture= 50.000
V_fixture= 1.100
V_fixture_min= 1.060
V_fixture_max= 1.170
|time   V(typ)   V(min)   V(max)
0s        1.1V       1.06V      1.17V
157ps     1.1V       1.06V      1.166V
223ps     1.09V      1.06V      921.6mV
272ps     937.5mV    1.058V     837.3mV
315ps     842.4mV    1.042V     879.4mV
362ps     795.7mV    932.4mV    900.6mV
417ps     827.7mV    829.6mV    908.5mV
497ps     850.4mV    778.6mV    911.3mV
702ps     854.9mV    823.9mV    911.8mV
3ns       855mV      824.7mV    911.8mV
[Falling Waveform]
R_fixture= 50.000
V_fixture= 0.0
V_fixture_min= 0.0
V_fixture_max= 0.0
|time   V(typ)   V(min)   V(max)
0s        323.1mV    316.4mV    333.3mV
143ps     322.3mV    315.9mV    341.5mV
196ps     336.3mV    316.2mV    86.97mV
211ps     300.7mV    319.7mV    52.88mV
260ps     78.18mV    333.8mV    10.12mV
291ps     29.38mV    234.8mV    1.331mV
321ps     11.48mV    118.5mV    248.8uV
352ps     4.321mV    48.72mV    101.1uV
448ps     -336uV     2.93mV     7.173uV
3ns       4.093uV    15.5uV     963.8nV
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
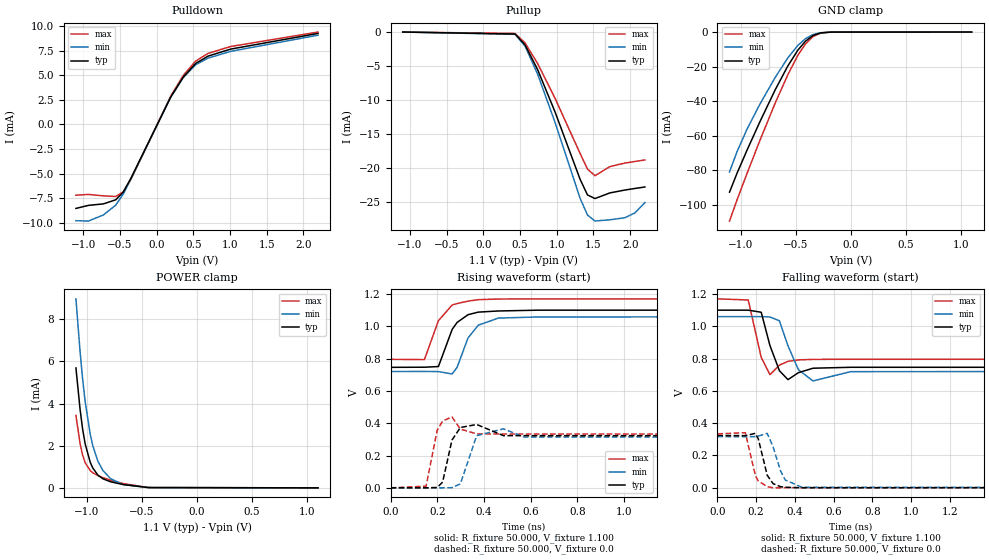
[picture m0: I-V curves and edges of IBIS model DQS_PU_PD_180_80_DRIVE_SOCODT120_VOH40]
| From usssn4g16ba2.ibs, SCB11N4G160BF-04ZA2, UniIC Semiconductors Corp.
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|   Model DQS_PU_PD_180_80_DRIVE_SOCODT120_VOH40
[Model] DQS_PU_PD_180_80_DRIVE_SOCODT120_VOH40
Model_type I/O
Polarity   Inverting
Vinl =  0.135V
Vinh =  0.305V
Vmeas =  0.220V
Rref =  50.000
Vref =  0.220V
C_comp   1.020pF   1.010pF   1.030pF
[Model Spec]
Vinh   0.305V   0.297V   0.319V
Vinl   0.135V   0.127V   0.149V
Vmeas   0.220V   0.212V   0.234V
Vref   0.220V   0.212V   0.234V
Rref   50.000   NA   NA
[Temperature Range]   25.000   0.105k   -40.000
[Voltage Range]   1.100V   1.060V   1.170V
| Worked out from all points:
|   slope of the pulldown table from 0 to 0.165 V, typ, clamps not added: 68.2 ohm
|   GND clamp passes 1 mA (typ) near -0.30 V on its own axis
|   POWER clamp passes 1 mA (typ) near -0.95 V on its own axis
|   rising waveform, R_fixture 50.000, V_fixture 1.100: 20-80 % time 66.3ps typ, 68.3ps min, 65.9ps max; typ from 0.746 V to 1.1 V
|   rising waveform, R_fixture 50.000, V_fixture 0.0: 20-80 % time 27.4ps typ, 34.8ps min, 21.8ps max; typ from 0 V to 0.323 V
|   falling waveform, R_fixture 50.000, V_fixture 1.100: 20-80 % time 44.6ps typ, 57.3ps min, 36.3ps max; typ from 1.1 V to 0.746 V
|   falling waveform, R_fixture 50.000, V_fixture 0.0: 20-80 % time 41.4ps typ, 54.2ps min, 38.4ps max; typ from 0.323 V to 0 V
[Pulldown]
|Voltage   I(typ)   I(min)   I(max)
-1.1V     -8.531mA   -9.779mA   -7.187mA
-930mV    -8.221mA   -9.809mA   -7.107mA
-726mV    -8.07mA    -9.196mA   -7.255mA
-556mV    -7.649mA   -8.186mA   -7.316mA
-454mV    -6.852mA   -7.06mA    -6.833mA
-352mV    -5.485mA   -5.559mA   -5.593mA
192mV     2.785mA    2.773mA    2.883mA
362mV     4.806mA    4.757mA    4.977mA
532mV     6.204mA    6.068mA    6.444mA
702mV     6.948mA    6.744mA    7.224mA
1.008V    7.659mA    7.43mA     7.924mA
2.2V      9.253mA    9.074mA    9.394mA
[Pullup]
|Voltage   I(typ)   I(min)   I(max)
-1.1V     1.8nA      19.34nA    0A
432mV     -294.2uA   -340.2uA   -214.5uA
568mV     -1.899mA   -2.087mA   -1.603mA
738mV     -5.508mA   -6.173mA   -4.628mA
976mV     -11.74mA   -13.27mA   -9.734mA
1.316V    -21.59mA   -24.38mA   -17.8mA
1.418V    -23.93mA   -26.88mA   -20.13mA
1.52V     -24.46mA   -27.76mA   -21.11mA
1.724V    -23.63mA   -27.58mA   -19.76mA
1.928V    -23.21mA   -27.28mA   -19.25mA
2.064V    -22.98mA   -26.57mA   -19.02mA
2.2V      -22.76mA   -25.06mA   -18.79mA
[GND_clamp]
|Voltage   I(typ)   I(min)   I(max)
-1.1V     -92.78mA   -81.05mA   -109.5mA
-1.031V   -81.73mA   -69.22mA   -97.17mA
-939mV    -68.18mA   -56.02mA   -81.64mA
-824mV    -52mA      -41.83mA   -62.83mA
-686mV    -33.62mA   -26.41mA   -41.32mA
-571mV    -19.76mA   -15.06mA   -24.85mA
-479mV    -10.5mA    -7.76mA    -13.5mA
-410mV    -5.313mA   -3.84mA    -6.916mA
-341mV    -2.007mA   -1.45mA    -2.59mA
-272mV    -506.9uA   -403.5uA   -609.8uA
-180mV    -45.65uA   -51.35uA   -43.55uA
1.1V      0A         0A         0A
[POWER_clamp]
|Voltage   I(typ)   I(min)   I(max)
-1.1V     5.691mA    8.967mA    3.44mA
-1.062V   3.709mA    6.444mA    2.092mA
-1.039V   2.781mA    5.152mA    1.546mA
-1.016V   2.086mA    4.085mA    1.193mA
-970mV    1.21mA     2.539mA    818.5uA
-947mV    943.7uA    2.005mA    716.7uA
-901mV    610.1uA    1.27mA     581.3uA
-855mV    430.7uA    824.1uA    484.6uA
-786mV    289.9uA    439.4uA    366uA
-671mV    155.9uA    155.9uA    203.6uA
-441mV    13.2uA     12.79uA    15.03uA
1.1V      0A         0A         0A
[Ramp]
| variable   typ   min   max
dV/dt_r   0.194/27.559p   0.190/34.980p   0.200/21.925p
dV/dt_f   0.212/44.769p   0.204/57.390p   0.225/36.342p
R_load = 50.000
[Rising Waveform]
R_fixture= 50.000
V_fixture= 1.100
V_fixture_min= 1.060
V_fixture_max= 1.170
|time   V(typ)   V(min)   V(max)
0s        746mV      720.2mV    795.6mV
145ps     746.8mV    720.6mV    793.9mV
205ps     751mV      719.7mV    1.035V
264ps     981.2mV    704.9mV    1.132V
285ps     1.024V     746mV      1.141V
332ps     1.072V     928.4mV    1.156V
376ps     1.088V     1.007V     1.165V
462ps     1.095V     1.051V     1.169V
633ps     1.1V       1.058V     1.17V
3ns       1.1V       1.06V      1.17V
[Rising Waveform]
R_fixture= 50.000
V_fixture= 0.0
V_fixture_min= 0.0
V_fixture_max= 0.0
|time   V(typ)   V(min)   V(max)
0s        3.687uV    13.4uV     860.8nV
152ps     -138uV     49.23uV    10.33mV
200ps     2.241mV    -60.31uV   357.9mV
223ps     35.64mV    -79.55uV   413.7mV
263ps     295.2mV    792.5uV    439.3mV
299ps     373.5mV    24.43mV    363.7mV
369ps     392.3mV    323.2mV    334mV
484ps     322.9mV    365.2mV    333.3mV
571ps     323.1mV    315mV      333.3mV
3ns       323.1mV    316.4mV    333.3mV
[Falling Waveform]
R_fixture= 50.000
V_fixture= 1.100
V_fixture_min= 1.060
V_fixture_max= 1.170
|time   V(typ)   V(min)   V(max)
0s        1.1V       1.06V      1.17V
159ps     1.1V       1.06V      1.163V
226ps     1.087V     1.06V      807.4mV
271ps     880.7mV    1.058V     700.3mV
320ps     724.5mV    1.034V     759.6mV
364ps     669.4mV    879.1mV    782.7mV
418ps     712.6mV    730.9mV    791.8mV
493ps     740.2mV    661.1mV    794.9mV
687ps     745.9mV    719mV      795.6mV
3ns       746mV      720.2mV    795.6mV
[Falling Waveform]
R_fixture= 50.000
V_fixture= 0.0
V_fixture_min= 0.0
V_fixture_max= 0.0
|time   V(typ)   V(min)   V(max)
0s        323.1mV    316.4mV    333.3mV
144ps     322.4mV    315.9mV    340.6mV
196ps     336.6mV    316.2mV    74.63mV
211ps     302.1mV    319.6mV    41.14mV
257ps     76.69mV    336.3mV    6.451mV
287ps     25.02mV    253.8mV    -1.245mV
326ps     5.837mV    103.3mV    -809.7uV
350ps     2.456mV    47.34mV    -323.5uV
436ps     -898.9uV   2.557mV    -10.58uV
3ns       3.382uV    13.34uV    507.9nV
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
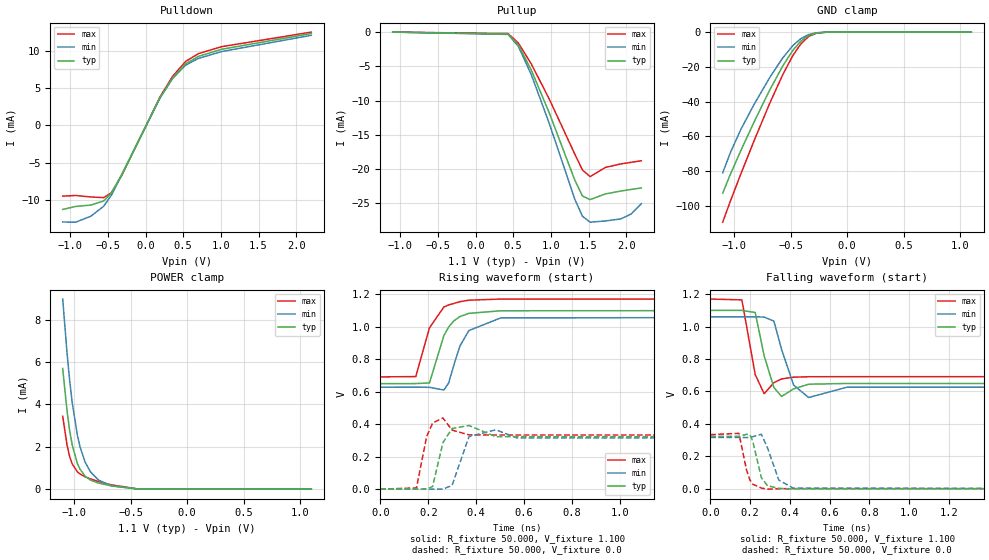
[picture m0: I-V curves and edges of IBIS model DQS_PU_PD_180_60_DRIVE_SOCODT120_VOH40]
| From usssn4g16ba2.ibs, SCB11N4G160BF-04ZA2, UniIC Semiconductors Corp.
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|   Model DQS_PU_PD_180_60_DRIVE_SOCODT120_VOH40
[Model] DQS_PU_PD_180_60_DRIVE_SOCODT120_VOH40
Model_type I/O
Polarity   Inverting
Vinl =  0.135V
Vinh =  0.305V
Vmeas =  0.220V
Rref =  50.000
Vref =  0.220V
C_comp   1.020pF   1.010pF   1.030pF
[Model Spec]
Vinh   0.305V   0.297V   0.319V
Vinl   0.135V   0.127V   0.149V
Vmeas   0.220V   0.212V   0.234V
Vref   0.220V   0.212V   0.234V
Rref   50.000   NA   NA
[Temperature Range]   25.000   0.105k   -40.000
[Voltage Range]   1.100V   1.060V   1.170V
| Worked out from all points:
|   slope of the pulldown table from 0 to 0.165 V, typ, clamps not added: 51.2 ohm
|   GND clamp passes 1 mA (typ) near -0.30 V on its own axis
|   POWER clamp passes 1 mA (typ) near -0.95 V on its own axis
|   rising waveform, R_fixture 50.000, V_fixture 1.100: 20-80 % time 67.4ps typ, 70ps min, 66.4ps max; typ from 0.649 V to 1.1 V
|   rising waveform, R_fixture 50.000, V_fixture 0.0: 20-80 % time 27.3ps typ, 34.7ps min, 21.7ps max; typ from 0 V to 0.323 V
|   falling waveform, R_fixture 50.000, V_fixture 1.100: 20-80 % time 43.5ps typ, 55.7ps min, 35.4ps max; typ from 1.1 V to 0.649 V
|   falling waveform, R_fixture 50.000, V_fixture 0.0: 20-80 % time 37.4ps typ, 52.8ps min, 33.9ps max; typ from 0.323 V to 0 V
[Pulldown]
|Voltage   I(typ)   I(min)   I(max)
-1.1V     -11.28mA   -12.96mA   -9.498mA
-930mV    -10.88mA   -12.99mA   -9.404mA
-726mV    -10.69mA   -12.19mA   -9.609mA
-556mV    -10.14mA   -10.85mA   -9.692mA
-454mV    -9.086mA   -9.369mA   -9.054mA
-318mV    -6.606mA   -6.683mA   -6.751mA
192mV     3.708mA    3.693mA    3.839mA
362mV     6.401mA    6.335mA    6.628mA
532mV     8.266mA    8.084mA    8.585mA
702mV     9.259mA    8.986mA    9.627mA
1.008V    10.21mA    9.901mA    10.56mA
2.2V      12.33mA    12.09mA    12.52mA
[Pullup]
|Voltage   I(typ)   I(min)   I(max)
-1.1V     1.8nA      19.34nA    0A
432mV     -294.2uA   -340.2uA   -214.5uA
568mV     -1.899mA   -2.087mA   -1.603mA
738mV     -5.508mA   -6.173mA   -4.628mA
976mV     -11.74mA   -13.27mA   -9.734mA
1.316V    -21.59mA   -24.38mA   -17.8mA
1.418V    -23.93mA   -26.88mA   -20.13mA
1.52V     -24.46mA   -27.76mA   -21.11mA
1.724V    -23.63mA   -27.58mA   -19.76mA
1.928V    -23.21mA   -27.28mA   -19.25mA
2.064V    -22.98mA   -26.57mA   -19.02mA
2.2V      -22.76mA   -25.06mA   -18.79mA
[GND_clamp]
|Voltage   I(typ)   I(min)   I(max)
-1.1V     -92.78mA   -81.05mA   -109.5mA
-1.031V   -81.73mA   -69.22mA   -97.17mA
-939mV    -68.18mA   -56.02mA   -81.64mA
-824mV    -52mA      -41.83mA   -62.83mA
-686mV    -33.62mA   -26.41mA   -41.32mA
-571mV    -19.76mA   -15.06mA   -24.85mA
-479mV    -10.5mA    -7.76mA    -13.5mA
-410mV    -5.313mA   -3.84mA    -6.916mA
-341mV    -2.007mA   -1.45mA    -2.59mA
-272mV    -506.9uA   -403.5uA   -609.8uA
-180mV    -45.65uA   -51.35uA   -43.55uA
1.1V      0A         0A         0A
[POWER_clamp]
|Voltage   I(typ)   I(min)   I(max)
-1.1V     5.691mA    8.967mA    3.44mA
-1.062V   3.709mA    6.444mA    2.092mA
-1.039V   2.781mA    5.152mA    1.546mA
-1.016V   2.086mA    4.085mA    1.193mA
-970mV    1.21mA     2.539mA    818.5uA
-947mV    943.7uA    2.005mA    716.7uA
-901mV    610.1uA    1.27mA     581.3uA
-855mV    430.7uA    824.1uA    484.6uA
-786mV    289.9uA    439.4uA    366uA
-671mV    155.9uA    155.9uA    203.6uA
-441mV    13.2uA     12.79uA    15.03uA
1.1V      0A         0A         0A
[Ramp]
| variable   typ   min   max
dV/dt_r   0.194/27.375p   0.190/34.837p   0.200/21.900p
dV/dt_f   0.270/43.580p   0.260/55.893p   0.287/35.521p
R_load = 50.000
[Rising Waveform]
R_fixture= 50.000
V_fixture= 1.100
V_fixture_min= 1.060
V_fixture_max= 1.170
|time   V(typ)   V(min)   V(max)
0s        649.2mV    627.2mV    691mV
148ps     649.9mV    627.8mV    693mV
205ps     653.6mV    626.8mV    992.7mV
265ps     944.7mV    610.1mV    1.121V
285ps     998.1mV    653.1mV    1.134V
307ps     1.036V     765.2mV    1.143V
332ps     1.062V     881mV      1.154V
369ps     1.082V     975.7mV    1.163V
502ps     1.098V     1.054V     1.17V
3ns       1.1V       1.06V      1.17V
[Rising Waveform]
R_fixture= 50.000
V_fixture= 0.0
V_fixture_min= 0.0
V_fixture_max= 0.0
|time   V(typ)   V(min)   V(max)
0s        3.216uV    11.69uV    749.1nV
151ps     -66.67uV   47.64uV    7.594mV
193ps     947.2uV    6.352uV    322mV
218ps     15.77mV    46.42uV    406.7mV
261ps     285.3mV    601.1uV    438.9mV
299ps     373.1mV    22.4mV     363.8mV
370ps     391.7mV    324.5mV    333.9mV
482ps     322.9mV    365mV      333.3mV
570ps     323.1mV    315mV      333.3mV
3ns       323.1mV    316.4mV    333.3mV
[Falling Waveform]
R_fixture= 50.000
V_fixture= 1.100
V_fixture_min= 1.060
V_fixture_max= 1.170
|time   V(typ)   V(min)   V(max)
0s        1.1V       1.06V      1.17V
159ps     1.1V       1.06V      1.165V
226ps     1.087V     1.06V      704.6mV
271ps     820.4mV    1.059V     585.6mV
320ps     624mV      1.034V     653.6mV
359ps     569mV      858.8mV    677.2mV
419ps     615.6mV    639.7mV    687.9mV
495ps     644.4mV    562.3mV    690.6mV
688ps     649.2mV    626.2mV    691mV
3ns       649.2mV    627.2mV    691.1mV
[Falling Waveform]
R_fixture= 50.000
V_fixture= 0.0
V_fixture_min= 0.0
V_fixture_max= 0.0
|time   V(typ)   V(min)   V(max)
0s        323.1mV    316.4mV    333.3mV
144ps     322.3mV    315.9mV    341.3mV
182ps     335.3mV    315.3mV    117.7mV
199ps     334mV      316.7mV    54.21mV
214ps     291.1mV    320.6mV    27.05mV
257ps     67.47mV    336.1mV    3.643mV
288ps     17.87mV    250.8mV    -3.244mV
345ps     1.677mV    52.47mV    -538.5uV
418ps     -2.146mV   3.173mV    -19.5uV
3ns       3.115uV    11.62uV    604.1nV
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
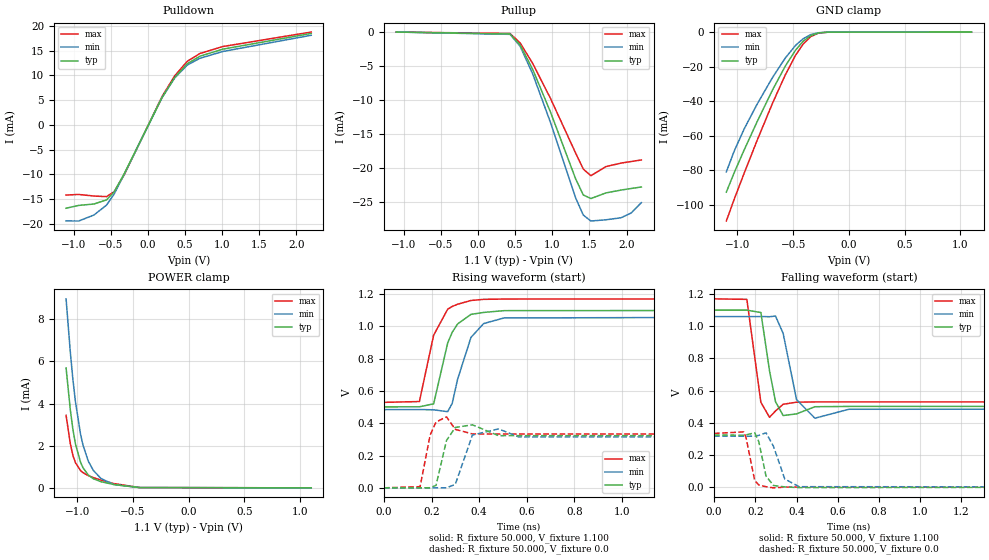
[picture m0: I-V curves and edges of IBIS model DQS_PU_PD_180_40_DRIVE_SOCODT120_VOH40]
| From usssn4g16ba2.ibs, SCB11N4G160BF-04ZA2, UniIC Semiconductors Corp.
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|   Model DQS_PU_PD_180_40_DRIVE_SOCODT120_VOH40
[Model] DQS_PU_PD_180_40_DRIVE_SOCODT120_VOH40
Model_type I/O
Polarity   Inverting
Vinl =  0.135V
Vinh =  0.305V
Vmeas =  0.220V
Rref =  50.000
Vref =  0.220V
C_comp   1.020pF   1.010pF   1.030pF
[Model Spec]
Vinh   0.305V   0.297V   0.319V
Vinl   0.135V   0.127V   0.149V
Vmeas   0.220V   0.212V   0.234V
Vref   0.220V   0.212V   0.234V
Rref   50.000   NA   NA
[Temperature Range]   25.000   0.105k   -40.000
[Voltage Range]   1.100V   1.060V   1.170V
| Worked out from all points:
|   slope of the pulldown table from 0 to 0.165 V, typ, clamps not added: 34.3 ohm
|   GND clamp passes 1 mA (typ) near -0.30 V on its own axis
|   POWER clamp passes 1 mA (typ) near -0.95 V on its own axis
|   rising waveform, R_fixture 50.000, V_fixture 1.100: 20-80 % time 68.5ps typ, 71.9ps min, 67ps max; typ from 0.501 V to 1.1 V
|   rising waveform, R_fixture 50.000, V_fixture 0.0: 20-80 % time 27.1ps typ, 34.5ps min, 21.7ps max; typ from 0 V to 0.323 V
|   falling waveform, R_fixture 50.000, V_fixture 1.100: 20-80 % time 39.7ps typ, 51ps min, 32.7ps max; typ from 1.1 V to 0.501 V
|   falling waveform, R_fixture 50.000, V_fixture 0.0: 20-80 % time 31.7ps typ, 49.8ps min, 28ps max; typ from 0.323 V to 0 V
[Pulldown]
|Voltage   I(typ)   I(min)   I(max)
-1.1V     -16.81mA   -19.37mA   -14.15mA
-930mV    -16.24mA   -19.39mA   -14.03mA
-726mV    -15.96mA   -18.19mA   -14.35mA
-556mV    -15.13mA   -16.19mA   -14.47mA
-454mV    -13.55mA   -13.98mA   -13.5mA
-318mV    -9.863mA   -9.979mA   -10.07mA
192mV     5.543mA    5.52mA     5.738mA
362mV     9.574mA    9.475mA    9.913mA
532mV     12.37mA    12.1mA     12.85mA
702mV     13.87mA    13.45mA    14.42mA
1.008V    15.29mA    14.82mA    15.82mA
2.2V      18.47mA    18.1mA     18.75mA
[Pullup]
|Voltage   I(typ)   I(min)   I(max)
-1.1V     1.8nA      19.34nA    0A
432mV     -294.2uA   -340.2uA   -214.5uA
568mV     -1.899mA   -2.087mA   -1.603mA
738mV     -5.508mA   -6.173mA   -4.628mA
976mV     -11.74mA   -13.27mA   -9.734mA
1.316V    -21.59mA   -24.38mA   -17.8mA
1.418V    -23.93mA   -26.88mA   -20.13mA
1.52V     -24.46mA   -27.76mA   -21.11mA
1.724V    -23.63mA   -27.58mA   -19.76mA
1.928V    -23.21mA   -27.28mA   -19.25mA
2.064V    -22.98mA   -26.57mA   -19.02mA
2.2V      -22.76mA   -25.06mA   -18.79mA
[GND_clamp]
|Voltage   I(typ)   I(min)   I(max)
-1.1V     -92.78mA   -81.05mA   -109.5mA
-1.031V   -81.73mA   -69.22mA   -97.17mA
-939mV    -68.18mA   -56.02mA   -81.64mA
-824mV    -52mA      -41.83mA   -62.83mA
-686mV    -33.62mA   -26.41mA   -41.32mA
-571mV    -19.76mA   -15.06mA   -24.85mA
-479mV    -10.5mA    -7.76mA    -13.5mA
-410mV    -5.313mA   -3.84mA    -6.916mA
-341mV    -2.007mA   -1.45mA    -2.59mA
-272mV    -506.9uA   -403.5uA   -609.8uA
-180mV    -45.65uA   -51.35uA   -43.55uA
1.1V      0A         0A         0A
[POWER_clamp]
|Voltage   I(typ)   I(min)   I(max)
-1.1V     5.691mA    8.967mA    3.44mA
-1.062V   3.709mA    6.444mA    2.092mA
-1.039V   2.781mA    5.152mA    1.546mA
-1.016V   2.086mA    4.085mA    1.193mA
-970mV    1.21mA     2.539mA    818.5uA
-947mV    943.7uA    2.005mA    716.7uA
-901mV    610.1uA    1.27mA     581.3uA
-855mV    430.7uA    824.1uA    484.6uA
-786mV    289.9uA    439.4uA    366uA
-671mV    155.9uA    155.9uA    203.6uA
-441mV    13.2uA     12.79uA    15.03uA
1.1V      0A         0A         0A
[Ramp]
| variable   typ   min   max
dV/dt_r   0.194/27.236p   0.190/34.426p   0.200/21.801p
dV/dt_f   0.359/39.857p   0.346/51.110p   0.384/32.772p
R_load = 50.000
[Rising Waveform]
R_fixture= 50.000
V_fixture= 1.100
V_fixture_min= 1.060
V_fixture_max= 1.170
|time   V(typ)   V(min)   V(max)
0s        501.3mV    484.2mV    529.3mV
149ps     501.8mV    484.8mV    534.3mV
209ps     520.2mV    483.1mV    945.4mV
268ps     896.8mV    471.7mV    1.106V
287ps     963.1mV    522.8mV    1.123V
310ps     1.015V     673.9mV    1.137V
366ps     1.074V     931.5mV    1.16V
419ps     1.086V     1.017V     1.167V
505ps     1.097V     1.052V     1.169V
3ns       1.1V       1.06V      1.17V
[Rising Waveform]
R_fixture= 50.000
V_fixture= 0.0
V_fixture_min= 0.0
V_fixture_max= 0.0
|time   V(typ)   V(min)   V(max)
0s        2.565uV    9.321uV    595.6nV
152ps     79.31uV    47.22uV    7.356mV
194ps     718.4uV    83.41uV    325.1mV
219ps     15.46mV    284.5uV    407.6mV
263ps     293mV      386.1uV    439.3mV
300ps     373.8mV    21.3mV     362mV
372ps     390.4mV    326.9mV    333.8mV
482ps     322.9mV    365mV      333.3mV
567ps     323.1mV    315.3mV    333.3mV
3ns       323.1mV    316.4mV    333.3mV
[Falling Waveform]
R_fixture= 50.000
V_fixture= 1.100
V_fixture_min= 1.060
V_fixture_max= 1.170
|time   V(typ)   V(min)   V(max)
0s        1.1V       1.06V      1.17V
159ps     1.1V       1.06V      1.167V
227ps     1.085V     1.06V      526.6mV
269ps     722.5mV    1.059V     433.8mV
298ps     530.7mV    1.063V     473.2mV
335ps     444.7mV    955.4mV    514.6mV
400ps     454.8mV    543.4mV    527.7mV
489ps     499.3mV    428mV      529.2mV
654ps     501.2mV    483.6mV    529.3mV
3ns       501.3mV    484.2mV    529.3mV
[Falling Waveform]
R_fixture= 50.000
V_fixture= 0.0
V_fixture_min= 0.0
V_fixture_max= 0.0
|time   V(typ)   V(min)   V(max)
0s        323.1mV    316.4mV    333.3mV
144ps     322.3mV    315.9mV    342.8mV
155ps     324mV      315.6mV    307.5mV
197ps     337.3mV    316.3mV    41.28mV
217ps     281.3mV    321.5mV    12.49mV
252ps     68.21mV    337mV      1.893mV
288ps     9.639mV    253.4mV    -5.042mV
343ps     789.6uV    49.92mV    -573.3uV
412ps     -3.486mV   2.196mV    -8.897uV
3ns       2.284uV    9.119uV    241.6nV
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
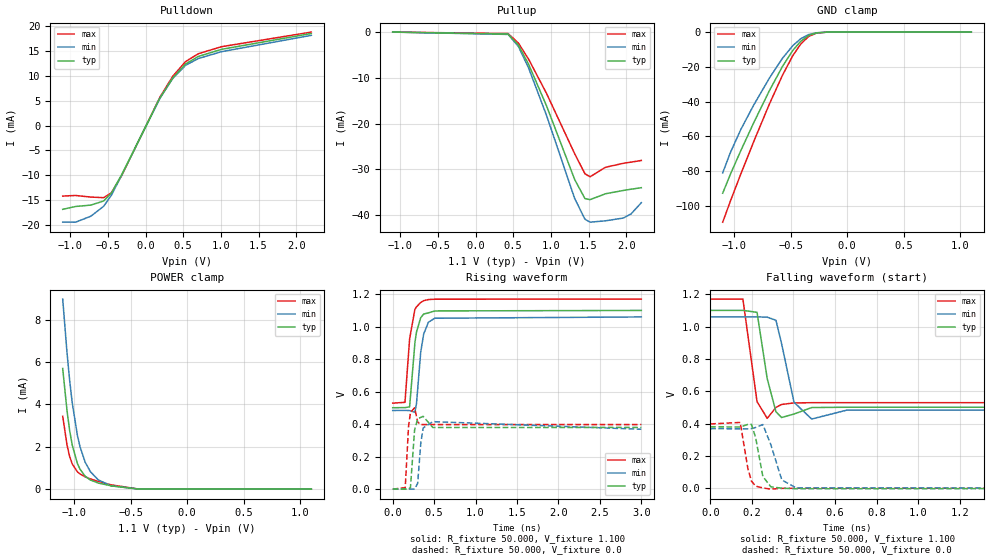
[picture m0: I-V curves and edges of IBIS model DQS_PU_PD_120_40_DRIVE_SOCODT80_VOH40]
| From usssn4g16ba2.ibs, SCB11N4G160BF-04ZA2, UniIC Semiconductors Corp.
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|   Model DQS_PU_PD_120_40_DRIVE_SOCODT80_VOH40
[Model] DQS_PU_PD_120_40_DRIVE_SOCODT80_VOH40
Model_type I/O
Polarity   Inverting
Vinl =  0.135V
Vinh =  0.305V
Vmeas =  0.220V
Rref =  50.000
Vref =  0.220V
C_comp   1.020pF   1.010pF   1.030pF
[Model Spec]
Vinh   0.305V   0.297V   0.319V
Vinl   0.135V   0.127V   0.149V
Vmeas   0.220V   0.212V   0.234V
Vref   0.220V   0.212V   0.234V
Rref   50.000   NA   NA
[Temperature Range]   25.000   0.105k   -40.000
[Voltage Range]   1.100V   1.060V   1.170V
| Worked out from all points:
|   slope of the pulldown table from 0 to 0.165 V, typ, clamps not added: 34.3 ohm
|   GND clamp passes 1 mA (typ) near -0.30 V on its own axis
|   POWER clamp passes 1 mA (typ) near -0.95 V on its own axis
|   rising waveform, R_fixture 50.000, V_fixture 1.100: 20-80 % time 67.9ps typ, 70.7ps min, 66.8ps max; typ from 0.501 V to 1.1 V
|   rising waveform, R_fixture 50.000, V_fixture 0.0: 20-80 % time 25.4ps typ, 32.9ps min, 20.2ps max; typ from 0 V to 0.38 V
|   falling waveform, R_fixture 50.000, V_fixture 1.100: 20-80 % time 39.9ps typ, 51.4ps min, 32.9ps max; typ from 1.1 V to 0.501 V
|   falling waveform, R_fixture 50.000, V_fixture 0.0: 20-80 % time 32.5ps typ, 50ps min, 28.6ps max; typ from 0.38 V to 0 V
[Pulldown]
|Voltage   I(typ)   I(min)   I(max)
-1.1V     -16.81mA   -19.37mA   -14.15mA
-930mV    -16.24mA   -19.39mA   -14.03mA
-726mV    -15.96mA   -18.19mA   -14.35mA
-556mV    -15.13mA   -16.19mA   -14.47mA
-454mV    -13.55mA   -13.98mA   -13.5mA
-318mV    -9.863mA   -9.979mA   -10.07mA
192mV     5.543mA    5.52mA     5.738mA
362mV     9.574mA    9.475mA    9.913mA
532mV     12.37mA    12.1mA     12.85mA
702mV     13.87mA    13.45mA    14.42mA
1.008V    15.29mA    14.82mA    15.82mA
2.2V      18.47mA    18.1mA     18.75mA
[Pullup]
|Voltage   I(typ)   I(min)   I(max)
-1.1V     2.7nA      29.07nA    0A
432mV     -441uA     -509.9uA   -321.6uA
568mV     -2.841mA   -3.122mA   -2.399mA
704mV     -7.035mA   -7.857mA   -5.928mA
942mV     -16.13mA   -18.22mA   -13.41mA
1.316V    -32.25mA   -36.4mA    -26.61mA
1.452V    -36.39mA   -40.9mA    -30.97mA
1.52V     -36.62mA   -41.55mA   -31.62mA
1.724V    -35.34mA   -41.25mA   -29.55mA
1.962V    -34.61mA   -40.64mA   -28.68mA
2.064V    -34.34mA   -39.74mA   -28.42mA
2.2V      -34.01mA   -37.29mA   -28.06mA
[GND_clamp]
|Voltage   I(typ)   I(min)   I(max)
-1.1V     -92.78mA   -81.05mA   -109.5mA
-1.031V   -81.73mA   -69.22mA   -97.17mA
-939mV    -68.18mA   -56.02mA   -81.64mA
-824mV    -52mA      -41.83mA   -62.83mA
-686mV    -33.62mA   -26.41mA   -41.32mA
-571mV    -19.76mA   -15.06mA   -24.85mA
-479mV    -10.5mA    -7.76mA    -13.5mA
-410mV    -5.313mA   -3.84mA    -6.916mA
-341mV    -2.007mA   -1.45mA    -2.59mA
-272mV    -506.9uA   -403.5uA   -609.8uA
-180mV    -45.65uA   -51.35uA   -43.55uA
1.1V      0A         0A         0A
[POWER_clamp]
|Voltage   I(typ)   I(min)   I(max)
-1.1V     5.691mA    8.967mA    3.44mA
-1.062V   3.709mA    6.444mA    2.092mA
-1.039V   2.781mA    5.152mA    1.546mA
-1.016V   2.086mA    4.085mA    1.193mA
-970mV    1.21mA     2.539mA    818.5uA
-947mV    943.7uA    2.005mA    716.7uA
-901mV    610.1uA    1.27mA     581.3uA
-855mV    430.7uA    824.1uA    484.6uA
-786mV    289.9uA    439.4uA    366uA
-671mV    155.9uA    155.9uA    203.6uA
-441mV    13.2uA     12.79uA    15.03uA
1.1V      0A         0A         0A
[Ramp]
| variable   typ   min   max
dV/dt_r   0.228/25.558p   0.221/32.822p   0.239/20.493p
dV/dt_f   0.359/40.018p   0.346/51.554p   0.384/32.895p
R_load = 50.000
[Rising Waveform]
R_fixture= 50.000
V_fixture= 1.100
V_fixture_min= 1.060
V_fixture_max= 1.170
|time   V(typ)   V(min)   V(max)
0s        501.3mV    484.2mV    529.3mV
148ps     501.8mV    484.8mV    534.5mV
204ps     506.7mV    483.9mV    925mV
268ps     902.5mV    472.6mV    1.107V
287ps     967.1mV    526.7mV    1.122V
338ps     1.055V     842.9mV    1.149V
374ps     1.078V     955.2mV    1.16V
430ps     1.085V     1.027V     1.167V
508ps     1.097V     1.052V     1.169V
3ns       1.1V       1.06V      1.17V
[Rising Waveform]
R_fixture= 50.000
V_fixture= 0.0
V_fixture_min= 0.0
V_fixture_max= 0.0
|time   V(typ)   V(min)   V(max)
0s        2.565uV    9.321uV    595.6nV
151ps     -53.18uV   62.7uV     9.314mV
191ps     858.7uV    34.46uV    385.9mV
214ps     9.532mV    78.11uV    471.1mV
264ps     363.6mV    988.8uV    500.6mV
301ps     432.6mV    35.08mV    414.2mV
339ps     441.9mV    283.1mV    397.5mV
367ps     448.1mV    376.4mV    397.5mV
484ps     379.5mV    415.6mV    397.7mV
3ns       379.9mV    368.5mV    397.7mV
[Falling Waveform]
R_fixture= 50.000
V_fixture= 1.100
V_fixture_min= 1.060
V_fixture_max= 1.170
|time   V(typ)   V(min)   V(max)
0s        1.1V       1.06V      1.17V
157ps     1.1V       1.06V      1.17V
225ps     1.088V     1.06V      535.7mV
274ps     677.8mV    1.058V     432.4mV
316ps     473.4mV    1.039V     500.1mV
343ps     437.5mV    895.3mV    518.2mV
403ps     459.1mV    531.6mV    527.8mV
488ps     499.2mV    428.1mV    529.2mV
658ps     501.2mV    483.6mV    529.3mV
3ns       501.3mV    484.2mV    529.3mV
[Falling Waveform]
R_fixture= 50.000
V_fixture= 0.0
V_fixture_min= 0.0
V_fixture_max= 0.0
|time   V(typ)   V(min)   V(max)
0s        379.9mV    368.5mV    397.7mV
144ps     379mV      367.9mV    407.2mV
181ps     395.2mV    367.2mV    121.8mV
198ps     394.9mV    368.7mV    44.79mV
218ps     315mV      375.8mV    13.39mV
253ps     72.71mV    394.1mV    1.974mV
292ps     8.613mV    267.6mV    -5.504mV
344ps     805.8uV    51.91mV    -542.5uV
413ps     -3.4mV     2.205mV    -9.638uV
3ns       2.294uV    9.209uV    381.5nV
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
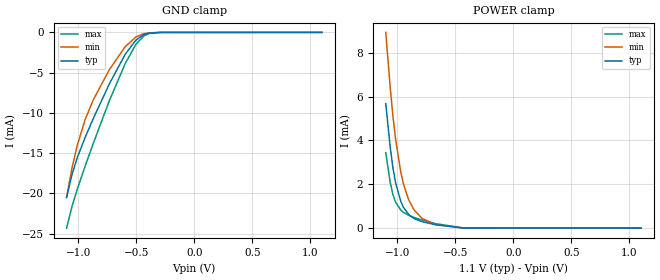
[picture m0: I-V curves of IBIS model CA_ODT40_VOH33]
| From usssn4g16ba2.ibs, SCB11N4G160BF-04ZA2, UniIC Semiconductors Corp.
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|   Model CA_ODT40_VOH33
[Model] CA_ODT40_VOH33
Model_type Input
Vinl =  93.000mV
Vinh =  0.273V
C_comp   0.710pF   0.700pF   0.720pF
[Model Spec]
Vinh   0.273V   0.267V   0.285V
Vinl   93.000mV   87.000mV   0.105V
[Add Submodel]
|  Submodel_name   Mode
ODT40_VOH33_CACLK   Non-Driving
[Temperature Range]   25.000   0.105k   -40.000
[Voltage Range]   1.100V   1.060V   1.170V
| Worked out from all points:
|   GND clamp passes 1 mA (typ) near -0.51 V on its own axis
|   POWER clamp passes 1 mA (typ) near -0.95 V on its own axis
[GND_clamp]
|Voltage   I(typ)   I(min)   I(max)
-1.1V     -20.5mA    -20.51mA   -24.31mA
-1.054V   -17.69mA   -16.89mA   -21.65mA
-1.008V   -15.57mA   -14.02mA   -19.49mA
-939mV    -13.01mA   -10.79mA   -16.57mA
-870mV    -10.71mA   -8.379mA   -13.79mA
-732mV    -6.413mA   -4.649mA   -8.508mA
-594mV    -2.707mA   -1.765mA   -3.85mA
-502mV    -951.2uA   -567uA     -1.477mA
-433mV    -266.6uA   -164.4uA   -430.6uA
-387mV    -88.17uA   -61.66uA   -135.3uA
-295mV    -6.313uA   -6.787uA   -6.983uA
1.1V      0A         0A         0A
[POWER_clamp]
|Voltage   I(typ)   I(min)   I(max)
-1.1V     5.671mA    8.923mA    3.433mA
-1.062V   3.7mA      6.421mA    2.09mA
-1.039V   2.777mA    5.138mA    1.545mA
-1.016V   2.084mA    4.076mA    1.192mA
-970mV    1.209mA    2.536mA    818.5uA
-947mV    943.5uA    2.003mA    716.7uA
-901mV    610.1uA    1.27mA     581.3uA
-855mV    430.7uA    824uA      484.6uA
-786mV    289.9uA    439.4uA    366uA
-671mV    155.9uA    155.9uA    203.6uA
-441mV    13.2uA     12.79uA    15.03uA
1.1V      0A         0A         0A
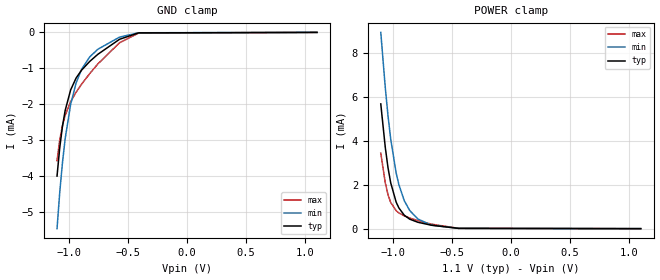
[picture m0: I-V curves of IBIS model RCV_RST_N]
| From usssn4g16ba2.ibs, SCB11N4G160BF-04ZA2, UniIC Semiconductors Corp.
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|   Model RCV_RST_N
[Model] RCV_RST_N
Model_type Input
Vinl =  0.130V
Vinh =  0.310V
C_comp   0.700pF   0.690pF   0.710pF
[Model Spec]
Vinh   0.880V   0.848V   0.936V
Vinl   0.220V   0.212V   0.234V
[Temperature Range]   25.000   0.105k   -40.000
[Voltage Range]   1.100V   1.060V   1.170V
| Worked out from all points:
|   GND clamp passes 1 mA (typ) near -0.88 V on its own axis
|   POWER clamp passes 1 mA (typ) near -0.95 V on its own axis
[GND_clamp]
|Voltage   I(typ)   I(min)   I(max)
-1.1V     -4.004mA   -5.469mA   -3.573mA
-1.077V   -3.213mA   -4.457mA   -2.999mA
-1.054V   -2.617mA   -3.629mA   -2.598mA
-1.031V   -2.175mA   -2.961mA   -2.312mA
-985mV    -1.605mA   -2.009mA   -1.932mA
-939mV    -1.274mA   -1.413mA   -1.668mA
-893mV    -1.055mA   -1.033mA   -1.447mA
-824mV    -811.3uA   -685.2uA   -1.151mA
-755mV    -611.7uA   -470.6uA   -881.6uA
-571mV    -191.9uA   -131.6uA   -288uA
-410mV    -13.76uA   -10.68uA   -20.37uA
1.1V      1.053pA    0A         -7.963pA
[POWER_clamp]
|Voltage   I(typ)   I(min)   I(max)
-1.1V     5.671mA    8.923mA    3.433mA
-1.062V   3.7mA      6.421mA    2.09mA
-1.039V   2.777mA    5.138mA    1.545mA
-1.016V   2.084mA    4.076mA    1.192mA
-970mV    1.209mA    2.536mA    818.5uA
-947mV    943.5uA    2.003mA    716.7uA
-901mV    610.1uA    1.27mA     581.3uA
-855mV    430.7uA    824uA      484.6uA
-786mV    289.9uA    439.4uA    366uA
-671mV    155.9uA    155.9uA    203.6uA
-441mV    13.2uA     12.78uA    15.03uA
1.1V      0A         0A         0A
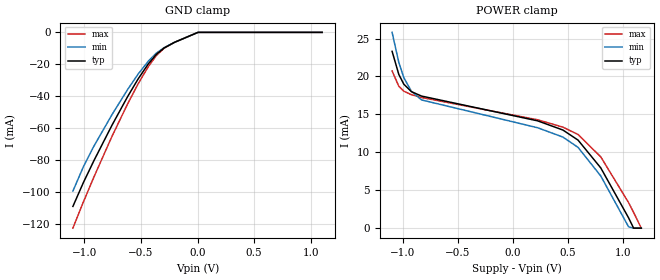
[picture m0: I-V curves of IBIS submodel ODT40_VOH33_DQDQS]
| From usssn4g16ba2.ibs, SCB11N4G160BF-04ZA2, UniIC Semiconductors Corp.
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|   Submodel ODT40_VOH33_DQDQS
[Submodel] ODT40_VOH33_DQDQS
Submodel_type Dynamic_clamp
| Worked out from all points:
|   GND clamp passes 1 mA (typ) near -0.03 V on its own axis
[GND_clamp]
|Voltage   I(typ)   I(min)   I(max)
-1.1V     -108.9mA   -99.29mA   -122.5mA
-1.008V   -94.06mA   -84.17mA   -106.2mA
-916mV    -80.48mA   -71.37mA   -90.73mA
-755mV    -58.1mA    -51.48mA   -65.05mA
-617mV    -40.2mA    -35.76mA   -44.75mA
-525mV    -29.22mA   -26.17mA   -32.31mA
-433mV    -19.58mA   -17.89mA   -21.26mA
-364mV    -13.83mA   -13.05mA   -14.56mA
-295mV    -9.767mA   -9.551mA   -9.91mA
-203mV    -6.239mA   -6.206mA   -6.231mA
4mV       0A         0A         0A
1.1V      0A         0A         0A
[POWER_clamp]
|Voltage   I(typ)   I(min)   I(max)
-1.1V     23.32mA    25.82mA    20.73mA
-1.039V   20.28mA    21.87mA    18.72mA
-993mV    18.98mA    19.84mA    18.06mA
-924mV    18mA       18.05mA    17.6mA
-832mV    17.42mA    16.91mA    17.23mA
226mV     14.15mA    13.24mA    14.29mA
456mV     12.94mA    12.01mA    13.32mA
594mV     11.61mA    10.65mA    12.35mA
801mV     7.942mA    6.878mA    9.398mA
1.054V    1.365mA    177.6uA    3.373mA
1.1V      0A         0A         2.072mA
1.17V     0A         0A         0A
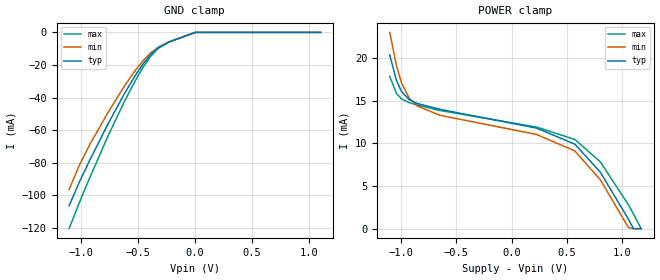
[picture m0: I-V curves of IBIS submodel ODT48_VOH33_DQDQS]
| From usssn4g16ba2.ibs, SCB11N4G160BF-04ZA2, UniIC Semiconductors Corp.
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|   Submodel ODT48_VOH33_DQDQS
[Submodel] ODT48_VOH33_DQDQS
Submodel_type Dynamic_clamp
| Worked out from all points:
|   GND clamp passes 1 mA (typ) near -0.04 V on its own axis
[GND_clamp]
|Voltage   I(typ)   I(min)   I(max)
-1.1V     -106.3mA   -96.29mA   -120.4mA
-1.008V   -91.48mA   -81.14mA   -104mA
-916mV    -77.93mA   -68.37mA   -88.62mA
-755mV    -55.56mA   -48.61mA   -62.89mA
-617mV    -37.72mA   -33.08mA   -42.52mA
-525mV    -26.86mA   -23.71mA   -30.11mA
-456mV    -19.65mA   -17.58mA   -21.75mA
-387mV    -13.67mA   -12.6mA    -14.72mA
-318mV    -9.359mA   -9.004mA   -9.653mA
-226mV    -5.885mA   -5.845mA   -5.886mA
4mV       0A         0A         0A
1.1V      0A         0A         0A
[POWER_clamp]
|Voltage   I(typ)   I(min)   I(max)
-1.1V     20.4mA     23.03mA    17.86mA
-1.039V   17.38mA    19.1mA     15.87mA
-993mV    16.09mA    17.08mA    15.22mA
-924mV    15.14mA    15.32mA    14.79mA
-855mV    14.7mA     14.42mA    14.52mA
-648mV    14.01mA    13.31mA    13.87mA
226mV     11.8mA     11.05mA    11.92mA
571mV     9.916mA    9.127mA    10.47mA
801mV     6.63mA     5.743mA    7.844mA
1.054V    1.14mA     148.3uA    2.816mA
1.1V      0A         0A         1.731mA
1.17V     0A         0A         0A
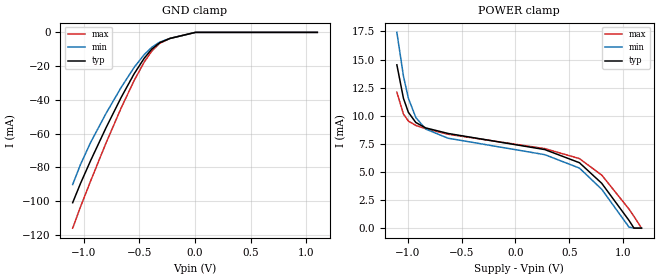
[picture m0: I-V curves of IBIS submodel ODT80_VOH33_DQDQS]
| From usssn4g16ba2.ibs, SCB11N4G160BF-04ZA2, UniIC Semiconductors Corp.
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|   Submodel ODT80_VOH33_DQDQS
[Submodel] ODT80_VOH33_DQDQS
Submodel_type Dynamic_clamp
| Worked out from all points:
|   GND clamp passes 1 mA (typ) near -0.07 V on its own axis
[GND_clamp]
|Voltage   I(typ)   I(min)   I(max)
-1.1V     -101mA     -90.25mA   -116.1mA
-1.031V   -89.78mA   -78.54mA   -103.7mA
-939mV    -76.09mA   -65.32mA   -88.18mA
-801mV    -56.68mA   -48.17mA   -65.75mA
-663mV    -38.45mA   -32.53mA   -44.67mA
-548mV    -24.64mA   -20.84mA   -28.64mA
-456mV    -15.27mA   -13.11mA   -17.54mA
-387mV    -9.839mA   -8.741mA   -10.96mA
-318mV    -6.17mA    -5.815mA   -6.492mA
-226mV    -3.608mA   -3.579mA   -3.616mA
4mV       0A         0A         0A
1.1V      0A         0A         0A
[POWER_clamp]
|Voltage   I(typ)   I(min)   I(max)
-1.1V     14.53mA    17.42mA    12.1mA
-1.039V   11.55mA    13.53mA    10.15mA
-993mV    10.3mA     11.55mA    9.527mA
-924mV    9.397mA    9.84mA     9.137mA
-832mV    8.917mA    8.811mA    8.851mA
-625mV    8.424mA    8.001mA    8.354mA
272mV     6.992mA    6.539mA    7.078mA
594mV     5.821mA    5.343mA    6.188mA
801mV     3.988mA    3.455mA    4.717mA
1.054V    686uA      89.1uA     1.695mA
1.1V      0A         0A         1.042mA
1.17V     0A         0A         0A
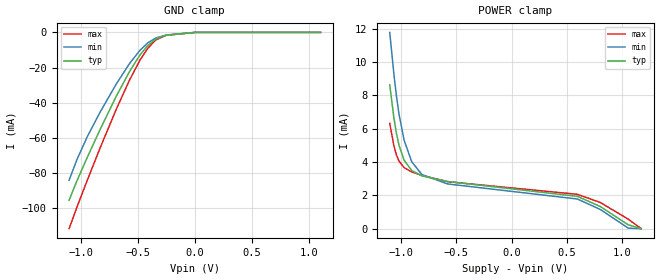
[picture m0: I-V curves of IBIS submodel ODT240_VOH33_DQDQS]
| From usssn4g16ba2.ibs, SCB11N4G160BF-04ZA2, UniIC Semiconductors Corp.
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|   Submodel ODT240_VOH33_DQDQS
[Submodel] ODT240_VOH33_DQDQS
Submodel_type Dynamic_clamp
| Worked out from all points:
|   GND clamp passes 1 mA (typ) near -0.19 V on its own axis
[GND_clamp]
|Voltage   I(typ)   I(min)   I(max)
-1.1V     -95.43mA   -84.04mA   -111.6mA
-1.031V   -84.34mA   -72.25mA   -99.29mA
-939mV    -70.75mA   -59.04mA   -83.75mA
-824mV    -54.55mA   -44.78mA   -64.96mA
-686mV    -36.15mA   -29.22mA   -43.51mA
-571mV    -22.2mA    -17.67mA   -27.07mA
-479mV    -12.76mA   -10.09mA   -15.65mA
-410mV    -7.335mA   -5.885mA   -8.889mA
-341mV    -3.721mA   -3.169mA   -4.283mA
-249mV    -1.556mA   -1.508mA   -1.597mA
4mV       0A         0A         0A
1.1V      0A         0A         0A
[POWER_clamp]
|Voltage   I(typ)   I(min)   I(max)
-1.1V     8.639mA    11.79mA    6.328mA
-1.062V   6.643mA    9.25mA     4.968mA
-1.039V   5.707mA    7.949mA    4.415mA
-1.016V   5.004mA    6.873mA    4.055mA
-970mV    4.11mA     5.309mA    3.666mA
-901mV    3.486mA    4.014mA    3.407mA
-809mV    3.169mA    3.25mA     3.2mA
-579mV    2.834mA    2.687mA    2.824mA
594mV     1.941mA    1.782mA    2.063mA
801mV     1.329mA    1.152mA    1.572mA
1.054V    228.6uA    29.42uA    564.7uA
1.17V     0A         0A         0A
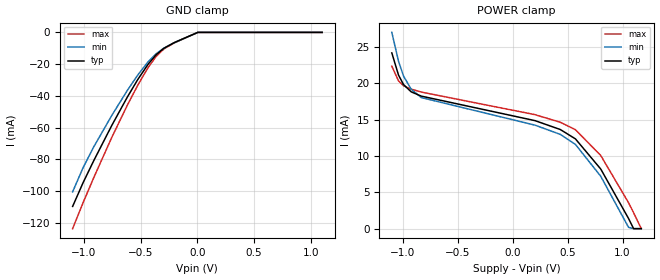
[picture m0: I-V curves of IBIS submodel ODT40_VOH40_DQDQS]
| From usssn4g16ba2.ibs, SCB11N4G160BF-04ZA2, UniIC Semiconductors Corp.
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|   Submodel ODT40_VOH40_DQDQS
[Submodel] ODT40_VOH40_DQDQS
Submodel_type Dynamic_clamp
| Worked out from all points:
|   GND clamp passes 1 mA (typ) near -0.03 V on its own axis
[GND_clamp]
|Voltage   I(typ)   I(min)   I(max)
-1.1V     -109.6mA   -100.4mA   -123.6mA
-1.008V   -94.7mA    -85.24mA   -107.3mA
-916mV    -81.1mA    -72.37mA   -91.86mA
-755mV    -58.65mA   -52.34mA   -66.17mA
-617mV    -40.67mA   -36.47mA   -45.77mA
-525mV    -29.62mA   -26.77mA   -33.2mA
-433mV    -19.92mA   -18.39mA   -21.99mA
-364mV    -14.12mA   -13.47mA   -15.18mA
-295mV    -10mA      -9.898mA   -10.42mA
-203mV    -6.404mA   -6.446mA   -6.581mA
4mV       0A         0A         0A
1.1V      0A         0A         0A
[POWER_clamp]
|Voltage   I(typ)   I(min)   I(max)
-1.1V     24.16mA    26.98mA    22.33mA
-1.039V   21.11mA    23.01mA    20.32mA
-993mV    19.8mA     20.97mA    19.64mA
-924mV    18.81mA    19.17mA    19.18mA
-832mV    18.22mA    18.02mA    18.78mA
203mV     14.85mA    14.23mA    15.67mA
433mV     13.63mA    12.96mA    14.63mA
571mV     12.34mA    11.58mA    13.6mA
801mV     8.2mA      7.206mA    10.06mA
1.054V    1.403mA    184.8uA    3.575mA
1.1V      0A         0A         2.194mA
1.17V     0A         0A         0A
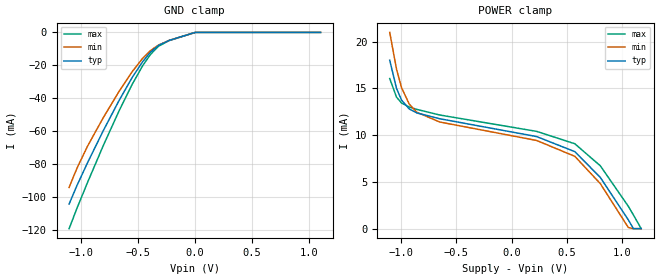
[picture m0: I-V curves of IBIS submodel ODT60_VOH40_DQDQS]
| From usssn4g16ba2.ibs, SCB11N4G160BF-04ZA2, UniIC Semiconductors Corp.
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|   Submodel ODT60_VOH40_DQDQS
[Submodel] ODT60_VOH40_DQDQS
Submodel_type Dynamic_clamp
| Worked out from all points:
|   GND clamp passes 1 mA (typ) near -0.05 V on its own axis
[GND_clamp]
|Voltage   I(typ)   I(min)   I(max)
-1.1V     -104.1mA   -94.01mA   -119mA
-1.031V   -92.81mA   -82.31mA   -106.6mA
-939mV    -79.07mA   -69.03mA   -91.04mA
-801mV    -59.61mA   -51.7mA    -68.65mA
-663mV    -41.3mA    -35.81mA   -47.59mA
-548mV    -27.33mA   -23.81mA   -31.48mA
-456mV    -17.69mA   -15.69mA   -20.16mA
-387mV    -11.96mA   -10.97mA   -13.28mA
-318mV    -7.935mA   -7.66mA    -8.44mA
-226mV    -4.87mA    -4.892mA   -5.014mA
4mV       0A         0A         0A
1.1V      0A         0A         0A
[POWER_clamp]
|Voltage   I(typ)   I(min)   I(max)
-1.1V     18.02mA    21mA       16.06mA
-1.039V   15.02mA    17.08mA    14.08mA
-993mV    13.75mA    15.08mA    13.44mA
-924mV    12.81mA    13.33mA    13.02mA
-855mV    12.38mA    12.45mA    12.76mA
-648mV    11.76mA    11.41mA    12.16mA
226mV     9.854mA    9.437mA    10.41mA
571mV     8.241mA    7.739mA    9.085mA
801mV     5.483mA    4.82mA     6.727mA
1.054V    939uA      123.5uA    2.392mA
1.1V      0A         0A         1.468mA
1.17V     0A         0A         0A
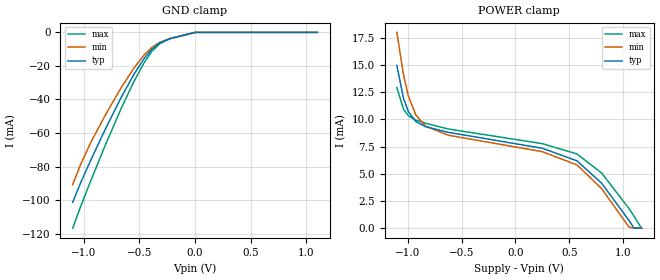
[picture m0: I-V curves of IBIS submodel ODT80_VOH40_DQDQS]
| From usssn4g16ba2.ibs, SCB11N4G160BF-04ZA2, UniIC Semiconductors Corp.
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|   Submodel ODT80_VOH40_DQDQS
[Submodel] ODT80_VOH40_DQDQS
Submodel_type Dynamic_clamp
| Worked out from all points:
|   GND clamp passes 1 mA (typ) near -0.06 V on its own axis
[GND_clamp]
|Voltage   I(typ)   I(min)   I(max)
-1.1V     -101.3mA   -90.82mA   -116.7mA
-1.031V   -90.11mA   -79.1mA    -104.3mA
-939mV    -76.41mA   -65.84mA   -88.75mA
-801mV    -56.97mA   -48.62mA   -66.32mA
-663mV    -38.7mA    -32.91mA   -45.22mA
-548mV    -24.85mA   -21.16mA   -29.11mA
-456mV    -15.45mA   -13.38mA   -17.93mA
-387mV    -9.993mA   -8.969mA   -11.29mA
-318mV    -6.298mA   -6.003mA   -6.769mA
-226mV    -3.7mA     -3.713mA   -3.813mA
4mV       0A         0A         0A
1.1V      0A         0A         0A
[POWER_clamp]
|Voltage   I(typ)   I(min)   I(max)
-1.1V     14.94mA    17.99mA    12.91mA
-1.039V   11.96mA    14.11mA    10.95mA
-993mV    10.71mA    12.12mA    10.32mA
-924mV    9.801mA    10.4mA     9.926mA
-832mV    9.315mA    9.366mA    9.631mA
-625mV    8.807mA    8.54mA     9.115mA
249mV     7.343mA    7.029mA    7.764mA
571mV     6.186mA    5.81mA     6.819mA
801mV     4.118mA    3.62mA     5.051mA
1.054V    705.4uA    92.71uA    1.797mA
1.1V      0A         0A         1.103mA
1.17V     0A         0A         0A
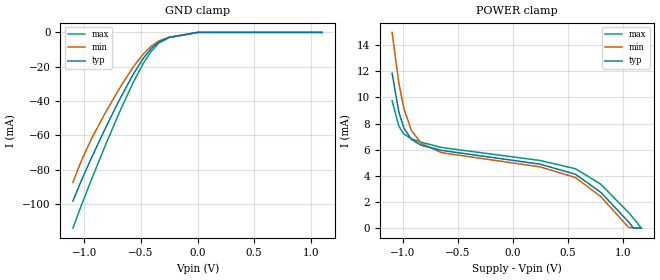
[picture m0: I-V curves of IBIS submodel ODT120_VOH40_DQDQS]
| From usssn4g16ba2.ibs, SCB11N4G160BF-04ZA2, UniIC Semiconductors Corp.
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|   Submodel ODT120_VOH40_DQDQS
[Submodel] ODT120_VOH40_DQDQS
Submodel_type Dynamic_clamp
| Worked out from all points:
|   GND clamp passes 1 mA (typ) near -0.10 V on its own axis
[GND_clamp]
|Voltage   I(typ)   I(min)   I(max)
-1.1V     -98.34mA   -87.44mA   -114.1mA
-1.031V   -87.19mA   -75.68mA   -101.8mA
-939mV    -73.55mA   -62.44mA   -86.27mA
-824mV    -57.32mA   -48.07mA   -67.5mA
-686mV    -38.87mA   -32.32mA   -46.09mA
-571mV    -24.81mA   -20.51mA   -29.64mA
-479mV    -15.16mA   -12.62mA   -18.1mA
-410mV    -9.473mA   -8.094mA   -11.11mA
-341mV    -5.528mA   -5.021mA   -6.177mA
-249mV    -2.884mA   -2.862mA   -2.997mA
4mV       0A         0A         0A
1.1V      0A         0A         0A
[POWER_clamp]
|Voltage   I(typ)   I(min)   I(max)
-1.1V     11.86mA    14.98mA    9.751mA
-1.039V   8.903mA    11.12mA    7.815mA
-993mV    7.664mA    9.154mA    7.204mA
-924mV    6.784mA    7.466mA    6.832mA
-832mV    6.334mA    6.467mA    6.569mA
-648mV    5.948mA    5.771mA    6.17mA
249mV     4.894mA    4.685mA    5.175mA
571mV     4.121mA    3.87mA     4.544mA
801mV     2.741mA    2.41mA     3.364mA
1.054V    469.4uA    61.56uA    1.196mA
1.1V      0A         0A         734uA
1.17V     0A         0A         0A
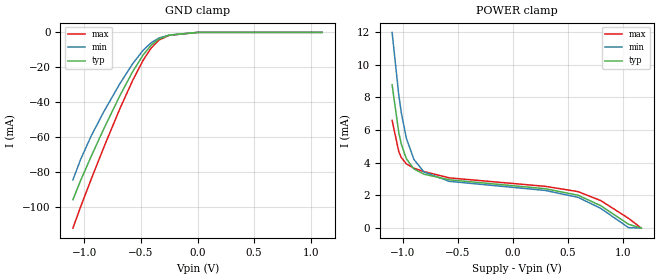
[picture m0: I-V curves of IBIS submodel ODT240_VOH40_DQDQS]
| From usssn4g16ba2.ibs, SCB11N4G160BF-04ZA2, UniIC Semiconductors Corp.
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|   Submodel ODT240_VOH40_DQDQS
[Submodel] ODT240_VOH40_DQDQS
Submodel_type Dynamic_clamp
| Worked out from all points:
|   GND clamp passes 1 mA (typ) near -0.18 V on its own axis
[GND_clamp]
|Voltage   I(typ)   I(min)   I(max)
-1.1V     -95.54mA   -84.22mA   -111.8mA
-1.031V   -84.44mA   -72.43mA   -99.48mA
-939mV    -70.85mA   -59.21mA   -83.94mA
-824mV    -54.65mA   -44.93mA   -65.15mA
-686mV    -36.23mA   -29.35mA   -43.69mA
-571mV    -22.27mA   -17.77mA   -27.23mA
-479mV    -12.82mA   -10.18mA   -15.79mA
-410mV    -7.388mA   -5.964mA   -9.005mA
-341mV    -3.766mA   -3.235mA   -4.381mA
-249mV    -1.59mA    -1.556mA   -1.67mA
4mV       0A         0A         0A
1.1V      0A         0A         0A
[POWER_clamp]
|Voltage   I(typ)   I(min)   I(max)
-1.1V     8.777mA    11.98mA    6.598mA
-1.039V   5.844mA    8.139mA    4.682mA
-1.016V   5.14mA     7.062mA    4.321mA
-970mV    4.246mA    5.497mA    3.932mA
-901mV    3.619mA    4.2mA      3.67mA
-809mV    3.301mA    3.434mA    3.46mA
-579mV    2.96mA     2.864mA    3.076mA
295mV     2.412mA    2.307mA    2.558mA
594mV     2.013mA    1.884mA    2.235mA
801mV     1.372mA    1.206mA    1.684mA
1.054V    234.9uA    30.62uA    598.8uA
1.17V     0A         0A         0A
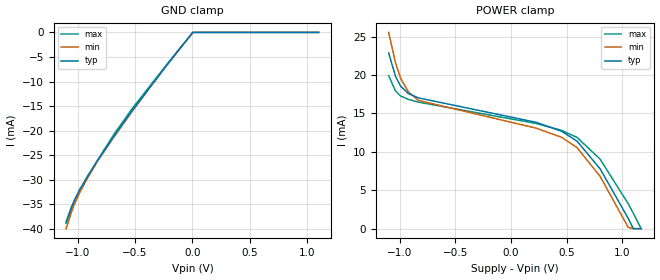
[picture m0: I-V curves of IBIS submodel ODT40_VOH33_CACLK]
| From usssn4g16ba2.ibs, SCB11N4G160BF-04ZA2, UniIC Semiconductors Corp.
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|   Submodel ODT40_VOH33_CACLK
[Submodel] ODT40_VOH33_CACLK
Submodel_type Dynamic_clamp
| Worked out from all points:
|   GND clamp passes 1 mA (typ) near -0.03 V on its own axis
[GND_clamp]
|Voltage   I(typ)   I(min)   I(max)
-1.1V     -38.52mA   -39.93mA   -38.81mA
-1.054V   -35.51mA   -36.57mA   -36.02mA
-1.031V   -34.26mA   -35.14mA   -34.83mA
-985mV    -32.1mA    -32.67mA   -32.67mA
-916mV    -29.31mA   -29.62mA   -29.68mA
-824mV    -25.93mA   -26.13mA   -25.95mA
-686mV    -21.19mA   -21.37mA   -20.82mA
-525mV    -15.92mA   -16.07mA   -15.52mA
-226mV    -6.74mA    -6.769mA   -6.605mA
4mV       0A         0A         0A
1.1V      0A         0A         0A
[POWER_clamp]
|Voltage   I(typ)   I(min)   I(max)
-1.1V     22.89mA    25.56mA    19.94mA
-1.039V   19.87mA    21.64mA    17.94mA
-993mV    18.57mA    19.61mA    17.28mA
-924mV    17.6mA     17.83mA    16.84mA
-832mV    17.03mA    16.7mA     16.48mA
226mV     13.85mA    13.09mA    13.7mA
456mV     12.68mA    11.89mA    12.8mA
594mV     11.39mA    10.55mA    11.88mA
801mV     7.798mA    6.815mA    9.054mA
1.054V    1.339mA    176.4uA    3.248mA
1.1V      0A         0A         1.996mA
1.17V     0A         0A         0A
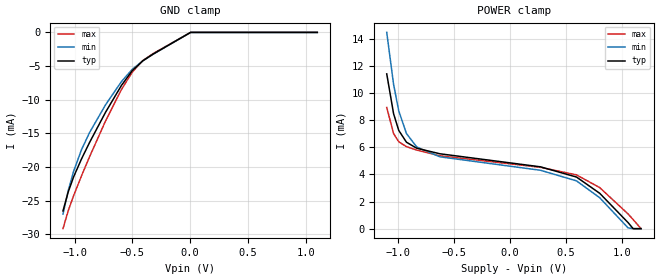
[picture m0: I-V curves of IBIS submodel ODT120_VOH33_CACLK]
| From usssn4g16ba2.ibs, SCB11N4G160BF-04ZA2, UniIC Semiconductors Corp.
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|   Submodel ODT120_VOH33_CACLK
[Submodel] ODT120_VOH33_CACLK
Submodel_type Dynamic_clamp
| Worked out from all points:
|   GND clamp passes 1 mA (typ) near -0.10 V on its own axis
[GND_clamp]
|Voltage   I(typ)   I(min)   I(max)
-1.1V     -26.53mA   -26.99mA   -29.16mA
-1.054V   -23.66mA   -23.45mA   -26.46mA
-1.008V   -21.46mA   -20.63mA   -24.25mA
-939mV    -18.77mA   -17.39mA   -21.28mA
-870mV    -16.35mA   -14.88mA   -18.47mA
-732mV    -11.87mA   -10.76mA   -13.17mA
-594mV    -7.871mA   -7.303mA   -8.485mA
-502mV    -5.715mA   -5.511mA   -5.931mA
-410mV    -4.23mA    -4.231mA   -4.183mA
-318mV    -3.197mA   -3.219mA   -3.124mA
4mV       0A         0A         0A
1.1V      0A         0A         0A
[POWER_clamp]
|Voltage   I(typ)   I(min)   I(max)
-1.1V     11.42mA    14.48mA    8.941mA
-1.039V   8.483mA    10.65mA    7.018mA
-993mV    7.251mA    8.694mA    6.413mA
-924mV    6.377mA    7.015mA    6.048mA
-832mV    5.933mA    6.023mA    5.794mA
-625mV    5.524mA    5.3mA      5.375mA
272mV     4.562mA    4.308mA    4.524mA
594mV     3.807mA    3.526mA    3.967mA
801mV     2.61mA     2.282mA    3.029mA
1.054V    448.8uA    59.12uA    1.088mA
1.1V      0A         0A         668.5uA
1.17V     0A         0A         0A
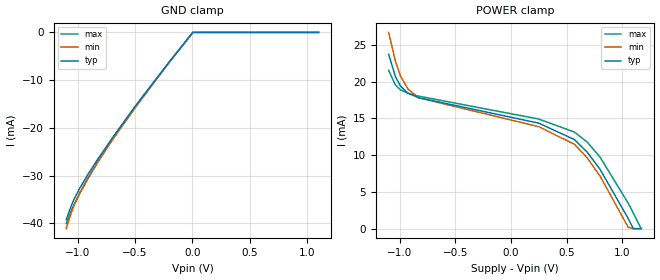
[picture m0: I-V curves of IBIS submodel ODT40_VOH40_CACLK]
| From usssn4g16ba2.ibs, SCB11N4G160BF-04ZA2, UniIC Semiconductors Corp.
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|   Submodel ODT40_VOH40_CACLK
[Submodel] ODT40_VOH40_CACLK
Submodel_type Dynamic_clamp
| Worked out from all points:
|   GND clamp passes 1 mA (typ) near -0.03 V on its own axis
[GND_clamp]
|Voltage   I(typ)   I(min)   I(max)
-1.1V     -39.27mA   -41.14mA   -40.08mA
-1.054V   -36.24mA   -37.73mA   -37.28mA
-1.031V   -34.98mA   -36.29mA   -36.09mA
-985mV    -32.8mA    -33.78mA   -33.93mA
-916mV    -29.98mA   -30.67mA   -30.93mA
-824mV    -26.56mA   -27.09mA   -27.18mA
-686mV    -21.73mA   -22.17mA   -21.99mA
-502mV    -15.59mA   -15.92mA   -15.7mA
-203mV    -6.218mA   -6.315mA   -6.297mA
4mV       0A         0A         0A
1.1V      0A         0A         0A
[POWER_clamp]
|Voltage   I(typ)   I(min)   I(max)
-1.1V     23.72mA    26.71mA    21.55mA
-1.039V   20.69mA    22.78mA    19.55mA
-993mV    19.39mA    20.75mA    18.88mA
-924mV    18.41mA    18.96mA    18.42mA
-832mV    17.83mA    17.82mA    18.04mA
249mV     14.36mA    13.88mA    14.92mA
571mV     12.12mA    11.48mA    13.14mA
686mV     10.4mA     9.627mA    11.77mA
801mV     8.061mA    7.147mA    9.734mA
1.054V    1.379mA    183.7uA    3.459mA
1.1V      0A         0A         2.122mA
1.17V     0A         0A         0A
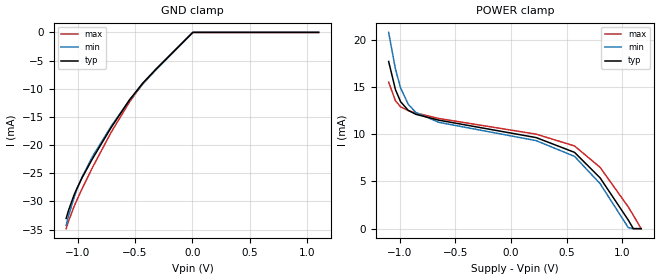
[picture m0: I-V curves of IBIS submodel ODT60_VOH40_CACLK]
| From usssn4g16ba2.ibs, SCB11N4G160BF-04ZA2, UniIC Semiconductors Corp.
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|   Submodel ODT60_VOH40_CACLK
[Submodel] ODT60_VOH40_CACLK
Submodel_type Dynamic_clamp
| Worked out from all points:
|   GND clamp passes 1 mA (typ) near -0.05 V on its own axis
[GND_clamp]
|Voltage   I(typ)   I(min)   I(max)
-1.1V     -33.02mA   -34.26mA   -34.83mA
-1.077V   -31.44mA   -32.42mA   -33.37mA
-1.031V   -28.86mA   -29.3mA    -30.91mA
-1.008V   -27.77mA   -27.98mA   -29.82mA
-962mV    -25.83mA   -25.69mA   -27.78mA
-870mV    -22.4mA    -22.01mA   -23.95mA
-709mV    -16.93mA   -16.69mA   -17.77mA
-548mV    -11.98mA   -12.01mA   -12.34mA
-433mV    -9.016mA   -9.172mA   -9.128mA
-318mV    -6.531mA   -6.654mA   -6.591mA
4mV       0A         0A         0A
1.1V      0A         0A         0A
[POWER_clamp]
|Voltage   I(typ)   I(min)   I(max)
-1.1V     17.71mA    20.79mA    15.52mA
-1.039V   14.73mA    16.91mA    13.55mA
-993mV    13.46mA    14.92mA    12.91mA
-924mV    12.53mA    13.18mA    12.5mA
-855mV    12.11mA    12.3mA     12.25mA
-648mV    11.49mA    11.26mA    11.67mA
226mV     9.647mA    9.326mA    10.01mA
571mV     8.084mA    7.658mA    8.763mA
801mV     5.38mA     4.771mA    6.497mA
1.054V    920.6uA    122.7uA    2.309mA
1.1V      0A         0A         1.417mA
1.17V     0A         0A         0A
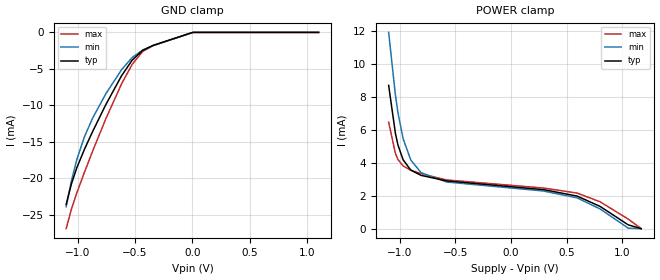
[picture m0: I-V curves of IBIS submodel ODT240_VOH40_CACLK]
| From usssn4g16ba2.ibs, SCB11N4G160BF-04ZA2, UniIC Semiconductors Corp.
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|   Submodel ODT240_VOH40_CACLK
[Submodel] ODT240_VOH40_CACLK
Submodel_type Dynamic_clamp
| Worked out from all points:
|   GND clamp passes 1 mA (typ) near -0.19 V on its own axis
[GND_clamp]
|Voltage   I(typ)   I(min)   I(max)
-1.1V     -23.63mA   -23.94mA   -26.94mA
-1.054V   -20.79mA   -20.35mA   -24.26mA
-1.008V   -18.62mA   -17.51mA   -22.07mA
-939mV    -15.99mA   -14.26mA   -19.13mA
-870mV    -13.63mA   -11.79mA   -16.33mA
-755mV    -9.935mA   -8.446mA   -11.88mA
-617mV    -5.949mA   -5.116mA   -7.058mA
-525mV    -3.819mA   -3.452mA   -4.398mA
-433mV    -2.46mA    -2.424mA   -2.61mA
-341mV    -1.778mA   -1.809mA   -1.8mA
4mV       0A         0A         0A
1.1V      0A         0A         0A
[POWER_clamp]
|Voltage   I(typ)   I(min)   I(max)
-1.1V     8.685mA    11.9mA     6.458mA
-1.039V   5.769mA    8.085mA    4.551mA
-1.016V   5.068mA    7.015mA    4.191mA
-970mV    4.175mA    5.456mA    3.802mA
-901mV    3.551mA    4.162mA    3.543mA
-809mV    3.233mA    3.397mA    3.334mA
-579mV    2.895mA    2.829mA    2.955mA
295mV     2.364mA    2.281mA    2.463mA
594mV     1.977mA    1.867mA    2.158mA
801mV     1.349mA    1.196mA    1.629mA
1.054V    230.9uA    30.78uA    579.4uA
1.17V     0A         0A         0A
